VERSION 5.8 ;
BUSBITCHARS "[]" ;
DIVIDERCHAR "/" ;
UNITS
    DATABASE MICRONS 1000 ;
END UNITS

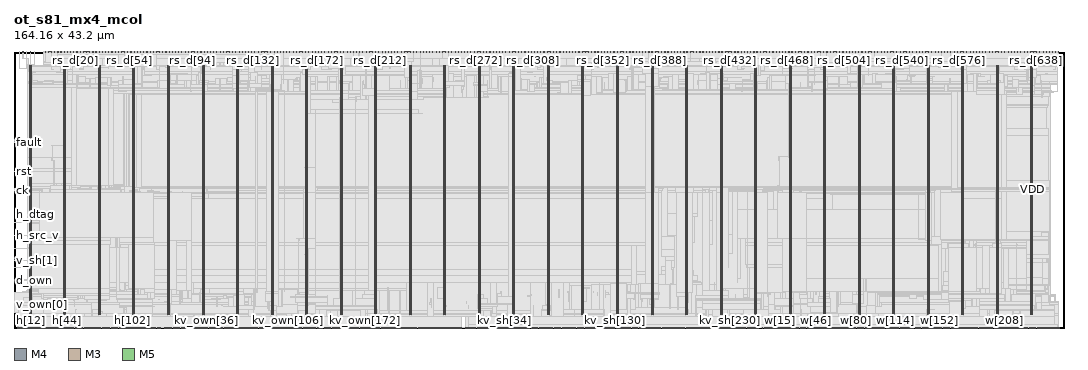
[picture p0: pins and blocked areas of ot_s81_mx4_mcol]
MACRO ot_s81_mx4_mcol
  FOREIGN ot_s81_mx4_mcol 0 0 ;
  CLASS BLOCK ;
  SIZE 164.16 BY 43.2 ;
  PIN ck
    DIRECTION INPUT ;
    USE SIGNAL ;
    PORT
      LAYER M4 ;
        RECT  0 21.504 0.084 21.528 ;
    END
  END ck
  PIN d_own
    DIRECTION INPUT ;
    USE SIGNAL ;
    PORT
      LAYER M4 ;
        RECT  0 7.488 0.084 7.512 ;
    END
  END d_own
  PIN fault
    DIRECTION OUTPUT ;
    USE SIGNAL ;
    PORT
      LAYER M4 ;
        RECT  0 28.992 0.084 29.016 ;
    END
  END fault
  PIN h[0]
    DIRECTION INPUT ;
    USE SIGNAL ;
    PORT
      LAYER M3 ;
        RECT  0.576 0 0.594 0.038 ;
    END
  END h[0]
  PIN h[100]
    DIRECTION INPUT ;
    USE SIGNAL ;
    PORT
      LAYER M3 ;
        RECT  18.144 0 18.162 0.038 ;
    END
  END h[100]
  PIN h[101]
    DIRECTION INPUT ;
    USE SIGNAL ;
    PORT
      LAYER M5 ;
        RECT  18.336 0 18.36 0.084 ;
    END
  END h[101]
  PIN h[102]
    DIRECTION INPUT ;
    USE SIGNAL ;
    PORT
      LAYER M3 ;
        RECT  18.504 0 18.522 0.038 ;
    END
  END h[102]
  PIN h[103]
    DIRECTION INPUT ;
    USE SIGNAL ;
    PORT
      LAYER M5 ;
        RECT  18.672 0 18.696 0.084 ;
    END
  END h[103]
  PIN h[104]
    DIRECTION INPUT ;
    USE SIGNAL ;
    PORT
      LAYER M3 ;
        RECT  18.864 0 18.882 0.038 ;
    END
  END h[104]
  PIN h[105]
    DIRECTION INPUT ;
    USE SIGNAL ;
    PORT
      LAYER M5 ;
        RECT  19.056 0 19.08 0.084 ;
    END
  END h[105]
  PIN h[106]
    DIRECTION INPUT ;
    USE SIGNAL ;
    PORT
      LAYER M3 ;
        RECT  19.224 0 19.242 0.038 ;
    END
  END h[106]
  PIN h[107]
    DIRECTION INPUT ;
    USE SIGNAL ;
    PORT
      LAYER M5 ;
        RECT  19.392 0 19.416 0.084 ;
    END
  END h[107]
  PIN h[108]
    DIRECTION INPUT ;
    USE SIGNAL ;
    PORT
      LAYER M3 ;
        RECT  19.548 0 19.566 0.038 ;
    END
  END h[108]
  PIN h[109]
    DIRECTION INPUT ;
    USE SIGNAL ;
    PORT
      LAYER M5 ;
        RECT  19.728 0 19.752 0.084 ;
    END
  END h[109]
  PIN h[10]
    DIRECTION INPUT ;
    USE SIGNAL ;
    PORT
      LAYER M3 ;
        RECT  2.34 0 2.358 0.038 ;
    END
  END h[10]
  PIN h[110]
    DIRECTION INPUT ;
    USE SIGNAL ;
    PORT
      LAYER M3 ;
        RECT  19.908 0 19.926 0.038 ;
    END
  END h[110]
  PIN h[111]
    DIRECTION INPUT ;
    USE SIGNAL ;
    PORT
      LAYER M5 ;
        RECT  20.112 0 20.136 0.084 ;
    END
  END h[111]
  PIN h[112]
    DIRECTION INPUT ;
    USE SIGNAL ;
    PORT
      LAYER M3 ;
        RECT  20.268 0 20.286 0.038 ;
    END
  END h[112]
  PIN h[113]
    DIRECTION INPUT ;
    USE SIGNAL ;
    PORT
      LAYER M5 ;
        RECT  20.448 0 20.472 0.084 ;
    END
  END h[113]
  PIN h[114]
    DIRECTION INPUT ;
    USE SIGNAL ;
    PORT
      LAYER M3 ;
        RECT  20.628 0 20.646 0.038 ;
    END
  END h[114]
  PIN h[115]
    DIRECTION INPUT ;
    USE SIGNAL ;
    PORT
      LAYER M5 ;
        RECT  20.784 0 20.808 0.084 ;
    END
  END h[115]
  PIN h[116]
    DIRECTION INPUT ;
    USE SIGNAL ;
    PORT
      LAYER M3 ;
        RECT  20.988 0 21.006 0.038 ;
    END
  END h[116]
  PIN h[117]
    DIRECTION INPUT ;
    USE SIGNAL ;
    PORT
      LAYER M5 ;
        RECT  21.12 0 21.144 0.084 ;
    END
  END h[117]
  PIN h[118]
    DIRECTION INPUT ;
    USE SIGNAL ;
    PORT
      LAYER M3 ;
        RECT  21.312 0 21.33 0.038 ;
    END
  END h[118]
  PIN h[119]
    DIRECTION INPUT ;
    USE SIGNAL ;
    PORT
      LAYER M5 ;
        RECT  21.504 0 21.528 0.084 ;
    END
  END h[119]
  PIN h[11]
    DIRECTION INPUT ;
    USE SIGNAL ;
    PORT
      LAYER M5 ;
        RECT  2.496 0 2.52 0.084 ;
    END
  END h[11]
  PIN h[120]
    DIRECTION INPUT ;
    USE SIGNAL ;
    PORT
      LAYER M3 ;
        RECT  21.672 0 21.69 0.038 ;
    END
  END h[120]
  PIN h[121]
    DIRECTION INPUT ;
    USE SIGNAL ;
    PORT
      LAYER M5 ;
        RECT  21.84 0 21.864 0.084 ;
    END
  END h[121]
  PIN h[122]
    DIRECTION INPUT ;
    USE SIGNAL ;
    PORT
      LAYER M3 ;
        RECT  22.032 0 22.05 0.038 ;
    END
  END h[122]
  PIN h[123]
    DIRECTION INPUT ;
    USE SIGNAL ;
    PORT
      LAYER M5 ;
        RECT  22.176 0 22.2 0.084 ;
    END
  END h[123]
  PIN h[124]
    DIRECTION INPUT ;
    USE SIGNAL ;
    PORT
      LAYER M3 ;
        RECT  22.392 0 22.41 0.038 ;
    END
  END h[124]
  PIN h[125]
    DIRECTION INPUT ;
    USE SIGNAL ;
    PORT
      LAYER M5 ;
        RECT  22.56 0 22.584 0.084 ;
    END
  END h[125]
  PIN h[126]
    DIRECTION INPUT ;
    USE SIGNAL ;
    PORT
      LAYER M3 ;
        RECT  22.716 0 22.734 0.038 ;
    END
  END h[126]
  PIN h[127]
    DIRECTION INPUT ;
    USE SIGNAL ;
    PORT
      LAYER M5 ;
        RECT  22.896 0 22.92 0.084 ;
    END
  END h[127]
  PIN h[12]
    DIRECTION INPUT ;
    USE SIGNAL ;
    PORT
      LAYER M3 ;
        RECT  2.7 0 2.718 0.038 ;
    END
  END h[12]
  PIN h[13]
    DIRECTION INPUT ;
    USE SIGNAL ;
    PORT
      LAYER M5 ;
        RECT  2.88 0 2.904 0.084 ;
    END
  END h[13]
  PIN h[14]
    DIRECTION INPUT ;
    USE SIGNAL ;
    PORT
      LAYER M3 ;
        RECT  3.024 0 3.042 0.038 ;
    END
  END h[14]
  PIN h[15]
    DIRECTION INPUT ;
    USE SIGNAL ;
    PORT
      LAYER M5 ;
        RECT  3.216 0 3.24 0.084 ;
    END
  END h[15]
  PIN h[16]
    DIRECTION INPUT ;
    USE SIGNAL ;
    PORT
      LAYER M3 ;
        RECT  3.384 0 3.402 0.038 ;
    END
  END h[16]
  PIN h[17]
    DIRECTION INPUT ;
    USE SIGNAL ;
    PORT
      LAYER M5 ;
        RECT  3.552 0 3.576 0.084 ;
    END
  END h[17]
  PIN h[18]
    DIRECTION INPUT ;
    USE SIGNAL ;
    PORT
      LAYER M3 ;
        RECT  3.744 0 3.762 0.038 ;
    END
  END h[18]
  PIN h[19]
    DIRECTION INPUT ;
    USE SIGNAL ;
    PORT
      LAYER M5 ;
        RECT  3.936 0 3.96 0.084 ;
    END
  END h[19]
  PIN h[1]
    DIRECTION INPUT ;
    USE SIGNAL ;
    PORT
      LAYER M5 ;
        RECT  0.768 0 0.792 0.084 ;
    END
  END h[1]
  PIN h[20]
    DIRECTION INPUT ;
    USE SIGNAL ;
    PORT
      LAYER M3 ;
        RECT  4.104 0 4.122 0.038 ;
    END
  END h[20]
  PIN h[21]
    DIRECTION INPUT ;
    USE SIGNAL ;
    PORT
      LAYER M5 ;
        RECT  4.272 0 4.296 0.084 ;
    END
  END h[21]
  PIN h[22]
    DIRECTION INPUT ;
    USE SIGNAL ;
    PORT
      LAYER M3 ;
        RECT  4.464 0 4.482 0.038 ;
    END
  END h[22]
  PIN h[23]
    DIRECTION INPUT ;
    USE SIGNAL ;
    PORT
      LAYER M5 ;
        RECT  4.608 0 4.632 0.084 ;
    END
  END h[23]
  PIN h[24]
    DIRECTION INPUT ;
    USE SIGNAL ;
    PORT
      LAYER M3 ;
        RECT  4.788 0 4.806 0.038 ;
    END
  END h[24]
  PIN h[25]
    DIRECTION INPUT ;
    USE SIGNAL ;
    PORT
      LAYER M5 ;
        RECT  4.992 0 5.016 0.084 ;
    END
  END h[25]
  PIN h[26]
    DIRECTION INPUT ;
    USE SIGNAL ;
    PORT
      LAYER M3 ;
        RECT  5.148 0 5.166 0.038 ;
    END
  END h[26]
  PIN h[27]
    DIRECTION INPUT ;
    USE SIGNAL ;
    PORT
      LAYER M5 ;
        RECT  5.328 0 5.352 0.084 ;
    END
  END h[27]
  PIN h[28]
    DIRECTION INPUT ;
    USE SIGNAL ;
    PORT
      LAYER M3 ;
        RECT  5.508 0 5.526 0.038 ;
    END
  END h[28]
  PIN h[29]
    DIRECTION INPUT ;
    USE SIGNAL ;
    PORT
      LAYER M5 ;
        RECT  5.664 0 5.688 0.084 ;
    END
  END h[29]
  PIN h[2]
    DIRECTION INPUT ;
    USE SIGNAL ;
    PORT
      LAYER M3 ;
        RECT  0.936 0 0.954 0.038 ;
    END
  END h[2]
  PIN h[30]
    DIRECTION INPUT ;
    USE SIGNAL ;
    PORT
      LAYER M3 ;
        RECT  5.868 0 5.886 0.038 ;
    END
  END h[30]
  PIN h[31]
    DIRECTION INPUT ;
    USE SIGNAL ;
    PORT
      LAYER M5 ;
        RECT  6.048 0 6.072 0.084 ;
    END
  END h[31]
  PIN h[32]
    DIRECTION INPUT ;
    USE SIGNAL ;
    PORT
      LAYER M3 ;
        RECT  6.192 0 6.21 0.038 ;
    END
  END h[32]
  PIN h[33]
    DIRECTION INPUT ;
    USE SIGNAL ;
    PORT
      LAYER M5 ;
        RECT  6.384 0 6.408 0.084 ;
    END
  END h[33]
  PIN h[34]
    DIRECTION INPUT ;
    USE SIGNAL ;
    PORT
      LAYER M3 ;
        RECT  6.552 0 6.57 0.038 ;
    END
  END h[34]
  PIN h[35]
    DIRECTION INPUT ;
    USE SIGNAL ;
    PORT
      LAYER M5 ;
        RECT  6.72 0 6.744 0.084 ;
    END
  END h[35]
  PIN h[36]
    DIRECTION INPUT ;
    USE SIGNAL ;
    PORT
      LAYER M3 ;
        RECT  6.912 0 6.93 0.038 ;
    END
  END h[36]
  PIN h[37]
    DIRECTION INPUT ;
    USE SIGNAL ;
    PORT
      LAYER M5 ;
        RECT  7.104 0 7.128 0.084 ;
    END
  END h[37]
  PIN h[38]
    DIRECTION INPUT ;
    USE SIGNAL ;
    PORT
      LAYER M3 ;
        RECT  7.272 0 7.29 0.038 ;
    END
  END h[38]
  PIN h[39]
    DIRECTION INPUT ;
    USE SIGNAL ;
    PORT
      LAYER M5 ;
        RECT  7.44 0 7.464 0.084 ;
    END
  END h[39]
  PIN h[3]
    DIRECTION INPUT ;
    USE SIGNAL ;
    PORT
      LAYER M5 ;
        RECT  1.104 0 1.128 0.084 ;
    END
  END h[3]
  PIN h[40]
    DIRECTION INPUT ;
    USE SIGNAL ;
    PORT
      LAYER M3 ;
        RECT  7.596 0 7.614 0.038 ;
    END
  END h[40]
  PIN h[41]
    DIRECTION INPUT ;
    USE SIGNAL ;
    PORT
      LAYER M5 ;
        RECT  7.776 0 7.8 0.084 ;
    END
  END h[41]
  PIN h[42]
    DIRECTION INPUT ;
    USE SIGNAL ;
    PORT
      LAYER M3 ;
        RECT  7.956 0 7.974 0.038 ;
    END
  END h[42]
  PIN h[43]
    DIRECTION INPUT ;
    USE SIGNAL ;
    PORT
      LAYER M5 ;
        RECT  8.112 0 8.136 0.084 ;
    END
  END h[43]
  PIN h[44]
    DIRECTION INPUT ;
    USE SIGNAL ;
    PORT
      LAYER M3 ;
        RECT  8.316 0 8.334 0.038 ;
    END
  END h[44]
  PIN h[45]
    DIRECTION INPUT ;
    USE SIGNAL ;
    PORT
      LAYER M5 ;
        RECT  8.496 0 8.52 0.084 ;
    END
  END h[45]
  PIN h[46]
    DIRECTION INPUT ;
    USE SIGNAL ;
    PORT
      LAYER M3 ;
        RECT  8.676 0 8.694 0.038 ;
    END
  END h[46]
  PIN h[47]
    DIRECTION INPUT ;
    USE SIGNAL ;
    PORT
      LAYER M5 ;
        RECT  8.832 0 8.856 0.084 ;
    END
  END h[47]
  PIN h[48]
    DIRECTION INPUT ;
    USE SIGNAL ;
    PORT
      LAYER M3 ;
        RECT  9 0 9.018 0.038 ;
    END
  END h[48]
  PIN h[49]
    DIRECTION INPUT ;
    USE SIGNAL ;
    PORT
      LAYER M5 ;
        RECT  9.168 0 9.192 0.084 ;
    END
  END h[49]
  PIN h[4]
    DIRECTION INPUT ;
    USE SIGNAL ;
    PORT
      LAYER M3 ;
        RECT  1.296 0 1.314 0.038 ;
    END
  END h[4]
  PIN h[50]
    DIRECTION INPUT ;
    USE SIGNAL ;
    PORT
      LAYER M3 ;
        RECT  9.36 0 9.378 0.038 ;
    END
  END h[50]
  PIN h[51]
    DIRECTION INPUT ;
    USE SIGNAL ;
    PORT
      LAYER M5 ;
        RECT  9.552 0 9.576 0.084 ;
    END
  END h[51]
  PIN h[52]
    DIRECTION INPUT ;
    USE SIGNAL ;
    PORT
      LAYER M3 ;
        RECT  9.72 0 9.738 0.038 ;
    END
  END h[52]
  PIN h[53]
    DIRECTION INPUT ;
    USE SIGNAL ;
    PORT
      LAYER M5 ;
        RECT  9.888 0 9.912 0.084 ;
    END
  END h[53]
  PIN h[54]
    DIRECTION INPUT ;
    USE SIGNAL ;
    PORT
      LAYER M3 ;
        RECT  10.08 0 10.098 0.038 ;
    END
  END h[54]
  PIN h[55]
    DIRECTION INPUT ;
    USE SIGNAL ;
    PORT
      LAYER M5 ;
        RECT  10.224 0 10.248 0.084 ;
    END
  END h[55]
  PIN h[56]
    DIRECTION INPUT ;
    USE SIGNAL ;
    PORT
      LAYER M3 ;
        RECT  10.44 0 10.458 0.038 ;
    END
  END h[56]
  PIN h[57]
    DIRECTION INPUT ;
    USE SIGNAL ;
    PORT
      LAYER M5 ;
        RECT  10.608 0 10.632 0.084 ;
    END
  END h[57]
  PIN h[58]
    DIRECTION INPUT ;
    USE SIGNAL ;
    PORT
      LAYER M3 ;
        RECT  10.764 0 10.782 0.038 ;
    END
  END h[58]
  PIN h[59]
    DIRECTION INPUT ;
    USE SIGNAL ;
    PORT
      LAYER M5 ;
        RECT  10.944 0 10.968 0.084 ;
    END
  END h[59]
  PIN h[5]
    DIRECTION INPUT ;
    USE SIGNAL ;
    PORT
      LAYER M5 ;
        RECT  1.44 0 1.464 0.084 ;
    END
  END h[5]
  PIN h[60]
    DIRECTION INPUT ;
    USE SIGNAL ;
    PORT
      LAYER M3 ;
        RECT  11.124 0 11.142 0.038 ;
    END
  END h[60]
  PIN h[61]
    DIRECTION INPUT ;
    USE SIGNAL ;
    PORT
      LAYER M5 ;
        RECT  11.28 0 11.304 0.084 ;
    END
  END h[61]
  PIN h[62]
    DIRECTION INPUT ;
    USE SIGNAL ;
    PORT
      LAYER M3 ;
        RECT  11.484 0 11.502 0.038 ;
    END
  END h[62]
  PIN h[63]
    DIRECTION INPUT ;
    USE SIGNAL ;
    PORT
      LAYER M5 ;
        RECT  11.664 0 11.688 0.084 ;
    END
  END h[63]
  PIN h[64]
    DIRECTION INPUT ;
    USE SIGNAL ;
    PORT
      LAYER M3 ;
        RECT  11.844 0 11.862 0.038 ;
    END
  END h[64]
  PIN h[65]
    DIRECTION INPUT ;
    USE SIGNAL ;
    PORT
      LAYER M5 ;
        RECT  12 0 12.024 0.084 ;
    END
  END h[65]
  PIN h[66]
    DIRECTION INPUT ;
    USE SIGNAL ;
    PORT
      LAYER M3 ;
        RECT  12.168 0 12.186 0.038 ;
    END
  END h[66]
  PIN h[67]
    DIRECTION INPUT ;
    USE SIGNAL ;
    PORT
      LAYER M5 ;
        RECT  12.336 0 12.36 0.084 ;
    END
  END h[67]
  PIN h[68]
    DIRECTION INPUT ;
    USE SIGNAL ;
    PORT
      LAYER M3 ;
        RECT  12.528 0 12.546 0.038 ;
    END
  END h[68]
  PIN h[69]
    DIRECTION INPUT ;
    USE SIGNAL ;
    PORT
      LAYER M5 ;
        RECT  12.72 0 12.744 0.084 ;
    END
  END h[69]
  PIN h[6]
    DIRECTION INPUT ;
    USE SIGNAL ;
    PORT
      LAYER M3 ;
        RECT  1.62 0 1.638 0.038 ;
    END
  END h[6]
  PIN h[70]
    DIRECTION INPUT ;
    USE SIGNAL ;
    PORT
      LAYER M3 ;
        RECT  12.888 0 12.906 0.038 ;
    END
  END h[70]
  PIN h[71]
    DIRECTION INPUT ;
    USE SIGNAL ;
    PORT
      LAYER M5 ;
        RECT  13.056 0 13.08 0.084 ;
    END
  END h[71]
  PIN h[72]
    DIRECTION INPUT ;
    USE SIGNAL ;
    PORT
      LAYER M3 ;
        RECT  13.248 0 13.266 0.038 ;
    END
  END h[72]
  PIN h[73]
    DIRECTION INPUT ;
    USE SIGNAL ;
    PORT
      LAYER M5 ;
        RECT  13.392 0 13.416 0.084 ;
    END
  END h[73]
  PIN h[74]
    DIRECTION INPUT ;
    USE SIGNAL ;
    PORT
      LAYER M3 ;
        RECT  13.572 0 13.59 0.038 ;
    END
  END h[74]
  PIN h[75]
    DIRECTION INPUT ;
    USE SIGNAL ;
    PORT
      LAYER M5 ;
        RECT  13.776 0 13.8 0.084 ;
    END
  END h[75]
  PIN h[76]
    DIRECTION INPUT ;
    USE SIGNAL ;
    PORT
      LAYER M3 ;
        RECT  13.932 0 13.95 0.038 ;
    END
  END h[76]
  PIN h[77]
    DIRECTION INPUT ;
    USE SIGNAL ;
    PORT
      LAYER M5 ;
        RECT  14.112 0 14.136 0.084 ;
    END
  END h[77]
  PIN h[78]
    DIRECTION INPUT ;
    USE SIGNAL ;
    PORT
      LAYER M3 ;
        RECT  14.292 0 14.31 0.038 ;
    END
  END h[78]
  PIN h[79]
    DIRECTION INPUT ;
    USE SIGNAL ;
    PORT
      LAYER M5 ;
        RECT  14.448 0 14.472 0.084 ;
    END
  END h[79]
  PIN h[7]
    DIRECTION INPUT ;
    USE SIGNAL ;
    PORT
      LAYER M5 ;
        RECT  1.824 0 1.848 0.084 ;
    END
  END h[7]
  PIN h[80]
    DIRECTION INPUT ;
    USE SIGNAL ;
    PORT
      LAYER M3 ;
        RECT  14.652 0 14.67 0.038 ;
    END
  END h[80]
  PIN h[81]
    DIRECTION INPUT ;
    USE SIGNAL ;
    PORT
      LAYER M5 ;
        RECT  14.832 0 14.856 0.084 ;
    END
  END h[81]
  PIN h[82]
    DIRECTION INPUT ;
    USE SIGNAL ;
    PORT
      LAYER M3 ;
        RECT  14.976 0 14.994 0.038 ;
    END
  END h[82]
  PIN h[83]
    DIRECTION INPUT ;
    USE SIGNAL ;
    PORT
      LAYER M5 ;
        RECT  15.168 0 15.192 0.084 ;
    END
  END h[83]
  PIN h[84]
    DIRECTION INPUT ;
    USE SIGNAL ;
    PORT
      LAYER M3 ;
        RECT  15.336 0 15.354 0.038 ;
    END
  END h[84]
  PIN h[85]
    DIRECTION INPUT ;
    USE SIGNAL ;
    PORT
      LAYER M5 ;
        RECT  15.504 0 15.528 0.084 ;
    END
  END h[85]
  PIN h[86]
    DIRECTION INPUT ;
    USE SIGNAL ;
    PORT
      LAYER M3 ;
        RECT  15.696 0 15.714 0.038 ;
    END
  END h[86]
  PIN h[87]
    DIRECTION INPUT ;
    USE SIGNAL ;
    PORT
      LAYER M5 ;
        RECT  15.888 0 15.912 0.084 ;
    END
  END h[87]
  PIN h[88]
    DIRECTION INPUT ;
    USE SIGNAL ;
    PORT
      LAYER M3 ;
        RECT  16.056 0 16.074 0.038 ;
    END
  END h[88]
  PIN h[89]
    DIRECTION INPUT ;
    USE SIGNAL ;
    PORT
      LAYER M5 ;
        RECT  16.224 0 16.248 0.084 ;
    END
  END h[89]
  PIN h[8]
    DIRECTION INPUT ;
    USE SIGNAL ;
    PORT
      LAYER M3 ;
        RECT  1.98 0 1.998 0.038 ;
    END
  END h[8]
  PIN h[90]
    DIRECTION INPUT ;
    USE SIGNAL ;
    PORT
      LAYER M3 ;
        RECT  16.416 0 16.434 0.038 ;
    END
  END h[90]
  PIN h[91]
    DIRECTION INPUT ;
    USE SIGNAL ;
    PORT
      LAYER M5 ;
        RECT  16.56 0 16.584 0.084 ;
    END
  END h[91]
  PIN h[92]
    DIRECTION INPUT ;
    USE SIGNAL ;
    PORT
      LAYER M3 ;
        RECT  16.74 0 16.758 0.038 ;
    END
  END h[92]
  PIN h[93]
    DIRECTION INPUT ;
    USE SIGNAL ;
    PORT
      LAYER M5 ;
        RECT  16.944 0 16.968 0.084 ;
    END
  END h[93]
  PIN h[94]
    DIRECTION INPUT ;
    USE SIGNAL ;
    PORT
      LAYER M3 ;
        RECT  17.1 0 17.118 0.038 ;
    END
  END h[94]
  PIN h[95]
    DIRECTION INPUT ;
    USE SIGNAL ;
    PORT
      LAYER M5 ;
        RECT  17.28 0 17.304 0.084 ;
    END
  END h[95]
  PIN h[96]
    DIRECTION INPUT ;
    USE SIGNAL ;
    PORT
      LAYER M3 ;
        RECT  17.46 0 17.478 0.038 ;
    END
  END h[96]
  PIN h[97]
    DIRECTION INPUT ;
    USE SIGNAL ;
    PORT
      LAYER M5 ;
        RECT  17.616 0 17.64 0.084 ;
    END
  END h[97]
  PIN h[98]
    DIRECTION INPUT ;
    USE SIGNAL ;
    PORT
      LAYER M3 ;
        RECT  17.82 0 17.838 0.038 ;
    END
  END h[98]
  PIN h[99]
    DIRECTION INPUT ;
    USE SIGNAL ;
    PORT
      LAYER M5 ;
        RECT  18 0 18.024 0.084 ;
    END
  END h[99]
  PIN h[9]
    DIRECTION INPUT ;
    USE SIGNAL ;
    PORT
      LAYER M5 ;
        RECT  2.16 0 2.184 0.084 ;
    END
  END h[9]
  PIN h_dtag
    DIRECTION INPUT ;
    USE SIGNAL ;
    PORT
      LAYER M4 ;
        RECT  0 16.512 0.084 16.536 ;
    END
  END h_dtag
  PIN h_src_v
    DIRECTION INPUT ;
    USE SIGNAL ;
    PORT
      LAYER M4 ;
        RECT  0 14.496 0.084 14.52 ;
    END
  END h_src_v
  PIN kv_own[0]
    DIRECTION INPUT ;
    USE SIGNAL ;
    PORT
      LAYER M3 ;
        RECT  23.58 0 23.598 0.038 ;
    END
  END kv_own[0]
  PIN kv_own[100]
    DIRECTION INPUT ;
    USE SIGNAL ;
    PORT
      LAYER M3 ;
        RECT  41.76 0 41.778 0.038 ;
    END
  END kv_own[100]
  PIN kv_own[101]
    DIRECTION INPUT ;
    USE SIGNAL ;
    PORT
      LAYER M5 ;
        RECT  41.904 0 41.928 0.084 ;
    END
  END kv_own[101]
  PIN kv_own[102]
    DIRECTION INPUT ;
    USE SIGNAL ;
    PORT
      LAYER M3 ;
        RECT  42.12 0 42.138 0.038 ;
    END
  END kv_own[102]
  PIN kv_own[103]
    DIRECTION INPUT ;
    USE SIGNAL ;
    PORT
      LAYER M5 ;
        RECT  42.288 0 42.312 0.084 ;
    END
  END kv_own[103]
  PIN kv_own[104]
    DIRECTION INPUT ;
    USE SIGNAL ;
    PORT
      LAYER M3 ;
        RECT  42.48 0 42.498 0.038 ;
    END
  END kv_own[104]
  PIN kv_own[105]
    DIRECTION INPUT ;
    USE SIGNAL ;
    PORT
      LAYER M5 ;
        RECT  42.672 0 42.696 0.084 ;
    END
  END kv_own[105]
  PIN kv_own[106]
    DIRECTION INPUT ;
    USE SIGNAL ;
    PORT
      LAYER M3 ;
        RECT  42.84 0 42.858 0.038 ;
    END
  END kv_own[106]
  PIN kv_own[107]
    DIRECTION INPUT ;
    USE SIGNAL ;
    PORT
      LAYER M5 ;
        RECT  43.008 0 43.032 0.084 ;
    END
  END kv_own[107]
  PIN kv_own[108]
    DIRECTION INPUT ;
    USE SIGNAL ;
    PORT
      LAYER M3 ;
        RECT  43.2 0 43.218 0.038 ;
    END
  END kv_own[108]
  PIN kv_own[109]
    DIRECTION INPUT ;
    USE SIGNAL ;
    PORT
      LAYER M5 ;
        RECT  43.392 0 43.416 0.084 ;
    END
  END kv_own[109]
  PIN kv_own[10]
    DIRECTION INPUT ;
    USE SIGNAL ;
    PORT
      LAYER M3 ;
        RECT  25.416 0 25.434 0.038 ;
    END
  END kv_own[10]
  PIN kv_own[110]
    DIRECTION INPUT ;
    USE SIGNAL ;
    PORT
      LAYER M3 ;
        RECT  43.56 0 43.578 0.038 ;
    END
  END kv_own[110]
  PIN kv_own[111]
    DIRECTION INPUT ;
    USE SIGNAL ;
    PORT
      LAYER M5 ;
        RECT  43.728 0 43.752 0.084 ;
    END
  END kv_own[111]
  PIN kv_own[112]
    DIRECTION INPUT ;
    USE SIGNAL ;
    PORT
      LAYER M3 ;
        RECT  43.92 0 43.938 0.038 ;
    END
  END kv_own[112]
  PIN kv_own[113]
    DIRECTION INPUT ;
    USE SIGNAL ;
    PORT
      LAYER M5 ;
        RECT  44.112 0 44.136 0.084 ;
    END
  END kv_own[113]
  PIN kv_own[114]
    DIRECTION INPUT ;
    USE SIGNAL ;
    PORT
      LAYER M3 ;
        RECT  44.28 0 44.298 0.038 ;
    END
  END kv_own[114]
  PIN kv_own[115]
    DIRECTION INPUT ;
    USE SIGNAL ;
    PORT
      LAYER M5 ;
        RECT  44.448 0 44.472 0.084 ;
    END
  END kv_own[115]
  PIN kv_own[116]
    DIRECTION INPUT ;
    USE SIGNAL ;
    PORT
      LAYER M3 ;
        RECT  44.64 0 44.658 0.038 ;
    END
  END kv_own[116]
  PIN kv_own[117]
    DIRECTION INPUT ;
    USE SIGNAL ;
    PORT
      LAYER M5 ;
        RECT  44.832 0 44.856 0.084 ;
    END
  END kv_own[117]
  PIN kv_own[118]
    DIRECTION INPUT ;
    USE SIGNAL ;
    PORT
      LAYER M3 ;
        RECT  45 0 45.018 0.038 ;
    END
  END kv_own[118]
  PIN kv_own[119]
    DIRECTION INPUT ;
    USE SIGNAL ;
    PORT
      LAYER M5 ;
        RECT  45.216 0 45.24 0.084 ;
    END
  END kv_own[119]
  PIN kv_own[11]
    DIRECTION INPUT ;
    USE SIGNAL ;
    PORT
      LAYER M5 ;
        RECT  25.584 0 25.608 0.084 ;
    END
  END kv_own[11]
  PIN kv_own[120]
    DIRECTION INPUT ;
    USE SIGNAL ;
    PORT
      LAYER M3 ;
        RECT  45.396 0 45.414 0.038 ;
    END
  END kv_own[120]
  PIN kv_own[121]
    DIRECTION INPUT ;
    USE SIGNAL ;
    PORT
      LAYER M5 ;
        RECT  45.552 0 45.576 0.084 ;
    END
  END kv_own[121]
  PIN kv_own[122]
    DIRECTION INPUT ;
    USE SIGNAL ;
    PORT
      LAYER M3 ;
        RECT  45.756 0 45.774 0.038 ;
    END
  END kv_own[122]
  PIN kv_own[123]
    DIRECTION INPUT ;
    USE SIGNAL ;
    PORT
      LAYER M5 ;
        RECT  45.936 0 45.96 0.084 ;
    END
  END kv_own[123]
  PIN kv_own[124]
    DIRECTION INPUT ;
    USE SIGNAL ;
    PORT
      LAYER M3 ;
        RECT  46.116 0 46.134 0.038 ;
    END
  END kv_own[124]
  PIN kv_own[125]
    DIRECTION INPUT ;
    USE SIGNAL ;
    PORT
      LAYER M5 ;
        RECT  46.272 0 46.296 0.084 ;
    END
  END kv_own[125]
  PIN kv_own[126]
    DIRECTION INPUT ;
    USE SIGNAL ;
    PORT
      LAYER M3 ;
        RECT  46.476 0 46.494 0.038 ;
    END
  END kv_own[126]
  PIN kv_own[127]
    DIRECTION INPUT ;
    USE SIGNAL ;
    PORT
      LAYER M5 ;
        RECT  46.656 0 46.68 0.084 ;
    END
  END kv_own[127]
  PIN kv_own[128]
    DIRECTION INPUT ;
    USE SIGNAL ;
    PORT
      LAYER M3 ;
        RECT  46.836 0 46.854 0.038 ;
    END
  END kv_own[128]
  PIN kv_own[129]
    DIRECTION INPUT ;
    USE SIGNAL ;
    PORT
      LAYER M5 ;
        RECT  46.992 0 47.016 0.084 ;
    END
  END kv_own[129]
  PIN kv_own[12]
    DIRECTION INPUT ;
    USE SIGNAL ;
    PORT
      LAYER M3 ;
        RECT  25.776 0 25.794 0.038 ;
    END
  END kv_own[12]
  PIN kv_own[130]
    DIRECTION INPUT ;
    USE SIGNAL ;
    PORT
      LAYER M3 ;
        RECT  47.196 0 47.214 0.038 ;
    END
  END kv_own[130]
  PIN kv_own[131]
    DIRECTION INPUT ;
    USE SIGNAL ;
    PORT
      LAYER M5 ;
        RECT  47.376 0 47.4 0.084 ;
    END
  END kv_own[131]
  PIN kv_own[132]
    DIRECTION INPUT ;
    USE SIGNAL ;
    PORT
      LAYER M3 ;
        RECT  47.556 0 47.574 0.038 ;
    END
  END kv_own[132]
  PIN kv_own[133]
    DIRECTION INPUT ;
    USE SIGNAL ;
    PORT
      LAYER M5 ;
        RECT  47.76 0 47.784 0.084 ;
    END
  END kv_own[133]
  PIN kv_own[134]
    DIRECTION INPUT ;
    USE SIGNAL ;
    PORT
      LAYER M3 ;
        RECT  47.916 0 47.934 0.038 ;
    END
  END kv_own[134]
  PIN kv_own[135]
    DIRECTION INPUT ;
    USE SIGNAL ;
    PORT
      LAYER M5 ;
        RECT  48.096 0 48.12 0.084 ;
    END
  END kv_own[135]
  PIN kv_own[136]
    DIRECTION INPUT ;
    USE SIGNAL ;
    PORT
      LAYER M3 ;
        RECT  48.276 0 48.294 0.038 ;
    END
  END kv_own[136]
  PIN kv_own[137]
    DIRECTION INPUT ;
    USE SIGNAL ;
    PORT
      LAYER M5 ;
        RECT  48.48 0 48.504 0.084 ;
    END
  END kv_own[137]
  PIN kv_own[138]
    DIRECTION INPUT ;
    USE SIGNAL ;
    PORT
      LAYER M3 ;
        RECT  48.636 0 48.654 0.038 ;
    END
  END kv_own[138]
  PIN kv_own[139]
    DIRECTION INPUT ;
    USE SIGNAL ;
    PORT
      LAYER M5 ;
        RECT  48.816 0 48.84 0.084 ;
    END
  END kv_own[139]
  PIN kv_own[13]
    DIRECTION INPUT ;
    USE SIGNAL ;
    PORT
      LAYER M5 ;
        RECT  25.92 0 25.944 0.084 ;
    END
  END kv_own[13]
  PIN kv_own[140]
    DIRECTION INPUT ;
    USE SIGNAL ;
    PORT
      LAYER M3 ;
        RECT  48.996 0 49.014 0.038 ;
    END
  END kv_own[140]
  PIN kv_own[141]
    DIRECTION INPUT ;
    USE SIGNAL ;
    PORT
      LAYER M5 ;
        RECT  49.2 0 49.224 0.084 ;
    END
  END kv_own[141]
  PIN kv_own[142]
    DIRECTION INPUT ;
    USE SIGNAL ;
    PORT
      LAYER M3 ;
        RECT  49.392 0 49.41 0.038 ;
    END
  END kv_own[142]
  PIN kv_own[143]
    DIRECTION INPUT ;
    USE SIGNAL ;
    PORT
      LAYER M5 ;
        RECT  49.536 0 49.56 0.084 ;
    END
  END kv_own[143]
  PIN kv_own[144]
    DIRECTION INPUT ;
    USE SIGNAL ;
    PORT
      LAYER M3 ;
        RECT  49.752 0 49.77 0.038 ;
    END
  END kv_own[144]
  PIN kv_own[145]
    DIRECTION INPUT ;
    USE SIGNAL ;
    PORT
      LAYER M5 ;
        RECT  49.92 0 49.944 0.084 ;
    END
  END kv_own[145]
  PIN kv_own[146]
    DIRECTION INPUT ;
    USE SIGNAL ;
    PORT
      LAYER M3 ;
        RECT  50.112 0 50.13 0.038 ;
    END
  END kv_own[146]
  PIN kv_own[147]
    DIRECTION INPUT ;
    USE SIGNAL ;
    PORT
      LAYER M5 ;
        RECT  50.304 0 50.328 0.084 ;
    END
  END kv_own[147]
  PIN kv_own[148]
    DIRECTION INPUT ;
    USE SIGNAL ;
    PORT
      LAYER M3 ;
        RECT  50.472 0 50.49 0.038 ;
    END
  END kv_own[148]
  PIN kv_own[149]
    DIRECTION INPUT ;
    USE SIGNAL ;
    PORT
      LAYER M5 ;
        RECT  50.64 0 50.664 0.084 ;
    END
  END kv_own[149]
  PIN kv_own[14]
    DIRECTION INPUT ;
    USE SIGNAL ;
    PORT
      LAYER M3 ;
        RECT  26.136 0 26.154 0.038 ;
    END
  END kv_own[14]
  PIN kv_own[150]
    DIRECTION INPUT ;
    USE SIGNAL ;
    PORT
      LAYER M3 ;
        RECT  50.832 0 50.85 0.038 ;
    END
  END kv_own[150]
  PIN kv_own[151]
    DIRECTION INPUT ;
    USE SIGNAL ;
    PORT
      LAYER M5 ;
        RECT  51.024 0 51.048 0.084 ;
    END
  END kv_own[151]
  PIN kv_own[152]
    DIRECTION INPUT ;
    USE SIGNAL ;
    PORT
      LAYER M3 ;
        RECT  51.192 0 51.21 0.038 ;
    END
  END kv_own[152]
  PIN kv_own[153]
    DIRECTION INPUT ;
    USE SIGNAL ;
    PORT
      LAYER M5 ;
        RECT  51.36 0 51.384 0.084 ;
    END
  END kv_own[153]
  PIN kv_own[154]
    DIRECTION INPUT ;
    USE SIGNAL ;
    PORT
      LAYER M3 ;
        RECT  51.552 0 51.57 0.038 ;
    END
  END kv_own[154]
  PIN kv_own[155]
    DIRECTION INPUT ;
    USE SIGNAL ;
    PORT
      LAYER M5 ;
        RECT  51.744 0 51.768 0.084 ;
    END
  END kv_own[155]
  PIN kv_own[156]
    DIRECTION INPUT ;
    USE SIGNAL ;
    PORT
      LAYER M3 ;
        RECT  51.912 0 51.93 0.038 ;
    END
  END kv_own[156]
  PIN kv_own[157]
    DIRECTION INPUT ;
    USE SIGNAL ;
    PORT
      LAYER M5 ;
        RECT  52.08 0 52.104 0.084 ;
    END
  END kv_own[157]
  PIN kv_own[158]
    DIRECTION INPUT ;
    USE SIGNAL ;
    PORT
      LAYER M3 ;
        RECT  52.272 0 52.29 0.038 ;
    END
  END kv_own[158]
  PIN kv_own[159]
    DIRECTION INPUT ;
    USE SIGNAL ;
    PORT
      LAYER M5 ;
        RECT  52.464 0 52.488 0.084 ;
    END
  END kv_own[159]
  PIN kv_own[15]
    DIRECTION INPUT ;
    USE SIGNAL ;
    PORT
      LAYER M5 ;
        RECT  26.304 0 26.328 0.084 ;
    END
  END kv_own[15]
  PIN kv_own[160]
    DIRECTION INPUT ;
    USE SIGNAL ;
    PORT
      LAYER M3 ;
        RECT  52.632 0 52.65 0.038 ;
    END
  END kv_own[160]
  PIN kv_own[161]
    DIRECTION INPUT ;
    USE SIGNAL ;
    PORT
      LAYER M5 ;
        RECT  52.8 0 52.824 0.084 ;
    END
  END kv_own[161]
  PIN kv_own[162]
    DIRECTION INPUT ;
    USE SIGNAL ;
    PORT
      LAYER M3 ;
        RECT  52.992 0 53.01 0.038 ;
    END
  END kv_own[162]
  PIN kv_own[163]
    DIRECTION INPUT ;
    USE SIGNAL ;
    PORT
      LAYER M5 ;
        RECT  53.184 0 53.208 0.084 ;
    END
  END kv_own[163]
  PIN kv_own[164]
    DIRECTION INPUT ;
    USE SIGNAL ;
    PORT
      LAYER M3 ;
        RECT  53.388 0 53.406 0.038 ;
    END
  END kv_own[164]
  PIN kv_own[165]
    DIRECTION INPUT ;
    USE SIGNAL ;
    PORT
      LAYER M5 ;
        RECT  53.568 0 53.592 0.084 ;
    END
  END kv_own[165]
  PIN kv_own[166]
    DIRECTION INPUT ;
    USE SIGNAL ;
    PORT
      LAYER M3 ;
        RECT  53.748 0 53.766 0.038 ;
    END
  END kv_own[166]
  PIN kv_own[167]
    DIRECTION INPUT ;
    USE SIGNAL ;
    PORT
      LAYER M5 ;
        RECT  53.904 0 53.928 0.084 ;
    END
  END kv_own[167]
  PIN kv_own[168]
    DIRECTION INPUT ;
    USE SIGNAL ;
    PORT
      LAYER M3 ;
        RECT  54.108 0 54.126 0.038 ;
    END
  END kv_own[168]
  PIN kv_own[169]
    DIRECTION INPUT ;
    USE SIGNAL ;
    PORT
      LAYER M5 ;
        RECT  54.288 0 54.312 0.084 ;
    END
  END kv_own[169]
  PIN kv_own[16]
    DIRECTION INPUT ;
    USE SIGNAL ;
    PORT
      LAYER M3 ;
        RECT  26.496 0 26.514 0.038 ;
    END
  END kv_own[16]
  PIN kv_own[170]
    DIRECTION INPUT ;
    USE SIGNAL ;
    PORT
      LAYER M3 ;
        RECT  54.468 0 54.486 0.038 ;
    END
  END kv_own[170]
  PIN kv_own[171]
    DIRECTION INPUT ;
    USE SIGNAL ;
    PORT
      LAYER M5 ;
        RECT  54.624 0 54.648 0.084 ;
    END
  END kv_own[171]
  PIN kv_own[172]
    DIRECTION INPUT ;
    USE SIGNAL ;
    PORT
      LAYER M3 ;
        RECT  54.828 0 54.846 0.038 ;
    END
  END kv_own[172]
  PIN kv_own[173]
    DIRECTION INPUT ;
    USE SIGNAL ;
    PORT
      LAYER M5 ;
        RECT  55.008 0 55.032 0.084 ;
    END
  END kv_own[173]
  PIN kv_own[174]
    DIRECTION INPUT ;
    USE SIGNAL ;
    PORT
      LAYER M3 ;
        RECT  55.188 0 55.206 0.038 ;
    END
  END kv_own[174]
  PIN kv_own[175]
    DIRECTION INPUT ;
    USE SIGNAL ;
    PORT
      LAYER M5 ;
        RECT  55.344 0 55.368 0.084 ;
    END
  END kv_own[175]
  PIN kv_own[176]
    DIRECTION INPUT ;
    USE SIGNAL ;
    PORT
      LAYER M3 ;
        RECT  55.548 0 55.566 0.038 ;
    END
  END kv_own[176]
  PIN kv_own[177]
    DIRECTION INPUT ;
    USE SIGNAL ;
    PORT
      LAYER M5 ;
        RECT  55.728 0 55.752 0.084 ;
    END
  END kv_own[177]
  PIN kv_own[178]
    DIRECTION INPUT ;
    USE SIGNAL ;
    PORT
      LAYER M3 ;
        RECT  55.908 0 55.926 0.038 ;
    END
  END kv_own[178]
  PIN kv_own[179]
    DIRECTION INPUT ;
    USE SIGNAL ;
    PORT
      LAYER M5 ;
        RECT  56.112 0 56.136 0.084 ;
    END
  END kv_own[179]
  PIN kv_own[17]
    DIRECTION INPUT ;
    USE SIGNAL ;
    PORT
      LAYER M5 ;
        RECT  26.688 0 26.712 0.084 ;
    END
  END kv_own[17]
  PIN kv_own[180]
    DIRECTION INPUT ;
    USE SIGNAL ;
    PORT
      LAYER M3 ;
        RECT  56.268 0 56.286 0.038 ;
    END
  END kv_own[180]
  PIN kv_own[181]
    DIRECTION INPUT ;
    USE SIGNAL ;
    PORT
      LAYER M5 ;
        RECT  56.448 0 56.472 0.084 ;
    END
  END kv_own[181]
  PIN kv_own[182]
    DIRECTION INPUT ;
    USE SIGNAL ;
    PORT
      LAYER M3 ;
        RECT  56.628 0 56.646 0.038 ;
    END
  END kv_own[182]
  PIN kv_own[183]
    DIRECTION INPUT ;
    USE SIGNAL ;
    PORT
      LAYER M5 ;
        RECT  56.832 0 56.856 0.084 ;
    END
  END kv_own[183]
  PIN kv_own[184]
    DIRECTION INPUT ;
    USE SIGNAL ;
    PORT
      LAYER M3 ;
        RECT  56.988 0 57.006 0.038 ;
    END
  END kv_own[184]
  PIN kv_own[185]
    DIRECTION INPUT ;
    USE SIGNAL ;
    PORT
      LAYER M5 ;
        RECT  57.168 0 57.192 0.084 ;
    END
  END kv_own[185]
  PIN kv_own[186]
    DIRECTION INPUT ;
    USE SIGNAL ;
    PORT
      LAYER M3 ;
        RECT  57.384 0 57.402 0.038 ;
    END
  END kv_own[186]
  PIN kv_own[187]
    DIRECTION INPUT ;
    USE SIGNAL ;
    PORT
      LAYER M5 ;
        RECT  57.552 0 57.576 0.084 ;
    END
  END kv_own[187]
  PIN kv_own[188]
    DIRECTION INPUT ;
    USE SIGNAL ;
    PORT
      LAYER M3 ;
        RECT  57.744 0 57.762 0.038 ;
    END
  END kv_own[188]
  PIN kv_own[189]
    DIRECTION INPUT ;
    USE SIGNAL ;
    PORT
      LAYER M5 ;
        RECT  57.888 0 57.912 0.084 ;
    END
  END kv_own[189]
  PIN kv_own[18]
    DIRECTION INPUT ;
    USE SIGNAL ;
    PORT
      LAYER M3 ;
        RECT  26.856 0 26.874 0.038 ;
    END
  END kv_own[18]
  PIN kv_own[190]
    DIRECTION INPUT ;
    USE SIGNAL ;
    PORT
      LAYER M3 ;
        RECT  58.104 0 58.122 0.038 ;
    END
  END kv_own[190]
  PIN kv_own[191]
    DIRECTION INPUT ;
    USE SIGNAL ;
    PORT
      LAYER M5 ;
        RECT  58.272 0 58.296 0.084 ;
    END
  END kv_own[191]
  PIN kv_own[192]
    DIRECTION INPUT ;
    USE SIGNAL ;
    PORT
      LAYER M3 ;
        RECT  58.464 0 58.482 0.038 ;
    END
  END kv_own[192]
  PIN kv_own[193]
    DIRECTION INPUT ;
    USE SIGNAL ;
    PORT
      LAYER M5 ;
        RECT  58.656 0 58.68 0.084 ;
    END
  END kv_own[193]
  PIN kv_own[194]
    DIRECTION INPUT ;
    USE SIGNAL ;
    PORT
      LAYER M3 ;
        RECT  58.824 0 58.842 0.038 ;
    END
  END kv_own[194]
  PIN kv_own[195]
    DIRECTION INPUT ;
    USE SIGNAL ;
    PORT
      LAYER M5 ;
        RECT  58.992 0 59.016 0.084 ;
    END
  END kv_own[195]
  PIN kv_own[196]
    DIRECTION INPUT ;
    USE SIGNAL ;
    PORT
      LAYER M3 ;
        RECT  59.184 0 59.202 0.038 ;
    END
  END kv_own[196]
  PIN kv_own[197]
    DIRECTION INPUT ;
    USE SIGNAL ;
    PORT
      LAYER M5 ;
        RECT  59.376 0 59.4 0.084 ;
    END
  END kv_own[197]
  PIN kv_own[198]
    DIRECTION INPUT ;
    USE SIGNAL ;
    PORT
      LAYER M3 ;
        RECT  59.544 0 59.562 0.038 ;
    END
  END kv_own[198]
  PIN kv_own[199]
    DIRECTION INPUT ;
    USE SIGNAL ;
    PORT
      LAYER M5 ;
        RECT  59.712 0 59.736 0.084 ;
    END
  END kv_own[199]
  PIN kv_own[19]
    DIRECTION INPUT ;
    USE SIGNAL ;
    PORT
      LAYER M5 ;
        RECT  27.024 0 27.048 0.084 ;
    END
  END kv_own[19]
  PIN kv_own[1]
    DIRECTION INPUT ;
    USE SIGNAL ;
    PORT
      LAYER M5 ;
        RECT  23.76 0 23.784 0.084 ;
    END
  END kv_own[1]
  PIN kv_own[200]
    DIRECTION INPUT ;
    USE SIGNAL ;
    PORT
      LAYER M3 ;
        RECT  59.904 0 59.922 0.038 ;
    END
  END kv_own[200]
  PIN kv_own[201]
    DIRECTION INPUT ;
    USE SIGNAL ;
    PORT
      LAYER M5 ;
        RECT  60.096 0 60.12 0.084 ;
    END
  END kv_own[201]
  PIN kv_own[202]
    DIRECTION INPUT ;
    USE SIGNAL ;
    PORT
      LAYER M3 ;
        RECT  60.264 0 60.282 0.038 ;
    END
  END kv_own[202]
  PIN kv_own[203]
    DIRECTION INPUT ;
    USE SIGNAL ;
    PORT
      LAYER M5 ;
        RECT  60.432 0 60.456 0.084 ;
    END
  END kv_own[203]
  PIN kv_own[204]
    DIRECTION INPUT ;
    USE SIGNAL ;
    PORT
      LAYER M3 ;
        RECT  60.624 0 60.642 0.038 ;
    END
  END kv_own[204]
  PIN kv_own[205]
    DIRECTION INPUT ;
    USE SIGNAL ;
    PORT
      LAYER M5 ;
        RECT  60.816 0 60.84 0.084 ;
    END
  END kv_own[205]
  PIN kv_own[206]
    DIRECTION INPUT ;
    USE SIGNAL ;
    PORT
      LAYER M3 ;
        RECT  60.984 0 61.002 0.038 ;
    END
  END kv_own[206]
  PIN kv_own[207]
    DIRECTION INPUT ;
    USE SIGNAL ;
    PORT
      LAYER M5 ;
        RECT  61.2 0 61.224 0.084 ;
    END
  END kv_own[207]
  PIN kv_own[208]
    DIRECTION INPUT ;
    USE SIGNAL ;
    PORT
      LAYER M3 ;
        RECT  61.38 0 61.398 0.038 ;
    END
  END kv_own[208]
  PIN kv_own[209]
    DIRECTION INPUT ;
    USE SIGNAL ;
    PORT
      LAYER M5 ;
        RECT  61.536 0 61.56 0.084 ;
    END
  END kv_own[209]
  PIN kv_own[20]
    DIRECTION INPUT ;
    USE SIGNAL ;
    PORT
      LAYER M3 ;
        RECT  27.216 0 27.234 0.038 ;
    END
  END kv_own[20]
  PIN kv_own[210]
    DIRECTION INPUT ;
    USE SIGNAL ;
    PORT
      LAYER M3 ;
        RECT  61.74 0 61.758 0.038 ;
    END
  END kv_own[210]
  PIN kv_own[211]
    DIRECTION INPUT ;
    USE SIGNAL ;
    PORT
      LAYER M5 ;
        RECT  61.92 0 61.944 0.084 ;
    END
  END kv_own[211]
  PIN kv_own[212]
    DIRECTION INPUT ;
    USE SIGNAL ;
    PORT
      LAYER M3 ;
        RECT  62.1 0 62.118 0.038 ;
    END
  END kv_own[212]
  PIN kv_own[213]
    DIRECTION INPUT ;
    USE SIGNAL ;
    PORT
      LAYER M5 ;
        RECT  62.256 0 62.28 0.084 ;
    END
  END kv_own[213]
  PIN kv_own[214]
    DIRECTION INPUT ;
    USE SIGNAL ;
    PORT
      LAYER M3 ;
        RECT  62.46 0 62.478 0.038 ;
    END
  END kv_own[214]
  PIN kv_own[215]
    DIRECTION INPUT ;
    USE SIGNAL ;
    PORT
      LAYER M5 ;
        RECT  62.64 0 62.664 0.084 ;
    END
  END kv_own[215]
  PIN kv_own[216]
    DIRECTION INPUT ;
    USE SIGNAL ;
    PORT
      LAYER M3 ;
        RECT  62.82 0 62.838 0.038 ;
    END
  END kv_own[216]
  PIN kv_own[217]
    DIRECTION INPUT ;
    USE SIGNAL ;
    PORT
      LAYER M5 ;
        RECT  62.976 0 63 0.084 ;
    END
  END kv_own[217]
  PIN kv_own[218]
    DIRECTION INPUT ;
    USE SIGNAL ;
    PORT
      LAYER M3 ;
        RECT  63.18 0 63.198 0.038 ;
    END
  END kv_own[218]
  PIN kv_own[219]
    DIRECTION INPUT ;
    USE SIGNAL ;
    PORT
      LAYER M5 ;
        RECT  63.36 0 63.384 0.084 ;
    END
  END kv_own[219]
  PIN kv_own[21]
    DIRECTION INPUT ;
    USE SIGNAL ;
    PORT
      LAYER M5 ;
        RECT  27.408 0 27.432 0.084 ;
    END
  END kv_own[21]
  PIN kv_own[220]
    DIRECTION INPUT ;
    USE SIGNAL ;
    PORT
      LAYER M3 ;
        RECT  63.54 0 63.558 0.038 ;
    END
  END kv_own[220]
  PIN kv_own[221]
    DIRECTION INPUT ;
    USE SIGNAL ;
    PORT
      LAYER M5 ;
        RECT  63.744 0 63.768 0.084 ;
    END
  END kv_own[221]
  PIN kv_own[222]
    DIRECTION INPUT ;
    USE SIGNAL ;
    PORT
      LAYER M3 ;
        RECT  63.9 0 63.918 0.038 ;
    END
  END kv_own[222]
  PIN kv_own[223]
    DIRECTION INPUT ;
    USE SIGNAL ;
    PORT
      LAYER M5 ;
        RECT  64.08 0 64.104 0.084 ;
    END
  END kv_own[223]
  PIN kv_own[224]
    DIRECTION INPUT ;
    USE SIGNAL ;
    PORT
      LAYER M3 ;
        RECT  64.26 0 64.278 0.038 ;
    END
  END kv_own[224]
  PIN kv_own[225]
    DIRECTION INPUT ;
    USE SIGNAL ;
    PORT
      LAYER M5 ;
        RECT  64.464 0 64.488 0.084 ;
    END
  END kv_own[225]
  PIN kv_own[226]
    DIRECTION INPUT ;
    USE SIGNAL ;
    PORT
      LAYER M3 ;
        RECT  64.62 0 64.638 0.038 ;
    END
  END kv_own[226]
  PIN kv_own[227]
    DIRECTION INPUT ;
    USE SIGNAL ;
    PORT
      LAYER M5 ;
        RECT  64.8 0 64.824 0.084 ;
    END
  END kv_own[227]
  PIN kv_own[228]
    DIRECTION INPUT ;
    USE SIGNAL ;
    PORT
      LAYER M3 ;
        RECT  64.98 0 64.998 0.038 ;
    END
  END kv_own[228]
  PIN kv_own[229]
    DIRECTION INPUT ;
    USE SIGNAL ;
    PORT
      LAYER M5 ;
        RECT  65.184 0 65.208 0.084 ;
    END
  END kv_own[229]
  PIN kv_own[22]
    DIRECTION INPUT ;
    USE SIGNAL ;
    PORT
      LAYER M3 ;
        RECT  27.576 0 27.594 0.038 ;
    END
  END kv_own[22]
  PIN kv_own[230]
    DIRECTION INPUT ;
    USE SIGNAL ;
    PORT
      LAYER M3 ;
        RECT  65.376 0 65.394 0.038 ;
    END
  END kv_own[230]
  PIN kv_own[231]
    DIRECTION INPUT ;
    USE SIGNAL ;
    PORT
      LAYER M5 ;
        RECT  65.52 0 65.544 0.084 ;
    END
  END kv_own[231]
  PIN kv_own[232]
    DIRECTION INPUT ;
    USE SIGNAL ;
    PORT
      LAYER M3 ;
        RECT  65.736 0 65.754 0.038 ;
    END
  END kv_own[232]
  PIN kv_own[233]
    DIRECTION INPUT ;
    USE SIGNAL ;
    PORT
      LAYER M5 ;
        RECT  65.904 0 65.928 0.084 ;
    END
  END kv_own[233]
  PIN kv_own[234]
    DIRECTION INPUT ;
    USE SIGNAL ;
    PORT
      LAYER M3 ;
        RECT  66.096 0 66.114 0.038 ;
    END
  END kv_own[234]
  PIN kv_own[235]
    DIRECTION INPUT ;
    USE SIGNAL ;
    PORT
      LAYER M5 ;
        RECT  66.288 0 66.312 0.084 ;
    END
  END kv_own[235]
  PIN kv_own[236]
    DIRECTION INPUT ;
    USE SIGNAL ;
    PORT
      LAYER M3 ;
        RECT  66.456 0 66.474 0.038 ;
    END
  END kv_own[236]
  PIN kv_own[237]
    DIRECTION INPUT ;
    USE SIGNAL ;
    PORT
      LAYER M5 ;
        RECT  66.624 0 66.648 0.084 ;
    END
  END kv_own[237]
  PIN kv_own[238]
    DIRECTION INPUT ;
    USE SIGNAL ;
    PORT
      LAYER M3 ;
        RECT  66.816 0 66.834 0.038 ;
    END
  END kv_own[238]
  PIN kv_own[239]
    DIRECTION INPUT ;
    USE SIGNAL ;
    PORT
      LAYER M5 ;
        RECT  67.008 0 67.032 0.084 ;
    END
  END kv_own[239]
  PIN kv_own[23]
    DIRECTION INPUT ;
    USE SIGNAL ;
    PORT
      LAYER M5 ;
        RECT  27.744 0 27.768 0.084 ;
    END
  END kv_own[23]
  PIN kv_own[240]
    DIRECTION INPUT ;
    USE SIGNAL ;
    PORT
      LAYER M3 ;
        RECT  67.176 0 67.194 0.038 ;
    END
  END kv_own[240]
  PIN kv_own[241]
    DIRECTION INPUT ;
    USE SIGNAL ;
    PORT
      LAYER M5 ;
        RECT  67.344 0 67.368 0.084 ;
    END
  END kv_own[241]
  PIN kv_own[242]
    DIRECTION INPUT ;
    USE SIGNAL ;
    PORT
      LAYER M3 ;
        RECT  67.536 0 67.554 0.038 ;
    END
  END kv_own[242]
  PIN kv_own[243]
    DIRECTION INPUT ;
    USE SIGNAL ;
    PORT
      LAYER M5 ;
        RECT  67.728 0 67.752 0.084 ;
    END
  END kv_own[243]
  PIN kv_own[244]
    DIRECTION INPUT ;
    USE SIGNAL ;
    PORT
      LAYER M3 ;
        RECT  67.896 0 67.914 0.038 ;
    END
  END kv_own[244]
  PIN kv_own[245]
    DIRECTION INPUT ;
    USE SIGNAL ;
    PORT
      LAYER M5 ;
        RECT  68.064 0 68.088 0.084 ;
    END
  END kv_own[245]
  PIN kv_own[246]
    DIRECTION INPUT ;
    USE SIGNAL ;
    PORT
      LAYER M3 ;
        RECT  68.256 0 68.274 0.038 ;
    END
  END kv_own[246]
  PIN kv_own[247]
    DIRECTION INPUT ;
    USE SIGNAL ;
    PORT
      LAYER M5 ;
        RECT  68.448 0 68.472 0.084 ;
    END
  END kv_own[247]
  PIN kv_own[248]
    DIRECTION INPUT ;
    USE SIGNAL ;
    PORT
      LAYER M3 ;
        RECT  68.616 0 68.634 0.038 ;
    END
  END kv_own[248]
  PIN kv_own[249]
    DIRECTION INPUT ;
    USE SIGNAL ;
    PORT
      LAYER M5 ;
        RECT  68.784 0 68.808 0.084 ;
    END
  END kv_own[249]
  PIN kv_own[24]
    DIRECTION INPUT ;
    USE SIGNAL ;
    PORT
      LAYER M3 ;
        RECT  27.936 0 27.954 0.038 ;
    END
  END kv_own[24]
  PIN kv_own[250]
    DIRECTION INPUT ;
    USE SIGNAL ;
    PORT
      LAYER M3 ;
        RECT  68.976 0 68.994 0.038 ;
    END
  END kv_own[250]
  PIN kv_own[251]
    DIRECTION INPUT ;
    USE SIGNAL ;
    PORT
      LAYER M5 ;
        RECT  69.168 0 69.192 0.084 ;
    END
  END kv_own[251]
  PIN kv_own[252]
    DIRECTION INPUT ;
    USE SIGNAL ;
    PORT
      LAYER M3 ;
        RECT  69.372 0 69.39 0.038 ;
    END
  END kv_own[252]
  PIN kv_own[253]
    DIRECTION INPUT ;
    USE SIGNAL ;
    PORT
      LAYER M5 ;
        RECT  69.552 0 69.576 0.084 ;
    END
  END kv_own[253]
  PIN kv_own[254]
    DIRECTION INPUT ;
    USE SIGNAL ;
    PORT
      LAYER M3 ;
        RECT  69.732 0 69.75 0.038 ;
    END
  END kv_own[254]
  PIN kv_own[255]
    DIRECTION INPUT ;
    USE SIGNAL ;
    PORT
      LAYER M5 ;
        RECT  69.888 0 69.912 0.084 ;
    END
  END kv_own[255]
  PIN kv_own[25]
    DIRECTION INPUT ;
    USE SIGNAL ;
    PORT
      LAYER M5 ;
        RECT  28.128 0 28.152 0.084 ;
    END
  END kv_own[25]
  PIN kv_own[26]
    DIRECTION INPUT ;
    USE SIGNAL ;
    PORT
      LAYER M3 ;
        RECT  28.296 0 28.314 0.038 ;
    END
  END kv_own[26]
  PIN kv_own[27]
    DIRECTION INPUT ;
    USE SIGNAL ;
    PORT
      LAYER M5 ;
        RECT  28.464 0 28.488 0.084 ;
    END
  END kv_own[27]
  PIN kv_own[28]
    DIRECTION INPUT ;
    USE SIGNAL ;
    PORT
      LAYER M3 ;
        RECT  28.656 0 28.674 0.038 ;
    END
  END kv_own[28]
  PIN kv_own[29]
    DIRECTION INPUT ;
    USE SIGNAL ;
    PORT
      LAYER M5 ;
        RECT  28.848 0 28.872 0.084 ;
    END
  END kv_own[29]
  PIN kv_own[2]
    DIRECTION INPUT ;
    USE SIGNAL ;
    PORT
      LAYER M3 ;
        RECT  23.94 0 23.958 0.038 ;
    END
  END kv_own[2]
  PIN kv_own[30]
    DIRECTION INPUT ;
    USE SIGNAL ;
    PORT
      LAYER M3 ;
        RECT  29.016 0 29.034 0.038 ;
    END
  END kv_own[30]
  PIN kv_own[31]
    DIRECTION INPUT ;
    USE SIGNAL ;
    PORT
      LAYER M5 ;
        RECT  29.232 0 29.256 0.084 ;
    END
  END kv_own[31]
  PIN kv_own[32]
    DIRECTION INPUT ;
    USE SIGNAL ;
    PORT
      LAYER M3 ;
        RECT  29.412 0 29.43 0.038 ;
    END
  END kv_own[32]
  PIN kv_own[33]
    DIRECTION INPUT ;
    USE SIGNAL ;
    PORT
      LAYER M5 ;
        RECT  29.568 0 29.592 0.084 ;
    END
  END kv_own[33]
  PIN kv_own[34]
    DIRECTION INPUT ;
    USE SIGNAL ;
    PORT
      LAYER M3 ;
        RECT  29.772 0 29.79 0.038 ;
    END
  END kv_own[34]
  PIN kv_own[35]
    DIRECTION INPUT ;
    USE SIGNAL ;
    PORT
      LAYER M5 ;
        RECT  29.952 0 29.976 0.084 ;
    END
  END kv_own[35]
  PIN kv_own[36]
    DIRECTION INPUT ;
    USE SIGNAL ;
    PORT
      LAYER M3 ;
        RECT  30.132 0 30.15 0.038 ;
    END
  END kv_own[36]
  PIN kv_own[37]
    DIRECTION INPUT ;
    USE SIGNAL ;
    PORT
      LAYER M5 ;
        RECT  30.288 0 30.312 0.084 ;
    END
  END kv_own[37]
  PIN kv_own[38]
    DIRECTION INPUT ;
    USE SIGNAL ;
    PORT
      LAYER M3 ;
        RECT  30.492 0 30.51 0.038 ;
    END
  END kv_own[38]
  PIN kv_own[39]
    DIRECTION INPUT ;
    USE SIGNAL ;
    PORT
      LAYER M5 ;
        RECT  30.672 0 30.696 0.084 ;
    END
  END kv_own[39]
  PIN kv_own[3]
    DIRECTION INPUT ;
    USE SIGNAL ;
    PORT
      LAYER M5 ;
        RECT  24.144 0 24.168 0.084 ;
    END
  END kv_own[3]
  PIN kv_own[40]
    DIRECTION INPUT ;
    USE SIGNAL ;
    PORT
      LAYER M3 ;
        RECT  30.852 0 30.87 0.038 ;
    END
  END kv_own[40]
  PIN kv_own[41]
    DIRECTION INPUT ;
    USE SIGNAL ;
    PORT
      LAYER M5 ;
        RECT  31.008 0 31.032 0.084 ;
    END
  END kv_own[41]
  PIN kv_own[42]
    DIRECTION INPUT ;
    USE SIGNAL ;
    PORT
      LAYER M3 ;
        RECT  31.212 0 31.23 0.038 ;
    END
  END kv_own[42]
  PIN kv_own[43]
    DIRECTION INPUT ;
    USE SIGNAL ;
    PORT
      LAYER M5 ;
        RECT  31.392 0 31.416 0.084 ;
    END
  END kv_own[43]
  PIN kv_own[44]
    DIRECTION INPUT ;
    USE SIGNAL ;
    PORT
      LAYER M3 ;
        RECT  31.572 0 31.59 0.038 ;
    END
  END kv_own[44]
  PIN kv_own[45]
    DIRECTION INPUT ;
    USE SIGNAL ;
    PORT
      LAYER M5 ;
        RECT  31.776 0 31.8 0.084 ;
    END
  END kv_own[45]
  PIN kv_own[46]
    DIRECTION INPUT ;
    USE SIGNAL ;
    PORT
      LAYER M3 ;
        RECT  31.932 0 31.95 0.038 ;
    END
  END kv_own[46]
  PIN kv_own[47]
    DIRECTION INPUT ;
    USE SIGNAL ;
    PORT
      LAYER M5 ;
        RECT  32.112 0 32.136 0.084 ;
    END
  END kv_own[47]
  PIN kv_own[48]
    DIRECTION INPUT ;
    USE SIGNAL ;
    PORT
      LAYER M3 ;
        RECT  32.292 0 32.31 0.038 ;
    END
  END kv_own[48]
  PIN kv_own[49]
    DIRECTION INPUT ;
    USE SIGNAL ;
    PORT
      LAYER M5 ;
        RECT  32.496 0 32.52 0.084 ;
    END
  END kv_own[49]
  PIN kv_own[4]
    DIRECTION INPUT ;
    USE SIGNAL ;
    PORT
      LAYER M3 ;
        RECT  24.3 0 24.318 0.038 ;
    END
  END kv_own[4]
  PIN kv_own[50]
    DIRECTION INPUT ;
    USE SIGNAL ;
    PORT
      LAYER M3 ;
        RECT  32.652 0 32.67 0.038 ;
    END
  END kv_own[50]
  PIN kv_own[51]
    DIRECTION INPUT ;
    USE SIGNAL ;
    PORT
      LAYER M5 ;
        RECT  32.832 0 32.856 0.084 ;
    END
  END kv_own[51]
  PIN kv_own[52]
    DIRECTION INPUT ;
    USE SIGNAL ;
    PORT
      LAYER M3 ;
        RECT  33.012 0 33.03 0.038 ;
    END
  END kv_own[52]
  PIN kv_own[53]
    DIRECTION INPUT ;
    USE SIGNAL ;
    PORT
      LAYER M5 ;
        RECT  33.216 0 33.24 0.084 ;
    END
  END kv_own[53]
  PIN kv_own[54]
    DIRECTION INPUT ;
    USE SIGNAL ;
    PORT
      LAYER M3 ;
        RECT  33.408 0 33.426 0.038 ;
    END
  END kv_own[54]
  PIN kv_own[55]
    DIRECTION INPUT ;
    USE SIGNAL ;
    PORT
      LAYER M5 ;
        RECT  33.552 0 33.576 0.084 ;
    END
  END kv_own[55]
  PIN kv_own[56]
    DIRECTION INPUT ;
    USE SIGNAL ;
    PORT
      LAYER M3 ;
        RECT  33.768 0 33.786 0.038 ;
    END
  END kv_own[56]
  PIN kv_own[57]
    DIRECTION INPUT ;
    USE SIGNAL ;
    PORT
      LAYER M5 ;
        RECT  33.936 0 33.96 0.084 ;
    END
  END kv_own[57]
  PIN kv_own[58]
    DIRECTION INPUT ;
    USE SIGNAL ;
    PORT
      LAYER M3 ;
        RECT  34.128 0 34.146 0.038 ;
    END
  END kv_own[58]
  PIN kv_own[59]
    DIRECTION INPUT ;
    USE SIGNAL ;
    PORT
      LAYER M5 ;
        RECT  34.32 0 34.344 0.084 ;
    END
  END kv_own[59]
  PIN kv_own[5]
    DIRECTION INPUT ;
    USE SIGNAL ;
    PORT
      LAYER M5 ;
        RECT  24.48 0 24.504 0.084 ;
    END
  END kv_own[5]
  PIN kv_own[60]
    DIRECTION INPUT ;
    USE SIGNAL ;
    PORT
      LAYER M3 ;
        RECT  34.488 0 34.506 0.038 ;
    END
  END kv_own[60]
  PIN kv_own[61]
    DIRECTION INPUT ;
    USE SIGNAL ;
    PORT
      LAYER M5 ;
        RECT  34.656 0 34.68 0.084 ;
    END
  END kv_own[61]
  PIN kv_own[62]
    DIRECTION INPUT ;
    USE SIGNAL ;
    PORT
      LAYER M3 ;
        RECT  34.848 0 34.866 0.038 ;
    END
  END kv_own[62]
  PIN kv_own[63]
    DIRECTION INPUT ;
    USE SIGNAL ;
    PORT
      LAYER M5 ;
        RECT  35.04 0 35.064 0.084 ;
    END
  END kv_own[63]
  PIN kv_own[64]
    DIRECTION INPUT ;
    USE SIGNAL ;
    PORT
      LAYER M3 ;
        RECT  35.208 0 35.226 0.038 ;
    END
  END kv_own[64]
  PIN kv_own[65]
    DIRECTION INPUT ;
    USE SIGNAL ;
    PORT
      LAYER M5 ;
        RECT  35.376 0 35.4 0.084 ;
    END
  END kv_own[65]
  PIN kv_own[66]
    DIRECTION INPUT ;
    USE SIGNAL ;
    PORT
      LAYER M3 ;
        RECT  35.568 0 35.586 0.038 ;
    END
  END kv_own[66]
  PIN kv_own[67]
    DIRECTION INPUT ;
    USE SIGNAL ;
    PORT
      LAYER M5 ;
        RECT  35.76 0 35.784 0.084 ;
    END
  END kv_own[67]
  PIN kv_own[68]
    DIRECTION INPUT ;
    USE SIGNAL ;
    PORT
      LAYER M3 ;
        RECT  35.928 0 35.946 0.038 ;
    END
  END kv_own[68]
  PIN kv_own[69]
    DIRECTION INPUT ;
    USE SIGNAL ;
    PORT
      LAYER M5 ;
        RECT  36.096 0 36.12 0.084 ;
    END
  END kv_own[69]
  PIN kv_own[6]
    DIRECTION INPUT ;
    USE SIGNAL ;
    PORT
      LAYER M3 ;
        RECT  24.66 0 24.678 0.038 ;
    END
  END kv_own[6]
  PIN kv_own[70]
    DIRECTION INPUT ;
    USE SIGNAL ;
    PORT
      LAYER M3 ;
        RECT  36.288 0 36.306 0.038 ;
    END
  END kv_own[70]
  PIN kv_own[71]
    DIRECTION INPUT ;
    USE SIGNAL ;
    PORT
      LAYER M5 ;
        RECT  36.48 0 36.504 0.084 ;
    END
  END kv_own[71]
  PIN kv_own[72]
    DIRECTION INPUT ;
    USE SIGNAL ;
    PORT
      LAYER M3 ;
        RECT  36.648 0 36.666 0.038 ;
    END
  END kv_own[72]
  PIN kv_own[73]
    DIRECTION INPUT ;
    USE SIGNAL ;
    PORT
      LAYER M5 ;
        RECT  36.816 0 36.84 0.084 ;
    END
  END kv_own[73]
  PIN kv_own[74]
    DIRECTION INPUT ;
    USE SIGNAL ;
    PORT
      LAYER M3 ;
        RECT  37.008 0 37.026 0.038 ;
    END
  END kv_own[74]
  PIN kv_own[75]
    DIRECTION INPUT ;
    USE SIGNAL ;
    PORT
      LAYER M5 ;
        RECT  37.2 0 37.224 0.084 ;
    END
  END kv_own[75]
  PIN kv_own[76]
    DIRECTION INPUT ;
    USE SIGNAL ;
    PORT
      LAYER M3 ;
        RECT  37.404 0 37.422 0.038 ;
    END
  END kv_own[76]
  PIN kv_own[77]
    DIRECTION INPUT ;
    USE SIGNAL ;
    PORT
      LAYER M5 ;
        RECT  37.584 0 37.608 0.084 ;
    END
  END kv_own[77]
  PIN kv_own[78]
    DIRECTION INPUT ;
    USE SIGNAL ;
    PORT
      LAYER M3 ;
        RECT  37.764 0 37.782 0.038 ;
    END
  END kv_own[78]
  PIN kv_own[79]
    DIRECTION INPUT ;
    USE SIGNAL ;
    PORT
      LAYER M5 ;
        RECT  37.92 0 37.944 0.084 ;
    END
  END kv_own[79]
  PIN kv_own[7]
    DIRECTION INPUT ;
    USE SIGNAL ;
    PORT
      LAYER M5 ;
        RECT  24.864 0 24.888 0.084 ;
    END
  END kv_own[7]
  PIN kv_own[80]
    DIRECTION INPUT ;
    USE SIGNAL ;
    PORT
      LAYER M3 ;
        RECT  38.124 0 38.142 0.038 ;
    END
  END kv_own[80]
  PIN kv_own[81]
    DIRECTION INPUT ;
    USE SIGNAL ;
    PORT
      LAYER M5 ;
        RECT  38.304 0 38.328 0.084 ;
    END
  END kv_own[81]
  PIN kv_own[82]
    DIRECTION INPUT ;
    USE SIGNAL ;
    PORT
      LAYER M3 ;
        RECT  38.484 0 38.502 0.038 ;
    END
  END kv_own[82]
  PIN kv_own[83]
    DIRECTION INPUT ;
    USE SIGNAL ;
    PORT
      LAYER M5 ;
        RECT  38.64 0 38.664 0.084 ;
    END
  END kv_own[83]
  PIN kv_own[84]
    DIRECTION INPUT ;
    USE SIGNAL ;
    PORT
      LAYER M3 ;
        RECT  38.844 0 38.862 0.038 ;
    END
  END kv_own[84]
  PIN kv_own[85]
    DIRECTION INPUT ;
    USE SIGNAL ;
    PORT
      LAYER M5 ;
        RECT  39.024 0 39.048 0.084 ;
    END
  END kv_own[85]
  PIN kv_own[86]
    DIRECTION INPUT ;
    USE SIGNAL ;
    PORT
      LAYER M3 ;
        RECT  39.204 0 39.222 0.038 ;
    END
  END kv_own[86]
  PIN kv_own[87]
    DIRECTION INPUT ;
    USE SIGNAL ;
    PORT
      LAYER M5 ;
        RECT  39.36 0 39.384 0.084 ;
    END
  END kv_own[87]
  PIN kv_own[88]
    DIRECTION INPUT ;
    USE SIGNAL ;
    PORT
      LAYER M3 ;
        RECT  39.564 0 39.582 0.038 ;
    END
  END kv_own[88]
  PIN kv_own[89]
    DIRECTION INPUT ;
    USE SIGNAL ;
    PORT
      LAYER M5 ;
        RECT  39.744 0 39.768 0.084 ;
    END
  END kv_own[89]
  PIN kv_own[8]
    DIRECTION INPUT ;
    USE SIGNAL ;
    PORT
      LAYER M3 ;
        RECT  25.02 0 25.038 0.038 ;
    END
  END kv_own[8]
  PIN kv_own[90]
    DIRECTION INPUT ;
    USE SIGNAL ;
    PORT
      LAYER M3 ;
        RECT  39.924 0 39.942 0.038 ;
    END
  END kv_own[90]
  PIN kv_own[91]
    DIRECTION INPUT ;
    USE SIGNAL ;
    PORT
      LAYER M5 ;
        RECT  40.128 0 40.152 0.084 ;
    END
  END kv_own[91]
  PIN kv_own[92]
    DIRECTION INPUT ;
    USE SIGNAL ;
    PORT
      LAYER M3 ;
        RECT  40.284 0 40.302 0.038 ;
    END
  END kv_own[92]
  PIN kv_own[93]
    DIRECTION INPUT ;
    USE SIGNAL ;
    PORT
      LAYER M5 ;
        RECT  40.464 0 40.488 0.084 ;
    END
  END kv_own[93]
  PIN kv_own[94]
    DIRECTION INPUT ;
    USE SIGNAL ;
    PORT
      LAYER M3 ;
        RECT  40.644 0 40.662 0.038 ;
    END
  END kv_own[94]
  PIN kv_own[95]
    DIRECTION INPUT ;
    USE SIGNAL ;
    PORT
      LAYER M5 ;
        RECT  40.848 0 40.872 0.084 ;
    END
  END kv_own[95]
  PIN kv_own[96]
    DIRECTION INPUT ;
    USE SIGNAL ;
    PORT
      LAYER M3 ;
        RECT  41.004 0 41.022 0.038 ;
    END
  END kv_own[96]
  PIN kv_own[97]
    DIRECTION INPUT ;
    USE SIGNAL ;
    PORT
      LAYER M5 ;
        RECT  41.184 0 41.208 0.084 ;
    END
  END kv_own[97]
  PIN kv_own[98]
    DIRECTION INPUT ;
    USE SIGNAL ;
    PORT
      LAYER M3 ;
        RECT  41.4 0 41.418 0.038 ;
    END
  END kv_own[98]
  PIN kv_own[99]
    DIRECTION INPUT ;
    USE SIGNAL ;
    PORT
      LAYER M5 ;
        RECT  41.568 0 41.592 0.084 ;
    END
  END kv_own[99]
  PIN kv_own[9]
    DIRECTION INPUT ;
    USE SIGNAL ;
    PORT
      LAYER M5 ;
        RECT  25.2 0 25.224 0.084 ;
    END
  END kv_own[9]
  PIN kv_sh[0]
    DIRECTION INPUT ;
    USE SIGNAL ;
    PORT
      LAYER M3 ;
        RECT  70.596 0 70.614 0.038 ;
    END
  END kv_sh[0]
  PIN kv_sh[100]
    DIRECTION INPUT ;
    USE SIGNAL ;
    PORT
      LAYER M3 ;
        RECT  88.56 0 88.578 0.038 ;
    END
  END kv_sh[100]
  PIN kv_sh[101]
    DIRECTION INPUT ;
    USE SIGNAL ;
    PORT
      LAYER M5 ;
        RECT  88.704 0 88.728 0.084 ;
    END
  END kv_sh[101]
  PIN kv_sh[102]
    DIRECTION INPUT ;
    USE SIGNAL ;
    PORT
      LAYER M3 ;
        RECT  88.92 0 88.938 0.038 ;
    END
  END kv_sh[102]
  PIN kv_sh[103]
    DIRECTION INPUT ;
    USE SIGNAL ;
    PORT
      LAYER M5 ;
        RECT  89.088 0 89.112 0.084 ;
    END
  END kv_sh[103]
  PIN kv_sh[104]
    DIRECTION INPUT ;
    USE SIGNAL ;
    PORT
      LAYER M3 ;
        RECT  89.28 0 89.298 0.038 ;
    END
  END kv_sh[104]
  PIN kv_sh[105]
    DIRECTION INPUT ;
    USE SIGNAL ;
    PORT
      LAYER M5 ;
        RECT  89.424 0 89.448 0.084 ;
    END
  END kv_sh[105]
  PIN kv_sh[106]
    DIRECTION INPUT ;
    USE SIGNAL ;
    PORT
      LAYER M3 ;
        RECT  89.64 0 89.658 0.038 ;
    END
  END kv_sh[106]
  PIN kv_sh[107]
    DIRECTION INPUT ;
    USE SIGNAL ;
    PORT
      LAYER M5 ;
        RECT  89.808 0 89.832 0.084 ;
    END
  END kv_sh[107]
  PIN kv_sh[108]
    DIRECTION INPUT ;
    USE SIGNAL ;
    PORT
      LAYER M3 ;
        RECT  90 0 90.018 0.038 ;
    END
  END kv_sh[108]
  PIN kv_sh[109]
    DIRECTION INPUT ;
    USE SIGNAL ;
    PORT
      LAYER M5 ;
        RECT  90.144 0 90.168 0.084 ;
    END
  END kv_sh[109]
  PIN kv_sh[10]
    DIRECTION INPUT ;
    USE SIGNAL ;
    PORT
      LAYER M3 ;
        RECT  72.396 0 72.414 0.038 ;
    END
  END kv_sh[10]
  PIN kv_sh[110]
    DIRECTION INPUT ;
    USE SIGNAL ;
    PORT
      LAYER M3 ;
        RECT  90.36 0 90.378 0.038 ;
    END
  END kv_sh[110]
  PIN kv_sh[111]
    DIRECTION INPUT ;
    USE SIGNAL ;
    PORT
      LAYER M5 ;
        RECT  90.528 0 90.552 0.084 ;
    END
  END kv_sh[111]
  PIN kv_sh[112]
    DIRECTION INPUT ;
    USE SIGNAL ;
    PORT
      LAYER M3 ;
        RECT  90.72 0 90.738 0.038 ;
    END
  END kv_sh[112]
  PIN kv_sh[113]
    DIRECTION INPUT ;
    USE SIGNAL ;
    PORT
      LAYER M5 ;
        RECT  90.864 0 90.888 0.084 ;
    END
  END kv_sh[113]
  PIN kv_sh[114]
    DIRECTION INPUT ;
    USE SIGNAL ;
    PORT
      LAYER M3 ;
        RECT  91.08 0 91.098 0.038 ;
    END
  END kv_sh[114]
  PIN kv_sh[115]
    DIRECTION INPUT ;
    USE SIGNAL ;
    PORT
      LAYER M5 ;
        RECT  91.248 0 91.272 0.084 ;
    END
  END kv_sh[115]
  PIN kv_sh[116]
    DIRECTION INPUT ;
    USE SIGNAL ;
    PORT
      LAYER M3 ;
        RECT  91.44 0 91.458 0.038 ;
    END
  END kv_sh[116]
  PIN kv_sh[117]
    DIRECTION INPUT ;
    USE SIGNAL ;
    PORT
      LAYER M5 ;
        RECT  91.584 0 91.608 0.084 ;
    END
  END kv_sh[117]
  PIN kv_sh[118]
    DIRECTION INPUT ;
    USE SIGNAL ;
    PORT
      LAYER M3 ;
        RECT  91.8 0 91.818 0.038 ;
    END
  END kv_sh[118]
  PIN kv_sh[119]
    DIRECTION INPUT ;
    USE SIGNAL ;
    PORT
      LAYER M5 ;
        RECT  91.968 0 91.992 0.084 ;
    END
  END kv_sh[119]
  PIN kv_sh[11]
    DIRECTION INPUT ;
    USE SIGNAL ;
    PORT
      LAYER M5 ;
        RECT  72.576 0 72.6 0.084 ;
    END
  END kv_sh[11]
  PIN kv_sh[120]
    DIRECTION INPUT ;
    USE SIGNAL ;
    PORT
      LAYER M3 ;
        RECT  92.16 0 92.178 0.038 ;
    END
  END kv_sh[120]
  PIN kv_sh[121]
    DIRECTION INPUT ;
    USE SIGNAL ;
    PORT
      LAYER M5 ;
        RECT  92.304 0 92.328 0.084 ;
    END
  END kv_sh[121]
  PIN kv_sh[122]
    DIRECTION INPUT ;
    USE SIGNAL ;
    PORT
      LAYER M3 ;
        RECT  92.52 0 92.538 0.038 ;
    END
  END kv_sh[122]
  PIN kv_sh[123]
    DIRECTION INPUT ;
    USE SIGNAL ;
    PORT
      LAYER M5 ;
        RECT  92.688 0 92.712 0.084 ;
    END
  END kv_sh[123]
  PIN kv_sh[124]
    DIRECTION INPUT ;
    USE SIGNAL ;
    PORT
      LAYER M3 ;
        RECT  92.88 0 92.898 0.038 ;
    END
  END kv_sh[124]
  PIN kv_sh[125]
    DIRECTION INPUT ;
    USE SIGNAL ;
    PORT
      LAYER M5 ;
        RECT  93.024 0 93.048 0.084 ;
    END
  END kv_sh[125]
  PIN kv_sh[126]
    DIRECTION INPUT ;
    USE SIGNAL ;
    PORT
      LAYER M3 ;
        RECT  93.204 0 93.222 0.038 ;
    END
  END kv_sh[126]
  PIN kv_sh[127]
    DIRECTION INPUT ;
    USE SIGNAL ;
    PORT
      LAYER M5 ;
        RECT  93.408 0 93.432 0.084 ;
    END
  END kv_sh[127]
  PIN kv_sh[128]
    DIRECTION INPUT ;
    USE SIGNAL ;
    PORT
      LAYER M3 ;
        RECT  93.564 0 93.582 0.038 ;
    END
  END kv_sh[128]
  PIN kv_sh[129]
    DIRECTION INPUT ;
    USE SIGNAL ;
    PORT
      LAYER M5 ;
        RECT  93.744 0 93.768 0.084 ;
    END
  END kv_sh[129]
  PIN kv_sh[12]
    DIRECTION INPUT ;
    USE SIGNAL ;
    PORT
      LAYER M3 ;
        RECT  72.72 0 72.738 0.038 ;
    END
  END kv_sh[12]
  PIN kv_sh[130]
    DIRECTION INPUT ;
    USE SIGNAL ;
    PORT
      LAYER M3 ;
        RECT  93.924 0 93.942 0.038 ;
    END
  END kv_sh[130]
  PIN kv_sh[131]
    DIRECTION INPUT ;
    USE SIGNAL ;
    PORT
      LAYER M5 ;
        RECT  94.128 0 94.152 0.084 ;
    END
  END kv_sh[131]
  PIN kv_sh[132]
    DIRECTION INPUT ;
    USE SIGNAL ;
    PORT
      LAYER M3 ;
        RECT  94.284 0 94.302 0.038 ;
    END
  END kv_sh[132]
  PIN kv_sh[133]
    DIRECTION INPUT ;
    USE SIGNAL ;
    PORT
      LAYER M5 ;
        RECT  94.464 0 94.488 0.084 ;
    END
  END kv_sh[133]
  PIN kv_sh[134]
    DIRECTION INPUT ;
    USE SIGNAL ;
    PORT
      LAYER M3 ;
        RECT  94.644 0 94.662 0.038 ;
    END
  END kv_sh[134]
  PIN kv_sh[135]
    DIRECTION INPUT ;
    USE SIGNAL ;
    PORT
      LAYER M5 ;
        RECT  94.848 0 94.872 0.084 ;
    END
  END kv_sh[135]
  PIN kv_sh[136]
    DIRECTION INPUT ;
    USE SIGNAL ;
    PORT
      LAYER M3 ;
        RECT  95.004 0 95.022 0.038 ;
    END
  END kv_sh[136]
  PIN kv_sh[137]
    DIRECTION INPUT ;
    USE SIGNAL ;
    PORT
      LAYER M5 ;
        RECT  95.184 0 95.208 0.084 ;
    END
  END kv_sh[137]
  PIN kv_sh[138]
    DIRECTION INPUT ;
    USE SIGNAL ;
    PORT
      LAYER M3 ;
        RECT  95.364 0 95.382 0.038 ;
    END
  END kv_sh[138]
  PIN kv_sh[139]
    DIRECTION INPUT ;
    USE SIGNAL ;
    PORT
      LAYER M5 ;
        RECT  95.568 0 95.592 0.084 ;
    END
  END kv_sh[139]
  PIN kv_sh[13]
    DIRECTION INPUT ;
    USE SIGNAL ;
    PORT
      LAYER M5 ;
        RECT  72.912 0 72.936 0.084 ;
    END
  END kv_sh[13]
  PIN kv_sh[140]
    DIRECTION INPUT ;
    USE SIGNAL ;
    PORT
      LAYER M3 ;
        RECT  95.724 0 95.742 0.038 ;
    END
  END kv_sh[140]
  PIN kv_sh[141]
    DIRECTION INPUT ;
    USE SIGNAL ;
    PORT
      LAYER M5 ;
        RECT  95.904 0 95.928 0.084 ;
    END
  END kv_sh[141]
  PIN kv_sh[142]
    DIRECTION INPUT ;
    USE SIGNAL ;
    PORT
      LAYER M3 ;
        RECT  96.084 0 96.102 0.038 ;
    END
  END kv_sh[142]
  PIN kv_sh[143]
    DIRECTION INPUT ;
    USE SIGNAL ;
    PORT
      LAYER M5 ;
        RECT  96.288 0 96.312 0.084 ;
    END
  END kv_sh[143]
  PIN kv_sh[144]
    DIRECTION INPUT ;
    USE SIGNAL ;
    PORT
      LAYER M3 ;
        RECT  96.444 0 96.462 0.038 ;
    END
  END kv_sh[144]
  PIN kv_sh[145]
    DIRECTION INPUT ;
    USE SIGNAL ;
    PORT
      LAYER M5 ;
        RECT  96.624 0 96.648 0.084 ;
    END
  END kv_sh[145]
  PIN kv_sh[146]
    DIRECTION INPUT ;
    USE SIGNAL ;
    PORT
      LAYER M3 ;
        RECT  96.804 0 96.822 0.038 ;
    END
  END kv_sh[146]
  PIN kv_sh[147]
    DIRECTION INPUT ;
    USE SIGNAL ;
    PORT
      LAYER M5 ;
        RECT  97.008 0 97.032 0.084 ;
    END
  END kv_sh[147]
  PIN kv_sh[148]
    DIRECTION INPUT ;
    USE SIGNAL ;
    PORT
      LAYER M3 ;
        RECT  97.164 0 97.182 0.038 ;
    END
  END kv_sh[148]
  PIN kv_sh[149]
    DIRECTION INPUT ;
    USE SIGNAL ;
    PORT
      LAYER M5 ;
        RECT  97.344 0 97.368 0.084 ;
    END
  END kv_sh[149]
  PIN kv_sh[14]
    DIRECTION INPUT ;
    USE SIGNAL ;
    PORT
      LAYER M3 ;
        RECT  73.08 0 73.098 0.038 ;
    END
  END kv_sh[14]
  PIN kv_sh[150]
    DIRECTION INPUT ;
    USE SIGNAL ;
    PORT
      LAYER M3 ;
        RECT  97.524 0 97.542 0.038 ;
    END
  END kv_sh[150]
  PIN kv_sh[151]
    DIRECTION INPUT ;
    USE SIGNAL ;
    PORT
      LAYER M5 ;
        RECT  97.728 0 97.752 0.084 ;
    END
  END kv_sh[151]
  PIN kv_sh[152]
    DIRECTION INPUT ;
    USE SIGNAL ;
    PORT
      LAYER M3 ;
        RECT  97.884 0 97.902 0.038 ;
    END
  END kv_sh[152]
  PIN kv_sh[153]
    DIRECTION INPUT ;
    USE SIGNAL ;
    PORT
      LAYER M5 ;
        RECT  98.064 0 98.088 0.084 ;
    END
  END kv_sh[153]
  PIN kv_sh[154]
    DIRECTION INPUT ;
    USE SIGNAL ;
    PORT
      LAYER M3 ;
        RECT  98.244 0 98.262 0.038 ;
    END
  END kv_sh[154]
  PIN kv_sh[155]
    DIRECTION INPUT ;
    USE SIGNAL ;
    PORT
      LAYER M5 ;
        RECT  98.448 0 98.472 0.084 ;
    END
  END kv_sh[155]
  PIN kv_sh[156]
    DIRECTION INPUT ;
    USE SIGNAL ;
    PORT
      LAYER M3 ;
        RECT  98.604 0 98.622 0.038 ;
    END
  END kv_sh[156]
  PIN kv_sh[157]
    DIRECTION INPUT ;
    USE SIGNAL ;
    PORT
      LAYER M5 ;
        RECT  98.784 0 98.808 0.084 ;
    END
  END kv_sh[157]
  PIN kv_sh[158]
    DIRECTION INPUT ;
    USE SIGNAL ;
    PORT
      LAYER M3 ;
        RECT  98.964 0 98.982 0.038 ;
    END
  END kv_sh[158]
  PIN kv_sh[159]
    DIRECTION INPUT ;
    USE SIGNAL ;
    PORT
      LAYER M5 ;
        RECT  99.168 0 99.192 0.084 ;
    END
  END kv_sh[159]
  PIN kv_sh[15]
    DIRECTION INPUT ;
    USE SIGNAL ;
    PORT
      LAYER M5 ;
        RECT  73.296 0 73.32 0.084 ;
    END
  END kv_sh[15]
  PIN kv_sh[160]
    DIRECTION INPUT ;
    USE SIGNAL ;
    PORT
      LAYER M3 ;
        RECT  99.324 0 99.342 0.038 ;
    END
  END kv_sh[160]
  PIN kv_sh[161]
    DIRECTION INPUT ;
    USE SIGNAL ;
    PORT
      LAYER M5 ;
        RECT  99.504 0 99.528 0.084 ;
    END
  END kv_sh[161]
  PIN kv_sh[162]
    DIRECTION INPUT ;
    USE SIGNAL ;
    PORT
      LAYER M3 ;
        RECT  99.684 0 99.702 0.038 ;
    END
  END kv_sh[162]
  PIN kv_sh[163]
    DIRECTION INPUT ;
    USE SIGNAL ;
    PORT
      LAYER M5 ;
        RECT  99.888 0 99.912 0.084 ;
    END
  END kv_sh[163]
  PIN kv_sh[164]
    DIRECTION INPUT ;
    USE SIGNAL ;
    PORT
      LAYER M3 ;
        RECT  100.044 0 100.062 0.038 ;
    END
  END kv_sh[164]
  PIN kv_sh[165]
    DIRECTION INPUT ;
    USE SIGNAL ;
    PORT
      LAYER M5 ;
        RECT  100.224 0 100.248 0.084 ;
    END
  END kv_sh[165]
  PIN kv_sh[166]
    DIRECTION INPUT ;
    USE SIGNAL ;
    PORT
      LAYER M3 ;
        RECT  100.404 0 100.422 0.038 ;
    END
  END kv_sh[166]
  PIN kv_sh[167]
    DIRECTION INPUT ;
    USE SIGNAL ;
    PORT
      LAYER M5 ;
        RECT  100.608 0 100.632 0.084 ;
    END
  END kv_sh[167]
  PIN kv_sh[168]
    DIRECTION INPUT ;
    USE SIGNAL ;
    PORT
      LAYER M3 ;
        RECT  100.764 0 100.782 0.038 ;
    END
  END kv_sh[168]
  PIN kv_sh[169]
    DIRECTION INPUT ;
    USE SIGNAL ;
    PORT
      LAYER M5 ;
        RECT  100.944 0 100.968 0.084 ;
    END
  END kv_sh[169]
  PIN kv_sh[16]
    DIRECTION INPUT ;
    USE SIGNAL ;
    PORT
      LAYER M3 ;
        RECT  73.44 0 73.458 0.038 ;
    END
  END kv_sh[16]
  PIN kv_sh[170]
    DIRECTION INPUT ;
    USE SIGNAL ;
    PORT
      LAYER M3 ;
        RECT  101.124 0 101.142 0.038 ;
    END
  END kv_sh[170]
  PIN kv_sh[171]
    DIRECTION INPUT ;
    USE SIGNAL ;
    PORT
      LAYER M5 ;
        RECT  101.328 0 101.352 0.084 ;
    END
  END kv_sh[171]
  PIN kv_sh[172]
    DIRECTION INPUT ;
    USE SIGNAL ;
    PORT
      LAYER M3 ;
        RECT  101.484 0 101.502 0.038 ;
    END
  END kv_sh[172]
  PIN kv_sh[173]
    DIRECTION INPUT ;
    USE SIGNAL ;
    PORT
      LAYER M5 ;
        RECT  101.664 0 101.688 0.084 ;
    END
  END kv_sh[173]
  PIN kv_sh[174]
    DIRECTION INPUT ;
    USE SIGNAL ;
    PORT
      LAYER M3 ;
        RECT  101.844 0 101.862 0.038 ;
    END
  END kv_sh[174]
  PIN kv_sh[175]
    DIRECTION INPUT ;
    USE SIGNAL ;
    PORT
      LAYER M5 ;
        RECT  102 0 102.024 0.084 ;
    END
  END kv_sh[175]
  PIN kv_sh[176]
    DIRECTION INPUT ;
    USE SIGNAL ;
    PORT
      LAYER M3 ;
        RECT  102.204 0 102.222 0.038 ;
    END
  END kv_sh[176]
  PIN kv_sh[177]
    DIRECTION INPUT ;
    USE SIGNAL ;
    PORT
      LAYER M5 ;
        RECT  102.384 0 102.408 0.084 ;
    END
  END kv_sh[177]
  PIN kv_sh[178]
    DIRECTION INPUT ;
    USE SIGNAL ;
    PORT
      LAYER M3 ;
        RECT  102.564 0 102.582 0.038 ;
    END
  END kv_sh[178]
  PIN kv_sh[179]
    DIRECTION INPUT ;
    USE SIGNAL ;
    PORT
      LAYER M5 ;
        RECT  102.72 0 102.744 0.084 ;
    END
  END kv_sh[179]
  PIN kv_sh[17]
    DIRECTION INPUT ;
    USE SIGNAL ;
    PORT
      LAYER M5 ;
        RECT  73.632 0 73.656 0.084 ;
    END
  END kv_sh[17]
  PIN kv_sh[180]
    DIRECTION INPUT ;
    USE SIGNAL ;
    PORT
      LAYER M3 ;
        RECT  102.924 0 102.942 0.038 ;
    END
  END kv_sh[180]
  PIN kv_sh[181]
    DIRECTION INPUT ;
    USE SIGNAL ;
    PORT
      LAYER M5 ;
        RECT  103.104 0 103.128 0.084 ;
    END
  END kv_sh[181]
  PIN kv_sh[182]
    DIRECTION INPUT ;
    USE SIGNAL ;
    PORT
      LAYER M3 ;
        RECT  103.284 0 103.302 0.038 ;
    END
  END kv_sh[182]
  PIN kv_sh[183]
    DIRECTION INPUT ;
    USE SIGNAL ;
    PORT
      LAYER M5 ;
        RECT  103.44 0 103.464 0.084 ;
    END
  END kv_sh[183]
  PIN kv_sh[184]
    DIRECTION INPUT ;
    USE SIGNAL ;
    PORT
      LAYER M3 ;
        RECT  103.644 0 103.662 0.038 ;
    END
  END kv_sh[184]
  PIN kv_sh[185]
    DIRECTION INPUT ;
    USE SIGNAL ;
    PORT
      LAYER M5 ;
        RECT  103.824 0 103.848 0.084 ;
    END
  END kv_sh[185]
  PIN kv_sh[186]
    DIRECTION INPUT ;
    USE SIGNAL ;
    PORT
      LAYER M3 ;
        RECT  104.004 0 104.022 0.038 ;
    END
  END kv_sh[186]
  PIN kv_sh[187]
    DIRECTION INPUT ;
    USE SIGNAL ;
    PORT
      LAYER M5 ;
        RECT  104.16 0 104.184 0.084 ;
    END
  END kv_sh[187]
  PIN kv_sh[188]
    DIRECTION INPUT ;
    USE SIGNAL ;
    PORT
      LAYER M3 ;
        RECT  104.364 0 104.382 0.038 ;
    END
  END kv_sh[188]
  PIN kv_sh[189]
    DIRECTION INPUT ;
    USE SIGNAL ;
    PORT
      LAYER M5 ;
        RECT  104.544 0 104.568 0.084 ;
    END
  END kv_sh[189]
  PIN kv_sh[18]
    DIRECTION INPUT ;
    USE SIGNAL ;
    PORT
      LAYER M3 ;
        RECT  73.8 0 73.818 0.038 ;
    END
  END kv_sh[18]
  PIN kv_sh[190]
    DIRECTION INPUT ;
    USE SIGNAL ;
    PORT
      LAYER M3 ;
        RECT  104.724 0 104.742 0.038 ;
    END
  END kv_sh[190]
  PIN kv_sh[191]
    DIRECTION INPUT ;
    USE SIGNAL ;
    PORT
      LAYER M5 ;
        RECT  104.88 0 104.904 0.084 ;
    END
  END kv_sh[191]
  PIN kv_sh[192]
    DIRECTION INPUT ;
    USE SIGNAL ;
    PORT
      LAYER M3 ;
        RECT  105.084 0 105.102 0.038 ;
    END
  END kv_sh[192]
  PIN kv_sh[193]
    DIRECTION INPUT ;
    USE SIGNAL ;
    PORT
      LAYER M5 ;
        RECT  105.264 0 105.288 0.084 ;
    END
  END kv_sh[193]
  PIN kv_sh[194]
    DIRECTION INPUT ;
    USE SIGNAL ;
    PORT
      LAYER M3 ;
        RECT  105.444 0 105.462 0.038 ;
    END
  END kv_sh[194]
  PIN kv_sh[195]
    DIRECTION INPUT ;
    USE SIGNAL ;
    PORT
      LAYER M5 ;
        RECT  105.6 0 105.624 0.084 ;
    END
  END kv_sh[195]
  PIN kv_sh[196]
    DIRECTION INPUT ;
    USE SIGNAL ;
    PORT
      LAYER M3 ;
        RECT  105.804 0 105.822 0.038 ;
    END
  END kv_sh[196]
  PIN kv_sh[197]
    DIRECTION INPUT ;
    USE SIGNAL ;
    PORT
      LAYER M5 ;
        RECT  105.984 0 106.008 0.084 ;
    END
  END kv_sh[197]
  PIN kv_sh[198]
    DIRECTION INPUT ;
    USE SIGNAL ;
    PORT
      LAYER M3 ;
        RECT  106.164 0 106.182 0.038 ;
    END
  END kv_sh[198]
  PIN kv_sh[199]
    DIRECTION INPUT ;
    USE SIGNAL ;
    PORT
      LAYER M5 ;
        RECT  106.32 0 106.344 0.084 ;
    END
  END kv_sh[199]
  PIN kv_sh[19]
    DIRECTION INPUT ;
    USE SIGNAL ;
    PORT
      LAYER M5 ;
        RECT  74.016 0 74.04 0.084 ;
    END
  END kv_sh[19]
  PIN kv_sh[1]
    DIRECTION INPUT ;
    USE SIGNAL ;
    PORT
      LAYER M5 ;
        RECT  70.752 0 70.776 0.084 ;
    END
  END kv_sh[1]
  PIN kv_sh[200]
    DIRECTION INPUT ;
    USE SIGNAL ;
    PORT
      LAYER M3 ;
        RECT  106.524 0 106.542 0.038 ;
    END
  END kv_sh[200]
  PIN kv_sh[201]
    DIRECTION INPUT ;
    USE SIGNAL ;
    PORT
      LAYER M5 ;
        RECT  106.704 0 106.728 0.084 ;
    END
  END kv_sh[201]
  PIN kv_sh[202]
    DIRECTION INPUT ;
    USE SIGNAL ;
    PORT
      LAYER M3 ;
        RECT  106.884 0 106.902 0.038 ;
    END
  END kv_sh[202]
  PIN kv_sh[203]
    DIRECTION INPUT ;
    USE SIGNAL ;
    PORT
      LAYER M5 ;
        RECT  107.04 0 107.064 0.084 ;
    END
  END kv_sh[203]
  PIN kv_sh[204]
    DIRECTION INPUT ;
    USE SIGNAL ;
    PORT
      LAYER M3 ;
        RECT  107.244 0 107.262 0.038 ;
    END
  END kv_sh[204]
  PIN kv_sh[205]
    DIRECTION INPUT ;
    USE SIGNAL ;
    PORT
      LAYER M5 ;
        RECT  107.424 0 107.448 0.084 ;
    END
  END kv_sh[205]
  PIN kv_sh[206]
    DIRECTION INPUT ;
    USE SIGNAL ;
    PORT
      LAYER M3 ;
        RECT  107.604 0 107.622 0.038 ;
    END
  END kv_sh[206]
  PIN kv_sh[207]
    DIRECTION INPUT ;
    USE SIGNAL ;
    PORT
      LAYER M5 ;
        RECT  107.76 0 107.784 0.084 ;
    END
  END kv_sh[207]
  PIN kv_sh[208]
    DIRECTION INPUT ;
    USE SIGNAL ;
    PORT
      LAYER M3 ;
        RECT  107.964 0 107.982 0.038 ;
    END
  END kv_sh[208]
  PIN kv_sh[209]
    DIRECTION INPUT ;
    USE SIGNAL ;
    PORT
      LAYER M5 ;
        RECT  108.144 0 108.168 0.084 ;
    END
  END kv_sh[209]
  PIN kv_sh[20]
    DIRECTION INPUT ;
    USE SIGNAL ;
    PORT
      LAYER M3 ;
        RECT  74.16 0 74.178 0.038 ;
    END
  END kv_sh[20]
  PIN kv_sh[210]
    DIRECTION INPUT ;
    USE SIGNAL ;
    PORT
      LAYER M3 ;
        RECT  108.324 0 108.342 0.038 ;
    END
  END kv_sh[210]
  PIN kv_sh[211]
    DIRECTION INPUT ;
    USE SIGNAL ;
    PORT
      LAYER M5 ;
        RECT  108.48 0 108.504 0.084 ;
    END
  END kv_sh[211]
  PIN kv_sh[212]
    DIRECTION INPUT ;
    USE SIGNAL ;
    PORT
      LAYER M3 ;
        RECT  108.684 0 108.702 0.038 ;
    END
  END kv_sh[212]
  PIN kv_sh[213]
    DIRECTION INPUT ;
    USE SIGNAL ;
    PORT
      LAYER M5 ;
        RECT  108.864 0 108.888 0.084 ;
    END
  END kv_sh[213]
  PIN kv_sh[214]
    DIRECTION INPUT ;
    USE SIGNAL ;
    PORT
      LAYER M3 ;
        RECT  109.044 0 109.062 0.038 ;
    END
  END kv_sh[214]
  PIN kv_sh[215]
    DIRECTION INPUT ;
    USE SIGNAL ;
    PORT
      LAYER M5 ;
        RECT  109.2 0 109.224 0.084 ;
    END
  END kv_sh[215]
  PIN kv_sh[216]
    DIRECTION INPUT ;
    USE SIGNAL ;
    PORT
      LAYER M3 ;
        RECT  109.404 0 109.422 0.038 ;
    END
  END kv_sh[216]
  PIN kv_sh[217]
    DIRECTION INPUT ;
    USE SIGNAL ;
    PORT
      LAYER M5 ;
        RECT  109.584 0 109.608 0.084 ;
    END
  END kv_sh[217]
  PIN kv_sh[218]
    DIRECTION INPUT ;
    USE SIGNAL ;
    PORT
      LAYER M3 ;
        RECT  109.764 0 109.782 0.038 ;
    END
  END kv_sh[218]
  PIN kv_sh[219]
    DIRECTION INPUT ;
    USE SIGNAL ;
    PORT
      LAYER M5 ;
        RECT  109.92 0 109.944 0.084 ;
    END
  END kv_sh[219]
  PIN kv_sh[21]
    DIRECTION INPUT ;
    USE SIGNAL ;
    PORT
      LAYER M5 ;
        RECT  74.352 0 74.376 0.084 ;
    END
  END kv_sh[21]
  PIN kv_sh[220]
    DIRECTION INPUT ;
    USE SIGNAL ;
    PORT
      LAYER M3 ;
        RECT  110.124 0 110.142 0.038 ;
    END
  END kv_sh[220]
  PIN kv_sh[221]
    DIRECTION INPUT ;
    USE SIGNAL ;
    PORT
      LAYER M5 ;
        RECT  110.304 0 110.328 0.084 ;
    END
  END kv_sh[221]
  PIN kv_sh[222]
    DIRECTION INPUT ;
    USE SIGNAL ;
    PORT
      LAYER M3 ;
        RECT  110.484 0 110.502 0.038 ;
    END
  END kv_sh[222]
  PIN kv_sh[223]
    DIRECTION INPUT ;
    USE SIGNAL ;
    PORT
      LAYER M5 ;
        RECT  110.64 0 110.664 0.084 ;
    END
  END kv_sh[223]
  PIN kv_sh[224]
    DIRECTION INPUT ;
    USE SIGNAL ;
    PORT
      LAYER M3 ;
        RECT  110.844 0 110.862 0.038 ;
    END
  END kv_sh[224]
  PIN kv_sh[225]
    DIRECTION INPUT ;
    USE SIGNAL ;
    PORT
      LAYER M5 ;
        RECT  111.024 0 111.048 0.084 ;
    END
  END kv_sh[225]
  PIN kv_sh[226]
    DIRECTION INPUT ;
    USE SIGNAL ;
    PORT
      LAYER M3 ;
        RECT  111.204 0 111.222 0.038 ;
    END
  END kv_sh[226]
  PIN kv_sh[227]
    DIRECTION INPUT ;
    USE SIGNAL ;
    PORT
      LAYER M5 ;
        RECT  111.36 0 111.384 0.084 ;
    END
  END kv_sh[227]
  PIN kv_sh[228]
    DIRECTION INPUT ;
    USE SIGNAL ;
    PORT
      LAYER M3 ;
        RECT  111.564 0 111.582 0.038 ;
    END
  END kv_sh[228]
  PIN kv_sh[229]
    DIRECTION INPUT ;
    USE SIGNAL ;
    PORT
      LAYER M5 ;
        RECT  111.744 0 111.768 0.084 ;
    END
  END kv_sh[229]
  PIN kv_sh[22]
    DIRECTION INPUT ;
    USE SIGNAL ;
    PORT
      LAYER M3 ;
        RECT  74.52 0 74.538 0.038 ;
    END
  END kv_sh[22]
  PIN kv_sh[230]
    DIRECTION INPUT ;
    USE SIGNAL ;
    PORT
      LAYER M3 ;
        RECT  111.924 0 111.942 0.038 ;
    END
  END kv_sh[230]
  PIN kv_sh[231]
    DIRECTION INPUT ;
    USE SIGNAL ;
    PORT
      LAYER M5 ;
        RECT  112.08 0 112.104 0.084 ;
    END
  END kv_sh[231]
  PIN kv_sh[232]
    DIRECTION INPUT ;
    USE SIGNAL ;
    PORT
      LAYER M3 ;
        RECT  112.284 0 112.302 0.038 ;
    END
  END kv_sh[232]
  PIN kv_sh[233]
    DIRECTION INPUT ;
    USE SIGNAL ;
    PORT
      LAYER M5 ;
        RECT  112.464 0 112.488 0.084 ;
    END
  END kv_sh[233]
  PIN kv_sh[234]
    DIRECTION INPUT ;
    USE SIGNAL ;
    PORT
      LAYER M3 ;
        RECT  112.644 0 112.662 0.038 ;
    END
  END kv_sh[234]
  PIN kv_sh[235]
    DIRECTION INPUT ;
    USE SIGNAL ;
    PORT
      LAYER M5 ;
        RECT  112.8 0 112.824 0.084 ;
    END
  END kv_sh[235]
  PIN kv_sh[236]
    DIRECTION INPUT ;
    USE SIGNAL ;
    PORT
      LAYER M3 ;
        RECT  113.004 0 113.022 0.038 ;
    END
  END kv_sh[236]
  PIN kv_sh[237]
    DIRECTION INPUT ;
    USE SIGNAL ;
    PORT
      LAYER M5 ;
        RECT  113.184 0 113.208 0.084 ;
    END
  END kv_sh[237]
  PIN kv_sh[238]
    DIRECTION INPUT ;
    USE SIGNAL ;
    PORT
      LAYER M3 ;
        RECT  113.364 0 113.382 0.038 ;
    END
  END kv_sh[238]
  PIN kv_sh[239]
    DIRECTION INPUT ;
    USE SIGNAL ;
    PORT
      LAYER M5 ;
        RECT  113.52 0 113.544 0.084 ;
    END
  END kv_sh[239]
  PIN kv_sh[23]
    DIRECTION INPUT ;
    USE SIGNAL ;
    PORT
      LAYER M5 ;
        RECT  74.688 0 74.712 0.084 ;
    END
  END kv_sh[23]
  PIN kv_sh[240]
    DIRECTION INPUT ;
    USE SIGNAL ;
    PORT
      LAYER M3 ;
        RECT  113.724 0 113.742 0.038 ;
    END
  END kv_sh[240]
  PIN kv_sh[241]
    DIRECTION INPUT ;
    USE SIGNAL ;
    PORT
      LAYER M5 ;
        RECT  113.904 0 113.928 0.084 ;
    END
  END kv_sh[241]
  PIN kv_sh[242]
    DIRECTION INPUT ;
    USE SIGNAL ;
    PORT
      LAYER M3 ;
        RECT  114.048 0 114.066 0.038 ;
    END
  END kv_sh[242]
  PIN kv_sh[243]
    DIRECTION INPUT ;
    USE SIGNAL ;
    PORT
      LAYER M5 ;
        RECT  114.24 0 114.264 0.084 ;
    END
  END kv_sh[243]
  PIN kv_sh[244]
    DIRECTION INPUT ;
    USE SIGNAL ;
    PORT
      LAYER M3 ;
        RECT  114.408 0 114.426 0.038 ;
    END
  END kv_sh[244]
  PIN kv_sh[245]
    DIRECTION INPUT ;
    USE SIGNAL ;
    PORT
      LAYER M5 ;
        RECT  114.624 0 114.648 0.084 ;
    END
  END kv_sh[245]
  PIN kv_sh[246]
    DIRECTION INPUT ;
    USE SIGNAL ;
    PORT
      LAYER M3 ;
        RECT  114.768 0 114.786 0.038 ;
    END
  END kv_sh[246]
  PIN kv_sh[247]
    DIRECTION INPUT ;
    USE SIGNAL ;
    PORT
      LAYER M5 ;
        RECT  114.96 0 114.984 0.084 ;
    END
  END kv_sh[247]
  PIN kv_sh[248]
    DIRECTION INPUT ;
    USE SIGNAL ;
    PORT
      LAYER M3 ;
        RECT  115.128 0 115.146 0.038 ;
    END
  END kv_sh[248]
  PIN kv_sh[249]
    DIRECTION INPUT ;
    USE SIGNAL ;
    PORT
      LAYER M5 ;
        RECT  115.344 0 115.368 0.084 ;
    END
  END kv_sh[249]
  PIN kv_sh[24]
    DIRECTION INPUT ;
    USE SIGNAL ;
    PORT
      LAYER M3 ;
        RECT  74.88 0 74.898 0.038 ;
    END
  END kv_sh[24]
  PIN kv_sh[250]
    DIRECTION INPUT ;
    USE SIGNAL ;
    PORT
      LAYER M3 ;
        RECT  115.488 0 115.506 0.038 ;
    END
  END kv_sh[250]
  PIN kv_sh[251]
    DIRECTION INPUT ;
    USE SIGNAL ;
    PORT
      LAYER M5 ;
        RECT  115.68 0 115.704 0.084 ;
    END
  END kv_sh[251]
  PIN kv_sh[252]
    DIRECTION INPUT ;
    USE SIGNAL ;
    PORT
      LAYER M3 ;
        RECT  115.848 0 115.866 0.038 ;
    END
  END kv_sh[252]
  PIN kv_sh[253]
    DIRECTION INPUT ;
    USE SIGNAL ;
    PORT
      LAYER M5 ;
        RECT  116.016 0 116.04 0.084 ;
    END
  END kv_sh[253]
  PIN kv_sh[254]
    DIRECTION INPUT ;
    USE SIGNAL ;
    PORT
      LAYER M3 ;
        RECT  116.208 0 116.226 0.038 ;
    END
  END kv_sh[254]
  PIN kv_sh[255]
    DIRECTION INPUT ;
    USE SIGNAL ;
    PORT
      LAYER M5 ;
        RECT  116.4 0 116.424 0.084 ;
    END
  END kv_sh[255]
  PIN kv_sh[25]
    DIRECTION INPUT ;
    USE SIGNAL ;
    PORT
      LAYER M5 ;
        RECT  75.072 0 75.096 0.084 ;
    END
  END kv_sh[25]
  PIN kv_sh[26]
    DIRECTION INPUT ;
    USE SIGNAL ;
    PORT
      LAYER M3 ;
        RECT  75.24 0 75.258 0.038 ;
    END
  END kv_sh[26]
  PIN kv_sh[27]
    DIRECTION INPUT ;
    USE SIGNAL ;
    PORT
      LAYER M5 ;
        RECT  75.408 0 75.432 0.084 ;
    END
  END kv_sh[27]
  PIN kv_sh[28]
    DIRECTION INPUT ;
    USE SIGNAL ;
    PORT
      LAYER M3 ;
        RECT  75.6 0 75.618 0.038 ;
    END
  END kv_sh[28]
  PIN kv_sh[29]
    DIRECTION INPUT ;
    USE SIGNAL ;
    PORT
      LAYER M5 ;
        RECT  75.792 0 75.816 0.084 ;
    END
  END kv_sh[29]
  PIN kv_sh[2]
    DIRECTION INPUT ;
    USE SIGNAL ;
    PORT
      LAYER M3 ;
        RECT  70.956 0 70.974 0.038 ;
    END
  END kv_sh[2]
  PIN kv_sh[30]
    DIRECTION INPUT ;
    USE SIGNAL ;
    PORT
      LAYER M3 ;
        RECT  75.96 0 75.978 0.038 ;
    END
  END kv_sh[30]
  PIN kv_sh[31]
    DIRECTION INPUT ;
    USE SIGNAL ;
    PORT
      LAYER M5 ;
        RECT  76.128 0 76.152 0.084 ;
    END
  END kv_sh[31]
  PIN kv_sh[32]
    DIRECTION INPUT ;
    USE SIGNAL ;
    PORT
      LAYER M3 ;
        RECT  76.32 0 76.338 0.038 ;
    END
  END kv_sh[32]
  PIN kv_sh[33]
    DIRECTION INPUT ;
    USE SIGNAL ;
    PORT
      LAYER M5 ;
        RECT  76.512 0 76.536 0.084 ;
    END
  END kv_sh[33]
  PIN kv_sh[34]
    DIRECTION INPUT ;
    USE SIGNAL ;
    PORT
      LAYER M3 ;
        RECT  76.68 0 76.698 0.038 ;
    END
  END kv_sh[34]
  PIN kv_sh[35]
    DIRECTION INPUT ;
    USE SIGNAL ;
    PORT
      LAYER M5 ;
        RECT  76.848 0 76.872 0.084 ;
    END
  END kv_sh[35]
  PIN kv_sh[36]
    DIRECTION INPUT ;
    USE SIGNAL ;
    PORT
      LAYER M3 ;
        RECT  77.04 0 77.058 0.038 ;
    END
  END kv_sh[36]
  PIN kv_sh[37]
    DIRECTION INPUT ;
    USE SIGNAL ;
    PORT
      LAYER M5 ;
        RECT  77.232 0 77.256 0.084 ;
    END
  END kv_sh[37]
  PIN kv_sh[38]
    DIRECTION INPUT ;
    USE SIGNAL ;
    PORT
      LAYER M3 ;
        RECT  77.4 0 77.418 0.038 ;
    END
  END kv_sh[38]
  PIN kv_sh[39]
    DIRECTION INPUT ;
    USE SIGNAL ;
    PORT
      LAYER M5 ;
        RECT  77.568 0 77.592 0.084 ;
    END
  END kv_sh[39]
  PIN kv_sh[3]
    DIRECTION INPUT ;
    USE SIGNAL ;
    PORT
      LAYER M5 ;
        RECT  71.136 0 71.16 0.084 ;
    END
  END kv_sh[3]
  PIN kv_sh[40]
    DIRECTION INPUT ;
    USE SIGNAL ;
    PORT
      LAYER M3 ;
        RECT  77.76 0 77.778 0.038 ;
    END
  END kv_sh[40]
  PIN kv_sh[41]
    DIRECTION INPUT ;
    USE SIGNAL ;
    PORT
      LAYER M5 ;
        RECT  77.952 0 77.976 0.084 ;
    END
  END kv_sh[41]
  PIN kv_sh[42]
    DIRECTION INPUT ;
    USE SIGNAL ;
    PORT
      LAYER M3 ;
        RECT  78.12 0 78.138 0.038 ;
    END
  END kv_sh[42]
  PIN kv_sh[43]
    DIRECTION INPUT ;
    USE SIGNAL ;
    PORT
      LAYER M5 ;
        RECT  78.288 0 78.312 0.084 ;
    END
  END kv_sh[43]
  PIN kv_sh[44]
    DIRECTION INPUT ;
    USE SIGNAL ;
    PORT
      LAYER M3 ;
        RECT  78.48 0 78.498 0.038 ;
    END
  END kv_sh[44]
  PIN kv_sh[45]
    DIRECTION INPUT ;
    USE SIGNAL ;
    PORT
      LAYER M5 ;
        RECT  78.672 0 78.696 0.084 ;
    END
  END kv_sh[45]
  PIN kv_sh[46]
    DIRECTION INPUT ;
    USE SIGNAL ;
    PORT
      LAYER M3 ;
        RECT  78.84 0 78.858 0.038 ;
    END
  END kv_sh[46]
  PIN kv_sh[47]
    DIRECTION INPUT ;
    USE SIGNAL ;
    PORT
      LAYER M5 ;
        RECT  79.008 0 79.032 0.084 ;
    END
  END kv_sh[47]
  PIN kv_sh[48]
    DIRECTION INPUT ;
    USE SIGNAL ;
    PORT
      LAYER M3 ;
        RECT  79.2 0 79.218 0.038 ;
    END
  END kv_sh[48]
  PIN kv_sh[49]
    DIRECTION INPUT ;
    USE SIGNAL ;
    PORT
      LAYER M5 ;
        RECT  79.392 0 79.416 0.084 ;
    END
  END kv_sh[49]
  PIN kv_sh[4]
    DIRECTION INPUT ;
    USE SIGNAL ;
    PORT
      LAYER M3 ;
        RECT  71.316 0 71.334 0.038 ;
    END
  END kv_sh[4]
  PIN kv_sh[50]
    DIRECTION INPUT ;
    USE SIGNAL ;
    PORT
      LAYER M3 ;
        RECT  79.56 0 79.578 0.038 ;
    END
  END kv_sh[50]
  PIN kv_sh[51]
    DIRECTION INPUT ;
    USE SIGNAL ;
    PORT
      LAYER M5 ;
        RECT  79.728 0 79.752 0.084 ;
    END
  END kv_sh[51]
  PIN kv_sh[52]
    DIRECTION INPUT ;
    USE SIGNAL ;
    PORT
      LAYER M3 ;
        RECT  79.92 0 79.938 0.038 ;
    END
  END kv_sh[52]
  PIN kv_sh[53]
    DIRECTION INPUT ;
    USE SIGNAL ;
    PORT
      LAYER M5 ;
        RECT  80.112 0 80.136 0.084 ;
    END
  END kv_sh[53]
  PIN kv_sh[54]
    DIRECTION INPUT ;
    USE SIGNAL ;
    PORT
      LAYER M3 ;
        RECT  80.28 0 80.298 0.038 ;
    END
  END kv_sh[54]
  PIN kv_sh[55]
    DIRECTION INPUT ;
    USE SIGNAL ;
    PORT
      LAYER M5 ;
        RECT  80.448 0 80.472 0.084 ;
    END
  END kv_sh[55]
  PIN kv_sh[56]
    DIRECTION INPUT ;
    USE SIGNAL ;
    PORT
      LAYER M3 ;
        RECT  80.64 0 80.658 0.038 ;
    END
  END kv_sh[56]
  PIN kv_sh[57]
    DIRECTION INPUT ;
    USE SIGNAL ;
    PORT
      LAYER M5 ;
        RECT  80.832 0 80.856 0.084 ;
    END
  END kv_sh[57]
  PIN kv_sh[58]
    DIRECTION INPUT ;
    USE SIGNAL ;
    PORT
      LAYER M3 ;
        RECT  81 0 81.018 0.038 ;
    END
  END kv_sh[58]
  PIN kv_sh[59]
    DIRECTION INPUT ;
    USE SIGNAL ;
    PORT
      LAYER M5 ;
        RECT  81.168 0 81.192 0.084 ;
    END
  END kv_sh[59]
  PIN kv_sh[5]
    DIRECTION INPUT ;
    USE SIGNAL ;
    PORT
      LAYER M5 ;
        RECT  71.472 0 71.496 0.084 ;
    END
  END kv_sh[5]
  PIN kv_sh[60]
    DIRECTION INPUT ;
    USE SIGNAL ;
    PORT
      LAYER M3 ;
        RECT  81.36 0 81.378 0.038 ;
    END
  END kv_sh[60]
  PIN kv_sh[61]
    DIRECTION INPUT ;
    USE SIGNAL ;
    PORT
      LAYER M5 ;
        RECT  81.552 0 81.576 0.084 ;
    END
  END kv_sh[61]
  PIN kv_sh[62]
    DIRECTION INPUT ;
    USE SIGNAL ;
    PORT
      LAYER M3 ;
        RECT  81.72 0 81.738 0.038 ;
    END
  END kv_sh[62]
  PIN kv_sh[63]
    DIRECTION INPUT ;
    USE SIGNAL ;
    PORT
      LAYER M5 ;
        RECT  81.888 0 81.912 0.084 ;
    END
  END kv_sh[63]
  PIN kv_sh[64]
    DIRECTION INPUT ;
    USE SIGNAL ;
    PORT
      LAYER M3 ;
        RECT  82.08 0 82.098 0.038 ;
    END
  END kv_sh[64]
  PIN kv_sh[65]
    DIRECTION INPUT ;
    USE SIGNAL ;
    PORT
      LAYER M5 ;
        RECT  82.272 0 82.296 0.084 ;
    END
  END kv_sh[65]
  PIN kv_sh[66]
    DIRECTION INPUT ;
    USE SIGNAL ;
    PORT
      LAYER M3 ;
        RECT  82.44 0 82.458 0.038 ;
    END
  END kv_sh[66]
  PIN kv_sh[67]
    DIRECTION INPUT ;
    USE SIGNAL ;
    PORT
      LAYER M5 ;
        RECT  82.608 0 82.632 0.084 ;
    END
  END kv_sh[67]
  PIN kv_sh[68]
    DIRECTION INPUT ;
    USE SIGNAL ;
    PORT
      LAYER M3 ;
        RECT  82.8 0 82.818 0.038 ;
    END
  END kv_sh[68]
  PIN kv_sh[69]
    DIRECTION INPUT ;
    USE SIGNAL ;
    PORT
      LAYER M5 ;
        RECT  82.992 0 83.016 0.084 ;
    END
  END kv_sh[69]
  PIN kv_sh[6]
    DIRECTION INPUT ;
    USE SIGNAL ;
    PORT
      LAYER M3 ;
        RECT  71.676 0 71.694 0.038 ;
    END
  END kv_sh[6]
  PIN kv_sh[70]
    DIRECTION INPUT ;
    USE SIGNAL ;
    PORT
      LAYER M3 ;
        RECT  83.16 0 83.178 0.038 ;
    END
  END kv_sh[70]
  PIN kv_sh[71]
    DIRECTION INPUT ;
    USE SIGNAL ;
    PORT
      LAYER M5 ;
        RECT  83.328 0 83.352 0.084 ;
    END
  END kv_sh[71]
  PIN kv_sh[72]
    DIRECTION INPUT ;
    USE SIGNAL ;
    PORT
      LAYER M3 ;
        RECT  83.52 0 83.538 0.038 ;
    END
  END kv_sh[72]
  PIN kv_sh[73]
    DIRECTION INPUT ;
    USE SIGNAL ;
    PORT
      LAYER M5 ;
        RECT  83.712 0 83.736 0.084 ;
    END
  END kv_sh[73]
  PIN kv_sh[74]
    DIRECTION INPUT ;
    USE SIGNAL ;
    PORT
      LAYER M3 ;
        RECT  83.88 0 83.898 0.038 ;
    END
  END kv_sh[74]
  PIN kv_sh[75]
    DIRECTION INPUT ;
    USE SIGNAL ;
    PORT
      LAYER M5 ;
        RECT  84.048 0 84.072 0.084 ;
    END
  END kv_sh[75]
  PIN kv_sh[76]
    DIRECTION INPUT ;
    USE SIGNAL ;
    PORT
      LAYER M3 ;
        RECT  84.24 0 84.258 0.038 ;
    END
  END kv_sh[76]
  PIN kv_sh[77]
    DIRECTION INPUT ;
    USE SIGNAL ;
    PORT
      LAYER M5 ;
        RECT  84.432 0 84.456 0.084 ;
    END
  END kv_sh[77]
  PIN kv_sh[78]
    DIRECTION INPUT ;
    USE SIGNAL ;
    PORT
      LAYER M3 ;
        RECT  84.6 0 84.618 0.038 ;
    END
  END kv_sh[78]
  PIN kv_sh[79]
    DIRECTION INPUT ;
    USE SIGNAL ;
    PORT
      LAYER M5 ;
        RECT  84.768 0 84.792 0.084 ;
    END
  END kv_sh[79]
  PIN kv_sh[7]
    DIRECTION INPUT ;
    USE SIGNAL ;
    PORT
      LAYER M5 ;
        RECT  71.856 0 71.88 0.084 ;
    END
  END kv_sh[7]
  PIN kv_sh[80]
    DIRECTION INPUT ;
    USE SIGNAL ;
    PORT
      LAYER M3 ;
        RECT  84.96 0 84.978 0.038 ;
    END
  END kv_sh[80]
  PIN kv_sh[81]
    DIRECTION INPUT ;
    USE SIGNAL ;
    PORT
      LAYER M5 ;
        RECT  85.152 0 85.176 0.084 ;
    END
  END kv_sh[81]
  PIN kv_sh[82]
    DIRECTION INPUT ;
    USE SIGNAL ;
    PORT
      LAYER M3 ;
        RECT  85.32 0 85.338 0.038 ;
    END
  END kv_sh[82]
  PIN kv_sh[83]
    DIRECTION INPUT ;
    USE SIGNAL ;
    PORT
      LAYER M5 ;
        RECT  85.488 0 85.512 0.084 ;
    END
  END kv_sh[83]
  PIN kv_sh[84]
    DIRECTION INPUT ;
    USE SIGNAL ;
    PORT
      LAYER M3 ;
        RECT  85.68 0 85.698 0.038 ;
    END
  END kv_sh[84]
  PIN kv_sh[85]
    DIRECTION INPUT ;
    USE SIGNAL ;
    PORT
      LAYER M5 ;
        RECT  85.872 0 85.896 0.084 ;
    END
  END kv_sh[85]
  PIN kv_sh[86]
    DIRECTION INPUT ;
    USE SIGNAL ;
    PORT
      LAYER M3 ;
        RECT  86.04 0 86.058 0.038 ;
    END
  END kv_sh[86]
  PIN kv_sh[87]
    DIRECTION INPUT ;
    USE SIGNAL ;
    PORT
      LAYER M5 ;
        RECT  86.208 0 86.232 0.084 ;
    END
  END kv_sh[87]
  PIN kv_sh[88]
    DIRECTION INPUT ;
    USE SIGNAL ;
    PORT
      LAYER M3 ;
        RECT  86.4 0 86.418 0.038 ;
    END
  END kv_sh[88]
  PIN kv_sh[89]
    DIRECTION INPUT ;
    USE SIGNAL ;
    PORT
      LAYER M5 ;
        RECT  86.592 0 86.616 0.084 ;
    END
  END kv_sh[89]
  PIN kv_sh[8]
    DIRECTION INPUT ;
    USE SIGNAL ;
    PORT
      LAYER M3 ;
        RECT  72.036 0 72.054 0.038 ;
    END
  END kv_sh[8]
  PIN kv_sh[90]
    DIRECTION INPUT ;
    USE SIGNAL ;
    PORT
      LAYER M3 ;
        RECT  86.76 0 86.778 0.038 ;
    END
  END kv_sh[90]
  PIN kv_sh[91]
    DIRECTION INPUT ;
    USE SIGNAL ;
    PORT
      LAYER M5 ;
        RECT  86.928 0 86.952 0.084 ;
    END
  END kv_sh[91]
  PIN kv_sh[92]
    DIRECTION INPUT ;
    USE SIGNAL ;
    PORT
      LAYER M3 ;
        RECT  87.12 0 87.138 0.038 ;
    END
  END kv_sh[92]
  PIN kv_sh[93]
    DIRECTION INPUT ;
    USE SIGNAL ;
    PORT
      LAYER M5 ;
        RECT  87.312 0 87.336 0.084 ;
    END
  END kv_sh[93]
  PIN kv_sh[94]
    DIRECTION INPUT ;
    USE SIGNAL ;
    PORT
      LAYER M3 ;
        RECT  87.48 0 87.498 0.038 ;
    END
  END kv_sh[94]
  PIN kv_sh[95]
    DIRECTION INPUT ;
    USE SIGNAL ;
    PORT
      LAYER M5 ;
        RECT  87.648 0 87.672 0.084 ;
    END
  END kv_sh[95]
  PIN kv_sh[96]
    DIRECTION INPUT ;
    USE SIGNAL ;
    PORT
      LAYER M3 ;
        RECT  87.84 0 87.858 0.038 ;
    END
  END kv_sh[96]
  PIN kv_sh[97]
    DIRECTION INPUT ;
    USE SIGNAL ;
    PORT
      LAYER M5 ;
        RECT  88.032 0 88.056 0.084 ;
    END
  END kv_sh[97]
  PIN kv_sh[98]
    DIRECTION INPUT ;
    USE SIGNAL ;
    PORT
      LAYER M3 ;
        RECT  88.2 0 88.218 0.038 ;
    END
  END kv_sh[98]
  PIN kv_sh[99]
    DIRECTION INPUT ;
    USE SIGNAL ;
    PORT
      LAYER M5 ;
        RECT  88.368 0 88.392 0.084 ;
    END
  END kv_sh[99]
  PIN kv_sh[9]
    DIRECTION INPUT ;
    USE SIGNAL ;
    PORT
      LAYER M5 ;
        RECT  72.192 0 72.216 0.084 ;
    END
  END kv_sh[9]
  PIN rs_d[0]
    DIRECTION OUTPUT ;
    USE SIGNAL ;
    PORT
      LAYER M3 ;
        RECT  4.608 43.162 4.626 43.2 ;
    END
  END rs_d[0]
  PIN rs_d[100]
    DIRECTION OUTPUT ;
    USE SIGNAL ;
    PORT
      LAYER M3 ;
        RECT  29.448 43.162 29.466 43.2 ;
    END
  END rs_d[100]
  PIN rs_d[101]
    DIRECTION OUTPUT ;
    USE SIGNAL ;
    PORT
      LAYER M5 ;
        RECT  29.712 43.116 29.736 43.2 ;
    END
  END rs_d[101]
  PIN rs_d[102]
    DIRECTION OUTPUT ;
    USE SIGNAL ;
    PORT
      LAYER M3 ;
        RECT  29.952 43.162 29.97 43.2 ;
    END
  END rs_d[102]
  PIN rs_d[103]
    DIRECTION OUTPUT ;
    USE SIGNAL ;
    PORT
      LAYER M5 ;
        RECT  30.192 43.116 30.216 43.2 ;
    END
  END rs_d[103]
  PIN rs_d[104]
    DIRECTION OUTPUT ;
    USE SIGNAL ;
    PORT
      LAYER M3 ;
        RECT  30.456 43.162 30.474 43.2 ;
    END
  END rs_d[104]
  PIN rs_d[105]
    DIRECTION OUTPUT ;
    USE SIGNAL ;
    PORT
      LAYER M5 ;
        RECT  30.72 43.116 30.744 43.2 ;
    END
  END rs_d[105]
  PIN rs_d[106]
    DIRECTION OUTPUT ;
    USE SIGNAL ;
    PORT
      LAYER M3 ;
        RECT  30.96 43.162 30.978 43.2 ;
    END
  END rs_d[106]
  PIN rs_d[107]
    DIRECTION OUTPUT ;
    USE SIGNAL ;
    PORT
      LAYER M5 ;
        RECT  31.2 43.116 31.224 43.2 ;
    END
  END rs_d[107]
  PIN rs_d[108]
    DIRECTION OUTPUT ;
    USE SIGNAL ;
    PORT
      LAYER M3 ;
        RECT  31.464 43.162 31.482 43.2 ;
    END
  END rs_d[108]
  PIN rs_d[109]
    DIRECTION OUTPUT ;
    USE SIGNAL ;
    PORT
      LAYER M5 ;
        RECT  31.68 43.116 31.704 43.2 ;
    END
  END rs_d[109]
  PIN rs_d[10]
    DIRECTION OUTPUT ;
    USE SIGNAL ;
    PORT
      LAYER M3 ;
        RECT  7.092 43.162 7.11 43.2 ;
    END
  END rs_d[10]
  PIN rs_d[110]
    DIRECTION OUTPUT ;
    USE SIGNAL ;
    PORT
      LAYER M3 ;
        RECT  31.932 43.162 31.95 43.2 ;
    END
  END rs_d[110]
  PIN rs_d[111]
    DIRECTION OUTPUT ;
    USE SIGNAL ;
    PORT
      LAYER M5 ;
        RECT  32.208 43.116 32.232 43.2 ;
    END
  END rs_d[111]
  PIN rs_d[112]
    DIRECTION OUTPUT ;
    USE SIGNAL ;
    PORT
      LAYER M3 ;
        RECT  32.436 43.162 32.454 43.2 ;
    END
  END rs_d[112]
  PIN rs_d[113]
    DIRECTION OUTPUT ;
    USE SIGNAL ;
    PORT
      LAYER M5 ;
        RECT  32.688 43.116 32.712 43.2 ;
    END
  END rs_d[113]
  PIN rs_d[114]
    DIRECTION OUTPUT ;
    USE SIGNAL ;
    PORT
      LAYER M3 ;
        RECT  32.94 43.162 32.958 43.2 ;
    END
  END rs_d[114]
  PIN rs_d[115]
    DIRECTION OUTPUT ;
    USE SIGNAL ;
    PORT
      LAYER M5 ;
        RECT  33.168 43.116 33.192 43.2 ;
    END
  END rs_d[115]
  PIN rs_d[116]
    DIRECTION OUTPUT ;
    USE SIGNAL ;
    PORT
      LAYER M3 ;
        RECT  33.444 43.162 33.462 43.2 ;
    END
  END rs_d[116]
  PIN rs_d[117]
    DIRECTION OUTPUT ;
    USE SIGNAL ;
    PORT
      LAYER M5 ;
        RECT  33.696 43.116 33.72 43.2 ;
    END
  END rs_d[117]
  PIN rs_d[118]
    DIRECTION OUTPUT ;
    USE SIGNAL ;
    PORT
      LAYER M3 ;
        RECT  33.948 43.162 33.966 43.2 ;
    END
  END rs_d[118]
  PIN rs_d[119]
    DIRECTION OUTPUT ;
    USE SIGNAL ;
    PORT
      LAYER M5 ;
        RECT  34.176 43.116 34.2 43.2 ;
    END
  END rs_d[119]
  PIN rs_d[11]
    DIRECTION OUTPUT ;
    USE SIGNAL ;
    PORT
      LAYER M5 ;
        RECT  7.344 43.116 7.368 43.2 ;
    END
  END rs_d[11]
  PIN rs_d[120]
    DIRECTION OUTPUT ;
    USE SIGNAL ;
    PORT
      LAYER M3 ;
        RECT  34.416 43.162 34.434 43.2 ;
    END
  END rs_d[120]
  PIN rs_d[121]
    DIRECTION OUTPUT ;
    USE SIGNAL ;
    PORT
      LAYER M5 ;
        RECT  34.656 43.116 34.68 43.2 ;
    END
  END rs_d[121]
  PIN rs_d[122]
    DIRECTION OUTPUT ;
    USE SIGNAL ;
    PORT
      LAYER M3 ;
        RECT  34.92 43.162 34.938 43.2 ;
    END
  END rs_d[122]
  PIN rs_d[123]
    DIRECTION OUTPUT ;
    USE SIGNAL ;
    PORT
      LAYER M5 ;
        RECT  35.184 43.116 35.208 43.2 ;
    END
  END rs_d[123]
  PIN rs_d[124]
    DIRECTION OUTPUT ;
    USE SIGNAL ;
    PORT
      LAYER M3 ;
        RECT  35.424 43.162 35.442 43.2 ;
    END
  END rs_d[124]
  PIN rs_d[125]
    DIRECTION OUTPUT ;
    USE SIGNAL ;
    PORT
      LAYER M5 ;
        RECT  35.664 43.116 35.688 43.2 ;
    END
  END rs_d[125]
  PIN rs_d[126]
    DIRECTION OUTPUT ;
    USE SIGNAL ;
    PORT
      LAYER M3 ;
        RECT  35.928 43.162 35.946 43.2 ;
    END
  END rs_d[126]
  PIN rs_d[127]
    DIRECTION OUTPUT ;
    USE SIGNAL ;
    PORT
      LAYER M5 ;
        RECT  36.144 43.116 36.168 43.2 ;
    END
  END rs_d[127]
  PIN rs_d[128]
    DIRECTION OUTPUT ;
    USE SIGNAL ;
    PORT
      LAYER M3 ;
        RECT  36.432 43.162 36.45 43.2 ;
    END
  END rs_d[128]
  PIN rs_d[129]
    DIRECTION OUTPUT ;
    USE SIGNAL ;
    PORT
      LAYER M5 ;
        RECT  36.672 43.116 36.696 43.2 ;
    END
  END rs_d[129]
  PIN rs_d[12]
    DIRECTION OUTPUT ;
    USE SIGNAL ;
    PORT
      LAYER M3 ;
        RECT  7.596 43.162 7.614 43.2 ;
    END
  END rs_d[12]
  PIN rs_d[130]
    DIRECTION OUTPUT ;
    USE SIGNAL ;
    PORT
      LAYER M3 ;
        RECT  36.9 43.162 36.918 43.2 ;
    END
  END rs_d[130]
  PIN rs_d[131]
    DIRECTION OUTPUT ;
    USE SIGNAL ;
    PORT
      LAYER M5 ;
        RECT  37.152 43.116 37.176 43.2 ;
    END
  END rs_d[131]
  PIN rs_d[132]
    DIRECTION OUTPUT ;
    USE SIGNAL ;
    PORT
      LAYER M3 ;
        RECT  37.404 43.162 37.422 43.2 ;
    END
  END rs_d[132]
  PIN rs_d[133]
    DIRECTION OUTPUT ;
    USE SIGNAL ;
    PORT
      LAYER M5 ;
        RECT  37.632 43.116 37.656 43.2 ;
    END
  END rs_d[133]
  PIN rs_d[134]
    DIRECTION OUTPUT ;
    USE SIGNAL ;
    PORT
      LAYER M3 ;
        RECT  37.908 43.162 37.926 43.2 ;
    END
  END rs_d[134]
  PIN rs_d[135]
    DIRECTION OUTPUT ;
    USE SIGNAL ;
    PORT
      LAYER M5 ;
        RECT  38.16 43.116 38.184 43.2 ;
    END
  END rs_d[135]
  PIN rs_d[136]
    DIRECTION OUTPUT ;
    USE SIGNAL ;
    PORT
      LAYER M3 ;
        RECT  38.412 43.162 38.43 43.2 ;
    END
  END rs_d[136]
  PIN rs_d[137]
    DIRECTION OUTPUT ;
    USE SIGNAL ;
    PORT
      LAYER M5 ;
        RECT  38.64 43.116 38.664 43.2 ;
    END
  END rs_d[137]
  PIN rs_d[138]
    DIRECTION OUTPUT ;
    USE SIGNAL ;
    PORT
      LAYER M3 ;
        RECT  38.916 43.162 38.934 43.2 ;
    END
  END rs_d[138]
  PIN rs_d[139]
    DIRECTION OUTPUT ;
    USE SIGNAL ;
    PORT
      LAYER M5 ;
        RECT  39.168 43.116 39.192 43.2 ;
    END
  END rs_d[139]
  PIN rs_d[13]
    DIRECTION OUTPUT ;
    USE SIGNAL ;
    PORT
      LAYER M5 ;
        RECT  7.824 43.116 7.848 43.2 ;
    END
  END rs_d[13]
  PIN rs_d[140]
    DIRECTION OUTPUT ;
    USE SIGNAL ;
    PORT
      LAYER M3 ;
        RECT  39.384 43.162 39.402 43.2 ;
    END
  END rs_d[140]
  PIN rs_d[141]
    DIRECTION OUTPUT ;
    USE SIGNAL ;
    PORT
      LAYER M5 ;
        RECT  39.648 43.116 39.672 43.2 ;
    END
  END rs_d[141]
  PIN rs_d[142]
    DIRECTION OUTPUT ;
    USE SIGNAL ;
    PORT
      LAYER M3 ;
        RECT  39.888 43.162 39.906 43.2 ;
    END
  END rs_d[142]
  PIN rs_d[143]
    DIRECTION OUTPUT ;
    USE SIGNAL ;
    PORT
      LAYER M5 ;
        RECT  40.128 43.116 40.152 43.2 ;
    END
  END rs_d[143]
  PIN rs_d[144]
    DIRECTION OUTPUT ;
    USE SIGNAL ;
    PORT
      LAYER M3 ;
        RECT  40.392 43.162 40.41 43.2 ;
    END
  END rs_d[144]
  PIN rs_d[145]
    DIRECTION OUTPUT ;
    USE SIGNAL ;
    PORT
      LAYER M5 ;
        RECT  40.656 43.116 40.68 43.2 ;
    END
  END rs_d[145]
  PIN rs_d[146]
    DIRECTION OUTPUT ;
    USE SIGNAL ;
    PORT
      LAYER M3 ;
        RECT  40.896 43.162 40.914 43.2 ;
    END
  END rs_d[146]
  PIN rs_d[147]
    DIRECTION OUTPUT ;
    USE SIGNAL ;
    PORT
      LAYER M5 ;
        RECT  41.136 43.116 41.16 43.2 ;
    END
  END rs_d[147]
  PIN rs_d[148]
    DIRECTION OUTPUT ;
    USE SIGNAL ;
    PORT
      LAYER M3 ;
        RECT  41.4 43.162 41.418 43.2 ;
    END
  END rs_d[148]
  PIN rs_d[149]
    DIRECTION OUTPUT ;
    USE SIGNAL ;
    PORT
      LAYER M5 ;
        RECT  41.616 43.116 41.64 43.2 ;
    END
  END rs_d[149]
  PIN rs_d[14]
    DIRECTION OUTPUT ;
    USE SIGNAL ;
    PORT
      LAYER M3 ;
        RECT  8.1 43.162 8.118 43.2 ;
    END
  END rs_d[14]
  PIN rs_d[150]
    DIRECTION OUTPUT ;
    USE SIGNAL ;
    PORT
      LAYER M3 ;
        RECT  41.868 43.162 41.886 43.2 ;
    END
  END rs_d[150]
  PIN rs_d[151]
    DIRECTION OUTPUT ;
    USE SIGNAL ;
    PORT
      LAYER M5 ;
        RECT  42.144 43.116 42.168 43.2 ;
    END
  END rs_d[151]
  PIN rs_d[152]
    DIRECTION OUTPUT ;
    USE SIGNAL ;
    PORT
      LAYER M3 ;
        RECT  42.372 43.162 42.39 43.2 ;
    END
  END rs_d[152]
  PIN rs_d[153]
    DIRECTION OUTPUT ;
    USE SIGNAL ;
    PORT
      LAYER M5 ;
        RECT  42.624 43.116 42.648 43.2 ;
    END
  END rs_d[153]
  PIN rs_d[154]
    DIRECTION OUTPUT ;
    USE SIGNAL ;
    PORT
      LAYER M3 ;
        RECT  42.876 43.162 42.894 43.2 ;
    END
  END rs_d[154]
  PIN rs_d[155]
    DIRECTION OUTPUT ;
    USE SIGNAL ;
    PORT
      LAYER M5 ;
        RECT  43.104 43.116 43.128 43.2 ;
    END
  END rs_d[155]
  PIN rs_d[156]
    DIRECTION OUTPUT ;
    USE SIGNAL ;
    PORT
      LAYER M3 ;
        RECT  43.38 43.162 43.398 43.2 ;
    END
  END rs_d[156]
  PIN rs_d[157]
    DIRECTION OUTPUT ;
    USE SIGNAL ;
    PORT
      LAYER M5 ;
        RECT  43.632 43.116 43.656 43.2 ;
    END
  END rs_d[157]
  PIN rs_d[158]
    DIRECTION OUTPUT ;
    USE SIGNAL ;
    PORT
      LAYER M3 ;
        RECT  43.884 43.162 43.902 43.2 ;
    END
  END rs_d[158]
  PIN rs_d[159]
    DIRECTION OUTPUT ;
    USE SIGNAL ;
    PORT
      LAYER M5 ;
        RECT  44.112 43.116 44.136 43.2 ;
    END
  END rs_d[159]
  PIN rs_d[15]
    DIRECTION OUTPUT ;
    USE SIGNAL ;
    PORT
      LAYER M5 ;
        RECT  8.352 43.116 8.376 43.2 ;
    END
  END rs_d[15]
  PIN rs_d[160]
    DIRECTION OUTPUT ;
    USE SIGNAL ;
    PORT
      LAYER M3 ;
        RECT  44.352 43.162 44.37 43.2 ;
    END
  END rs_d[160]
  PIN rs_d[161]
    DIRECTION OUTPUT ;
    USE SIGNAL ;
    PORT
      LAYER M5 ;
        RECT  44.592 43.116 44.616 43.2 ;
    END
  END rs_d[161]
  PIN rs_d[162]
    DIRECTION OUTPUT ;
    USE SIGNAL ;
    PORT
      LAYER M3 ;
        RECT  44.856 43.162 44.874 43.2 ;
    END
  END rs_d[162]
  PIN rs_d[163]
    DIRECTION OUTPUT ;
    USE SIGNAL ;
    PORT
      LAYER M5 ;
        RECT  45.12 43.116 45.144 43.2 ;
    END
  END rs_d[163]
  PIN rs_d[164]
    DIRECTION OUTPUT ;
    USE SIGNAL ;
    PORT
      LAYER M3 ;
        RECT  45.36 43.162 45.378 43.2 ;
    END
  END rs_d[164]
  PIN rs_d[165]
    DIRECTION OUTPUT ;
    USE SIGNAL ;
    PORT
      LAYER M5 ;
        RECT  45.6 43.116 45.624 43.2 ;
    END
  END rs_d[165]
  PIN rs_d[166]
    DIRECTION OUTPUT ;
    USE SIGNAL ;
    PORT
      LAYER M3 ;
        RECT  45.864 43.162 45.882 43.2 ;
    END
  END rs_d[166]
  PIN rs_d[167]
    DIRECTION OUTPUT ;
    USE SIGNAL ;
    PORT
      LAYER M5 ;
        RECT  46.08 43.116 46.104 43.2 ;
    END
  END rs_d[167]
  PIN rs_d[168]
    DIRECTION OUTPUT ;
    USE SIGNAL ;
    PORT
      LAYER M3 ;
        RECT  46.368 43.162 46.386 43.2 ;
    END
  END rs_d[168]
  PIN rs_d[169]
    DIRECTION OUTPUT ;
    USE SIGNAL ;
    PORT
      LAYER M5 ;
        RECT  46.608 43.116 46.632 43.2 ;
    END
  END rs_d[169]
  PIN rs_d[16]
    DIRECTION OUTPUT ;
    USE SIGNAL ;
    PORT
      LAYER M3 ;
        RECT  8.604 43.162 8.622 43.2 ;
    END
  END rs_d[16]
  PIN rs_d[170]
    DIRECTION OUTPUT ;
    USE SIGNAL ;
    PORT
      LAYER M3 ;
        RECT  46.836 43.162 46.854 43.2 ;
    END
  END rs_d[170]
  PIN rs_d[171]
    DIRECTION OUTPUT ;
    USE SIGNAL ;
    PORT
      LAYER M5 ;
        RECT  47.088 43.116 47.112 43.2 ;
    END
  END rs_d[171]
  PIN rs_d[172]
    DIRECTION OUTPUT ;
    USE SIGNAL ;
    PORT
      LAYER M3 ;
        RECT  47.34 43.162 47.358 43.2 ;
    END
  END rs_d[172]
  PIN rs_d[173]
    DIRECTION OUTPUT ;
    USE SIGNAL ;
    PORT
      LAYER M5 ;
        RECT  47.616 43.116 47.64 43.2 ;
    END
  END rs_d[173]
  PIN rs_d[174]
    DIRECTION OUTPUT ;
    USE SIGNAL ;
    PORT
      LAYER M3 ;
        RECT  47.844 43.162 47.862 43.2 ;
    END
  END rs_d[174]
  PIN rs_d[175]
    DIRECTION OUTPUT ;
    USE SIGNAL ;
    PORT
      LAYER M5 ;
        RECT  48.096 43.116 48.12 43.2 ;
    END
  END rs_d[175]
  PIN rs_d[176]
    DIRECTION OUTPUT ;
    USE SIGNAL ;
    PORT
      LAYER M3 ;
        RECT  48.348 43.162 48.366 43.2 ;
    END
  END rs_d[176]
  PIN rs_d[177]
    DIRECTION OUTPUT ;
    USE SIGNAL ;
    PORT
      LAYER M5 ;
        RECT  48.576 43.116 48.6 43.2 ;
    END
  END rs_d[177]
  PIN rs_d[178]
    DIRECTION OUTPUT ;
    USE SIGNAL ;
    PORT
      LAYER M3 ;
        RECT  48.852 43.162 48.87 43.2 ;
    END
  END rs_d[178]
  PIN rs_d[179]
    DIRECTION OUTPUT ;
    USE SIGNAL ;
    PORT
      LAYER M5 ;
        RECT  49.104 43.116 49.128 43.2 ;
    END
  END rs_d[179]
  PIN rs_d[17]
    DIRECTION OUTPUT ;
    USE SIGNAL ;
    PORT
      LAYER M5 ;
        RECT  8.832 43.116 8.856 43.2 ;
    END
  END rs_d[17]
  PIN rs_d[180]
    DIRECTION OUTPUT ;
    USE SIGNAL ;
    PORT
      LAYER M3 ;
        RECT  49.32 43.162 49.338 43.2 ;
    END
  END rs_d[180]
  PIN rs_d[181]
    DIRECTION OUTPUT ;
    USE SIGNAL ;
    PORT
      LAYER M5 ;
        RECT  49.584 43.116 49.608 43.2 ;
    END
  END rs_d[181]
  PIN rs_d[182]
    DIRECTION OUTPUT ;
    USE SIGNAL ;
    PORT
      LAYER M3 ;
        RECT  49.824 43.162 49.842 43.2 ;
    END
  END rs_d[182]
  PIN rs_d[183]
    DIRECTION OUTPUT ;
    USE SIGNAL ;
    PORT
      LAYER M5 ;
        RECT  50.064 43.116 50.088 43.2 ;
    END
  END rs_d[183]
  PIN rs_d[184]
    DIRECTION OUTPUT ;
    USE SIGNAL ;
    PORT
      LAYER M3 ;
        RECT  50.328 43.162 50.346 43.2 ;
    END
  END rs_d[184]
  PIN rs_d[185]
    DIRECTION OUTPUT ;
    USE SIGNAL ;
    PORT
      LAYER M5 ;
        RECT  50.592 43.116 50.616 43.2 ;
    END
  END rs_d[185]
  PIN rs_d[186]
    DIRECTION OUTPUT ;
    USE SIGNAL ;
    PORT
      LAYER M3 ;
        RECT  50.832 43.162 50.85 43.2 ;
    END
  END rs_d[186]
  PIN rs_d[187]
    DIRECTION OUTPUT ;
    USE SIGNAL ;
    PORT
      LAYER M5 ;
        RECT  51.072 43.116 51.096 43.2 ;
    END
  END rs_d[187]
  PIN rs_d[188]
    DIRECTION OUTPUT ;
    USE SIGNAL ;
    PORT
      LAYER M3 ;
        RECT  51.336 43.162 51.354 43.2 ;
    END
  END rs_d[188]
  PIN rs_d[189]
    DIRECTION OUTPUT ;
    USE SIGNAL ;
    PORT
      LAYER M5 ;
        RECT  51.552 43.116 51.576 43.2 ;
    END
  END rs_d[189]
  PIN rs_d[18]
    DIRECTION OUTPUT ;
    USE SIGNAL ;
    PORT
      LAYER M3 ;
        RECT  9.072 43.162 9.09 43.2 ;
    END
  END rs_d[18]
  PIN rs_d[190]
    DIRECTION OUTPUT ;
    USE SIGNAL ;
    PORT
      LAYER M3 ;
        RECT  51.804 43.162 51.822 43.2 ;
    END
  END rs_d[190]
  PIN rs_d[191]
    DIRECTION OUTPUT ;
    USE SIGNAL ;
    PORT
      LAYER M5 ;
        RECT  52.08 43.116 52.104 43.2 ;
    END
  END rs_d[191]
  PIN rs_d[192]
    DIRECTION OUTPUT ;
    USE SIGNAL ;
    PORT
      LAYER M3 ;
        RECT  52.308 43.162 52.326 43.2 ;
    END
  END rs_d[192]
  PIN rs_d[193]
    DIRECTION OUTPUT ;
    USE SIGNAL ;
    PORT
      LAYER M5 ;
        RECT  52.56 43.116 52.584 43.2 ;
    END
  END rs_d[193]
  PIN rs_d[194]
    DIRECTION OUTPUT ;
    USE SIGNAL ;
    PORT
      LAYER M3 ;
        RECT  52.812 43.162 52.83 43.2 ;
    END
  END rs_d[194]
  PIN rs_d[195]
    DIRECTION OUTPUT ;
    USE SIGNAL ;
    PORT
      LAYER M5 ;
        RECT  53.04 43.116 53.064 43.2 ;
    END
  END rs_d[195]
  PIN rs_d[196]
    DIRECTION OUTPUT ;
    USE SIGNAL ;
    PORT
      LAYER M3 ;
        RECT  53.316 43.162 53.334 43.2 ;
    END
  END rs_d[196]
  PIN rs_d[197]
    DIRECTION OUTPUT ;
    USE SIGNAL ;
    PORT
      LAYER M5 ;
        RECT  53.568 43.116 53.592 43.2 ;
    END
  END rs_d[197]
  PIN rs_d[198]
    DIRECTION OUTPUT ;
    USE SIGNAL ;
    PORT
      LAYER M3 ;
        RECT  53.82 43.162 53.838 43.2 ;
    END
  END rs_d[198]
  PIN rs_d[199]
    DIRECTION OUTPUT ;
    USE SIGNAL ;
    PORT
      LAYER M5 ;
        RECT  54.048 43.116 54.072 43.2 ;
    END
  END rs_d[199]
  PIN rs_d[19]
    DIRECTION OUTPUT ;
    USE SIGNAL ;
    PORT
      LAYER M5 ;
        RECT  9.312 43.116 9.336 43.2 ;
    END
  END rs_d[19]
  PIN rs_d[1]
    DIRECTION OUTPUT ;
    USE SIGNAL ;
    PORT
      LAYER M5 ;
        RECT  4.848 43.116 4.872 43.2 ;
    END
  END rs_d[1]
  PIN rs_d[200]
    DIRECTION OUTPUT ;
    USE SIGNAL ;
    PORT
      LAYER M3 ;
        RECT  54.288 43.162 54.306 43.2 ;
    END
  END rs_d[200]
  PIN rs_d[201]
    DIRECTION OUTPUT ;
    USE SIGNAL ;
    PORT
      LAYER M5 ;
        RECT  54.528 43.116 54.552 43.2 ;
    END
  END rs_d[201]
  PIN rs_d[202]
    DIRECTION OUTPUT ;
    USE SIGNAL ;
    PORT
      LAYER M3 ;
        RECT  54.792 43.162 54.81 43.2 ;
    END
  END rs_d[202]
  PIN rs_d[203]
    DIRECTION OUTPUT ;
    USE SIGNAL ;
    PORT
      LAYER M5 ;
        RECT  55.056 43.116 55.08 43.2 ;
    END
  END rs_d[203]
  PIN rs_d[204]
    DIRECTION OUTPUT ;
    USE SIGNAL ;
    PORT
      LAYER M3 ;
        RECT  55.296 43.162 55.314 43.2 ;
    END
  END rs_d[204]
  PIN rs_d[205]
    DIRECTION OUTPUT ;
    USE SIGNAL ;
    PORT
      LAYER M5 ;
        RECT  55.536 43.116 55.56 43.2 ;
    END
  END rs_d[205]
  PIN rs_d[206]
    DIRECTION OUTPUT ;
    USE SIGNAL ;
    PORT
      LAYER M3 ;
        RECT  55.8 43.162 55.818 43.2 ;
    END
  END rs_d[206]
  PIN rs_d[207]
    DIRECTION OUTPUT ;
    USE SIGNAL ;
    PORT
      LAYER M5 ;
        RECT  56.016 43.116 56.04 43.2 ;
    END
  END rs_d[207]
  PIN rs_d[208]
    DIRECTION OUTPUT ;
    USE SIGNAL ;
    PORT
      LAYER M3 ;
        RECT  56.304 43.162 56.322 43.2 ;
    END
  END rs_d[208]
  PIN rs_d[209]
    DIRECTION OUTPUT ;
    USE SIGNAL ;
    PORT
      LAYER M5 ;
        RECT  56.544 43.116 56.568 43.2 ;
    END
  END rs_d[209]
  PIN rs_d[20]
    DIRECTION OUTPUT ;
    USE SIGNAL ;
    PORT
      LAYER M3 ;
        RECT  9.576 43.162 9.594 43.2 ;
    END
  END rs_d[20]
  PIN rs_d[210]
    DIRECTION OUTPUT ;
    USE SIGNAL ;
    PORT
      LAYER M3 ;
        RECT  56.772 43.162 56.79 43.2 ;
    END
  END rs_d[210]
  PIN rs_d[211]
    DIRECTION OUTPUT ;
    USE SIGNAL ;
    PORT
      LAYER M5 ;
        RECT  57.024 43.116 57.048 43.2 ;
    END
  END rs_d[211]
  PIN rs_d[212]
    DIRECTION OUTPUT ;
    USE SIGNAL ;
    PORT
      LAYER M3 ;
        RECT  57.276 43.162 57.294 43.2 ;
    END
  END rs_d[212]
  PIN rs_d[213]
    DIRECTION OUTPUT ;
    USE SIGNAL ;
    PORT
      LAYER M5 ;
        RECT  57.552 43.116 57.576 43.2 ;
    END
  END rs_d[213]
  PIN rs_d[214]
    DIRECTION OUTPUT ;
    USE SIGNAL ;
    PORT
      LAYER M3 ;
        RECT  57.78 43.162 57.798 43.2 ;
    END
  END rs_d[214]
  PIN rs_d[215]
    DIRECTION OUTPUT ;
    USE SIGNAL ;
    PORT
      LAYER M5 ;
        RECT  58.032 43.116 58.056 43.2 ;
    END
  END rs_d[215]
  PIN rs_d[216]
    DIRECTION OUTPUT ;
    USE SIGNAL ;
    PORT
      LAYER M3 ;
        RECT  58.284 43.162 58.302 43.2 ;
    END
  END rs_d[216]
  PIN rs_d[217]
    DIRECTION OUTPUT ;
    USE SIGNAL ;
    PORT
      LAYER M5 ;
        RECT  58.512 43.116 58.536 43.2 ;
    END
  END rs_d[217]
  PIN rs_d[218]
    DIRECTION OUTPUT ;
    USE SIGNAL ;
    PORT
      LAYER M3 ;
        RECT  58.788 43.162 58.806 43.2 ;
    END
  END rs_d[218]
  PIN rs_d[219]
    DIRECTION OUTPUT ;
    USE SIGNAL ;
    PORT
      LAYER M5 ;
        RECT  59.04 43.116 59.064 43.2 ;
    END
  END rs_d[219]
  PIN rs_d[21]
    DIRECTION OUTPUT ;
    USE SIGNAL ;
    PORT
      LAYER M5 ;
        RECT  9.84 43.116 9.864 43.2 ;
    END
  END rs_d[21]
  PIN rs_d[220]
    DIRECTION OUTPUT ;
    USE SIGNAL ;
    PORT
      LAYER M3 ;
        RECT  59.256 43.162 59.274 43.2 ;
    END
  END rs_d[220]
  PIN rs_d[221]
    DIRECTION OUTPUT ;
    USE SIGNAL ;
    PORT
      LAYER M5 ;
        RECT  59.52 43.116 59.544 43.2 ;
    END
  END rs_d[221]
  PIN rs_d[222]
    DIRECTION OUTPUT ;
    USE SIGNAL ;
    PORT
      LAYER M3 ;
        RECT  59.76 43.162 59.778 43.2 ;
    END
  END rs_d[222]
  PIN rs_d[223]
    DIRECTION OUTPUT ;
    USE SIGNAL ;
    PORT
      LAYER M5 ;
        RECT  60 43.116 60.024 43.2 ;
    END
  END rs_d[223]
  PIN rs_d[224]
    DIRECTION OUTPUT ;
    USE SIGNAL ;
    PORT
      LAYER M3 ;
        RECT  60.264 43.162 60.282 43.2 ;
    END
  END rs_d[224]
  PIN rs_d[225]
    DIRECTION OUTPUT ;
    USE SIGNAL ;
    PORT
      LAYER M5 ;
        RECT  60.528 43.116 60.552 43.2 ;
    END
  END rs_d[225]
  PIN rs_d[226]
    DIRECTION OUTPUT ;
    USE SIGNAL ;
    PORT
      LAYER M3 ;
        RECT  60.768 43.162 60.786 43.2 ;
    END
  END rs_d[226]
  PIN rs_d[227]
    DIRECTION OUTPUT ;
    USE SIGNAL ;
    PORT
      LAYER M5 ;
        RECT  61.008 43.116 61.032 43.2 ;
    END
  END rs_d[227]
  PIN rs_d[228]
    DIRECTION OUTPUT ;
    USE SIGNAL ;
    PORT
      LAYER M3 ;
        RECT  61.272 43.162 61.29 43.2 ;
    END
  END rs_d[228]
  PIN rs_d[229]
    DIRECTION OUTPUT ;
    USE SIGNAL ;
    PORT
      LAYER M5 ;
        RECT  61.488 43.116 61.512 43.2 ;
    END
  END rs_d[229]
  PIN rs_d[22]
    DIRECTION OUTPUT ;
    USE SIGNAL ;
    PORT
      LAYER M3 ;
        RECT  10.08 43.162 10.098 43.2 ;
    END
  END rs_d[22]
  PIN rs_d[230]
    DIRECTION OUTPUT ;
    USE SIGNAL ;
    PORT
      LAYER M3 ;
        RECT  61.74 43.162 61.758 43.2 ;
    END
  END rs_d[230]
  PIN rs_d[231]
    DIRECTION OUTPUT ;
    USE SIGNAL ;
    PORT
      LAYER M5 ;
        RECT  62.016 43.116 62.04 43.2 ;
    END
  END rs_d[231]
  PIN rs_d[232]
    DIRECTION OUTPUT ;
    USE SIGNAL ;
    PORT
      LAYER M3 ;
        RECT  62.244 43.162 62.262 43.2 ;
    END
  END rs_d[232]
  PIN rs_d[233]
    DIRECTION OUTPUT ;
    USE SIGNAL ;
    PORT
      LAYER M5 ;
        RECT  62.496 43.116 62.52 43.2 ;
    END
  END rs_d[233]
  PIN rs_d[234]
    DIRECTION OUTPUT ;
    USE SIGNAL ;
    PORT
      LAYER M3 ;
        RECT  62.748 43.162 62.766 43.2 ;
    END
  END rs_d[234]
  PIN rs_d[235]
    DIRECTION OUTPUT ;
    USE SIGNAL ;
    PORT
      LAYER M5 ;
        RECT  62.976 43.116 63 43.2 ;
    END
  END rs_d[235]
  PIN rs_d[236]
    DIRECTION OUTPUT ;
    USE SIGNAL ;
    PORT
      LAYER M3 ;
        RECT  63.252 43.162 63.27 43.2 ;
    END
  END rs_d[236]
  PIN rs_d[237]
    DIRECTION OUTPUT ;
    USE SIGNAL ;
    PORT
      LAYER M5 ;
        RECT  63.504 43.116 63.528 43.2 ;
    END
  END rs_d[237]
  PIN rs_d[238]
    DIRECTION OUTPUT ;
    USE SIGNAL ;
    PORT
      LAYER M3 ;
        RECT  63.756 43.162 63.774 43.2 ;
    END
  END rs_d[238]
  PIN rs_d[239]
    DIRECTION OUTPUT ;
    USE SIGNAL ;
    PORT
      LAYER M5 ;
        RECT  63.984 43.116 64.008 43.2 ;
    END
  END rs_d[239]
  PIN rs_d[23]
    DIRECTION OUTPUT ;
    USE SIGNAL ;
    PORT
      LAYER M5 ;
        RECT  10.32 43.116 10.344 43.2 ;
    END
  END rs_d[23]
  PIN rs_d[240]
    DIRECTION OUTPUT ;
    USE SIGNAL ;
    PORT
      LAYER M3 ;
        RECT  64.224 43.162 64.242 43.2 ;
    END
  END rs_d[240]
  PIN rs_d[241]
    DIRECTION OUTPUT ;
    USE SIGNAL ;
    PORT
      LAYER M5 ;
        RECT  64.464 43.116 64.488 43.2 ;
    END
  END rs_d[241]
  PIN rs_d[242]
    DIRECTION OUTPUT ;
    USE SIGNAL ;
    PORT
      LAYER M3 ;
        RECT  64.728 43.162 64.746 43.2 ;
    END
  END rs_d[242]
  PIN rs_d[243]
    DIRECTION OUTPUT ;
    USE SIGNAL ;
    PORT
      LAYER M5 ;
        RECT  64.992 43.116 65.016 43.2 ;
    END
  END rs_d[243]
  PIN rs_d[244]
    DIRECTION OUTPUT ;
    USE SIGNAL ;
    PORT
      LAYER M3 ;
        RECT  65.232 43.162 65.25 43.2 ;
    END
  END rs_d[244]
  PIN rs_d[245]
    DIRECTION OUTPUT ;
    USE SIGNAL ;
    PORT
      LAYER M5 ;
        RECT  65.472 43.116 65.496 43.2 ;
    END
  END rs_d[245]
  PIN rs_d[246]
    DIRECTION OUTPUT ;
    USE SIGNAL ;
    PORT
      LAYER M3 ;
        RECT  65.736 43.162 65.754 43.2 ;
    END
  END rs_d[246]
  PIN rs_d[247]
    DIRECTION OUTPUT ;
    USE SIGNAL ;
    PORT
      LAYER M5 ;
        RECT  66 43.116 66.024 43.2 ;
    END
  END rs_d[247]
  PIN rs_d[248]
    DIRECTION OUTPUT ;
    USE SIGNAL ;
    PORT
      LAYER M3 ;
        RECT  66.24 43.162 66.258 43.2 ;
    END
  END rs_d[248]
  PIN rs_d[249]
    DIRECTION OUTPUT ;
    USE SIGNAL ;
    PORT
      LAYER M5 ;
        RECT  66.48 43.116 66.504 43.2 ;
    END
  END rs_d[249]
  PIN rs_d[24]
    DIRECTION OUTPUT ;
    USE SIGNAL ;
    PORT
      LAYER M3 ;
        RECT  10.584 43.162 10.602 43.2 ;
    END
  END rs_d[24]
  PIN rs_d[250]
    DIRECTION OUTPUT ;
    USE SIGNAL ;
    PORT
      LAYER M3 ;
        RECT  66.708 43.162 66.726 43.2 ;
    END
  END rs_d[250]
  PIN rs_d[251]
    DIRECTION OUTPUT ;
    USE SIGNAL ;
    PORT
      LAYER M5 ;
        RECT  66.96 43.116 66.984 43.2 ;
    END
  END rs_d[251]
  PIN rs_d[252]
    DIRECTION OUTPUT ;
    USE SIGNAL ;
    PORT
      LAYER M3 ;
        RECT  67.212 43.162 67.23 43.2 ;
    END
  END rs_d[252]
  PIN rs_d[253]
    DIRECTION OUTPUT ;
    USE SIGNAL ;
    PORT
      LAYER M5 ;
        RECT  67.488 43.116 67.512 43.2 ;
    END
  END rs_d[253]
  PIN rs_d[254]
    DIRECTION OUTPUT ;
    USE SIGNAL ;
    PORT
      LAYER M3 ;
        RECT  67.716 43.162 67.734 43.2 ;
    END
  END rs_d[254]
  PIN rs_d[255]
    DIRECTION OUTPUT ;
    USE SIGNAL ;
    PORT
      LAYER M5 ;
        RECT  67.968 43.116 67.992 43.2 ;
    END
  END rs_d[255]
  PIN rs_d[256]
    DIRECTION OUTPUT ;
    USE SIGNAL ;
    PORT
      LAYER M3 ;
        RECT  68.22 43.162 68.238 43.2 ;
    END
  END rs_d[256]
  PIN rs_d[257]
    DIRECTION OUTPUT ;
    USE SIGNAL ;
    PORT
      LAYER M5 ;
        RECT  68.448 43.116 68.472 43.2 ;
    END
  END rs_d[257]
  PIN rs_d[258]
    DIRECTION OUTPUT ;
    USE SIGNAL ;
    PORT
      LAYER M3 ;
        RECT  68.724 43.162 68.742 43.2 ;
    END
  END rs_d[258]
  PIN rs_d[259]
    DIRECTION OUTPUT ;
    USE SIGNAL ;
    PORT
      LAYER M5 ;
        RECT  68.976 43.116 69 43.2 ;
    END
  END rs_d[259]
  PIN rs_d[25]
    DIRECTION OUTPUT ;
    USE SIGNAL ;
    PORT
      LAYER M5 ;
        RECT  10.8 43.116 10.824 43.2 ;
    END
  END rs_d[25]
  PIN rs_d[260]
    DIRECTION OUTPUT ;
    USE SIGNAL ;
    PORT
      LAYER M3 ;
        RECT  69.192 43.162 69.21 43.2 ;
    END
  END rs_d[260]
  PIN rs_d[261]
    DIRECTION OUTPUT ;
    USE SIGNAL ;
    PORT
      LAYER M5 ;
        RECT  69.456 43.116 69.48 43.2 ;
    END
  END rs_d[261]
  PIN rs_d[262]
    DIRECTION OUTPUT ;
    USE SIGNAL ;
    PORT
      LAYER M3 ;
        RECT  69.696 43.162 69.714 43.2 ;
    END
  END rs_d[262]
  PIN rs_d[263]
    DIRECTION OUTPUT ;
    USE SIGNAL ;
    PORT
      LAYER M5 ;
        RECT  69.936 43.116 69.96 43.2 ;
    END
  END rs_d[263]
  PIN rs_d[264]
    DIRECTION OUTPUT ;
    USE SIGNAL ;
    PORT
      LAYER M3 ;
        RECT  70.2 43.162 70.218 43.2 ;
    END
  END rs_d[264]
  PIN rs_d[265]
    DIRECTION OUTPUT ;
    USE SIGNAL ;
    PORT
      LAYER M5 ;
        RECT  70.464 43.116 70.488 43.2 ;
    END
  END rs_d[265]
  PIN rs_d[266]
    DIRECTION OUTPUT ;
    USE SIGNAL ;
    PORT
      LAYER M3 ;
        RECT  70.704 43.162 70.722 43.2 ;
    END
  END rs_d[266]
  PIN rs_d[267]
    DIRECTION OUTPUT ;
    USE SIGNAL ;
    PORT
      LAYER M5 ;
        RECT  70.944 43.116 70.968 43.2 ;
    END
  END rs_d[267]
  PIN rs_d[268]
    DIRECTION OUTPUT ;
    USE SIGNAL ;
    PORT
      LAYER M3 ;
        RECT  71.208 43.162 71.226 43.2 ;
    END
  END rs_d[268]
  PIN rs_d[269]
    DIRECTION OUTPUT ;
    USE SIGNAL ;
    PORT
      LAYER M5 ;
        RECT  71.424 43.116 71.448 43.2 ;
    END
  END rs_d[269]
  PIN rs_d[26]
    DIRECTION OUTPUT ;
    USE SIGNAL ;
    PORT
      LAYER M3 ;
        RECT  11.088 43.162 11.106 43.2 ;
    END
  END rs_d[26]
  PIN rs_d[270]
    DIRECTION OUTPUT ;
    USE SIGNAL ;
    PORT
      LAYER M3 ;
        RECT  71.676 43.162 71.694 43.2 ;
    END
  END rs_d[270]
  PIN rs_d[271]
    DIRECTION OUTPUT ;
    USE SIGNAL ;
    PORT
      LAYER M5 ;
        RECT  71.952 43.116 71.976 43.2 ;
    END
  END rs_d[271]
  PIN rs_d[272]
    DIRECTION OUTPUT ;
    USE SIGNAL ;
    PORT
      LAYER M3 ;
        RECT  72.18 43.162 72.198 43.2 ;
    END
  END rs_d[272]
  PIN rs_d[273]
    DIRECTION OUTPUT ;
    USE SIGNAL ;
    PORT
      LAYER M5 ;
        RECT  72.432 43.116 72.456 43.2 ;
    END
  END rs_d[273]
  PIN rs_d[274]
    DIRECTION OUTPUT ;
    USE SIGNAL ;
    PORT
      LAYER M3 ;
        RECT  72.684 43.162 72.702 43.2 ;
    END
  END rs_d[274]
  PIN rs_d[275]
    DIRECTION OUTPUT ;
    USE SIGNAL ;
    PORT
      LAYER M5 ;
        RECT  72.912 43.116 72.936 43.2 ;
    END
  END rs_d[275]
  PIN rs_d[276]
    DIRECTION OUTPUT ;
    USE SIGNAL ;
    PORT
      LAYER M3 ;
        RECT  73.188 43.162 73.206 43.2 ;
    END
  END rs_d[276]
  PIN rs_d[277]
    DIRECTION OUTPUT ;
    USE SIGNAL ;
    PORT
      LAYER M5 ;
        RECT  73.44 43.116 73.464 43.2 ;
    END
  END rs_d[277]
  PIN rs_d[278]
    DIRECTION OUTPUT ;
    USE SIGNAL ;
    PORT
      LAYER M3 ;
        RECT  73.692 43.162 73.71 43.2 ;
    END
  END rs_d[278]
  PIN rs_d[279]
    DIRECTION OUTPUT ;
    USE SIGNAL ;
    PORT
      LAYER M5 ;
        RECT  73.92 43.116 73.944 43.2 ;
    END
  END rs_d[279]
  PIN rs_d[27]
    DIRECTION OUTPUT ;
    USE SIGNAL ;
    PORT
      LAYER M5 ;
        RECT  11.328 43.116 11.352 43.2 ;
    END
  END rs_d[27]
  PIN rs_d[280]
    DIRECTION OUTPUT ;
    USE SIGNAL ;
    PORT
      LAYER M3 ;
        RECT  74.196 43.162 74.214 43.2 ;
    END
  END rs_d[280]
  PIN rs_d[281]
    DIRECTION OUTPUT ;
    USE SIGNAL ;
    PORT
      LAYER M5 ;
        RECT  74.4 43.116 74.424 43.2 ;
    END
  END rs_d[281]
  PIN rs_d[282]
    DIRECTION OUTPUT ;
    USE SIGNAL ;
    PORT
      LAYER M3 ;
        RECT  74.664 43.162 74.682 43.2 ;
    END
  END rs_d[282]
  PIN rs_d[283]
    DIRECTION OUTPUT ;
    USE SIGNAL ;
    PORT
      LAYER M5 ;
        RECT  74.928 43.116 74.952 43.2 ;
    END
  END rs_d[283]
  PIN rs_d[284]
    DIRECTION OUTPUT ;
    USE SIGNAL ;
    PORT
      LAYER M3 ;
        RECT  75.168 43.162 75.186 43.2 ;
    END
  END rs_d[284]
  PIN rs_d[285]
    DIRECTION OUTPUT ;
    USE SIGNAL ;
    PORT
      LAYER M5 ;
        RECT  75.408 43.116 75.432 43.2 ;
    END
  END rs_d[285]
  PIN rs_d[286]
    DIRECTION OUTPUT ;
    USE SIGNAL ;
    PORT
      LAYER M3 ;
        RECT  75.672 43.162 75.69 43.2 ;
    END
  END rs_d[286]
  PIN rs_d[287]
    DIRECTION OUTPUT ;
    USE SIGNAL ;
    PORT
      LAYER M5 ;
        RECT  75.936 43.116 75.96 43.2 ;
    END
  END rs_d[287]
  PIN rs_d[288]
    DIRECTION OUTPUT ;
    USE SIGNAL ;
    PORT
      LAYER M3 ;
        RECT  76.176 43.162 76.194 43.2 ;
    END
  END rs_d[288]
  PIN rs_d[289]
    DIRECTION OUTPUT ;
    USE SIGNAL ;
    PORT
      LAYER M5 ;
        RECT  76.416 43.116 76.44 43.2 ;
    END
  END rs_d[289]
  PIN rs_d[28]
    DIRECTION OUTPUT ;
    USE SIGNAL ;
    PORT
      LAYER M3 ;
        RECT  11.556 43.162 11.574 43.2 ;
    END
  END rs_d[28]
  PIN rs_d[290]
    DIRECTION OUTPUT ;
    USE SIGNAL ;
    PORT
      LAYER M3 ;
        RECT  76.68 43.162 76.698 43.2 ;
    END
  END rs_d[290]
  PIN rs_d[291]
    DIRECTION OUTPUT ;
    USE SIGNAL ;
    PORT
      LAYER M5 ;
        RECT  76.896 43.116 76.92 43.2 ;
    END
  END rs_d[291]
  PIN rs_d[292]
    DIRECTION OUTPUT ;
    USE SIGNAL ;
    PORT
      LAYER M3 ;
        RECT  77.148 43.162 77.166 43.2 ;
    END
  END rs_d[292]
  PIN rs_d[293]
    DIRECTION OUTPUT ;
    USE SIGNAL ;
    PORT
      LAYER M5 ;
        RECT  77.424 43.116 77.448 43.2 ;
    END
  END rs_d[293]
  PIN rs_d[294]
    DIRECTION OUTPUT ;
    USE SIGNAL ;
    PORT
      LAYER M3 ;
        RECT  77.652 43.162 77.67 43.2 ;
    END
  END rs_d[294]
  PIN rs_d[295]
    DIRECTION OUTPUT ;
    USE SIGNAL ;
    PORT
      LAYER M5 ;
        RECT  77.904 43.116 77.928 43.2 ;
    END
  END rs_d[295]
  PIN rs_d[296]
    DIRECTION OUTPUT ;
    USE SIGNAL ;
    PORT
      LAYER M3 ;
        RECT  78.156 43.162 78.174 43.2 ;
    END
  END rs_d[296]
  PIN rs_d[297]
    DIRECTION OUTPUT ;
    USE SIGNAL ;
    PORT
      LAYER M5 ;
        RECT  78.384 43.116 78.408 43.2 ;
    END
  END rs_d[297]
  PIN rs_d[298]
    DIRECTION OUTPUT ;
    USE SIGNAL ;
    PORT
      LAYER M3 ;
        RECT  78.66 43.162 78.678 43.2 ;
    END
  END rs_d[298]
  PIN rs_d[299]
    DIRECTION OUTPUT ;
    USE SIGNAL ;
    PORT
      LAYER M5 ;
        RECT  78.912 43.116 78.936 43.2 ;
    END
  END rs_d[299]
  PIN rs_d[29]
    DIRECTION OUTPUT ;
    USE SIGNAL ;
    PORT
      LAYER M5 ;
        RECT  11.808 43.116 11.832 43.2 ;
    END
  END rs_d[29]
  PIN rs_d[2]
    DIRECTION OUTPUT ;
    USE SIGNAL ;
    PORT
      LAYER M3 ;
        RECT  5.112 43.162 5.13 43.2 ;
    END
  END rs_d[2]
  PIN rs_d[300]
    DIRECTION OUTPUT ;
    USE SIGNAL ;
    PORT
      LAYER M3 ;
        RECT  79.164 43.162 79.182 43.2 ;
    END
  END rs_d[300]
  PIN rs_d[301]
    DIRECTION OUTPUT ;
    USE SIGNAL ;
    PORT
      LAYER M5 ;
        RECT  79.392 43.116 79.416 43.2 ;
    END
  END rs_d[301]
  PIN rs_d[302]
    DIRECTION OUTPUT ;
    USE SIGNAL ;
    PORT
      LAYER M3 ;
        RECT  79.632 43.162 79.65 43.2 ;
    END
  END rs_d[302]
  PIN rs_d[303]
    DIRECTION OUTPUT ;
    USE SIGNAL ;
    PORT
      LAYER M5 ;
        RECT  79.872 43.116 79.896 43.2 ;
    END
  END rs_d[303]
  PIN rs_d[304]
    DIRECTION OUTPUT ;
    USE SIGNAL ;
    PORT
      LAYER M3 ;
        RECT  80.136 43.162 80.154 43.2 ;
    END
  END rs_d[304]
  PIN rs_d[305]
    DIRECTION OUTPUT ;
    USE SIGNAL ;
    PORT
      LAYER M5 ;
        RECT  80.4 43.116 80.424 43.2 ;
    END
  END rs_d[305]
  PIN rs_d[306]
    DIRECTION OUTPUT ;
    USE SIGNAL ;
    PORT
      LAYER M3 ;
        RECT  80.64 43.162 80.658 43.2 ;
    END
  END rs_d[306]
  PIN rs_d[307]
    DIRECTION OUTPUT ;
    USE SIGNAL ;
    PORT
      LAYER M5 ;
        RECT  80.88 43.116 80.904 43.2 ;
    END
  END rs_d[307]
  PIN rs_d[308]
    DIRECTION OUTPUT ;
    USE SIGNAL ;
    PORT
      LAYER M3 ;
        RECT  81.144 43.162 81.162 43.2 ;
    END
  END rs_d[308]
  PIN rs_d[309]
    DIRECTION OUTPUT ;
    USE SIGNAL ;
    PORT
      LAYER M5 ;
        RECT  81.36 43.116 81.384 43.2 ;
    END
  END rs_d[309]
  PIN rs_d[30]
    DIRECTION OUTPUT ;
    USE SIGNAL ;
    PORT
      LAYER M3 ;
        RECT  12.06 43.162 12.078 43.2 ;
    END
  END rs_d[30]
  PIN rs_d[310]
    DIRECTION OUTPUT ;
    USE SIGNAL ;
    PORT
      LAYER M3 ;
        RECT  81.648 43.162 81.666 43.2 ;
    END
  END rs_d[310]
  PIN rs_d[311]
    DIRECTION OUTPUT ;
    USE SIGNAL ;
    PORT
      LAYER M5 ;
        RECT  81.888 43.116 81.912 43.2 ;
    END
  END rs_d[311]
  PIN rs_d[312]
    DIRECTION OUTPUT ;
    USE SIGNAL ;
    PORT
      LAYER M3 ;
        RECT  82.116 43.162 82.134 43.2 ;
    END
  END rs_d[312]
  PIN rs_d[313]
    DIRECTION OUTPUT ;
    USE SIGNAL ;
    PORT
      LAYER M5 ;
        RECT  82.368 43.116 82.392 43.2 ;
    END
  END rs_d[313]
  PIN rs_d[314]
    DIRECTION OUTPUT ;
    USE SIGNAL ;
    PORT
      LAYER M3 ;
        RECT  82.62 43.162 82.638 43.2 ;
    END
  END rs_d[314]
  PIN rs_d[315]
    DIRECTION OUTPUT ;
    USE SIGNAL ;
    PORT
      LAYER M5 ;
        RECT  82.848 43.116 82.872 43.2 ;
    END
  END rs_d[315]
  PIN rs_d[316]
    DIRECTION OUTPUT ;
    USE SIGNAL ;
    PORT
      LAYER M3 ;
        RECT  83.124 43.162 83.142 43.2 ;
    END
  END rs_d[316]
  PIN rs_d[317]
    DIRECTION OUTPUT ;
    USE SIGNAL ;
    PORT
      LAYER M5 ;
        RECT  83.376 43.116 83.4 43.2 ;
    END
  END rs_d[317]
  PIN rs_d[318]
    DIRECTION OUTPUT ;
    USE SIGNAL ;
    PORT
      LAYER M3 ;
        RECT  83.628 43.162 83.646 43.2 ;
    END
  END rs_d[318]
  PIN rs_d[319]
    DIRECTION OUTPUT ;
    USE SIGNAL ;
    PORT
      LAYER M5 ;
        RECT  83.856 43.116 83.88 43.2 ;
    END
  END rs_d[319]
  PIN rs_d[31]
    DIRECTION OUTPUT ;
    USE SIGNAL ;
    PORT
      LAYER M5 ;
        RECT  12.336 43.116 12.36 43.2 ;
    END
  END rs_d[31]
  PIN rs_d[320]
    DIRECTION OUTPUT ;
    USE SIGNAL ;
    PORT
      LAYER M3 ;
        RECT  84.132 43.162 84.15 43.2 ;
    END
  END rs_d[320]
  PIN rs_d[321]
    DIRECTION OUTPUT ;
    USE SIGNAL ;
    PORT
      LAYER M5 ;
        RECT  84.384 43.116 84.408 43.2 ;
    END
  END rs_d[321]
  PIN rs_d[322]
    DIRECTION OUTPUT ;
    USE SIGNAL ;
    PORT
      LAYER M3 ;
        RECT  84.6 43.162 84.618 43.2 ;
    END
  END rs_d[322]
  PIN rs_d[323]
    DIRECTION OUTPUT ;
    USE SIGNAL ;
    PORT
      LAYER M5 ;
        RECT  84.864 43.116 84.888 43.2 ;
    END
  END rs_d[323]
  PIN rs_d[324]
    DIRECTION OUTPUT ;
    USE SIGNAL ;
    PORT
      LAYER M3 ;
        RECT  85.104 43.162 85.122 43.2 ;
    END
  END rs_d[324]
  PIN rs_d[325]
    DIRECTION OUTPUT ;
    USE SIGNAL ;
    PORT
      LAYER M5 ;
        RECT  85.344 43.116 85.368 43.2 ;
    END
  END rs_d[325]
  PIN rs_d[326]
    DIRECTION OUTPUT ;
    USE SIGNAL ;
    PORT
      LAYER M3 ;
        RECT  85.608 43.162 85.626 43.2 ;
    END
  END rs_d[326]
  PIN rs_d[327]
    DIRECTION OUTPUT ;
    USE SIGNAL ;
    PORT
      LAYER M5 ;
        RECT  85.872 43.116 85.896 43.2 ;
    END
  END rs_d[327]
  PIN rs_d[328]
    DIRECTION OUTPUT ;
    USE SIGNAL ;
    PORT
      LAYER M3 ;
        RECT  86.112 43.162 86.13 43.2 ;
    END
  END rs_d[328]
  PIN rs_d[329]
    DIRECTION OUTPUT ;
    USE SIGNAL ;
    PORT
      LAYER M5 ;
        RECT  86.352 43.116 86.376 43.2 ;
    END
  END rs_d[329]
  PIN rs_d[32]
    DIRECTION OUTPUT ;
    USE SIGNAL ;
    PORT
      LAYER M3 ;
        RECT  12.564 43.162 12.582 43.2 ;
    END
  END rs_d[32]
  PIN rs_d[330]
    DIRECTION OUTPUT ;
    USE SIGNAL ;
    PORT
      LAYER M3 ;
        RECT  86.616 43.162 86.634 43.2 ;
    END
  END rs_d[330]
  PIN rs_d[331]
    DIRECTION OUTPUT ;
    USE SIGNAL ;
    PORT
      LAYER M5 ;
        RECT  86.832 43.116 86.856 43.2 ;
    END
  END rs_d[331]
  PIN rs_d[332]
    DIRECTION OUTPUT ;
    USE SIGNAL ;
    PORT
      LAYER M3 ;
        RECT  87.084 43.162 87.102 43.2 ;
    END
  END rs_d[332]
  PIN rs_d[333]
    DIRECTION OUTPUT ;
    USE SIGNAL ;
    PORT
      LAYER M5 ;
        RECT  87.36 43.116 87.384 43.2 ;
    END
  END rs_d[333]
  PIN rs_d[334]
    DIRECTION OUTPUT ;
    USE SIGNAL ;
    PORT
      LAYER M3 ;
        RECT  87.588 43.162 87.606 43.2 ;
    END
  END rs_d[334]
  PIN rs_d[335]
    DIRECTION OUTPUT ;
    USE SIGNAL ;
    PORT
      LAYER M5 ;
        RECT  87.84 43.116 87.864 43.2 ;
    END
  END rs_d[335]
  PIN rs_d[336]
    DIRECTION OUTPUT ;
    USE SIGNAL ;
    PORT
      LAYER M3 ;
        RECT  88.092 43.162 88.11 43.2 ;
    END
  END rs_d[336]
  PIN rs_d[337]
    DIRECTION OUTPUT ;
    USE SIGNAL ;
    PORT
      LAYER M5 ;
        RECT  88.32 43.116 88.344 43.2 ;
    END
  END rs_d[337]
  PIN rs_d[338]
    DIRECTION OUTPUT ;
    USE SIGNAL ;
    PORT
      LAYER M3 ;
        RECT  88.596 43.162 88.614 43.2 ;
    END
  END rs_d[338]
  PIN rs_d[339]
    DIRECTION OUTPUT ;
    USE SIGNAL ;
    PORT
      LAYER M5 ;
        RECT  88.848 43.116 88.872 43.2 ;
    END
  END rs_d[339]
  PIN rs_d[33]
    DIRECTION OUTPUT ;
    USE SIGNAL ;
    PORT
      LAYER M5 ;
        RECT  12.816 43.116 12.84 43.2 ;
    END
  END rs_d[33]
  PIN rs_d[340]
    DIRECTION OUTPUT ;
    USE SIGNAL ;
    PORT
      LAYER M3 ;
        RECT  89.1 43.162 89.118 43.2 ;
    END
  END rs_d[340]
  PIN rs_d[341]
    DIRECTION OUTPUT ;
    USE SIGNAL ;
    PORT
      LAYER M5 ;
        RECT  89.328 43.116 89.352 43.2 ;
    END
  END rs_d[341]
  PIN rs_d[342]
    DIRECTION OUTPUT ;
    USE SIGNAL ;
    PORT
      LAYER M3 ;
        RECT  89.568 43.162 89.586 43.2 ;
    END
  END rs_d[342]
  PIN rs_d[343]
    DIRECTION OUTPUT ;
    USE SIGNAL ;
    PORT
      LAYER M5 ;
        RECT  89.808 43.116 89.832 43.2 ;
    END
  END rs_d[343]
  PIN rs_d[344]
    DIRECTION OUTPUT ;
    USE SIGNAL ;
    PORT
      LAYER M3 ;
        RECT  90.072 43.162 90.09 43.2 ;
    END
  END rs_d[344]
  PIN rs_d[345]
    DIRECTION OUTPUT ;
    USE SIGNAL ;
    PORT
      LAYER M5 ;
        RECT  90.336 43.116 90.36 43.2 ;
    END
  END rs_d[345]
  PIN rs_d[346]
    DIRECTION OUTPUT ;
    USE SIGNAL ;
    PORT
      LAYER M3 ;
        RECT  90.576 43.162 90.594 43.2 ;
    END
  END rs_d[346]
  PIN rs_d[347]
    DIRECTION OUTPUT ;
    USE SIGNAL ;
    PORT
      LAYER M5 ;
        RECT  90.816 43.116 90.84 43.2 ;
    END
  END rs_d[347]
  PIN rs_d[348]
    DIRECTION OUTPUT ;
    USE SIGNAL ;
    PORT
      LAYER M3 ;
        RECT  91.08 43.162 91.098 43.2 ;
    END
  END rs_d[348]
  PIN rs_d[349]
    DIRECTION OUTPUT ;
    USE SIGNAL ;
    PORT
      LAYER M5 ;
        RECT  91.296 43.116 91.32 43.2 ;
    END
  END rs_d[349]
  PIN rs_d[34]
    DIRECTION OUTPUT ;
    USE SIGNAL ;
    PORT
      LAYER M3 ;
        RECT  13.068 43.162 13.086 43.2 ;
    END
  END rs_d[34]
  PIN rs_d[350]
    DIRECTION OUTPUT ;
    USE SIGNAL ;
    PORT
      LAYER M3 ;
        RECT  91.584 43.162 91.602 43.2 ;
    END
  END rs_d[350]
  PIN rs_d[351]
    DIRECTION OUTPUT ;
    USE SIGNAL ;
    PORT
      LAYER M5 ;
        RECT  91.824 43.116 91.848 43.2 ;
    END
  END rs_d[351]
  PIN rs_d[352]
    DIRECTION OUTPUT ;
    USE SIGNAL ;
    PORT
      LAYER M3 ;
        RECT  92.052 43.162 92.07 43.2 ;
    END
  END rs_d[352]
  PIN rs_d[353]
    DIRECTION OUTPUT ;
    USE SIGNAL ;
    PORT
      LAYER M5 ;
        RECT  92.304 43.116 92.328 43.2 ;
    END
  END rs_d[353]
  PIN rs_d[354]
    DIRECTION OUTPUT ;
    USE SIGNAL ;
    PORT
      LAYER M3 ;
        RECT  92.556 43.162 92.574 43.2 ;
    END
  END rs_d[354]
  PIN rs_d[355]
    DIRECTION OUTPUT ;
    USE SIGNAL ;
    PORT
      LAYER M5 ;
        RECT  92.832 43.116 92.856 43.2 ;
    END
  END rs_d[355]
  PIN rs_d[356]
    DIRECTION OUTPUT ;
    USE SIGNAL ;
    PORT
      LAYER M3 ;
        RECT  93.06 43.162 93.078 43.2 ;
    END
  END rs_d[356]
  PIN rs_d[357]
    DIRECTION OUTPUT ;
    USE SIGNAL ;
    PORT
      LAYER M5 ;
        RECT  93.312 43.116 93.336 43.2 ;
    END
  END rs_d[357]
  PIN rs_d[358]
    DIRECTION OUTPUT ;
    USE SIGNAL ;
    PORT
      LAYER M3 ;
        RECT  93.564 43.162 93.582 43.2 ;
    END
  END rs_d[358]
  PIN rs_d[359]
    DIRECTION OUTPUT ;
    USE SIGNAL ;
    PORT
      LAYER M5 ;
        RECT  93.792 43.116 93.816 43.2 ;
    END
  END rs_d[359]
  PIN rs_d[35]
    DIRECTION OUTPUT ;
    USE SIGNAL ;
    PORT
      LAYER M5 ;
        RECT  13.296 43.116 13.32 43.2 ;
    END
  END rs_d[35]
  PIN rs_d[360]
    DIRECTION OUTPUT ;
    USE SIGNAL ;
    PORT
      LAYER M3 ;
        RECT  94.068 43.162 94.086 43.2 ;
    END
  END rs_d[360]
  PIN rs_d[361]
    DIRECTION OUTPUT ;
    USE SIGNAL ;
    PORT
      LAYER M5 ;
        RECT  94.32 43.116 94.344 43.2 ;
    END
  END rs_d[361]
  PIN rs_d[362]
    DIRECTION OUTPUT ;
    USE SIGNAL ;
    PORT
      LAYER M3 ;
        RECT  94.536 43.162 94.554 43.2 ;
    END
  END rs_d[362]
  PIN rs_d[363]
    DIRECTION OUTPUT ;
    USE SIGNAL ;
    PORT
      LAYER M5 ;
        RECT  94.8 43.116 94.824 43.2 ;
    END
  END rs_d[363]
  PIN rs_d[364]
    DIRECTION OUTPUT ;
    USE SIGNAL ;
    PORT
      LAYER M3 ;
        RECT  95.04 43.162 95.058 43.2 ;
    END
  END rs_d[364]
  PIN rs_d[365]
    DIRECTION OUTPUT ;
    USE SIGNAL ;
    PORT
      LAYER M5 ;
        RECT  95.28 43.116 95.304 43.2 ;
    END
  END rs_d[365]
  PIN rs_d[366]
    DIRECTION OUTPUT ;
    USE SIGNAL ;
    PORT
      LAYER M3 ;
        RECT  95.544 43.162 95.562 43.2 ;
    END
  END rs_d[366]
  PIN rs_d[367]
    DIRECTION OUTPUT ;
    USE SIGNAL ;
    PORT
      LAYER M5 ;
        RECT  95.808 43.116 95.832 43.2 ;
    END
  END rs_d[367]
  PIN rs_d[368]
    DIRECTION OUTPUT ;
    USE SIGNAL ;
    PORT
      LAYER M3 ;
        RECT  96.048 43.162 96.066 43.2 ;
    END
  END rs_d[368]
  PIN rs_d[369]
    DIRECTION OUTPUT ;
    USE SIGNAL ;
    PORT
      LAYER M5 ;
        RECT  96.288 43.116 96.312 43.2 ;
    END
  END rs_d[369]
  PIN rs_d[36]
    DIRECTION OUTPUT ;
    USE SIGNAL ;
    PORT
      LAYER M3 ;
        RECT  13.572 43.162 13.59 43.2 ;
    END
  END rs_d[36]
  PIN rs_d[370]
    DIRECTION OUTPUT ;
    USE SIGNAL ;
    PORT
      LAYER M3 ;
        RECT  96.552 43.162 96.57 43.2 ;
    END
  END rs_d[370]
  PIN rs_d[371]
    DIRECTION OUTPUT ;
    USE SIGNAL ;
    PORT
      LAYER M5 ;
        RECT  96.768 43.116 96.792 43.2 ;
    END
  END rs_d[371]
  PIN rs_d[372]
    DIRECTION OUTPUT ;
    USE SIGNAL ;
    PORT
      LAYER M3 ;
        RECT  97.02 43.162 97.038 43.2 ;
    END
  END rs_d[372]
  PIN rs_d[373]
    DIRECTION OUTPUT ;
    USE SIGNAL ;
    PORT
      LAYER M5 ;
        RECT  97.296 43.116 97.32 43.2 ;
    END
  END rs_d[373]
  PIN rs_d[374]
    DIRECTION OUTPUT ;
    USE SIGNAL ;
    PORT
      LAYER M3 ;
        RECT  97.524 43.162 97.542 43.2 ;
    END
  END rs_d[374]
  PIN rs_d[375]
    DIRECTION OUTPUT ;
    USE SIGNAL ;
    PORT
      LAYER M5 ;
        RECT  97.776 43.116 97.8 43.2 ;
    END
  END rs_d[375]
  PIN rs_d[376]
    DIRECTION OUTPUT ;
    USE SIGNAL ;
    PORT
      LAYER M3 ;
        RECT  98.028 43.162 98.046 43.2 ;
    END
  END rs_d[376]
  PIN rs_d[377]
    DIRECTION OUTPUT ;
    USE SIGNAL ;
    PORT
      LAYER M5 ;
        RECT  98.256 43.116 98.28 43.2 ;
    END
  END rs_d[377]
  PIN rs_d[378]
    DIRECTION OUTPUT ;
    USE SIGNAL ;
    PORT
      LAYER M3 ;
        RECT  98.532 43.162 98.55 43.2 ;
    END
  END rs_d[378]
  PIN rs_d[379]
    DIRECTION OUTPUT ;
    USE SIGNAL ;
    PORT
      LAYER M5 ;
        RECT  98.784 43.116 98.808 43.2 ;
    END
  END rs_d[379]
  PIN rs_d[37]
    DIRECTION OUTPUT ;
    USE SIGNAL ;
    PORT
      LAYER M5 ;
        RECT  13.824 43.116 13.848 43.2 ;
    END
  END rs_d[37]
  PIN rs_d[380]
    DIRECTION OUTPUT ;
    USE SIGNAL ;
    PORT
      LAYER M3 ;
        RECT  99.036 43.162 99.054 43.2 ;
    END
  END rs_d[380]
  PIN rs_d[381]
    DIRECTION OUTPUT ;
    USE SIGNAL ;
    PORT
      LAYER M5 ;
        RECT  99.264 43.116 99.288 43.2 ;
    END
  END rs_d[381]
  PIN rs_d[382]
    DIRECTION OUTPUT ;
    USE SIGNAL ;
    PORT
      LAYER M3 ;
        RECT  99.504 43.162 99.522 43.2 ;
    END
  END rs_d[382]
  PIN rs_d[383]
    DIRECTION OUTPUT ;
    USE SIGNAL ;
    PORT
      LAYER M5 ;
        RECT  99.744 43.116 99.768 43.2 ;
    END
  END rs_d[383]
  PIN rs_d[384]
    DIRECTION OUTPUT ;
    USE SIGNAL ;
    PORT
      LAYER M3 ;
        RECT  100.008 43.162 100.026 43.2 ;
    END
  END rs_d[384]
  PIN rs_d[385]
    DIRECTION OUTPUT ;
    USE SIGNAL ;
    PORT
      LAYER M5 ;
        RECT  100.272 43.116 100.296 43.2 ;
    END
  END rs_d[385]
  PIN rs_d[386]
    DIRECTION OUTPUT ;
    USE SIGNAL ;
    PORT
      LAYER M3 ;
        RECT  100.512 43.162 100.53 43.2 ;
    END
  END rs_d[386]
  PIN rs_d[387]
    DIRECTION OUTPUT ;
    USE SIGNAL ;
    PORT
      LAYER M5 ;
        RECT  100.752 43.116 100.776 43.2 ;
    END
  END rs_d[387]
  PIN rs_d[388]
    DIRECTION OUTPUT ;
    USE SIGNAL ;
    PORT
      LAYER M3 ;
        RECT  101.016 43.162 101.034 43.2 ;
    END
  END rs_d[388]
  PIN rs_d[389]
    DIRECTION OUTPUT ;
    USE SIGNAL ;
    PORT
      LAYER M5 ;
        RECT  101.232 43.116 101.256 43.2 ;
    END
  END rs_d[389]
  PIN rs_d[38]
    DIRECTION OUTPUT ;
    USE SIGNAL ;
    PORT
      LAYER M3 ;
        RECT  14.04 43.162 14.058 43.2 ;
    END
  END rs_d[38]
  PIN rs_d[390]
    DIRECTION OUTPUT ;
    USE SIGNAL ;
    PORT
      LAYER M3 ;
        RECT  101.52 43.162 101.538 43.2 ;
    END
  END rs_d[390]
  PIN rs_d[391]
    DIRECTION OUTPUT ;
    USE SIGNAL ;
    PORT
      LAYER M5 ;
        RECT  101.76 43.116 101.784 43.2 ;
    END
  END rs_d[391]
  PIN rs_d[392]
    DIRECTION OUTPUT ;
    USE SIGNAL ;
    PORT
      LAYER M3 ;
        RECT  101.988 43.162 102.006 43.2 ;
    END
  END rs_d[392]
  PIN rs_d[393]
    DIRECTION OUTPUT ;
    USE SIGNAL ;
    PORT
      LAYER M5 ;
        RECT  102.24 43.116 102.264 43.2 ;
    END
  END rs_d[393]
  PIN rs_d[394]
    DIRECTION OUTPUT ;
    USE SIGNAL ;
    PORT
      LAYER M3 ;
        RECT  102.492 43.162 102.51 43.2 ;
    END
  END rs_d[394]
  PIN rs_d[395]
    DIRECTION OUTPUT ;
    USE SIGNAL ;
    PORT
      LAYER M5 ;
        RECT  102.768 43.116 102.792 43.2 ;
    END
  END rs_d[395]
  PIN rs_d[396]
    DIRECTION OUTPUT ;
    USE SIGNAL ;
    PORT
      LAYER M3 ;
        RECT  102.996 43.162 103.014 43.2 ;
    END
  END rs_d[396]
  PIN rs_d[397]
    DIRECTION OUTPUT ;
    USE SIGNAL ;
    PORT
      LAYER M5 ;
        RECT  103.248 43.116 103.272 43.2 ;
    END
  END rs_d[397]
  PIN rs_d[398]
    DIRECTION OUTPUT ;
    USE SIGNAL ;
    PORT
      LAYER M3 ;
        RECT  103.5 43.162 103.518 43.2 ;
    END
  END rs_d[398]
  PIN rs_d[399]
    DIRECTION OUTPUT ;
    USE SIGNAL ;
    PORT
      LAYER M5 ;
        RECT  103.728 43.116 103.752 43.2 ;
    END
  END rs_d[399]
  PIN rs_d[39]
    DIRECTION OUTPUT ;
    USE SIGNAL ;
    PORT
      LAYER M5 ;
        RECT  14.304 43.116 14.328 43.2 ;
    END
  END rs_d[39]
  PIN rs_d[3]
    DIRECTION OUTPUT ;
    USE SIGNAL ;
    PORT
      LAYER M5 ;
        RECT  5.376 43.116 5.4 43.2 ;
    END
  END rs_d[3]
  PIN rs_d[400]
    DIRECTION OUTPUT ;
    USE SIGNAL ;
    PORT
      LAYER M3 ;
        RECT  104.004 43.162 104.022 43.2 ;
    END
  END rs_d[400]
  PIN rs_d[401]
    DIRECTION OUTPUT ;
    USE SIGNAL ;
    PORT
      LAYER M5 ;
        RECT  104.256 43.116 104.28 43.2 ;
    END
  END rs_d[401]
  PIN rs_d[402]
    DIRECTION OUTPUT ;
    USE SIGNAL ;
    PORT
      LAYER M3 ;
        RECT  104.472 43.162 104.49 43.2 ;
    END
  END rs_d[402]
  PIN rs_d[403]
    DIRECTION OUTPUT ;
    USE SIGNAL ;
    PORT
      LAYER M5 ;
        RECT  104.736 43.116 104.76 43.2 ;
    END
  END rs_d[403]
  PIN rs_d[404]
    DIRECTION OUTPUT ;
    USE SIGNAL ;
    PORT
      LAYER M3 ;
        RECT  104.976 43.162 104.994 43.2 ;
    END
  END rs_d[404]
  PIN rs_d[405]
    DIRECTION OUTPUT ;
    USE SIGNAL ;
    PORT
      LAYER M5 ;
        RECT  105.216 43.116 105.24 43.2 ;
    END
  END rs_d[405]
  PIN rs_d[406]
    DIRECTION OUTPUT ;
    USE SIGNAL ;
    PORT
      LAYER M3 ;
        RECT  105.48 43.162 105.498 43.2 ;
    END
  END rs_d[406]
  PIN rs_d[407]
    DIRECTION OUTPUT ;
    USE SIGNAL ;
    PORT
      LAYER M5 ;
        RECT  105.744 43.116 105.768 43.2 ;
    END
  END rs_d[407]
  PIN rs_d[408]
    DIRECTION OUTPUT ;
    USE SIGNAL ;
    PORT
      LAYER M3 ;
        RECT  105.984 43.162 106.002 43.2 ;
    END
  END rs_d[408]
  PIN rs_d[409]
    DIRECTION OUTPUT ;
    USE SIGNAL ;
    PORT
      LAYER M5 ;
        RECT  106.224 43.116 106.248 43.2 ;
    END
  END rs_d[409]
  PIN rs_d[40]
    DIRECTION OUTPUT ;
    USE SIGNAL ;
    PORT
      LAYER M3 ;
        RECT  14.544 43.162 14.562 43.2 ;
    END
  END rs_d[40]
  PIN rs_d[410]
    DIRECTION OUTPUT ;
    USE SIGNAL ;
    PORT
      LAYER M3 ;
        RECT  106.488 43.162 106.506 43.2 ;
    END
  END rs_d[410]
  PIN rs_d[411]
    DIRECTION OUTPUT ;
    USE SIGNAL ;
    PORT
      LAYER M5 ;
        RECT  106.704 43.116 106.728 43.2 ;
    END
  END rs_d[411]
  PIN rs_d[412]
    DIRECTION OUTPUT ;
    USE SIGNAL ;
    PORT
      LAYER M3 ;
        RECT  106.956 43.162 106.974 43.2 ;
    END
  END rs_d[412]
  PIN rs_d[413]
    DIRECTION OUTPUT ;
    USE SIGNAL ;
    PORT
      LAYER M5 ;
        RECT  107.232 43.116 107.256 43.2 ;
    END
  END rs_d[413]
  PIN rs_d[414]
    DIRECTION OUTPUT ;
    USE SIGNAL ;
    PORT
      LAYER M3 ;
        RECT  107.46 43.162 107.478 43.2 ;
    END
  END rs_d[414]
  PIN rs_d[415]
    DIRECTION OUTPUT ;
    USE SIGNAL ;
    PORT
      LAYER M5 ;
        RECT  107.712 43.116 107.736 43.2 ;
    END
  END rs_d[415]
  PIN rs_d[416]
    DIRECTION OUTPUT ;
    USE SIGNAL ;
    PORT
      LAYER M3 ;
        RECT  107.964 43.162 107.982 43.2 ;
    END
  END rs_d[416]
  PIN rs_d[417]
    DIRECTION OUTPUT ;
    USE SIGNAL ;
    PORT
      LAYER M5 ;
        RECT  108.192 43.116 108.216 43.2 ;
    END
  END rs_d[417]
  PIN rs_d[418]
    DIRECTION OUTPUT ;
    USE SIGNAL ;
    PORT
      LAYER M3 ;
        RECT  108.468 43.162 108.486 43.2 ;
    END
  END rs_d[418]
  PIN rs_d[419]
    DIRECTION OUTPUT ;
    USE SIGNAL ;
    PORT
      LAYER M5 ;
        RECT  108.72 43.116 108.744 43.2 ;
    END
  END rs_d[419]
  PIN rs_d[41]
    DIRECTION OUTPUT ;
    USE SIGNAL ;
    PORT
      LAYER M5 ;
        RECT  14.784 43.116 14.808 43.2 ;
    END
  END rs_d[41]
  PIN rs_d[420]
    DIRECTION OUTPUT ;
    USE SIGNAL ;
    PORT
      LAYER M3 ;
        RECT  108.972 43.162 108.99 43.2 ;
    END
  END rs_d[420]
  PIN rs_d[421]
    DIRECTION OUTPUT ;
    USE SIGNAL ;
    PORT
      LAYER M5 ;
        RECT  109.2 43.116 109.224 43.2 ;
    END
  END rs_d[421]
  PIN rs_d[422]
    DIRECTION OUTPUT ;
    USE SIGNAL ;
    PORT
      LAYER M3 ;
        RECT  109.44 43.162 109.458 43.2 ;
    END
  END rs_d[422]
  PIN rs_d[423]
    DIRECTION OUTPUT ;
    USE SIGNAL ;
    PORT
      LAYER M5 ;
        RECT  109.68 43.116 109.704 43.2 ;
    END
  END rs_d[423]
  PIN rs_d[424]
    DIRECTION OUTPUT ;
    USE SIGNAL ;
    PORT
      LAYER M3 ;
        RECT  109.944 43.162 109.962 43.2 ;
    END
  END rs_d[424]
  PIN rs_d[425]
    DIRECTION OUTPUT ;
    USE SIGNAL ;
    PORT
      LAYER M5 ;
        RECT  110.208 43.116 110.232 43.2 ;
    END
  END rs_d[425]
  PIN rs_d[426]
    DIRECTION OUTPUT ;
    USE SIGNAL ;
    PORT
      LAYER M3 ;
        RECT  110.448 43.162 110.466 43.2 ;
    END
  END rs_d[426]
  PIN rs_d[427]
    DIRECTION OUTPUT ;
    USE SIGNAL ;
    PORT
      LAYER M5 ;
        RECT  110.688 43.116 110.712 43.2 ;
    END
  END rs_d[427]
  PIN rs_d[428]
    DIRECTION OUTPUT ;
    USE SIGNAL ;
    PORT
      LAYER M3 ;
        RECT  110.952 43.162 110.97 43.2 ;
    END
  END rs_d[428]
  PIN rs_d[429]
    DIRECTION OUTPUT ;
    USE SIGNAL ;
    PORT
      LAYER M5 ;
        RECT  111.216 43.116 111.24 43.2 ;
    END
  END rs_d[429]
  PIN rs_d[42]
    DIRECTION OUTPUT ;
    USE SIGNAL ;
    PORT
      LAYER M3 ;
        RECT  15.048 43.162 15.066 43.2 ;
    END
  END rs_d[42]
  PIN rs_d[430]
    DIRECTION OUTPUT ;
    USE SIGNAL ;
    PORT
      LAYER M3 ;
        RECT  111.456 43.162 111.474 43.2 ;
    END
  END rs_d[430]
  PIN rs_d[431]
    DIRECTION OUTPUT ;
    USE SIGNAL ;
    PORT
      LAYER M5 ;
        RECT  111.696 43.116 111.72 43.2 ;
    END
  END rs_d[431]
  PIN rs_d[432]
    DIRECTION OUTPUT ;
    USE SIGNAL ;
    PORT
      LAYER M3 ;
        RECT  111.924 43.162 111.942 43.2 ;
    END
  END rs_d[432]
  PIN rs_d[433]
    DIRECTION OUTPUT ;
    USE SIGNAL ;
    PORT
      LAYER M5 ;
        RECT  112.176 43.116 112.2 43.2 ;
    END
  END rs_d[433]
  PIN rs_d[434]
    DIRECTION OUTPUT ;
    USE SIGNAL ;
    PORT
      LAYER M3 ;
        RECT  112.428 43.162 112.446 43.2 ;
    END
  END rs_d[434]
  PIN rs_d[435]
    DIRECTION OUTPUT ;
    USE SIGNAL ;
    PORT
      LAYER M5 ;
        RECT  112.704 43.116 112.728 43.2 ;
    END
  END rs_d[435]
  PIN rs_d[436]
    DIRECTION OUTPUT ;
    USE SIGNAL ;
    PORT
      LAYER M3 ;
        RECT  112.932 43.162 112.95 43.2 ;
    END
  END rs_d[436]
  PIN rs_d[437]
    DIRECTION OUTPUT ;
    USE SIGNAL ;
    PORT
      LAYER M5 ;
        RECT  113.184 43.116 113.208 43.2 ;
    END
  END rs_d[437]
  PIN rs_d[438]
    DIRECTION OUTPUT ;
    USE SIGNAL ;
    PORT
      LAYER M3 ;
        RECT  113.436 43.162 113.454 43.2 ;
    END
  END rs_d[438]
  PIN rs_d[439]
    DIRECTION OUTPUT ;
    USE SIGNAL ;
    PORT
      LAYER M5 ;
        RECT  113.664 43.116 113.688 43.2 ;
    END
  END rs_d[439]
  PIN rs_d[43]
    DIRECTION OUTPUT ;
    USE SIGNAL ;
    PORT
      LAYER M5 ;
        RECT  15.312 43.116 15.336 43.2 ;
    END
  END rs_d[43]
  PIN rs_d[440]
    DIRECTION OUTPUT ;
    USE SIGNAL ;
    PORT
      LAYER M3 ;
        RECT  113.94 43.162 113.958 43.2 ;
    END
  END rs_d[440]
  PIN rs_d[441]
    DIRECTION OUTPUT ;
    USE SIGNAL ;
    PORT
      LAYER M5 ;
        RECT  114.192 43.116 114.216 43.2 ;
    END
  END rs_d[441]
  PIN rs_d[442]
    DIRECTION OUTPUT ;
    USE SIGNAL ;
    PORT
      LAYER M3 ;
        RECT  114.408 43.162 114.426 43.2 ;
    END
  END rs_d[442]
  PIN rs_d[443]
    DIRECTION OUTPUT ;
    USE SIGNAL ;
    PORT
      LAYER M5 ;
        RECT  114.672 43.116 114.696 43.2 ;
    END
  END rs_d[443]
  PIN rs_d[444]
    DIRECTION OUTPUT ;
    USE SIGNAL ;
    PORT
      LAYER M3 ;
        RECT  114.912 43.162 114.93 43.2 ;
    END
  END rs_d[444]
  PIN rs_d[445]
    DIRECTION OUTPUT ;
    USE SIGNAL ;
    PORT
      LAYER M5 ;
        RECT  115.152 43.116 115.176 43.2 ;
    END
  END rs_d[445]
  PIN rs_d[446]
    DIRECTION OUTPUT ;
    USE SIGNAL ;
    PORT
      LAYER M3 ;
        RECT  115.416 43.162 115.434 43.2 ;
    END
  END rs_d[446]
  PIN rs_d[447]
    DIRECTION OUTPUT ;
    USE SIGNAL ;
    PORT
      LAYER M5 ;
        RECT  115.68 43.116 115.704 43.2 ;
    END
  END rs_d[447]
  PIN rs_d[448]
    DIRECTION OUTPUT ;
    USE SIGNAL ;
    PORT
      LAYER M3 ;
        RECT  115.92 43.162 115.938 43.2 ;
    END
  END rs_d[448]
  PIN rs_d[449]
    DIRECTION OUTPUT ;
    USE SIGNAL ;
    PORT
      LAYER M5 ;
        RECT  116.16 43.116 116.184 43.2 ;
    END
  END rs_d[449]
  PIN rs_d[44]
    DIRECTION OUTPUT ;
    USE SIGNAL ;
    PORT
      LAYER M3 ;
        RECT  15.552 43.162 15.57 43.2 ;
    END
  END rs_d[44]
  PIN rs_d[450]
    DIRECTION OUTPUT ;
    USE SIGNAL ;
    PORT
      LAYER M3 ;
        RECT  116.424 43.162 116.442 43.2 ;
    END
  END rs_d[450]
  PIN rs_d[451]
    DIRECTION OUTPUT ;
    USE SIGNAL ;
    PORT
      LAYER M5 ;
        RECT  116.64 43.116 116.664 43.2 ;
    END
  END rs_d[451]
  PIN rs_d[452]
    DIRECTION OUTPUT ;
    USE SIGNAL ;
    PORT
      LAYER M3 ;
        RECT  116.892 43.162 116.91 43.2 ;
    END
  END rs_d[452]
  PIN rs_d[453]
    DIRECTION OUTPUT ;
    USE SIGNAL ;
    PORT
      LAYER M5 ;
        RECT  117.168 43.116 117.192 43.2 ;
    END
  END rs_d[453]
  PIN rs_d[454]
    DIRECTION OUTPUT ;
    USE SIGNAL ;
    PORT
      LAYER M3 ;
        RECT  117.396 43.162 117.414 43.2 ;
    END
  END rs_d[454]
  PIN rs_d[455]
    DIRECTION OUTPUT ;
    USE SIGNAL ;
    PORT
      LAYER M5 ;
        RECT  117.648 43.116 117.672 43.2 ;
    END
  END rs_d[455]
  PIN rs_d[456]
    DIRECTION OUTPUT ;
    USE SIGNAL ;
    PORT
      LAYER M3 ;
        RECT  117.9 43.162 117.918 43.2 ;
    END
  END rs_d[456]
  PIN rs_d[457]
    DIRECTION OUTPUT ;
    USE SIGNAL ;
    PORT
      LAYER M5 ;
        RECT  118.128 43.116 118.152 43.2 ;
    END
  END rs_d[457]
  PIN rs_d[458]
    DIRECTION OUTPUT ;
    USE SIGNAL ;
    PORT
      LAYER M3 ;
        RECT  118.404 43.162 118.422 43.2 ;
    END
  END rs_d[458]
  PIN rs_d[459]
    DIRECTION OUTPUT ;
    USE SIGNAL ;
    PORT
      LAYER M5 ;
        RECT  118.656 43.116 118.68 43.2 ;
    END
  END rs_d[459]
  PIN rs_d[45]
    DIRECTION OUTPUT ;
    USE SIGNAL ;
    PORT
      LAYER M5 ;
        RECT  15.792 43.116 15.816 43.2 ;
    END
  END rs_d[45]
  PIN rs_d[460]
    DIRECTION OUTPUT ;
    USE SIGNAL ;
    PORT
      LAYER M3 ;
        RECT  118.908 43.162 118.926 43.2 ;
    END
  END rs_d[460]
  PIN rs_d[461]
    DIRECTION OUTPUT ;
    USE SIGNAL ;
    PORT
      LAYER M5 ;
        RECT  119.136 43.116 119.16 43.2 ;
    END
  END rs_d[461]
  PIN rs_d[462]
    DIRECTION OUTPUT ;
    USE SIGNAL ;
    PORT
      LAYER M3 ;
        RECT  119.376 43.162 119.394 43.2 ;
    END
  END rs_d[462]
  PIN rs_d[463]
    DIRECTION OUTPUT ;
    USE SIGNAL ;
    PORT
      LAYER M5 ;
        RECT  119.616 43.116 119.64 43.2 ;
    END
  END rs_d[463]
  PIN rs_d[464]
    DIRECTION OUTPUT ;
    USE SIGNAL ;
    PORT
      LAYER M3 ;
        RECT  119.88 43.162 119.898 43.2 ;
    END
  END rs_d[464]
  PIN rs_d[465]
    DIRECTION OUTPUT ;
    USE SIGNAL ;
    PORT
      LAYER M5 ;
        RECT  120.144 43.116 120.168 43.2 ;
    END
  END rs_d[465]
  PIN rs_d[466]
    DIRECTION OUTPUT ;
    USE SIGNAL ;
    PORT
      LAYER M3 ;
        RECT  120.384 43.162 120.402 43.2 ;
    END
  END rs_d[466]
  PIN rs_d[467]
    DIRECTION OUTPUT ;
    USE SIGNAL ;
    PORT
      LAYER M5 ;
        RECT  120.624 43.116 120.648 43.2 ;
    END
  END rs_d[467]
  PIN rs_d[468]
    DIRECTION OUTPUT ;
    USE SIGNAL ;
    PORT
      LAYER M3 ;
        RECT  120.888 43.162 120.906 43.2 ;
    END
  END rs_d[468]
  PIN rs_d[469]
    DIRECTION OUTPUT ;
    USE SIGNAL ;
    PORT
      LAYER M5 ;
        RECT  121.152 43.116 121.176 43.2 ;
    END
  END rs_d[469]
  PIN rs_d[46]
    DIRECTION OUTPUT ;
    USE SIGNAL ;
    PORT
      LAYER M3 ;
        RECT  16.056 43.162 16.074 43.2 ;
    END
  END rs_d[46]
  PIN rs_d[470]
    DIRECTION OUTPUT ;
    USE SIGNAL ;
    PORT
      LAYER M3 ;
        RECT  121.392 43.162 121.41 43.2 ;
    END
  END rs_d[470]
  PIN rs_d[471]
    DIRECTION OUTPUT ;
    USE SIGNAL ;
    PORT
      LAYER M5 ;
        RECT  121.632 43.116 121.656 43.2 ;
    END
  END rs_d[471]
  PIN rs_d[472]
    DIRECTION OUTPUT ;
    USE SIGNAL ;
    PORT
      LAYER M3 ;
        RECT  121.896 43.162 121.914 43.2 ;
    END
  END rs_d[472]
  PIN rs_d[473]
    DIRECTION OUTPUT ;
    USE SIGNAL ;
    PORT
      LAYER M5 ;
        RECT  122.112 43.116 122.136 43.2 ;
    END
  END rs_d[473]
  PIN rs_d[474]
    DIRECTION OUTPUT ;
    USE SIGNAL ;
    PORT
      LAYER M3 ;
        RECT  122.364 43.162 122.382 43.2 ;
    END
  END rs_d[474]
  PIN rs_d[475]
    DIRECTION OUTPUT ;
    USE SIGNAL ;
    PORT
      LAYER M5 ;
        RECT  122.64 43.116 122.664 43.2 ;
    END
  END rs_d[475]
  PIN rs_d[476]
    DIRECTION OUTPUT ;
    USE SIGNAL ;
    PORT
      LAYER M3 ;
        RECT  122.868 43.162 122.886 43.2 ;
    END
  END rs_d[476]
  PIN rs_d[477]
    DIRECTION OUTPUT ;
    USE SIGNAL ;
    PORT
      LAYER M5 ;
        RECT  123.12 43.116 123.144 43.2 ;
    END
  END rs_d[477]
  PIN rs_d[478]
    DIRECTION OUTPUT ;
    USE SIGNAL ;
    PORT
      LAYER M3 ;
        RECT  123.372 43.162 123.39 43.2 ;
    END
  END rs_d[478]
  PIN rs_d[479]
    DIRECTION OUTPUT ;
    USE SIGNAL ;
    PORT
      LAYER M5 ;
        RECT  123.6 43.116 123.624 43.2 ;
    END
  END rs_d[479]
  PIN rs_d[47]
    DIRECTION OUTPUT ;
    USE SIGNAL ;
    PORT
      LAYER M5 ;
        RECT  16.272 43.116 16.296 43.2 ;
    END
  END rs_d[47]
  PIN rs_d[480]
    DIRECTION OUTPUT ;
    USE SIGNAL ;
    PORT
      LAYER M3 ;
        RECT  123.876 43.162 123.894 43.2 ;
    END
  END rs_d[480]
  PIN rs_d[481]
    DIRECTION OUTPUT ;
    USE SIGNAL ;
    PORT
      LAYER M5 ;
        RECT  124.128 43.116 124.152 43.2 ;
    END
  END rs_d[481]
  PIN rs_d[482]
    DIRECTION OUTPUT ;
    USE SIGNAL ;
    PORT
      LAYER M3 ;
        RECT  124.38 43.162 124.398 43.2 ;
    END
  END rs_d[482]
  PIN rs_d[483]
    DIRECTION OUTPUT ;
    USE SIGNAL ;
    PORT
      LAYER M5 ;
        RECT  124.608 43.116 124.632 43.2 ;
    END
  END rs_d[483]
  PIN rs_d[484]
    DIRECTION OUTPUT ;
    USE SIGNAL ;
    PORT
      LAYER M3 ;
        RECT  124.848 43.162 124.866 43.2 ;
    END
  END rs_d[484]
  PIN rs_d[485]
    DIRECTION OUTPUT ;
    USE SIGNAL ;
    PORT
      LAYER M5 ;
        RECT  125.088 43.116 125.112 43.2 ;
    END
  END rs_d[485]
  PIN rs_d[486]
    DIRECTION OUTPUT ;
    USE SIGNAL ;
    PORT
      LAYER M3 ;
        RECT  125.352 43.162 125.37 43.2 ;
    END
  END rs_d[486]
  PIN rs_d[487]
    DIRECTION OUTPUT ;
    USE SIGNAL ;
    PORT
      LAYER M5 ;
        RECT  125.616 43.116 125.64 43.2 ;
    END
  END rs_d[487]
  PIN rs_d[488]
    DIRECTION OUTPUT ;
    USE SIGNAL ;
    PORT
      LAYER M3 ;
        RECT  125.856 43.162 125.874 43.2 ;
    END
  END rs_d[488]
  PIN rs_d[489]
    DIRECTION OUTPUT ;
    USE SIGNAL ;
    PORT
      LAYER M5 ;
        RECT  126.096 43.116 126.12 43.2 ;
    END
  END rs_d[489]
  PIN rs_d[48]
    DIRECTION OUTPUT ;
    USE SIGNAL ;
    PORT
      LAYER M3 ;
        RECT  16.524 43.162 16.542 43.2 ;
    END
  END rs_d[48]
  PIN rs_d[490]
    DIRECTION OUTPUT ;
    USE SIGNAL ;
    PORT
      LAYER M3 ;
        RECT  126.36 43.162 126.378 43.2 ;
    END
  END rs_d[490]
  PIN rs_d[491]
    DIRECTION OUTPUT ;
    USE SIGNAL ;
    PORT
      LAYER M5 ;
        RECT  126.576 43.116 126.6 43.2 ;
    END
  END rs_d[491]
  PIN rs_d[492]
    DIRECTION OUTPUT ;
    USE SIGNAL ;
    PORT
      LAYER M3 ;
        RECT  126.864 43.162 126.882 43.2 ;
    END
  END rs_d[492]
  PIN rs_d[493]
    DIRECTION OUTPUT ;
    USE SIGNAL ;
    PORT
      LAYER M5 ;
        RECT  127.104 43.116 127.128 43.2 ;
    END
  END rs_d[493]
  PIN rs_d[494]
    DIRECTION OUTPUT ;
    USE SIGNAL ;
    PORT
      LAYER M3 ;
        RECT  127.332 43.162 127.35 43.2 ;
    END
  END rs_d[494]
  PIN rs_d[495]
    DIRECTION OUTPUT ;
    USE SIGNAL ;
    PORT
      LAYER M5 ;
        RECT  127.584 43.116 127.608 43.2 ;
    END
  END rs_d[495]
  PIN rs_d[496]
    DIRECTION OUTPUT ;
    USE SIGNAL ;
    PORT
      LAYER M3 ;
        RECT  127.836 43.162 127.854 43.2 ;
    END
  END rs_d[496]
  PIN rs_d[497]
    DIRECTION OUTPUT ;
    USE SIGNAL ;
    PORT
      LAYER M5 ;
        RECT  128.064 43.116 128.088 43.2 ;
    END
  END rs_d[497]
  PIN rs_d[498]
    DIRECTION OUTPUT ;
    USE SIGNAL ;
    PORT
      LAYER M3 ;
        RECT  128.34 43.162 128.358 43.2 ;
    END
  END rs_d[498]
  PIN rs_d[499]
    DIRECTION OUTPUT ;
    USE SIGNAL ;
    PORT
      LAYER M5 ;
        RECT  128.592 43.116 128.616 43.2 ;
    END
  END rs_d[499]
  PIN rs_d[49]
    DIRECTION OUTPUT ;
    USE SIGNAL ;
    PORT
      LAYER M5 ;
        RECT  16.8 43.116 16.824 43.2 ;
    END
  END rs_d[49]
  PIN rs_d[4]
    DIRECTION OUTPUT ;
    USE SIGNAL ;
    PORT
      LAYER M3 ;
        RECT  5.616 43.162 5.634 43.2 ;
    END
  END rs_d[4]
  PIN rs_d[500]
    DIRECTION OUTPUT ;
    USE SIGNAL ;
    PORT
      LAYER M3 ;
        RECT  128.844 43.162 128.862 43.2 ;
    END
  END rs_d[500]
  PIN rs_d[501]
    DIRECTION OUTPUT ;
    USE SIGNAL ;
    PORT
      LAYER M5 ;
        RECT  129.072 43.116 129.096 43.2 ;
    END
  END rs_d[501]
  PIN rs_d[502]
    DIRECTION OUTPUT ;
    USE SIGNAL ;
    PORT
      LAYER M3 ;
        RECT  129.348 43.162 129.366 43.2 ;
    END
  END rs_d[502]
  PIN rs_d[503]
    DIRECTION OUTPUT ;
    USE SIGNAL ;
    PORT
      LAYER M5 ;
        RECT  129.6 43.116 129.624 43.2 ;
    END
  END rs_d[503]
  PIN rs_d[504]
    DIRECTION OUTPUT ;
    USE SIGNAL ;
    PORT
      LAYER M3 ;
        RECT  129.816 43.162 129.834 43.2 ;
    END
  END rs_d[504]
  PIN rs_d[505]
    DIRECTION OUTPUT ;
    USE SIGNAL ;
    PORT
      LAYER M5 ;
        RECT  130.08 43.116 130.104 43.2 ;
    END
  END rs_d[505]
  PIN rs_d[506]
    DIRECTION OUTPUT ;
    USE SIGNAL ;
    PORT
      LAYER M3 ;
        RECT  130.32 43.162 130.338 43.2 ;
    END
  END rs_d[506]
  PIN rs_d[507]
    DIRECTION OUTPUT ;
    USE SIGNAL ;
    PORT
      LAYER M5 ;
        RECT  130.56 43.116 130.584 43.2 ;
    END
  END rs_d[507]
  PIN rs_d[508]
    DIRECTION OUTPUT ;
    USE SIGNAL ;
    PORT
      LAYER M3 ;
        RECT  130.824 43.162 130.842 43.2 ;
    END
  END rs_d[508]
  PIN rs_d[509]
    DIRECTION OUTPUT ;
    USE SIGNAL ;
    PORT
      LAYER M5 ;
        RECT  131.088 43.116 131.112 43.2 ;
    END
  END rs_d[509]
  PIN rs_d[50]
    DIRECTION OUTPUT ;
    USE SIGNAL ;
    PORT
      LAYER M3 ;
        RECT  17.028 43.162 17.046 43.2 ;
    END
  END rs_d[50]
  PIN rs_d[510]
    DIRECTION OUTPUT ;
    USE SIGNAL ;
    PORT
      LAYER M3 ;
        RECT  131.328 43.162 131.346 43.2 ;
    END
  END rs_d[510]
  PIN rs_d[511]
    DIRECTION OUTPUT ;
    USE SIGNAL ;
    PORT
      LAYER M5 ;
        RECT  131.568 43.116 131.592 43.2 ;
    END
  END rs_d[511]
  PIN rs_d[512]
    DIRECTION OUTPUT ;
    USE SIGNAL ;
    PORT
      LAYER M3 ;
        RECT  131.832 43.162 131.85 43.2 ;
    END
  END rs_d[512]
  PIN rs_d[513]
    DIRECTION OUTPUT ;
    USE SIGNAL ;
    PORT
      LAYER M5 ;
        RECT  132.048 43.116 132.072 43.2 ;
    END
  END rs_d[513]
  PIN rs_d[514]
    DIRECTION OUTPUT ;
    USE SIGNAL ;
    PORT
      LAYER M3 ;
        RECT  132.3 43.162 132.318 43.2 ;
    END
  END rs_d[514]
  PIN rs_d[515]
    DIRECTION OUTPUT ;
    USE SIGNAL ;
    PORT
      LAYER M5 ;
        RECT  132.576 43.116 132.6 43.2 ;
    END
  END rs_d[515]
  PIN rs_d[516]
    DIRECTION OUTPUT ;
    USE SIGNAL ;
    PORT
      LAYER M3 ;
        RECT  132.804 43.162 132.822 43.2 ;
    END
  END rs_d[516]
  PIN rs_d[517]
    DIRECTION OUTPUT ;
    USE SIGNAL ;
    PORT
      LAYER M5 ;
        RECT  133.056 43.116 133.08 43.2 ;
    END
  END rs_d[517]
  PIN rs_d[518]
    DIRECTION OUTPUT ;
    USE SIGNAL ;
    PORT
      LAYER M3 ;
        RECT  133.308 43.162 133.326 43.2 ;
    END
  END rs_d[518]
  PIN rs_d[519]
    DIRECTION OUTPUT ;
    USE SIGNAL ;
    PORT
      LAYER M5 ;
        RECT  133.536 43.116 133.56 43.2 ;
    END
  END rs_d[519]
  PIN rs_d[51]
    DIRECTION OUTPUT ;
    USE SIGNAL ;
    PORT
      LAYER M5 ;
        RECT  17.28 43.116 17.304 43.2 ;
    END
  END rs_d[51]
  PIN rs_d[520]
    DIRECTION OUTPUT ;
    USE SIGNAL ;
    PORT
      LAYER M3 ;
        RECT  133.812 43.162 133.83 43.2 ;
    END
  END rs_d[520]
  PIN rs_d[521]
    DIRECTION OUTPUT ;
    USE SIGNAL ;
    PORT
      LAYER M5 ;
        RECT  134.064 43.116 134.088 43.2 ;
    END
  END rs_d[521]
  PIN rs_d[522]
    DIRECTION OUTPUT ;
    USE SIGNAL ;
    PORT
      LAYER M3 ;
        RECT  134.316 43.162 134.334 43.2 ;
    END
  END rs_d[522]
  PIN rs_d[523]
    DIRECTION OUTPUT ;
    USE SIGNAL ;
    PORT
      LAYER M5 ;
        RECT  134.544 43.116 134.568 43.2 ;
    END
  END rs_d[523]
  PIN rs_d[524]
    DIRECTION OUTPUT ;
    USE SIGNAL ;
    PORT
      LAYER M3 ;
        RECT  134.784 43.162 134.802 43.2 ;
    END
  END rs_d[524]
  PIN rs_d[525]
    DIRECTION OUTPUT ;
    USE SIGNAL ;
    PORT
      LAYER M5 ;
        RECT  135.024 43.116 135.048 43.2 ;
    END
  END rs_d[525]
  PIN rs_d[526]
    DIRECTION OUTPUT ;
    USE SIGNAL ;
    PORT
      LAYER M3 ;
        RECT  135.288 43.162 135.306 43.2 ;
    END
  END rs_d[526]
  PIN rs_d[527]
    DIRECTION OUTPUT ;
    USE SIGNAL ;
    PORT
      LAYER M5 ;
        RECT  135.552 43.116 135.576 43.2 ;
    END
  END rs_d[527]
  PIN rs_d[528]
    DIRECTION OUTPUT ;
    USE SIGNAL ;
    PORT
      LAYER M3 ;
        RECT  135.792 43.162 135.81 43.2 ;
    END
  END rs_d[528]
  PIN rs_d[529]
    DIRECTION OUTPUT ;
    USE SIGNAL ;
    PORT
      LAYER M5 ;
        RECT  136.032 43.116 136.056 43.2 ;
    END
  END rs_d[529]
  PIN rs_d[52]
    DIRECTION OUTPUT ;
    USE SIGNAL ;
    PORT
      LAYER M3 ;
        RECT  17.532 43.162 17.55 43.2 ;
    END
  END rs_d[52]
  PIN rs_d[530]
    DIRECTION OUTPUT ;
    USE SIGNAL ;
    PORT
      LAYER M3 ;
        RECT  136.296 43.162 136.314 43.2 ;
    END
  END rs_d[530]
  PIN rs_d[531]
    DIRECTION OUTPUT ;
    USE SIGNAL ;
    PORT
      LAYER M5 ;
        RECT  136.512 43.116 136.536 43.2 ;
    END
  END rs_d[531]
  PIN rs_d[532]
    DIRECTION OUTPUT ;
    USE SIGNAL ;
    PORT
      LAYER M3 ;
        RECT  136.8 43.162 136.818 43.2 ;
    END
  END rs_d[532]
  PIN rs_d[533]
    DIRECTION OUTPUT ;
    USE SIGNAL ;
    PORT
      LAYER M5 ;
        RECT  137.04 43.116 137.064 43.2 ;
    END
  END rs_d[533]
  PIN rs_d[534]
    DIRECTION OUTPUT ;
    USE SIGNAL ;
    PORT
      LAYER M3 ;
        RECT  137.268 43.162 137.286 43.2 ;
    END
  END rs_d[534]
  PIN rs_d[535]
    DIRECTION OUTPUT ;
    USE SIGNAL ;
    PORT
      LAYER M5 ;
        RECT  137.52 43.116 137.544 43.2 ;
    END
  END rs_d[535]
  PIN rs_d[536]
    DIRECTION OUTPUT ;
    USE SIGNAL ;
    PORT
      LAYER M3 ;
        RECT  137.772 43.162 137.79 43.2 ;
    END
  END rs_d[536]
  PIN rs_d[537]
    DIRECTION OUTPUT ;
    USE SIGNAL ;
    PORT
      LAYER M5 ;
        RECT  138 43.116 138.024 43.2 ;
    END
  END rs_d[537]
  PIN rs_d[538]
    DIRECTION OUTPUT ;
    USE SIGNAL ;
    PORT
      LAYER M3 ;
        RECT  138.276 43.162 138.294 43.2 ;
    END
  END rs_d[538]
  PIN rs_d[539]
    DIRECTION OUTPUT ;
    USE SIGNAL ;
    PORT
      LAYER M5 ;
        RECT  138.528 43.116 138.552 43.2 ;
    END
  END rs_d[539]
  PIN rs_d[53]
    DIRECTION OUTPUT ;
    USE SIGNAL ;
    PORT
      LAYER M5 ;
        RECT  17.76 43.116 17.784 43.2 ;
    END
  END rs_d[53]
  PIN rs_d[540]
    DIRECTION OUTPUT ;
    USE SIGNAL ;
    PORT
      LAYER M3 ;
        RECT  138.78 43.162 138.798 43.2 ;
    END
  END rs_d[540]
  PIN rs_d[541]
    DIRECTION OUTPUT ;
    USE SIGNAL ;
    PORT
      LAYER M5 ;
        RECT  139.008 43.116 139.032 43.2 ;
    END
  END rs_d[541]
  PIN rs_d[542]
    DIRECTION OUTPUT ;
    USE SIGNAL ;
    PORT
      LAYER M3 ;
        RECT  139.284 43.162 139.302 43.2 ;
    END
  END rs_d[542]
  PIN rs_d[543]
    DIRECTION OUTPUT ;
    USE SIGNAL ;
    PORT
      LAYER M5 ;
        RECT  139.536 43.116 139.56 43.2 ;
    END
  END rs_d[543]
  PIN rs_d[544]
    DIRECTION OUTPUT ;
    USE SIGNAL ;
    PORT
      LAYER M3 ;
        RECT  139.752 43.162 139.77 43.2 ;
    END
  END rs_d[544]
  PIN rs_d[545]
    DIRECTION OUTPUT ;
    USE SIGNAL ;
    PORT
      LAYER M5 ;
        RECT  140.016 43.116 140.04 43.2 ;
    END
  END rs_d[545]
  PIN rs_d[546]
    DIRECTION OUTPUT ;
    USE SIGNAL ;
    PORT
      LAYER M3 ;
        RECT  140.256 43.162 140.274 43.2 ;
    END
  END rs_d[546]
  PIN rs_d[547]
    DIRECTION OUTPUT ;
    USE SIGNAL ;
    PORT
      LAYER M5 ;
        RECT  140.496 43.116 140.52 43.2 ;
    END
  END rs_d[547]
  PIN rs_d[548]
    DIRECTION OUTPUT ;
    USE SIGNAL ;
    PORT
      LAYER M3 ;
        RECT  140.76 43.162 140.778 43.2 ;
    END
  END rs_d[548]
  PIN rs_d[549]
    DIRECTION OUTPUT ;
    USE SIGNAL ;
    PORT
      LAYER M5 ;
        RECT  141.024 43.116 141.048 43.2 ;
    END
  END rs_d[549]
  PIN rs_d[54]
    DIRECTION OUTPUT ;
    USE SIGNAL ;
    PORT
      LAYER M3 ;
        RECT  18.036 43.162 18.054 43.2 ;
    END
  END rs_d[54]
  PIN rs_d[550]
    DIRECTION OUTPUT ;
    USE SIGNAL ;
    PORT
      LAYER M3 ;
        RECT  141.264 43.162 141.282 43.2 ;
    END
  END rs_d[550]
  PIN rs_d[551]
    DIRECTION OUTPUT ;
    USE SIGNAL ;
    PORT
      LAYER M5 ;
        RECT  141.504 43.116 141.528 43.2 ;
    END
  END rs_d[551]
  PIN rs_d[552]
    DIRECTION OUTPUT ;
    USE SIGNAL ;
    PORT
      LAYER M3 ;
        RECT  141.768 43.162 141.786 43.2 ;
    END
  END rs_d[552]
  PIN rs_d[553]
    DIRECTION OUTPUT ;
    USE SIGNAL ;
    PORT
      LAYER M5 ;
        RECT  141.984 43.116 142.008 43.2 ;
    END
  END rs_d[553]
  PIN rs_d[554]
    DIRECTION OUTPUT ;
    USE SIGNAL ;
    PORT
      LAYER M3 ;
        RECT  142.236 43.162 142.254 43.2 ;
    END
  END rs_d[554]
  PIN rs_d[555]
    DIRECTION OUTPUT ;
    USE SIGNAL ;
    PORT
      LAYER M5 ;
        RECT  142.512 43.116 142.536 43.2 ;
    END
  END rs_d[555]
  PIN rs_d[556]
    DIRECTION OUTPUT ;
    USE SIGNAL ;
    PORT
      LAYER M3 ;
        RECT  142.74 43.162 142.758 43.2 ;
    END
  END rs_d[556]
  PIN rs_d[557]
    DIRECTION OUTPUT ;
    USE SIGNAL ;
    PORT
      LAYER M5 ;
        RECT  142.992 43.116 143.016 43.2 ;
    END
  END rs_d[557]
  PIN rs_d[558]
    DIRECTION OUTPUT ;
    USE SIGNAL ;
    PORT
      LAYER M3 ;
        RECT  143.244 43.162 143.262 43.2 ;
    END
  END rs_d[558]
  PIN rs_d[559]
    DIRECTION OUTPUT ;
    USE SIGNAL ;
    PORT
      LAYER M5 ;
        RECT  143.472 43.116 143.496 43.2 ;
    END
  END rs_d[559]
  PIN rs_d[55]
    DIRECTION OUTPUT ;
    USE SIGNAL ;
    PORT
      LAYER M5 ;
        RECT  18.288 43.116 18.312 43.2 ;
    END
  END rs_d[55]
  PIN rs_d[560]
    DIRECTION OUTPUT ;
    USE SIGNAL ;
    PORT
      LAYER M3 ;
        RECT  143.748 43.162 143.766 43.2 ;
    END
  END rs_d[560]
  PIN rs_d[561]
    DIRECTION OUTPUT ;
    USE SIGNAL ;
    PORT
      LAYER M5 ;
        RECT  144 43.116 144.024 43.2 ;
    END
  END rs_d[561]
  PIN rs_d[562]
    DIRECTION OUTPUT ;
    USE SIGNAL ;
    PORT
      LAYER M3 ;
        RECT  144.252 43.162 144.27 43.2 ;
    END
  END rs_d[562]
  PIN rs_d[563]
    DIRECTION OUTPUT ;
    USE SIGNAL ;
    PORT
      LAYER M5 ;
        RECT  144.48 43.116 144.504 43.2 ;
    END
  END rs_d[563]
  PIN rs_d[564]
    DIRECTION OUTPUT ;
    USE SIGNAL ;
    PORT
      LAYER M3 ;
        RECT  144.72 43.162 144.738 43.2 ;
    END
  END rs_d[564]
  PIN rs_d[565]
    DIRECTION OUTPUT ;
    USE SIGNAL ;
    PORT
      LAYER M5 ;
        RECT  144.96 43.116 144.984 43.2 ;
    END
  END rs_d[565]
  PIN rs_d[566]
    DIRECTION OUTPUT ;
    USE SIGNAL ;
    PORT
      LAYER M3 ;
        RECT  145.224 43.162 145.242 43.2 ;
    END
  END rs_d[566]
  PIN rs_d[567]
    DIRECTION OUTPUT ;
    USE SIGNAL ;
    PORT
      LAYER M5 ;
        RECT  145.488 43.116 145.512 43.2 ;
    END
  END rs_d[567]
  PIN rs_d[568]
    DIRECTION OUTPUT ;
    USE SIGNAL ;
    PORT
      LAYER M3 ;
        RECT  145.728 43.162 145.746 43.2 ;
    END
  END rs_d[568]
  PIN rs_d[569]
    DIRECTION OUTPUT ;
    USE SIGNAL ;
    PORT
      LAYER M5 ;
        RECT  145.968 43.116 145.992 43.2 ;
    END
  END rs_d[569]
  PIN rs_d[56]
    DIRECTION OUTPUT ;
    USE SIGNAL ;
    PORT
      LAYER M3 ;
        RECT  18.54 43.162 18.558 43.2 ;
    END
  END rs_d[56]
  PIN rs_d[570]
    DIRECTION OUTPUT ;
    USE SIGNAL ;
    PORT
      LAYER M3 ;
        RECT  146.232 43.162 146.25 43.2 ;
    END
  END rs_d[570]
  PIN rs_d[571]
    DIRECTION OUTPUT ;
    USE SIGNAL ;
    PORT
      LAYER M5 ;
        RECT  146.448 43.116 146.472 43.2 ;
    END
  END rs_d[571]
  PIN rs_d[572]
    DIRECTION OUTPUT ;
    USE SIGNAL ;
    PORT
      LAYER M3 ;
        RECT  146.736 43.162 146.754 43.2 ;
    END
  END rs_d[572]
  PIN rs_d[573]
    DIRECTION OUTPUT ;
    USE SIGNAL ;
    PORT
      LAYER M5 ;
        RECT  146.976 43.116 147 43.2 ;
    END
  END rs_d[573]
  PIN rs_d[574]
    DIRECTION OUTPUT ;
    USE SIGNAL ;
    PORT
      LAYER M3 ;
        RECT  147.204 43.162 147.222 43.2 ;
    END
  END rs_d[574]
  PIN rs_d[575]
    DIRECTION OUTPUT ;
    USE SIGNAL ;
    PORT
      LAYER M5 ;
        RECT  147.456 43.116 147.48 43.2 ;
    END
  END rs_d[575]
  PIN rs_d[576]
    DIRECTION OUTPUT ;
    USE SIGNAL ;
    PORT
      LAYER M3 ;
        RECT  147.708 43.162 147.726 43.2 ;
    END
  END rs_d[576]
  PIN rs_d[577]
    DIRECTION OUTPUT ;
    USE SIGNAL ;
    PORT
      LAYER M5 ;
        RECT  147.984 43.116 148.008 43.2 ;
    END
  END rs_d[577]
  PIN rs_d[578]
    DIRECTION OUTPUT ;
    USE SIGNAL ;
    PORT
      LAYER M3 ;
        RECT  148.212 43.162 148.23 43.2 ;
    END
  END rs_d[578]
  PIN rs_d[579]
    DIRECTION OUTPUT ;
    USE SIGNAL ;
    PORT
      LAYER M5 ;
        RECT  148.464 43.116 148.488 43.2 ;
    END
  END rs_d[579]
  PIN rs_d[57]
    DIRECTION OUTPUT ;
    USE SIGNAL ;
    PORT
      LAYER M5 ;
        RECT  18.768 43.116 18.792 43.2 ;
    END
  END rs_d[57]
  PIN rs_d[580]
    DIRECTION OUTPUT ;
    USE SIGNAL ;
    PORT
      LAYER M3 ;
        RECT  148.716 43.162 148.734 43.2 ;
    END
  END rs_d[580]
  PIN rs_d[581]
    DIRECTION OUTPUT ;
    USE SIGNAL ;
    PORT
      LAYER M5 ;
        RECT  148.944 43.116 148.968 43.2 ;
    END
  END rs_d[581]
  PIN rs_d[582]
    DIRECTION OUTPUT ;
    USE SIGNAL ;
    PORT
      LAYER M3 ;
        RECT  149.22 43.162 149.238 43.2 ;
    END
  END rs_d[582]
  PIN rs_d[583]
    DIRECTION OUTPUT ;
    USE SIGNAL ;
    PORT
      LAYER M5 ;
        RECT  149.472 43.116 149.496 43.2 ;
    END
  END rs_d[583]
  PIN rs_d[584]
    DIRECTION OUTPUT ;
    USE SIGNAL ;
    PORT
      LAYER M3 ;
        RECT  149.688 43.162 149.706 43.2 ;
    END
  END rs_d[584]
  PIN rs_d[585]
    DIRECTION OUTPUT ;
    USE SIGNAL ;
    PORT
      LAYER M5 ;
        RECT  149.952 43.116 149.976 43.2 ;
    END
  END rs_d[585]
  PIN rs_d[586]
    DIRECTION OUTPUT ;
    USE SIGNAL ;
    PORT
      LAYER M3 ;
        RECT  150.192 43.162 150.21 43.2 ;
    END
  END rs_d[586]
  PIN rs_d[587]
    DIRECTION OUTPUT ;
    USE SIGNAL ;
    PORT
      LAYER M5 ;
        RECT  150.432 43.116 150.456 43.2 ;
    END
  END rs_d[587]
  PIN rs_d[588]
    DIRECTION OUTPUT ;
    USE SIGNAL ;
    PORT
      LAYER M3 ;
        RECT  150.696 43.162 150.714 43.2 ;
    END
  END rs_d[588]
  PIN rs_d[589]
    DIRECTION OUTPUT ;
    USE SIGNAL ;
    PORT
      LAYER M5 ;
        RECT  150.96 43.116 150.984 43.2 ;
    END
  END rs_d[589]
  PIN rs_d[58]
    DIRECTION OUTPUT ;
    USE SIGNAL ;
    PORT
      LAYER M3 ;
        RECT  19.008 43.162 19.026 43.2 ;
    END
  END rs_d[58]
  PIN rs_d[590]
    DIRECTION OUTPUT ;
    USE SIGNAL ;
    PORT
      LAYER M3 ;
        RECT  151.2 43.162 151.218 43.2 ;
    END
  END rs_d[590]
  PIN rs_d[591]
    DIRECTION OUTPUT ;
    USE SIGNAL ;
    PORT
      LAYER M5 ;
        RECT  151.44 43.116 151.464 43.2 ;
    END
  END rs_d[591]
  PIN rs_d[592]
    DIRECTION OUTPUT ;
    USE SIGNAL ;
    PORT
      LAYER M3 ;
        RECT  151.704 43.162 151.722 43.2 ;
    END
  END rs_d[592]
  PIN rs_d[593]
    DIRECTION OUTPUT ;
    USE SIGNAL ;
    PORT
      LAYER M5 ;
        RECT  151.92 43.116 151.944 43.2 ;
    END
  END rs_d[593]
  PIN rs_d[594]
    DIRECTION OUTPUT ;
    USE SIGNAL ;
    PORT
      LAYER M3 ;
        RECT  152.172 43.162 152.19 43.2 ;
    END
  END rs_d[594]
  PIN rs_d[595]
    DIRECTION OUTPUT ;
    USE SIGNAL ;
    PORT
      LAYER M5 ;
        RECT  152.448 43.116 152.472 43.2 ;
    END
  END rs_d[595]
  PIN rs_d[596]
    DIRECTION OUTPUT ;
    USE SIGNAL ;
    PORT
      LAYER M3 ;
        RECT  152.676 43.162 152.694 43.2 ;
    END
  END rs_d[596]
  PIN rs_d[597]
    DIRECTION OUTPUT ;
    USE SIGNAL ;
    PORT
      LAYER M5 ;
        RECT  152.928 43.116 152.952 43.2 ;
    END
  END rs_d[597]
  PIN rs_d[598]
    DIRECTION OUTPUT ;
    USE SIGNAL ;
    PORT
      LAYER M3 ;
        RECT  153.18 43.162 153.198 43.2 ;
    END
  END rs_d[598]
  PIN rs_d[599]
    DIRECTION OUTPUT ;
    USE SIGNAL ;
    PORT
      LAYER M5 ;
        RECT  153.408 43.116 153.432 43.2 ;
    END
  END rs_d[599]
  PIN rs_d[59]
    DIRECTION OUTPUT ;
    USE SIGNAL ;
    PORT
      LAYER M5 ;
        RECT  19.248 43.116 19.272 43.2 ;
    END
  END rs_d[59]
  PIN rs_d[5]
    DIRECTION OUTPUT ;
    USE SIGNAL ;
    PORT
      LAYER M5 ;
        RECT  5.856 43.116 5.88 43.2 ;
    END
  END rs_d[5]
  PIN rs_d[600]
    DIRECTION OUTPUT ;
    USE SIGNAL ;
    PORT
      LAYER M3 ;
        RECT  153.684 43.162 153.702 43.2 ;
    END
  END rs_d[600]
  PIN rs_d[601]
    DIRECTION OUTPUT ;
    USE SIGNAL ;
    PORT
      LAYER M5 ;
        RECT  153.936 43.116 153.96 43.2 ;
    END
  END rs_d[601]
  PIN rs_d[602]
    DIRECTION OUTPUT ;
    USE SIGNAL ;
    PORT
      LAYER M3 ;
        RECT  154.188 43.162 154.206 43.2 ;
    END
  END rs_d[602]
  PIN rs_d[603]
    DIRECTION OUTPUT ;
    USE SIGNAL ;
    PORT
      LAYER M5 ;
        RECT  154.416 43.116 154.44 43.2 ;
    END
  END rs_d[603]
  PIN rs_d[604]
    DIRECTION OUTPUT ;
    USE SIGNAL ;
    PORT
      LAYER M3 ;
        RECT  154.656 43.162 154.674 43.2 ;
    END
  END rs_d[604]
  PIN rs_d[605]
    DIRECTION OUTPUT ;
    USE SIGNAL ;
    PORT
      LAYER M5 ;
        RECT  154.896 43.116 154.92 43.2 ;
    END
  END rs_d[605]
  PIN rs_d[606]
    DIRECTION OUTPUT ;
    USE SIGNAL ;
    PORT
      LAYER M3 ;
        RECT  155.16 43.162 155.178 43.2 ;
    END
  END rs_d[606]
  PIN rs_d[607]
    DIRECTION OUTPUT ;
    USE SIGNAL ;
    PORT
      LAYER M5 ;
        RECT  155.424 43.116 155.448 43.2 ;
    END
  END rs_d[607]
  PIN rs_d[608]
    DIRECTION OUTPUT ;
    USE SIGNAL ;
    PORT
      LAYER M3 ;
        RECT  155.664 43.162 155.682 43.2 ;
    END
  END rs_d[608]
  PIN rs_d[609]
    DIRECTION OUTPUT ;
    USE SIGNAL ;
    PORT
      LAYER M5 ;
        RECT  155.904 43.116 155.928 43.2 ;
    END
  END rs_d[609]
  PIN rs_d[60]
    DIRECTION OUTPUT ;
    USE SIGNAL ;
    PORT
      LAYER M3 ;
        RECT  19.512 43.162 19.53 43.2 ;
    END
  END rs_d[60]
  PIN rs_d[610]
    DIRECTION OUTPUT ;
    USE SIGNAL ;
    PORT
      LAYER M3 ;
        RECT  156.168 43.162 156.186 43.2 ;
    END
  END rs_d[610]
  PIN rs_d[611]
    DIRECTION OUTPUT ;
    USE SIGNAL ;
    PORT
      LAYER M5 ;
        RECT  156.432 43.116 156.456 43.2 ;
    END
  END rs_d[611]
  PIN rs_d[612]
    DIRECTION OUTPUT ;
    USE SIGNAL ;
    PORT
      LAYER M3 ;
        RECT  156.672 43.162 156.69 43.2 ;
    END
  END rs_d[612]
  PIN rs_d[613]
    DIRECTION OUTPUT ;
    USE SIGNAL ;
    PORT
      LAYER M5 ;
        RECT  156.912 43.116 156.936 43.2 ;
    END
  END rs_d[613]
  PIN rs_d[614]
    DIRECTION OUTPUT ;
    USE SIGNAL ;
    PORT
      LAYER M3 ;
        RECT  157.14 43.162 157.158 43.2 ;
    END
  END rs_d[614]
  PIN rs_d[615]
    DIRECTION OUTPUT ;
    USE SIGNAL ;
    PORT
      LAYER M5 ;
        RECT  157.392 43.116 157.416 43.2 ;
    END
  END rs_d[615]
  PIN rs_d[616]
    DIRECTION OUTPUT ;
    USE SIGNAL ;
    PORT
      LAYER M3 ;
        RECT  157.644 43.162 157.662 43.2 ;
    END
  END rs_d[616]
  PIN rs_d[617]
    DIRECTION OUTPUT ;
    USE SIGNAL ;
    PORT
      LAYER M5 ;
        RECT  157.92 43.116 157.944 43.2 ;
    END
  END rs_d[617]
  PIN rs_d[618]
    DIRECTION OUTPUT ;
    USE SIGNAL ;
    PORT
      LAYER M3 ;
        RECT  158.148 43.162 158.166 43.2 ;
    END
  END rs_d[618]
  PIN rs_d[619]
    DIRECTION OUTPUT ;
    USE SIGNAL ;
    PORT
      LAYER M5 ;
        RECT  158.4 43.116 158.424 43.2 ;
    END
  END rs_d[619]
  PIN rs_d[61]
    DIRECTION OUTPUT ;
    USE SIGNAL ;
    PORT
      LAYER M5 ;
        RECT  19.776 43.116 19.8 43.2 ;
    END
  END rs_d[61]
  PIN rs_d[620]
    DIRECTION OUTPUT ;
    USE SIGNAL ;
    PORT
      LAYER M3 ;
        RECT  158.652 43.162 158.67 43.2 ;
    END
  END rs_d[620]
  PIN rs_d[621]
    DIRECTION OUTPUT ;
    USE SIGNAL ;
    PORT
      LAYER M5 ;
        RECT  158.88 43.116 158.904 43.2 ;
    END
  END rs_d[621]
  PIN rs_d[622]
    DIRECTION OUTPUT ;
    USE SIGNAL ;
    PORT
      LAYER M3 ;
        RECT  159.156 43.162 159.174 43.2 ;
    END
  END rs_d[622]
  PIN rs_d[623]
    DIRECTION OUTPUT ;
    USE SIGNAL ;
    PORT
      LAYER M5 ;
        RECT  159.408 43.116 159.432 43.2 ;
    END
  END rs_d[623]
  PIN rs_d[624]
    DIRECTION OUTPUT ;
    USE SIGNAL ;
    PORT
      LAYER M3 ;
        RECT  159.624 43.162 159.642 43.2 ;
    END
  END rs_d[624]
  PIN rs_d[625]
    DIRECTION OUTPUT ;
    USE SIGNAL ;
    PORT
      LAYER M5 ;
        RECT  159.888 43.116 159.912 43.2 ;
    END
  END rs_d[625]
  PIN rs_d[626]
    DIRECTION OUTPUT ;
    USE SIGNAL ;
    PORT
      LAYER M3 ;
        RECT  160.128 43.162 160.146 43.2 ;
    END
  END rs_d[626]
  PIN rs_d[627]
    DIRECTION OUTPUT ;
    USE SIGNAL ;
    PORT
      LAYER M5 ;
        RECT  160.368 43.116 160.392 43.2 ;
    END
  END rs_d[627]
  PIN rs_d[628]
    DIRECTION OUTPUT ;
    USE SIGNAL ;
    PORT
      LAYER M3 ;
        RECT  160.632 43.162 160.65 43.2 ;
    END
  END rs_d[628]
  PIN rs_d[629]
    DIRECTION OUTPUT ;
    USE SIGNAL ;
    PORT
      LAYER M5 ;
        RECT  160.896 43.116 160.92 43.2 ;
    END
  END rs_d[629]
  PIN rs_d[62]
    DIRECTION OUTPUT ;
    USE SIGNAL ;
    PORT
      LAYER M3 ;
        RECT  20.016 43.162 20.034 43.2 ;
    END
  END rs_d[62]
  PIN rs_d[630]
    DIRECTION OUTPUT ;
    USE SIGNAL ;
    PORT
      LAYER M3 ;
        RECT  161.136 43.162 161.154 43.2 ;
    END
  END rs_d[630]
  PIN rs_d[631]
    DIRECTION OUTPUT ;
    USE SIGNAL ;
    PORT
      LAYER M5 ;
        RECT  161.376 43.116 161.4 43.2 ;
    END
  END rs_d[631]
  PIN rs_d[632]
    DIRECTION OUTPUT ;
    USE SIGNAL ;
    PORT
      LAYER M3 ;
        RECT  161.64 43.162 161.658 43.2 ;
    END
  END rs_d[632]
  PIN rs_d[633]
    DIRECTION OUTPUT ;
    USE SIGNAL ;
    PORT
      LAYER M5 ;
        RECT  161.856 43.116 161.88 43.2 ;
    END
  END rs_d[633]
  PIN rs_d[634]
    DIRECTION OUTPUT ;
    USE SIGNAL ;
    PORT
      LAYER M3 ;
        RECT  162.108 43.162 162.126 43.2 ;
    END
  END rs_d[634]
  PIN rs_d[635]
    DIRECTION OUTPUT ;
    USE SIGNAL ;
    PORT
      LAYER M5 ;
        RECT  162.384 43.116 162.408 43.2 ;
    END
  END rs_d[635]
  PIN rs_d[636]
    DIRECTION OUTPUT ;
    USE SIGNAL ;
    PORT
      LAYER M3 ;
        RECT  162.612 43.162 162.63 43.2 ;
    END
  END rs_d[636]
  PIN rs_d[637]
    DIRECTION OUTPUT ;
    USE SIGNAL ;
    PORT
      LAYER M5 ;
        RECT  162.864 43.116 162.888 43.2 ;
    END
  END rs_d[637]
  PIN rs_d[638]
    DIRECTION OUTPUT ;
    USE SIGNAL ;
    PORT
      LAYER M3 ;
        RECT  163.116 43.162 163.134 43.2 ;
    END
  END rs_d[638]
  PIN rs_d[639]
    DIRECTION OUTPUT ;
    USE SIGNAL ;
    PORT
      LAYER M5 ;
        RECT  163.344 43.116 163.368 43.2 ;
    END
  END rs_d[639]
  PIN rs_d[63]
    DIRECTION OUTPUT ;
    USE SIGNAL ;
    PORT
      LAYER M5 ;
        RECT  20.256 43.116 20.28 43.2 ;
    END
  END rs_d[63]
  PIN rs_d[64]
    DIRECTION OUTPUT ;
    USE SIGNAL ;
    PORT
      LAYER M3 ;
        RECT  20.52 43.162 20.538 43.2 ;
    END
  END rs_d[64]
  PIN rs_d[65]
    DIRECTION OUTPUT ;
    USE SIGNAL ;
    PORT
      LAYER M5 ;
        RECT  20.784 43.116 20.808 43.2 ;
    END
  END rs_d[65]
  PIN rs_d[66]
    DIRECTION OUTPUT ;
    USE SIGNAL ;
    PORT
      LAYER M3 ;
        RECT  21.024 43.162 21.042 43.2 ;
    END
  END rs_d[66]
  PIN rs_d[67]
    DIRECTION OUTPUT ;
    USE SIGNAL ;
    PORT
      LAYER M5 ;
        RECT  21.264 43.116 21.288 43.2 ;
    END
  END rs_d[67]
  PIN rs_d[68]
    DIRECTION OUTPUT ;
    USE SIGNAL ;
    PORT
      LAYER M3 ;
        RECT  21.492 43.162 21.51 43.2 ;
    END
  END rs_d[68]
  PIN rs_d[69]
    DIRECTION OUTPUT ;
    USE SIGNAL ;
    PORT
      LAYER M5 ;
        RECT  21.744 43.116 21.768 43.2 ;
    END
  END rs_d[69]
  PIN rs_d[6]
    DIRECTION OUTPUT ;
    USE SIGNAL ;
    PORT
      LAYER M3 ;
        RECT  6.12 43.162 6.138 43.2 ;
    END
  END rs_d[6]
  PIN rs_d[70]
    DIRECTION OUTPUT ;
    USE SIGNAL ;
    PORT
      LAYER M3 ;
        RECT  21.996 43.162 22.014 43.2 ;
    END
  END rs_d[70]
  PIN rs_d[71]
    DIRECTION OUTPUT ;
    USE SIGNAL ;
    PORT
      LAYER M5 ;
        RECT  22.272 43.116 22.296 43.2 ;
    END
  END rs_d[71]
  PIN rs_d[72]
    DIRECTION OUTPUT ;
    USE SIGNAL ;
    PORT
      LAYER M3 ;
        RECT  22.5 43.162 22.518 43.2 ;
    END
  END rs_d[72]
  PIN rs_d[73]
    DIRECTION OUTPUT ;
    USE SIGNAL ;
    PORT
      LAYER M5 ;
        RECT  22.752 43.116 22.776 43.2 ;
    END
  END rs_d[73]
  PIN rs_d[74]
    DIRECTION OUTPUT ;
    USE SIGNAL ;
    PORT
      LAYER M3 ;
        RECT  23.004 43.162 23.022 43.2 ;
    END
  END rs_d[74]
  PIN rs_d[75]
    DIRECTION OUTPUT ;
    USE SIGNAL ;
    PORT
      LAYER M5 ;
        RECT  23.232 43.116 23.256 43.2 ;
    END
  END rs_d[75]
  PIN rs_d[76]
    DIRECTION OUTPUT ;
    USE SIGNAL ;
    PORT
      LAYER M3 ;
        RECT  23.508 43.162 23.526 43.2 ;
    END
  END rs_d[76]
  PIN rs_d[77]
    DIRECTION OUTPUT ;
    USE SIGNAL ;
    PORT
      LAYER M5 ;
        RECT  23.76 43.116 23.784 43.2 ;
    END
  END rs_d[77]
  PIN rs_d[78]
    DIRECTION OUTPUT ;
    USE SIGNAL ;
    PORT
      LAYER M3 ;
        RECT  23.976 43.162 23.994 43.2 ;
    END
  END rs_d[78]
  PIN rs_d[79]
    DIRECTION OUTPUT ;
    USE SIGNAL ;
    PORT
      LAYER M5 ;
        RECT  24.24 43.116 24.264 43.2 ;
    END
  END rs_d[79]
  PIN rs_d[7]
    DIRECTION OUTPUT ;
    USE SIGNAL ;
    PORT
      LAYER M5 ;
        RECT  6.336 43.116 6.36 43.2 ;
    END
  END rs_d[7]
  PIN rs_d[80]
    DIRECTION OUTPUT ;
    USE SIGNAL ;
    PORT
      LAYER M3 ;
        RECT  24.48 43.162 24.498 43.2 ;
    END
  END rs_d[80]
  PIN rs_d[81]
    DIRECTION OUTPUT ;
    USE SIGNAL ;
    PORT
      LAYER M5 ;
        RECT  24.72 43.116 24.744 43.2 ;
    END
  END rs_d[81]
  PIN rs_d[82]
    DIRECTION OUTPUT ;
    USE SIGNAL ;
    PORT
      LAYER M3 ;
        RECT  24.984 43.162 25.002 43.2 ;
    END
  END rs_d[82]
  PIN rs_d[83]
    DIRECTION OUTPUT ;
    USE SIGNAL ;
    PORT
      LAYER M5 ;
        RECT  25.248 43.116 25.272 43.2 ;
    END
  END rs_d[83]
  PIN rs_d[84]
    DIRECTION OUTPUT ;
    USE SIGNAL ;
    PORT
      LAYER M3 ;
        RECT  25.488 43.162 25.506 43.2 ;
    END
  END rs_d[84]
  PIN rs_d[85]
    DIRECTION OUTPUT ;
    USE SIGNAL ;
    PORT
      LAYER M5 ;
        RECT  25.728 43.116 25.752 43.2 ;
    END
  END rs_d[85]
  PIN rs_d[86]
    DIRECTION OUTPUT ;
    USE SIGNAL ;
    PORT
      LAYER M3 ;
        RECT  25.992 43.162 26.01 43.2 ;
    END
  END rs_d[86]
  PIN rs_d[87]
    DIRECTION OUTPUT ;
    USE SIGNAL ;
    PORT
      LAYER M5 ;
        RECT  26.208 43.116 26.232 43.2 ;
    END
  END rs_d[87]
  PIN rs_d[88]
    DIRECTION OUTPUT ;
    USE SIGNAL ;
    PORT
      LAYER M3 ;
        RECT  26.496 43.162 26.514 43.2 ;
    END
  END rs_d[88]
  PIN rs_d[89]
    DIRECTION OUTPUT ;
    USE SIGNAL ;
    PORT
      LAYER M5 ;
        RECT  26.736 43.116 26.76 43.2 ;
    END
  END rs_d[89]
  PIN rs_d[8]
    DIRECTION OUTPUT ;
    USE SIGNAL ;
    PORT
      LAYER M3 ;
        RECT  6.588 43.162 6.606 43.2 ;
    END
  END rs_d[8]
  PIN rs_d[90]
    DIRECTION OUTPUT ;
    USE SIGNAL ;
    PORT
      LAYER M3 ;
        RECT  26.964 43.162 26.982 43.2 ;
    END
  END rs_d[90]
  PIN rs_d[91]
    DIRECTION OUTPUT ;
    USE SIGNAL ;
    PORT
      LAYER M5 ;
        RECT  27.216 43.116 27.24 43.2 ;
    END
  END rs_d[91]
  PIN rs_d[92]
    DIRECTION OUTPUT ;
    USE SIGNAL ;
    PORT
      LAYER M3 ;
        RECT  27.468 43.162 27.486 43.2 ;
    END
  END rs_d[92]
  PIN rs_d[93]
    DIRECTION OUTPUT ;
    USE SIGNAL ;
    PORT
      LAYER M5 ;
        RECT  27.696 43.116 27.72 43.2 ;
    END
  END rs_d[93]
  PIN rs_d[94]
    DIRECTION OUTPUT ;
    USE SIGNAL ;
    PORT
      LAYER M3 ;
        RECT  27.972 43.162 27.99 43.2 ;
    END
  END rs_d[94]
  PIN rs_d[95]
    DIRECTION OUTPUT ;
    USE SIGNAL ;
    PORT
      LAYER M5 ;
        RECT  28.224 43.116 28.248 43.2 ;
    END
  END rs_d[95]
  PIN rs_d[96]
    DIRECTION OUTPUT ;
    USE SIGNAL ;
    PORT
      LAYER M3 ;
        RECT  28.476 43.162 28.494 43.2 ;
    END
  END rs_d[96]
  PIN rs_d[97]
    DIRECTION OUTPUT ;
    USE SIGNAL ;
    PORT
      LAYER M5 ;
        RECT  28.704 43.116 28.728 43.2 ;
    END
  END rs_d[97]
  PIN rs_d[98]
    DIRECTION OUTPUT ;
    USE SIGNAL ;
    PORT
      LAYER M3 ;
        RECT  28.98 43.162 28.998 43.2 ;
    END
  END rs_d[98]
  PIN rs_d[99]
    DIRECTION OUTPUT ;
    USE SIGNAL ;
    PORT
      LAYER M5 ;
        RECT  29.232 43.116 29.256 43.2 ;
    END
  END rs_d[99]
  PIN rs_d[9]
    DIRECTION OUTPUT ;
    USE SIGNAL ;
    PORT
      LAYER M5 ;
        RECT  6.864 43.116 6.888 43.2 ;
    END
  END rs_d[9]
  PIN rs_v[0]
    DIRECTION OUTPUT ;
    USE SIGNAL ;
    PORT
      LAYER M3 ;
        RECT  0.792 43.162 0.81 43.2 ;
    END
  END rs_v[0]
  PIN rs_v[1]
    DIRECTION OUTPUT ;
    USE SIGNAL ;
    PORT
      LAYER M5 ;
        RECT  1.392 43.116 1.416 43.2 ;
    END
  END rs_v[1]
  PIN rs_v[2]
    DIRECTION OUTPUT ;
    USE SIGNAL ;
    PORT
      LAYER M3 ;
        RECT  1.98 43.162 1.998 43.2 ;
    END
  END rs_v[2]
  PIN rs_v[3]
    DIRECTION OUTPUT ;
    USE SIGNAL ;
    PORT
      LAYER M5 ;
        RECT  2.592 43.116 2.616 43.2 ;
    END
  END rs_v[3]
  PIN rs_v[4]
    DIRECTION OUTPUT ;
    USE SIGNAL ;
    PORT
      LAYER M3 ;
        RECT  3.204 43.162 3.222 43.2 ;
    END
  END rs_v[4]
  PIN rst
    DIRECTION INPUT ;
    USE SIGNAL ;
    PORT
      LAYER M4 ;
        RECT  0 24.48 0.084 24.504 ;
    END
  END rst
  PIN v_own[0]
    DIRECTION INPUT ;
    USE SIGNAL ;
    PORT
      LAYER M4 ;
        RECT  0 2.4 0.084 2.424 ;
    END
  END v_own[0]
  PIN v_own[1]
    DIRECTION INPUT ;
    USE SIGNAL ;
    PORT
      LAYER M4 ;
        RECT  0 3.168 0.084 3.192 ;
    END
  END v_own[1]
  PIN v_own[2]
    DIRECTION INPUT ;
    USE SIGNAL ;
    PORT
      LAYER M4 ;
        RECT  0 3.984 0.084 4.008 ;
    END
  END v_own[2]
  PIN v_own[3]
    DIRECTION INPUT ;
    USE SIGNAL ;
    PORT
      LAYER M4 ;
        RECT  0 4.8 0.084 4.824 ;
    END
  END v_own[3]
  PIN v_own[4]
    DIRECTION INPUT ;
    USE SIGNAL ;
    PORT
      LAYER M4 ;
        RECT  0 5.568 0.084 5.592 ;
    END
  END v_own[4]
  PIN v_sh[0]
    DIRECTION INPUT ;
    USE SIGNAL ;
    PORT
      LAYER M4 ;
        RECT  0 9.504 0.084 9.528 ;
    END
  END v_sh[0]
  PIN v_sh[1]
    DIRECTION INPUT ;
    USE SIGNAL ;
    PORT
      LAYER M4 ;
        RECT  0 10.512 0.084 10.536 ;
    END
  END v_sh[1]
  PIN vtag
    DIRECTION INPUT ;
    USE SIGNAL ;
    PORT
      LAYER M4 ;
        RECT  0 12.48 0.084 12.504 ;
    END
  END vtag
  PIN w[0]
    DIRECTION INPUT ;
    USE SIGNAL ;
    PORT
      LAYER M3 ;
        RECT  117.072 0 117.09 0.038 ;
    END
  END w[0]
  PIN w[100]
    DIRECTION INPUT ;
    USE SIGNAL ;
    PORT
      LAYER M3 ;
        RECT  135.252 0 135.27 0.038 ;
    END
  END w[100]
  PIN w[101]
    DIRECTION INPUT ;
    USE SIGNAL ;
    PORT
      LAYER M5 ;
        RECT  135.408 0 135.432 0.084 ;
    END
  END w[101]
  PIN w[102]
    DIRECTION INPUT ;
    USE SIGNAL ;
    PORT
      LAYER M3 ;
        RECT  135.612 0 135.63 0.038 ;
    END
  END w[102]
  PIN w[103]
    DIRECTION INPUT ;
    USE SIGNAL ;
    PORT
      LAYER M5 ;
        RECT  135.792 0 135.816 0.084 ;
    END
  END w[103]
  PIN w[104]
    DIRECTION INPUT ;
    USE SIGNAL ;
    PORT
      LAYER M3 ;
        RECT  135.972 0 135.99 0.038 ;
    END
  END w[104]
  PIN w[105]
    DIRECTION INPUT ;
    USE SIGNAL ;
    PORT
      LAYER M5 ;
        RECT  136.128 0 136.152 0.084 ;
    END
  END w[105]
  PIN w[106]
    DIRECTION INPUT ;
    USE SIGNAL ;
    PORT
      LAYER M3 ;
        RECT  136.332 0 136.35 0.038 ;
    END
  END w[106]
  PIN w[107]
    DIRECTION INPUT ;
    USE SIGNAL ;
    PORT
      LAYER M5 ;
        RECT  136.512 0 136.536 0.084 ;
    END
  END w[107]
  PIN w[108]
    DIRECTION INPUT ;
    USE SIGNAL ;
    PORT
      LAYER M3 ;
        RECT  136.692 0 136.71 0.038 ;
    END
  END w[108]
  PIN w[109]
    DIRECTION INPUT ;
    USE SIGNAL ;
    PORT
      LAYER M5 ;
        RECT  136.896 0 136.92 0.084 ;
    END
  END w[109]
  PIN w[10]
    DIRECTION INPUT ;
    USE SIGNAL ;
    PORT
      LAYER M3 ;
        RECT  118.908 0 118.926 0.038 ;
    END
  END w[10]
  PIN w[110]
    DIRECTION INPUT ;
    USE SIGNAL ;
    PORT
      LAYER M3 ;
        RECT  137.052 0 137.07 0.038 ;
    END
  END w[110]
  PIN w[111]
    DIRECTION INPUT ;
    USE SIGNAL ;
    PORT
      LAYER M5 ;
        RECT  137.232 0 137.256 0.084 ;
    END
  END w[111]
  PIN w[112]
    DIRECTION INPUT ;
    USE SIGNAL ;
    PORT
      LAYER M3 ;
        RECT  137.412 0 137.43 0.038 ;
    END
  END w[112]
  PIN w[113]
    DIRECTION INPUT ;
    USE SIGNAL ;
    PORT
      LAYER M5 ;
        RECT  137.616 0 137.64 0.084 ;
    END
  END w[113]
  PIN w[114]
    DIRECTION INPUT ;
    USE SIGNAL ;
    PORT
      LAYER M3 ;
        RECT  137.772 0 137.79 0.038 ;
    END
  END w[114]
  PIN w[115]
    DIRECTION INPUT ;
    USE SIGNAL ;
    PORT
      LAYER M5 ;
        RECT  137.952 0 137.976 0.084 ;
    END
  END w[115]
  PIN w[116]
    DIRECTION INPUT ;
    USE SIGNAL ;
    PORT
      LAYER M3 ;
        RECT  138.168 0 138.186 0.038 ;
    END
  END w[116]
  PIN w[117]
    DIRECTION INPUT ;
    USE SIGNAL ;
    PORT
      LAYER M5 ;
        RECT  138.336 0 138.36 0.084 ;
    END
  END w[117]
  PIN w[118]
    DIRECTION INPUT ;
    USE SIGNAL ;
    PORT
      LAYER M3 ;
        RECT  138.528 0 138.546 0.038 ;
    END
  END w[118]
  PIN w[119]
    DIRECTION INPUT ;
    USE SIGNAL ;
    PORT
      LAYER M5 ;
        RECT  138.672 0 138.696 0.084 ;
    END
  END w[119]
  PIN w[11]
    DIRECTION INPUT ;
    USE SIGNAL ;
    PORT
      LAYER M5 ;
        RECT  119.088 0 119.112 0.084 ;
    END
  END w[11]
  PIN w[120]
    DIRECTION INPUT ;
    USE SIGNAL ;
    PORT
      LAYER M3 ;
        RECT  138.888 0 138.906 0.038 ;
    END
  END w[120]
  PIN w[121]
    DIRECTION INPUT ;
    USE SIGNAL ;
    PORT
      LAYER M5 ;
        RECT  139.056 0 139.08 0.084 ;
    END
  END w[121]
  PIN w[122]
    DIRECTION INPUT ;
    USE SIGNAL ;
    PORT
      LAYER M3 ;
        RECT  139.248 0 139.266 0.038 ;
    END
  END w[122]
  PIN w[123]
    DIRECTION INPUT ;
    USE SIGNAL ;
    PORT
      LAYER M5 ;
        RECT  139.44 0 139.464 0.084 ;
    END
  END w[123]
  PIN w[124]
    DIRECTION INPUT ;
    USE SIGNAL ;
    PORT
      LAYER M3 ;
        RECT  139.608 0 139.626 0.038 ;
    END
  END w[124]
  PIN w[125]
    DIRECTION INPUT ;
    USE SIGNAL ;
    PORT
      LAYER M5 ;
        RECT  139.776 0 139.8 0.084 ;
    END
  END w[125]
  PIN w[126]
    DIRECTION INPUT ;
    USE SIGNAL ;
    PORT
      LAYER M3 ;
        RECT  139.968 0 139.986 0.038 ;
    END
  END w[126]
  PIN w[127]
    DIRECTION INPUT ;
    USE SIGNAL ;
    PORT
      LAYER M5 ;
        RECT  140.16 0 140.184 0.084 ;
    END
  END w[127]
  PIN w[128]
    DIRECTION INPUT ;
    USE SIGNAL ;
    PORT
      LAYER M3 ;
        RECT  140.328 0 140.346 0.038 ;
    END
  END w[128]
  PIN w[129]
    DIRECTION INPUT ;
    USE SIGNAL ;
    PORT
      LAYER M5 ;
        RECT  140.496 0 140.52 0.084 ;
    END
  END w[129]
  PIN w[12]
    DIRECTION INPUT ;
    USE SIGNAL ;
    PORT
      LAYER M3 ;
        RECT  119.268 0 119.286 0.038 ;
    END
  END w[12]
  PIN w[130]
    DIRECTION INPUT ;
    USE SIGNAL ;
    PORT
      LAYER M3 ;
        RECT  140.688 0 140.706 0.038 ;
    END
  END w[130]
  PIN w[131]
    DIRECTION INPUT ;
    USE SIGNAL ;
    PORT
      LAYER M5 ;
        RECT  140.88 0 140.904 0.084 ;
    END
  END w[131]
  PIN w[132]
    DIRECTION INPUT ;
    USE SIGNAL ;
    PORT
      LAYER M3 ;
        RECT  141.048 0 141.066 0.038 ;
    END
  END w[132]
  PIN w[133]
    DIRECTION INPUT ;
    USE SIGNAL ;
    PORT
      LAYER M5 ;
        RECT  141.216 0 141.24 0.084 ;
    END
  END w[133]
  PIN w[134]
    DIRECTION INPUT ;
    USE SIGNAL ;
    PORT
      LAYER M3 ;
        RECT  141.408 0 141.426 0.038 ;
    END
  END w[134]
  PIN w[135]
    DIRECTION INPUT ;
    USE SIGNAL ;
    PORT
      LAYER M5 ;
        RECT  141.6 0 141.624 0.084 ;
    END
  END w[135]
  PIN w[136]
    DIRECTION INPUT ;
    USE SIGNAL ;
    PORT
      LAYER M3 ;
        RECT  141.768 0 141.786 0.038 ;
    END
  END w[136]
  PIN w[137]
    DIRECTION INPUT ;
    USE SIGNAL ;
    PORT
      LAYER M5 ;
        RECT  141.984 0 142.008 0.084 ;
    END
  END w[137]
  PIN w[138]
    DIRECTION INPUT ;
    USE SIGNAL ;
    PORT
      LAYER M3 ;
        RECT  142.164 0 142.182 0.038 ;
    END
  END w[138]
  PIN w[139]
    DIRECTION INPUT ;
    USE SIGNAL ;
    PORT
      LAYER M5 ;
        RECT  142.32 0 142.344 0.084 ;
    END
  END w[139]
  PIN w[13]
    DIRECTION INPUT ;
    USE SIGNAL ;
    PORT
      LAYER M5 ;
        RECT  119.424 0 119.448 0.084 ;
    END
  END w[13]
  PIN w[140]
    DIRECTION INPUT ;
    USE SIGNAL ;
    PORT
      LAYER M3 ;
        RECT  142.524 0 142.542 0.038 ;
    END
  END w[140]
  PIN w[141]
    DIRECTION INPUT ;
    USE SIGNAL ;
    PORT
      LAYER M5 ;
        RECT  142.704 0 142.728 0.084 ;
    END
  END w[141]
  PIN w[142]
    DIRECTION INPUT ;
    USE SIGNAL ;
    PORT
      LAYER M3 ;
        RECT  142.884 0 142.902 0.038 ;
    END
  END w[142]
  PIN w[143]
    DIRECTION INPUT ;
    USE SIGNAL ;
    PORT
      LAYER M5 ;
        RECT  143.04 0 143.064 0.084 ;
    END
  END w[143]
  PIN w[144]
    DIRECTION INPUT ;
    USE SIGNAL ;
    PORT
      LAYER M3 ;
        RECT  143.244 0 143.262 0.038 ;
    END
  END w[144]
  PIN w[145]
    DIRECTION INPUT ;
    USE SIGNAL ;
    PORT
      LAYER M5 ;
        RECT  143.424 0 143.448 0.084 ;
    END
  END w[145]
  PIN w[146]
    DIRECTION INPUT ;
    USE SIGNAL ;
    PORT
      LAYER M3 ;
        RECT  143.604 0 143.622 0.038 ;
    END
  END w[146]
  PIN w[147]
    DIRECTION INPUT ;
    USE SIGNAL ;
    PORT
      LAYER M5 ;
        RECT  143.76 0 143.784 0.084 ;
    END
  END w[147]
  PIN w[148]
    DIRECTION INPUT ;
    USE SIGNAL ;
    PORT
      LAYER M3 ;
        RECT  143.964 0 143.982 0.038 ;
    END
  END w[148]
  PIN w[149]
    DIRECTION INPUT ;
    USE SIGNAL ;
    PORT
      LAYER M5 ;
        RECT  144.144 0 144.168 0.084 ;
    END
  END w[149]
  PIN w[14]
    DIRECTION INPUT ;
    USE SIGNAL ;
    PORT
      LAYER M3 ;
        RECT  119.628 0 119.646 0.038 ;
    END
  END w[14]
  PIN w[150]
    DIRECTION INPUT ;
    USE SIGNAL ;
    PORT
      LAYER M3 ;
        RECT  144.324 0 144.342 0.038 ;
    END
  END w[150]
  PIN w[151]
    DIRECTION INPUT ;
    USE SIGNAL ;
    PORT
      LAYER M5 ;
        RECT  144.528 0 144.552 0.084 ;
    END
  END w[151]
  PIN w[152]
    DIRECTION INPUT ;
    USE SIGNAL ;
    PORT
      LAYER M3 ;
        RECT  144.684 0 144.702 0.038 ;
    END
  END w[152]
  PIN w[153]
    DIRECTION INPUT ;
    USE SIGNAL ;
    PORT
      LAYER M5 ;
        RECT  144.864 0 144.888 0.084 ;
    END
  END w[153]
  PIN w[154]
    DIRECTION INPUT ;
    USE SIGNAL ;
    PORT
      LAYER M3 ;
        RECT  145.044 0 145.062 0.038 ;
    END
  END w[154]
  PIN w[155]
    DIRECTION INPUT ;
    USE SIGNAL ;
    PORT
      LAYER M5 ;
        RECT  145.248 0 145.272 0.084 ;
    END
  END w[155]
  PIN w[156]
    DIRECTION INPUT ;
    USE SIGNAL ;
    PORT
      LAYER M3 ;
        RECT  145.404 0 145.422 0.038 ;
    END
  END w[156]
  PIN w[157]
    DIRECTION INPUT ;
    USE SIGNAL ;
    PORT
      LAYER M5 ;
        RECT  145.584 0 145.608 0.084 ;
    END
  END w[157]
  PIN w[158]
    DIRECTION INPUT ;
    USE SIGNAL ;
    PORT
      LAYER M3 ;
        RECT  145.764 0 145.782 0.038 ;
    END
  END w[158]
  PIN w[159]
    DIRECTION INPUT ;
    USE SIGNAL ;
    PORT
      LAYER M5 ;
        RECT  145.968 0 145.992 0.084 ;
    END
  END w[159]
  PIN w[15]
    DIRECTION INPUT ;
    USE SIGNAL ;
    PORT
      LAYER M5 ;
        RECT  119.808 0 119.832 0.084 ;
    END
  END w[15]
  PIN w[160]
    DIRECTION INPUT ;
    USE SIGNAL ;
    PORT
      LAYER M3 ;
        RECT  146.16 0 146.178 0.038 ;
    END
  END w[160]
  PIN w[161]
    DIRECTION INPUT ;
    USE SIGNAL ;
    PORT
      LAYER M5 ;
        RECT  146.304 0 146.328 0.084 ;
    END
  END w[161]
  PIN w[162]
    DIRECTION INPUT ;
    USE SIGNAL ;
    PORT
      LAYER M3 ;
        RECT  146.52 0 146.538 0.038 ;
    END
  END w[162]
  PIN w[163]
    DIRECTION INPUT ;
    USE SIGNAL ;
    PORT
      LAYER M5 ;
        RECT  146.688 0 146.712 0.084 ;
    END
  END w[163]
  PIN w[164]
    DIRECTION INPUT ;
    USE SIGNAL ;
    PORT
      LAYER M3 ;
        RECT  146.88 0 146.898 0.038 ;
    END
  END w[164]
  PIN w[165]
    DIRECTION INPUT ;
    USE SIGNAL ;
    PORT
      LAYER M5 ;
        RECT  147.072 0 147.096 0.084 ;
    END
  END w[165]
  PIN w[166]
    DIRECTION INPUT ;
    USE SIGNAL ;
    PORT
      LAYER M3 ;
        RECT  147.24 0 147.258 0.038 ;
    END
  END w[166]
  PIN w[167]
    DIRECTION INPUT ;
    USE SIGNAL ;
    PORT
      LAYER M5 ;
        RECT  147.408 0 147.432 0.084 ;
    END
  END w[167]
  PIN w[168]
    DIRECTION INPUT ;
    USE SIGNAL ;
    PORT
      LAYER M3 ;
        RECT  147.6 0 147.618 0.038 ;
    END
  END w[168]
  PIN w[169]
    DIRECTION INPUT ;
    USE SIGNAL ;
    PORT
      LAYER M5 ;
        RECT  147.792 0 147.816 0.084 ;
    END
  END w[169]
  PIN w[16]
    DIRECTION INPUT ;
    USE SIGNAL ;
    PORT
      LAYER M3 ;
        RECT  119.988 0 120.006 0.038 ;
    END
  END w[16]
  PIN w[170]
    DIRECTION INPUT ;
    USE SIGNAL ;
    PORT
      LAYER M3 ;
        RECT  147.96 0 147.978 0.038 ;
    END
  END w[170]
  PIN w[171]
    DIRECTION INPUT ;
    USE SIGNAL ;
    PORT
      LAYER M5 ;
        RECT  148.128 0 148.152 0.084 ;
    END
  END w[171]
  PIN w[172]
    DIRECTION INPUT ;
    USE SIGNAL ;
    PORT
      LAYER M3 ;
        RECT  148.32 0 148.338 0.038 ;
    END
  END w[172]
  PIN w[173]
    DIRECTION INPUT ;
    USE SIGNAL ;
    PORT
      LAYER M5 ;
        RECT  148.512 0 148.536 0.084 ;
    END
  END w[173]
  PIN w[174]
    DIRECTION INPUT ;
    USE SIGNAL ;
    PORT
      LAYER M3 ;
        RECT  148.68 0 148.698 0.038 ;
    END
  END w[174]
  PIN w[175]
    DIRECTION INPUT ;
    USE SIGNAL ;
    PORT
      LAYER M5 ;
        RECT  148.848 0 148.872 0.084 ;
    END
  END w[175]
  PIN w[176]
    DIRECTION INPUT ;
    USE SIGNAL ;
    PORT
      LAYER M3 ;
        RECT  149.04 0 149.058 0.038 ;
    END
  END w[176]
  PIN w[177]
    DIRECTION INPUT ;
    USE SIGNAL ;
    PORT
      LAYER M5 ;
        RECT  149.232 0 149.256 0.084 ;
    END
  END w[177]
  PIN w[178]
    DIRECTION INPUT ;
    USE SIGNAL ;
    PORT
      LAYER M3 ;
        RECT  149.4 0 149.418 0.038 ;
    END
  END w[178]
  PIN w[179]
    DIRECTION INPUT ;
    USE SIGNAL ;
    PORT
      LAYER M5 ;
        RECT  149.616 0 149.64 0.084 ;
    END
  END w[179]
  PIN w[17]
    DIRECTION INPUT ;
    USE SIGNAL ;
    PORT
      LAYER M5 ;
        RECT  120.144 0 120.168 0.084 ;
    END
  END w[17]
  PIN w[180]
    DIRECTION INPUT ;
    USE SIGNAL ;
    PORT
      LAYER M3 ;
        RECT  149.76 0 149.778 0.038 ;
    END
  END w[180]
  PIN w[181]
    DIRECTION INPUT ;
    USE SIGNAL ;
    PORT
      LAYER M5 ;
        RECT  149.952 0 149.976 0.084 ;
    END
  END w[181]
  PIN w[182]
    DIRECTION INPUT ;
    USE SIGNAL ;
    PORT
      LAYER M3 ;
        RECT  150.156 0 150.174 0.038 ;
    END
  END w[182]
  PIN w[183]
    DIRECTION INPUT ;
    USE SIGNAL ;
    PORT
      LAYER M5 ;
        RECT  150.336 0 150.36 0.084 ;
    END
  END w[183]
  PIN w[184]
    DIRECTION INPUT ;
    USE SIGNAL ;
    PORT
      LAYER M3 ;
        RECT  150.516 0 150.534 0.038 ;
    END
  END w[184]
  PIN w[185]
    DIRECTION INPUT ;
    USE SIGNAL ;
    PORT
      LAYER M5 ;
        RECT  150.672 0 150.696 0.084 ;
    END
  END w[185]
  PIN w[186]
    DIRECTION INPUT ;
    USE SIGNAL ;
    PORT
      LAYER M3 ;
        RECT  150.876 0 150.894 0.038 ;
    END
  END w[186]
  PIN w[187]
    DIRECTION INPUT ;
    USE SIGNAL ;
    PORT
      LAYER M5 ;
        RECT  151.056 0 151.08 0.084 ;
    END
  END w[187]
  PIN w[188]
    DIRECTION INPUT ;
    USE SIGNAL ;
    PORT
      LAYER M3 ;
        RECT  151.236 0 151.254 0.038 ;
    END
  END w[188]
  PIN w[189]
    DIRECTION INPUT ;
    USE SIGNAL ;
    PORT
      LAYER M5 ;
        RECT  151.392 0 151.416 0.084 ;
    END
  END w[189]
  PIN w[18]
    DIRECTION INPUT ;
    USE SIGNAL ;
    PORT
      LAYER M3 ;
        RECT  120.348 0 120.366 0.038 ;
    END
  END w[18]
  PIN w[190]
    DIRECTION INPUT ;
    USE SIGNAL ;
    PORT
      LAYER M3 ;
        RECT  151.596 0 151.614 0.038 ;
    END
  END w[190]
  PIN w[191]
    DIRECTION INPUT ;
    USE SIGNAL ;
    PORT
      LAYER M5 ;
        RECT  151.776 0 151.8 0.084 ;
    END
  END w[191]
  PIN w[192]
    DIRECTION INPUT ;
    USE SIGNAL ;
    PORT
      LAYER M3 ;
        RECT  151.956 0 151.974 0.038 ;
    END
  END w[192]
  PIN w[193]
    DIRECTION INPUT ;
    USE SIGNAL ;
    PORT
      LAYER M5 ;
        RECT  152.112 0 152.136 0.084 ;
    END
  END w[193]
  PIN w[194]
    DIRECTION INPUT ;
    USE SIGNAL ;
    PORT
      LAYER M3 ;
        RECT  152.316 0 152.334 0.038 ;
    END
  END w[194]
  PIN w[195]
    DIRECTION INPUT ;
    USE SIGNAL ;
    PORT
      LAYER M5 ;
        RECT  152.496 0 152.52 0.084 ;
    END
  END w[195]
  PIN w[196]
    DIRECTION INPUT ;
    USE SIGNAL ;
    PORT
      LAYER M3 ;
        RECT  152.676 0 152.694 0.038 ;
    END
  END w[196]
  PIN w[197]
    DIRECTION INPUT ;
    USE SIGNAL ;
    PORT
      LAYER M5 ;
        RECT  152.88 0 152.904 0.084 ;
    END
  END w[197]
  PIN w[198]
    DIRECTION INPUT ;
    USE SIGNAL ;
    PORT
      LAYER M3 ;
        RECT  153.036 0 153.054 0.038 ;
    END
  END w[198]
  PIN w[199]
    DIRECTION INPUT ;
    USE SIGNAL ;
    PORT
      LAYER M5 ;
        RECT  153.216 0 153.24 0.084 ;
    END
  END w[199]
  PIN w[19]
    DIRECTION INPUT ;
    USE SIGNAL ;
    PORT
      LAYER M5 ;
        RECT  120.528 0 120.552 0.084 ;
    END
  END w[19]
  PIN w[1]
    DIRECTION INPUT ;
    USE SIGNAL ;
    PORT
      LAYER M5 ;
        RECT  117.264 0 117.288 0.084 ;
    END
  END w[1]
  PIN w[200]
    DIRECTION INPUT ;
    USE SIGNAL ;
    PORT
      LAYER M3 ;
        RECT  153.396 0 153.414 0.038 ;
    END
  END w[200]
  PIN w[201]
    DIRECTION INPUT ;
    USE SIGNAL ;
    PORT
      LAYER M5 ;
        RECT  153.6 0 153.624 0.084 ;
    END
  END w[201]
  PIN w[202]
    DIRECTION INPUT ;
    USE SIGNAL ;
    PORT
      LAYER M3 ;
        RECT  153.756 0 153.774 0.038 ;
    END
  END w[202]
  PIN w[203]
    DIRECTION INPUT ;
    USE SIGNAL ;
    PORT
      LAYER M5 ;
        RECT  153.936 0 153.96 0.084 ;
    END
  END w[203]
  PIN w[204]
    DIRECTION INPUT ;
    USE SIGNAL ;
    PORT
      LAYER M3 ;
        RECT  154.152 0 154.17 0.038 ;
    END
  END w[204]
  PIN w[205]
    DIRECTION INPUT ;
    USE SIGNAL ;
    PORT
      LAYER M5 ;
        RECT  154.32 0 154.344 0.084 ;
    END
  END w[205]
  PIN w[206]
    DIRECTION INPUT ;
    USE SIGNAL ;
    PORT
      LAYER M3 ;
        RECT  154.512 0 154.53 0.038 ;
    END
  END w[206]
  PIN w[207]
    DIRECTION INPUT ;
    USE SIGNAL ;
    PORT
      LAYER M5 ;
        RECT  154.656 0 154.68 0.084 ;
    END
  END w[207]
  PIN w[208]
    DIRECTION INPUT ;
    USE SIGNAL ;
    PORT
      LAYER M3 ;
        RECT  154.872 0 154.89 0.038 ;
    END
  END w[208]
  PIN w[209]
    DIRECTION INPUT ;
    USE SIGNAL ;
    PORT
      LAYER M5 ;
        RECT  155.04 0 155.064 0.084 ;
    END
  END w[209]
  PIN w[20]
    DIRECTION INPUT ;
    USE SIGNAL ;
    PORT
      LAYER M3 ;
        RECT  120.708 0 120.726 0.038 ;
    END
  END w[20]
  PIN w[210]
    DIRECTION INPUT ;
    USE SIGNAL ;
    PORT
      LAYER M3 ;
        RECT  155.232 0 155.25 0.038 ;
    END
  END w[210]
  PIN w[211]
    DIRECTION INPUT ;
    USE SIGNAL ;
    PORT
      LAYER M5 ;
        RECT  155.424 0 155.448 0.084 ;
    END
  END w[211]
  PIN w[212]
    DIRECTION INPUT ;
    USE SIGNAL ;
    PORT
      LAYER M3 ;
        RECT  155.592 0 155.61 0.038 ;
    END
  END w[212]
  PIN w[213]
    DIRECTION INPUT ;
    USE SIGNAL ;
    PORT
      LAYER M5 ;
        RECT  155.76 0 155.784 0.084 ;
    END
  END w[213]
  PIN w[214]
    DIRECTION INPUT ;
    USE SIGNAL ;
    PORT
      LAYER M3 ;
        RECT  155.952 0 155.97 0.038 ;
    END
  END w[214]
  PIN w[215]
    DIRECTION INPUT ;
    USE SIGNAL ;
    PORT
      LAYER M5 ;
        RECT  156.144 0 156.168 0.084 ;
    END
  END w[215]
  PIN w[216]
    DIRECTION INPUT ;
    USE SIGNAL ;
    PORT
      LAYER M3 ;
        RECT  156.312 0 156.33 0.038 ;
    END
  END w[216]
  PIN w[217]
    DIRECTION INPUT ;
    USE SIGNAL ;
    PORT
      LAYER M5 ;
        RECT  156.48 0 156.504 0.084 ;
    END
  END w[217]
  PIN w[218]
    DIRECTION INPUT ;
    USE SIGNAL ;
    PORT
      LAYER M3 ;
        RECT  156.672 0 156.69 0.038 ;
    END
  END w[218]
  PIN w[219]
    DIRECTION INPUT ;
    USE SIGNAL ;
    PORT
      LAYER M5 ;
        RECT  156.864 0 156.888 0.084 ;
    END
  END w[219]
  PIN w[21]
    DIRECTION INPUT ;
    USE SIGNAL ;
    PORT
      LAYER M5 ;
        RECT  120.912 0 120.936 0.084 ;
    END
  END w[21]
  PIN w[220]
    DIRECTION INPUT ;
    USE SIGNAL ;
    PORT
      LAYER M3 ;
        RECT  157.032 0 157.05 0.038 ;
    END
  END w[220]
  PIN w[221]
    DIRECTION INPUT ;
    USE SIGNAL ;
    PORT
      LAYER M5 ;
        RECT  157.2 0 157.224 0.084 ;
    END
  END w[221]
  PIN w[222]
    DIRECTION INPUT ;
    USE SIGNAL ;
    PORT
      LAYER M3 ;
        RECT  157.392 0 157.41 0.038 ;
    END
  END w[222]
  PIN w[223]
    DIRECTION INPUT ;
    USE SIGNAL ;
    PORT
      LAYER M5 ;
        RECT  157.584 0 157.608 0.084 ;
    END
  END w[223]
  PIN w[224]
    DIRECTION INPUT ;
    USE SIGNAL ;
    PORT
      LAYER M3 ;
        RECT  157.752 0 157.77 0.038 ;
    END
  END w[224]
  PIN w[225]
    DIRECTION INPUT ;
    USE SIGNAL ;
    PORT
      LAYER M5 ;
        RECT  157.968 0 157.992 0.084 ;
    END
  END w[225]
  PIN w[226]
    DIRECTION INPUT ;
    USE SIGNAL ;
    PORT
      LAYER M3 ;
        RECT  158.148 0 158.166 0.038 ;
    END
  END w[226]
  PIN w[227]
    DIRECTION INPUT ;
    USE SIGNAL ;
    PORT
      LAYER M5 ;
        RECT  158.304 0 158.328 0.084 ;
    END
  END w[227]
  PIN w[228]
    DIRECTION INPUT ;
    USE SIGNAL ;
    PORT
      LAYER M3 ;
        RECT  158.508 0 158.526 0.038 ;
    END
  END w[228]
  PIN w[229]
    DIRECTION INPUT ;
    USE SIGNAL ;
    PORT
      LAYER M5 ;
        RECT  158.688 0 158.712 0.084 ;
    END
  END w[229]
  PIN w[22]
    DIRECTION INPUT ;
    USE SIGNAL ;
    PORT
      LAYER M3 ;
        RECT  121.068 0 121.086 0.038 ;
    END
  END w[22]
  PIN w[230]
    DIRECTION INPUT ;
    USE SIGNAL ;
    PORT
      LAYER M3 ;
        RECT  158.868 0 158.886 0.038 ;
    END
  END w[230]
  PIN w[231]
    DIRECTION INPUT ;
    USE SIGNAL ;
    PORT
      LAYER M5 ;
        RECT  159.024 0 159.048 0.084 ;
    END
  END w[231]
  PIN w[232]
    DIRECTION INPUT ;
    USE SIGNAL ;
    PORT
      LAYER M3 ;
        RECT  159.228 0 159.246 0.038 ;
    END
  END w[232]
  PIN w[233]
    DIRECTION INPUT ;
    USE SIGNAL ;
    PORT
      LAYER M5 ;
        RECT  159.408 0 159.432 0.084 ;
    END
  END w[233]
  PIN w[234]
    DIRECTION INPUT ;
    USE SIGNAL ;
    PORT
      LAYER M3 ;
        RECT  159.588 0 159.606 0.038 ;
    END
  END w[234]
  PIN w[235]
    DIRECTION INPUT ;
    USE SIGNAL ;
    PORT
      LAYER M5 ;
        RECT  159.744 0 159.768 0.084 ;
    END
  END w[235]
  PIN w[236]
    DIRECTION INPUT ;
    USE SIGNAL ;
    PORT
      LAYER M3 ;
        RECT  159.948 0 159.966 0.038 ;
    END
  END w[236]
  PIN w[237]
    DIRECTION INPUT ;
    USE SIGNAL ;
    PORT
      LAYER M5 ;
        RECT  160.128 0 160.152 0.084 ;
    END
  END w[237]
  PIN w[238]
    DIRECTION INPUT ;
    USE SIGNAL ;
    PORT
      LAYER M3 ;
        RECT  160.308 0 160.326 0.038 ;
    END
  END w[238]
  PIN w[239]
    DIRECTION INPUT ;
    USE SIGNAL ;
    PORT
      LAYER M5 ;
        RECT  160.512 0 160.536 0.084 ;
    END
  END w[239]
  PIN w[23]
    DIRECTION INPUT ;
    USE SIGNAL ;
    PORT
      LAYER M5 ;
        RECT  121.248 0 121.272 0.084 ;
    END
  END w[23]
  PIN w[240]
    DIRECTION INPUT ;
    USE SIGNAL ;
    PORT
      LAYER M3 ;
        RECT  160.668 0 160.686 0.038 ;
    END
  END w[240]
  PIN w[241]
    DIRECTION INPUT ;
    USE SIGNAL ;
    PORT
      LAYER M5 ;
        RECT  160.848 0 160.872 0.084 ;
    END
  END w[241]
  PIN w[242]
    DIRECTION INPUT ;
    USE SIGNAL ;
    PORT
      LAYER M3 ;
        RECT  161.028 0 161.046 0.038 ;
    END
  END w[242]
  PIN w[243]
    DIRECTION INPUT ;
    USE SIGNAL ;
    PORT
      LAYER M5 ;
        RECT  161.232 0 161.256 0.084 ;
    END
  END w[243]
  PIN w[244]
    DIRECTION INPUT ;
    USE SIGNAL ;
    PORT
      LAYER M3 ;
        RECT  161.388 0 161.406 0.038 ;
    END
  END w[244]
  PIN w[245]
    DIRECTION INPUT ;
    USE SIGNAL ;
    PORT
      LAYER M5 ;
        RECT  161.568 0 161.592 0.084 ;
    END
  END w[245]
  PIN w[246]
    DIRECTION INPUT ;
    USE SIGNAL ;
    PORT
      LAYER M3 ;
        RECT  161.748 0 161.766 0.038 ;
    END
  END w[246]
  PIN w[247]
    DIRECTION INPUT ;
    USE SIGNAL ;
    PORT
      LAYER M5 ;
        RECT  161.952 0 161.976 0.084 ;
    END
  END w[247]
  PIN w[248]
    DIRECTION INPUT ;
    USE SIGNAL ;
    PORT
      LAYER M3 ;
        RECT  162.144 0 162.162 0.038 ;
    END
  END w[248]
  PIN w[249]
    DIRECTION INPUT ;
    USE SIGNAL ;
    PORT
      LAYER M5 ;
        RECT  162.288 0 162.312 0.084 ;
    END
  END w[249]
  PIN w[24]
    DIRECTION INPUT ;
    USE SIGNAL ;
    PORT
      LAYER M3 ;
        RECT  121.428 0 121.446 0.038 ;
    END
  END w[24]
  PIN w[250]
    DIRECTION INPUT ;
    USE SIGNAL ;
    PORT
      LAYER M3 ;
        RECT  162.504 0 162.522 0.038 ;
    END
  END w[250]
  PIN w[251]
    DIRECTION INPUT ;
    USE SIGNAL ;
    PORT
      LAYER M5 ;
        RECT  162.672 0 162.696 0.084 ;
    END
  END w[251]
  PIN w[252]
    DIRECTION INPUT ;
    USE SIGNAL ;
    PORT
      LAYER M3 ;
        RECT  162.864 0 162.882 0.038 ;
    END
  END w[252]
  PIN w[253]
    DIRECTION INPUT ;
    USE SIGNAL ;
    PORT
      LAYER M5 ;
        RECT  163.056 0 163.08 0.084 ;
    END
  END w[253]
  PIN w[254]
    DIRECTION INPUT ;
    USE SIGNAL ;
    PORT
      LAYER M3 ;
        RECT  163.224 0 163.242 0.038 ;
    END
  END w[254]
  PIN w[255]
    DIRECTION INPUT ;
    USE SIGNAL ;
    PORT
      LAYER M5 ;
        RECT  163.392 0 163.416 0.084 ;
    END
  END w[255]
  PIN w[25]
    DIRECTION INPUT ;
    USE SIGNAL ;
    PORT
      LAYER M5 ;
        RECT  121.632 0 121.656 0.084 ;
    END
  END w[25]
  PIN w[26]
    DIRECTION INPUT ;
    USE SIGNAL ;
    PORT
      LAYER M3 ;
        RECT  121.788 0 121.806 0.038 ;
    END
  END w[26]
  PIN w[27]
    DIRECTION INPUT ;
    USE SIGNAL ;
    PORT
      LAYER M5 ;
        RECT  121.968 0 121.992 0.084 ;
    END
  END w[27]
  PIN w[28]
    DIRECTION INPUT ;
    USE SIGNAL ;
    PORT
      LAYER M3 ;
        RECT  122.184 0 122.202 0.038 ;
    END
  END w[28]
  PIN w[29]
    DIRECTION INPUT ;
    USE SIGNAL ;
    PORT
      LAYER M5 ;
        RECT  122.352 0 122.376 0.084 ;
    END
  END w[29]
  PIN w[2]
    DIRECTION INPUT ;
    USE SIGNAL ;
    PORT
      LAYER M3 ;
        RECT  117.432 0 117.45 0.038 ;
    END
  END w[2]
  PIN w[30]
    DIRECTION INPUT ;
    USE SIGNAL ;
    PORT
      LAYER M3 ;
        RECT  122.544 0 122.562 0.038 ;
    END
  END w[30]
  PIN w[31]
    DIRECTION INPUT ;
    USE SIGNAL ;
    PORT
      LAYER M5 ;
        RECT  122.688 0 122.712 0.084 ;
    END
  END w[31]
  PIN w[32]
    DIRECTION INPUT ;
    USE SIGNAL ;
    PORT
      LAYER M3 ;
        RECT  122.904 0 122.922 0.038 ;
    END
  END w[32]
  PIN w[33]
    DIRECTION INPUT ;
    USE SIGNAL ;
    PORT
      LAYER M5 ;
        RECT  123.072 0 123.096 0.084 ;
    END
  END w[33]
  PIN w[34]
    DIRECTION INPUT ;
    USE SIGNAL ;
    PORT
      LAYER M3 ;
        RECT  123.264 0 123.282 0.038 ;
    END
  END w[34]
  PIN w[35]
    DIRECTION INPUT ;
    USE SIGNAL ;
    PORT
      LAYER M5 ;
        RECT  123.456 0 123.48 0.084 ;
    END
  END w[35]
  PIN w[36]
    DIRECTION INPUT ;
    USE SIGNAL ;
    PORT
      LAYER M3 ;
        RECT  123.624 0 123.642 0.038 ;
    END
  END w[36]
  PIN w[37]
    DIRECTION INPUT ;
    USE SIGNAL ;
    PORT
      LAYER M5 ;
        RECT  123.792 0 123.816 0.084 ;
    END
  END w[37]
  PIN w[38]
    DIRECTION INPUT ;
    USE SIGNAL ;
    PORT
      LAYER M3 ;
        RECT  123.984 0 124.002 0.038 ;
    END
  END w[38]
  PIN w[39]
    DIRECTION INPUT ;
    USE SIGNAL ;
    PORT
      LAYER M5 ;
        RECT  124.176 0 124.2 0.084 ;
    END
  END w[39]
  PIN w[3]
    DIRECTION INPUT ;
    USE SIGNAL ;
    PORT
      LAYER M5 ;
        RECT  117.648 0 117.672 0.084 ;
    END
  END w[3]
  PIN w[40]
    DIRECTION INPUT ;
    USE SIGNAL ;
    PORT
      LAYER M3 ;
        RECT  124.344 0 124.362 0.038 ;
    END
  END w[40]
  PIN w[41]
    DIRECTION INPUT ;
    USE SIGNAL ;
    PORT
      LAYER M5 ;
        RECT  124.512 0 124.536 0.084 ;
    END
  END w[41]
  PIN w[42]
    DIRECTION INPUT ;
    USE SIGNAL ;
    PORT
      LAYER M3 ;
        RECT  124.704 0 124.722 0.038 ;
    END
  END w[42]
  PIN w[43]
    DIRECTION INPUT ;
    USE SIGNAL ;
    PORT
      LAYER M5 ;
        RECT  124.896 0 124.92 0.084 ;
    END
  END w[43]
  PIN w[44]
    DIRECTION INPUT ;
    USE SIGNAL ;
    PORT
      LAYER M3 ;
        RECT  125.064 0 125.082 0.038 ;
    END
  END w[44]
  PIN w[45]
    DIRECTION INPUT ;
    USE SIGNAL ;
    PORT
      LAYER M5 ;
        RECT  125.232 0 125.256 0.084 ;
    END
  END w[45]
  PIN w[46]
    DIRECTION INPUT ;
    USE SIGNAL ;
    PORT
      LAYER M3 ;
        RECT  125.424 0 125.442 0.038 ;
    END
  END w[46]
  PIN w[47]
    DIRECTION INPUT ;
    USE SIGNAL ;
    PORT
      LAYER M5 ;
        RECT  125.616 0 125.64 0.084 ;
    END
  END w[47]
  PIN w[48]
    DIRECTION INPUT ;
    USE SIGNAL ;
    PORT
      LAYER M3 ;
        RECT  125.784 0 125.802 0.038 ;
    END
  END w[48]
  PIN w[49]
    DIRECTION INPUT ;
    USE SIGNAL ;
    PORT
      LAYER M5 ;
        RECT  126 0 126.024 0.084 ;
    END
  END w[49]
  PIN w[4]
    DIRECTION INPUT ;
    USE SIGNAL ;
    PORT
      LAYER M3 ;
        RECT  117.792 0 117.81 0.038 ;
    END
  END w[4]
  PIN w[50]
    DIRECTION INPUT ;
    USE SIGNAL ;
    PORT
      LAYER M3 ;
        RECT  126.18 0 126.198 0.038 ;
    END
  END w[50]
  PIN w[51]
    DIRECTION INPUT ;
    USE SIGNAL ;
    PORT
      LAYER M5 ;
        RECT  126.336 0 126.36 0.084 ;
    END
  END w[51]
  PIN w[52]
    DIRECTION INPUT ;
    USE SIGNAL ;
    PORT
      LAYER M3 ;
        RECT  126.54 0 126.558 0.038 ;
    END
  END w[52]
  PIN w[53]
    DIRECTION INPUT ;
    USE SIGNAL ;
    PORT
      LAYER M5 ;
        RECT  126.72 0 126.744 0.084 ;
    END
  END w[53]
  PIN w[54]
    DIRECTION INPUT ;
    USE SIGNAL ;
    PORT
      LAYER M3 ;
        RECT  126.9 0 126.918 0.038 ;
    END
  END w[54]
  PIN w[55]
    DIRECTION INPUT ;
    USE SIGNAL ;
    PORT
      LAYER M5 ;
        RECT  127.056 0 127.08 0.084 ;
    END
  END w[55]
  PIN w[56]
    DIRECTION INPUT ;
    USE SIGNAL ;
    PORT
      LAYER M3 ;
        RECT  127.26 0 127.278 0.038 ;
    END
  END w[56]
  PIN w[57]
    DIRECTION INPUT ;
    USE SIGNAL ;
    PORT
      LAYER M5 ;
        RECT  127.44 0 127.464 0.084 ;
    END
  END w[57]
  PIN w[58]
    DIRECTION INPUT ;
    USE SIGNAL ;
    PORT
      LAYER M3 ;
        RECT  127.62 0 127.638 0.038 ;
    END
  END w[58]
  PIN w[59]
    DIRECTION INPUT ;
    USE SIGNAL ;
    PORT
      LAYER M5 ;
        RECT  127.776 0 127.8 0.084 ;
    END
  END w[59]
  PIN w[5]
    DIRECTION INPUT ;
    USE SIGNAL ;
    PORT
      LAYER M5 ;
        RECT  117.984 0 118.008 0.084 ;
    END
  END w[5]
  PIN w[60]
    DIRECTION INPUT ;
    USE SIGNAL ;
    PORT
      LAYER M3 ;
        RECT  127.98 0 127.998 0.038 ;
    END
  END w[60]
  PIN w[61]
    DIRECTION INPUT ;
    USE SIGNAL ;
    PORT
      LAYER M5 ;
        RECT  128.16 0 128.184 0.084 ;
    END
  END w[61]
  PIN w[62]
    DIRECTION INPUT ;
    USE SIGNAL ;
    PORT
      LAYER M3 ;
        RECT  128.34 0 128.358 0.038 ;
    END
  END w[62]
  PIN w[63]
    DIRECTION INPUT ;
    USE SIGNAL ;
    PORT
      LAYER M5 ;
        RECT  128.544 0 128.568 0.084 ;
    END
  END w[63]
  PIN w[64]
    DIRECTION INPUT ;
    USE SIGNAL ;
    PORT
      LAYER M3 ;
        RECT  128.7 0 128.718 0.038 ;
    END
  END w[64]
  PIN w[65]
    DIRECTION INPUT ;
    USE SIGNAL ;
    PORT
      LAYER M5 ;
        RECT  128.88 0 128.904 0.084 ;
    END
  END w[65]
  PIN w[66]
    DIRECTION INPUT ;
    USE SIGNAL ;
    PORT
      LAYER M3 ;
        RECT  129.06 0 129.078 0.038 ;
    END
  END w[66]
  PIN w[67]
    DIRECTION INPUT ;
    USE SIGNAL ;
    PORT
      LAYER M5 ;
        RECT  129.264 0 129.288 0.084 ;
    END
  END w[67]
  PIN w[68]
    DIRECTION INPUT ;
    USE SIGNAL ;
    PORT
      LAYER M3 ;
        RECT  129.42 0 129.438 0.038 ;
    END
  END w[68]
  PIN w[69]
    DIRECTION INPUT ;
    USE SIGNAL ;
    PORT
      LAYER M5 ;
        RECT  129.6 0 129.624 0.084 ;
    END
  END w[69]
  PIN w[6]
    DIRECTION INPUT ;
    USE SIGNAL ;
    PORT
      LAYER M3 ;
        RECT  118.188 0 118.206 0.038 ;
    END
  END w[6]
  PIN w[70]
    DIRECTION INPUT ;
    USE SIGNAL ;
    PORT
      LAYER M3 ;
        RECT  129.78 0 129.798 0.038 ;
    END
  END w[70]
  PIN w[71]
    DIRECTION INPUT ;
    USE SIGNAL ;
    PORT
      LAYER M5 ;
        RECT  129.984 0 130.008 0.084 ;
    END
  END w[71]
  PIN w[72]
    DIRECTION INPUT ;
    USE SIGNAL ;
    PORT
      LAYER M3 ;
        RECT  130.176 0 130.194 0.038 ;
    END
  END w[72]
  PIN w[73]
    DIRECTION INPUT ;
    USE SIGNAL ;
    PORT
      LAYER M5 ;
        RECT  130.32 0 130.344 0.084 ;
    END
  END w[73]
  PIN w[74]
    DIRECTION INPUT ;
    USE SIGNAL ;
    PORT
      LAYER M3 ;
        RECT  130.536 0 130.554 0.038 ;
    END
  END w[74]
  PIN w[75]
    DIRECTION INPUT ;
    USE SIGNAL ;
    PORT
      LAYER M5 ;
        RECT  130.704 0 130.728 0.084 ;
    END
  END w[75]
  PIN w[76]
    DIRECTION INPUT ;
    USE SIGNAL ;
    PORT
      LAYER M3 ;
        RECT  130.896 0 130.914 0.038 ;
    END
  END w[76]
  PIN w[77]
    DIRECTION INPUT ;
    USE SIGNAL ;
    PORT
      LAYER M5 ;
        RECT  131.088 0 131.112 0.084 ;
    END
  END w[77]
  PIN w[78]
    DIRECTION INPUT ;
    USE SIGNAL ;
    PORT
      LAYER M3 ;
        RECT  131.256 0 131.274 0.038 ;
    END
  END w[78]
  PIN w[79]
    DIRECTION INPUT ;
    USE SIGNAL ;
    PORT
      LAYER M5 ;
        RECT  131.424 0 131.448 0.084 ;
    END
  END w[79]
  PIN w[7]
    DIRECTION INPUT ;
    USE SIGNAL ;
    PORT
      LAYER M5 ;
        RECT  118.368 0 118.392 0.084 ;
    END
  END w[7]
  PIN w[80]
    DIRECTION INPUT ;
    USE SIGNAL ;
    PORT
      LAYER M3 ;
        RECT  131.616 0 131.634 0.038 ;
    END
  END w[80]
  PIN w[81]
    DIRECTION INPUT ;
    USE SIGNAL ;
    PORT
      LAYER M5 ;
        RECT  131.808 0 131.832 0.084 ;
    END
  END w[81]
  PIN w[82]
    DIRECTION INPUT ;
    USE SIGNAL ;
    PORT
      LAYER M3 ;
        RECT  131.976 0 131.994 0.038 ;
    END
  END w[82]
  PIN w[83]
    DIRECTION INPUT ;
    USE SIGNAL ;
    PORT
      LAYER M5 ;
        RECT  132.144 0 132.168 0.084 ;
    END
  END w[83]
  PIN w[84]
    DIRECTION INPUT ;
    USE SIGNAL ;
    PORT
      LAYER M3 ;
        RECT  132.336 0 132.354 0.038 ;
    END
  END w[84]
  PIN w[85]
    DIRECTION INPUT ;
    USE SIGNAL ;
    PORT
      LAYER M5 ;
        RECT  132.528 0 132.552 0.084 ;
    END
  END w[85]
  PIN w[86]
    DIRECTION INPUT ;
    USE SIGNAL ;
    PORT
      LAYER M3 ;
        RECT  132.696 0 132.714 0.038 ;
    END
  END w[86]
  PIN w[87]
    DIRECTION INPUT ;
    USE SIGNAL ;
    PORT
      LAYER M5 ;
        RECT  132.864 0 132.888 0.084 ;
    END
  END w[87]
  PIN w[88]
    DIRECTION INPUT ;
    USE SIGNAL ;
    PORT
      LAYER M3 ;
        RECT  133.056 0 133.074 0.038 ;
    END
  END w[88]
  PIN w[89]
    DIRECTION INPUT ;
    USE SIGNAL ;
    PORT
      LAYER M5 ;
        RECT  133.248 0 133.272 0.084 ;
    END
  END w[89]
  PIN w[8]
    DIRECTION INPUT ;
    USE SIGNAL ;
    PORT
      LAYER M3 ;
        RECT  118.548 0 118.566 0.038 ;
    END
  END w[8]
  PIN w[90]
    DIRECTION INPUT ;
    USE SIGNAL ;
    PORT
      LAYER M3 ;
        RECT  133.416 0 133.434 0.038 ;
    END
  END w[90]
  PIN w[91]
    DIRECTION INPUT ;
    USE SIGNAL ;
    PORT
      LAYER M5 ;
        RECT  133.632 0 133.656 0.084 ;
    END
  END w[91]
  PIN w[92]
    DIRECTION INPUT ;
    USE SIGNAL ;
    PORT
      LAYER M3 ;
        RECT  133.776 0 133.794 0.038 ;
    END
  END w[92]
  PIN w[93]
    DIRECTION INPUT ;
    USE SIGNAL ;
    PORT
      LAYER M5 ;
        RECT  133.968 0 133.992 0.084 ;
    END
  END w[93]
  PIN w[94]
    DIRECTION INPUT ;
    USE SIGNAL ;
    PORT
      LAYER M3 ;
        RECT  134.172 0 134.19 0.038 ;
    END
  END w[94]
  PIN w[95]
    DIRECTION INPUT ;
    USE SIGNAL ;
    PORT
      LAYER M5 ;
        RECT  134.352 0 134.376 0.084 ;
    END
  END w[95]
  PIN w[96]
    DIRECTION INPUT ;
    USE SIGNAL ;
    PORT
      LAYER M3 ;
        RECT  134.532 0 134.55 0.038 ;
    END
  END w[96]
  PIN w[97]
    DIRECTION INPUT ;
    USE SIGNAL ;
    PORT
      LAYER M5 ;
        RECT  134.688 0 134.712 0.084 ;
    END
  END w[97]
  PIN w[98]
    DIRECTION INPUT ;
    USE SIGNAL ;
    PORT
      LAYER M3 ;
        RECT  134.892 0 134.91 0.038 ;
    END
  END w[98]
  PIN w[99]
    DIRECTION INPUT ;
    USE SIGNAL ;
    PORT
      LAYER M5 ;
        RECT  135.072 0 135.096 0.084 ;
    END
  END w[99]
  PIN w[9]
    DIRECTION INPUT ;
    USE SIGNAL ;
    PORT
      LAYER M5 ;
        RECT  118.704 0 118.728 0.084 ;
    END
  END w[9]
  PIN VDD
    DIRECTION INOUT ;
    USE POWER ;
    PORT
      LAYER M5 ;
        RECT  159.192 2.151 159.312 41.049 ;
        RECT  153.792 2.151 153.912 41.049 ;
        RECT  148.392 2.151 148.512 41.049 ;
        RECT  142.992 2.151 143.112 41.049 ;
        RECT  137.592 2.151 137.712 41.049 ;
        RECT  132.192 2.151 132.312 41.049 ;
        RECT  126.792 2.151 126.912 41.049 ;
        RECT  121.392 2.151 121.512 41.049 ;
        RECT  115.992 2.151 116.112 41.049 ;
        RECT  110.592 2.151 110.712 41.049 ;
        RECT  105.192 2.151 105.312 41.049 ;
        RECT  99.792 2.151 99.912 41.049 ;
        RECT  94.392 2.151 94.512 41.049 ;
        RECT  88.992 2.151 89.112 41.049 ;
        RECT  83.592 2.151 83.712 41.049 ;
        RECT  78.192 2.151 78.312 41.049 ;
        RECT  72.792 2.151 72.912 41.049 ;
        RECT  67.392 2.151 67.512 41.049 ;
        RECT  61.992 2.151 62.112 41.049 ;
        RECT  56.592 2.151 56.712 41.049 ;
        RECT  51.192 2.151 51.312 41.049 ;
        RECT  45.792 2.151 45.912 41.049 ;
        RECT  40.392 2.151 40.512 41.049 ;
        RECT  34.992 2.151 35.112 41.049 ;
        RECT  29.592 2.151 29.712 41.049 ;
        RECT  24.192 2.151 24.312 41.049 ;
        RECT  18.792 2.151 18.912 41.049 ;
        RECT  13.392 2.151 13.512 41.049 ;
        RECT  7.992 2.151 8.112 41.049 ;
        RECT  2.592 2.151 2.712 41.049 ;
    END
  END VDD
  PIN VSS
    DIRECTION INOUT ;
    USE GROUND ;
    PORT
      LAYER M5 ;
        RECT  159 2.137 159.12 41.063 ;
        RECT  153.6 2.137 153.72 41.063 ;
        RECT  148.2 2.137 148.32 41.063 ;
        RECT  142.8 2.137 142.92 41.063 ;
        RECT  137.4 2.137 137.52 41.063 ;
        RECT  132 2.137 132.12 41.063 ;
        RECT  126.6 2.137 126.72 41.063 ;
        RECT  121.2 2.137 121.32 41.063 ;
        RECT  115.8 2.137 115.92 41.063 ;
        RECT  110.4 2.137 110.52 41.063 ;
        RECT  105 2.137 105.12 41.063 ;
        RECT  99.6 2.137 99.72 41.063 ;
        RECT  94.2 2.137 94.32 41.063 ;
        RECT  88.8 2.137 88.92 41.063 ;
        RECT  83.4 2.137 83.52 41.063 ;
        RECT  78 2.137 78.12 41.063 ;
        RECT  72.6 2.137 72.72 41.063 ;
        RECT  67.2 2.137 67.32 41.063 ;
        RECT  61.8 2.137 61.92 41.063 ;
        RECT  56.4 2.137 56.52 41.063 ;
        RECT  51 2.137 51.12 41.063 ;
        RECT  45.6 2.137 45.72 41.063 ;
        RECT  40.2 2.137 40.32 41.063 ;
        RECT  34.8 2.137 34.92 41.063 ;
        RECT  29.4 2.137 29.52 41.063 ;
        RECT  24 2.137 24.12 41.063 ;
        RECT  18.6 2.137 18.72 41.063 ;
        RECT  13.2 2.137 13.32 41.063 ;
        RECT  7.8 2.137 7.92 41.063 ;
        RECT  2.4 2.137 2.52 41.063 ;
    END
  END VSS
  OBS
    LAYER RVTN ;
     RECT  2.16 2.16 162 2.295 ;
     RECT  2.16 2.565 162 2.835 ;
     RECT  2.16 3.105 162 3.375 ;
     RECT  2.16 3.645 162 3.915 ;
     RECT  2.16 4.185 162 4.455 ;
     RECT  2.16 4.725 162 4.995 ;
     RECT  2.16 5.265 162 5.535 ;
     RECT  2.16 5.805 162 6.075 ;
     RECT  2.16 6.345 162 6.615 ;
     RECT  2.16 6.885 162 7.155 ;
     RECT  2.16 7.425 162 7.695 ;
     RECT  2.16 7.965 162 8.235 ;
     RECT  2.16 8.505 162 8.775 ;
     RECT  2.16 9.045 162 9.315 ;
     RECT  2.16 9.585 162 9.855 ;
     RECT  2.16 10.125 162 10.395 ;
     RECT  2.16 10.665 162 10.935 ;
     RECT  2.16 11.205 162 11.475 ;
     RECT  2.16 11.745 162 12.015 ;
     RECT  2.16 12.285 162 12.555 ;
     RECT  2.16 12.825 162 13.095 ;
     RECT  2.16 13.365 162 13.635 ;
     RECT  2.16 13.905 162 14.175 ;
     RECT  2.16 14.445 162 14.715 ;
     RECT  2.16 14.985 162 15.255 ;
     RECT  2.16 15.525 162 15.795 ;
     RECT  2.16 16.065 162 16.335 ;
     RECT  2.16 16.605 162 16.875 ;
     RECT  2.16 17.145 162 17.415 ;
     RECT  2.16 17.685 162 17.955 ;
     RECT  2.16 18.225 162 18.495 ;
     RECT  2.16 18.765 162 19.035 ;
     RECT  2.16 19.305 162 19.575 ;
     RECT  2.16 19.845 162 20.115 ;
     RECT  2.16 20.385 162 20.655 ;
     RECT  2.16 20.925 162 21.195 ;
     RECT  2.16 21.465 162 21.735 ;
     RECT  2.16 22.005 162 22.275 ;
     RECT  2.16 22.545 162 22.815 ;
     RECT  2.16 23.085 162 23.355 ;
     RECT  2.16 23.625 162 23.895 ;
     RECT  2.16 24.165 162 24.435 ;
     RECT  2.16 24.705 162 24.975 ;
     RECT  2.16 25.245 162 25.515 ;
     RECT  2.16 25.785 162 26.055 ;
     RECT  2.16 26.325 162 26.595 ;
     RECT  2.16 26.865 162 27.135 ;
     RECT  2.16 27.405 162 27.675 ;
     RECT  2.16 27.945 162 28.215 ;
     RECT  2.16 28.485 162 28.755 ;
     RECT  2.16 29.025 162 29.295 ;
     RECT  2.16 29.565 162 29.835 ;
     RECT  2.16 30.105 162 30.375 ;
     RECT  2.16 30.645 162 30.915 ;
     RECT  2.16 31.185 162 31.455 ;
     RECT  2.16 31.725 162 31.995 ;
     RECT  2.16 32.265 162 32.535 ;
     RECT  2.16 32.805 162 33.075 ;
     RECT  2.16 33.345 162 33.615 ;
     RECT  2.16 33.885 162 34.155 ;
     RECT  2.16 34.425 162 34.695 ;
     RECT  2.16 34.965 162 35.235 ;
     RECT  2.16 35.505 162 35.775 ;
     RECT  2.16 36.045 162 36.315 ;
     RECT  2.16 36.585 162 36.855 ;
     RECT  2.16 37.125 162 37.395 ;
     RECT  2.16 37.665 162 37.935 ;
     RECT  2.16 38.205 162 38.475 ;
     RECT  2.16 38.745 162 39.015 ;
     RECT  2.16 39.285 162 39.555 ;
     RECT  2.16 39.825 162 40.095 ;
     RECT  2.16 40.365 162 40.635 ;
     RECT  2.16 40.905 162 41.04 ;
    LAYER RVTP ;
     RECT  2.16 2.295 162 2.565 ;
     RECT  2.16 2.835 162 3.105 ;
     RECT  2.16 3.375 162 3.645 ;
     RECT  2.16 3.915 162 4.185 ;
     RECT  2.16 4.455 162 4.725 ;
     RECT  2.16 4.995 162 5.265 ;
     RECT  2.16 5.535 162 5.805 ;
     RECT  2.16 6.075 162 6.345 ;
     RECT  2.16 6.615 162 6.885 ;
     RECT  2.16 7.155 162 7.425 ;
     RECT  2.16 7.695 162 7.965 ;
     RECT  2.16 8.235 162 8.505 ;
     RECT  2.16 8.775 162 9.045 ;
     RECT  2.16 9.315 162 9.585 ;
     RECT  2.16 9.855 162 10.125 ;
     RECT  2.16 10.395 162 10.665 ;
     RECT  2.16 10.935 162 11.205 ;
     RECT  2.16 11.475 162 11.745 ;
     RECT  2.16 12.015 162 12.285 ;
     RECT  2.16 12.555 162 12.825 ;
     RECT  2.16 13.095 162 13.365 ;
     RECT  2.16 13.635 162 13.905 ;
     RECT  2.16 14.175 162 14.445 ;
     RECT  2.16 14.715 162 14.985 ;
     RECT  2.16 15.255 162 15.525 ;
     RECT  2.16 15.795 162 16.065 ;
     RECT  2.16 16.335 162 16.605 ;
     RECT  2.16 16.875 162 17.145 ;
     RECT  2.16 17.415 162 17.685 ;
     RECT  2.16 17.955 162 18.225 ;
     RECT  2.16 18.495 162 18.765 ;
     RECT  2.16 19.035 162 19.305 ;
     RECT  2.16 19.575 162 19.845 ;
     RECT  2.16 20.115 162 20.385 ;
     RECT  2.16 20.655 162 20.925 ;
     RECT  2.16 21.195 162 21.465 ;
     RECT  2.16 21.735 162 22.005 ;
     RECT  2.16 22.275 162 22.545 ;
     RECT  2.16 22.815 162 23.085 ;
     RECT  2.16 23.355 162 23.625 ;
     RECT  2.16 23.895 162 24.165 ;
     RECT  2.16 24.435 162 24.705 ;
     RECT  2.16 24.975 162 25.245 ;
     RECT  2.16 25.515 162 25.785 ;
     RECT  2.16 26.055 162 26.325 ;
     RECT  2.16 26.595 162 26.865 ;
     RECT  2.16 27.135 162 27.405 ;
     RECT  2.16 27.675 162 27.945 ;
     RECT  2.16 28.215 162 28.485 ;
     RECT  2.16 28.755 162 29.025 ;
     RECT  2.16 29.295 162 29.565 ;
     RECT  2.16 29.835 162 30.105 ;
     RECT  2.16 30.375 162 30.645 ;
     RECT  2.16 30.915 162 31.185 ;
     RECT  2.16 31.455 162 31.725 ;
     RECT  2.16 31.995 162 32.265 ;
     RECT  2.16 32.535 162 32.805 ;
     RECT  2.16 33.075 162 33.345 ;
     RECT  2.16 33.615 162 33.885 ;
     RECT  2.16 34.155 162 34.425 ;
     RECT  2.16 34.695 162 34.965 ;
     RECT  2.16 35.235 162 35.505 ;
     RECT  2.16 35.775 162 36.045 ;
     RECT  2.16 36.315 162 36.585 ;
     RECT  2.16 36.855 162 37.125 ;
     RECT  2.16 37.395 162 37.665 ;
     RECT  2.16 37.935 162 38.205 ;
     RECT  2.16 38.475 162 38.745 ;
     RECT  2.16 39.015 162 39.285 ;
     RECT  2.16 39.555 162 39.825 ;
     RECT  2.16 40.095 162 40.365 ;
     RECT  2.16 40.635 162 40.905 ;
    LAYER M1 ;
     RECT  2.16 2.151 162 41.049 ;
    LAYER M2 ;
     RECT  0.571 3.582 0.931 3.6 ;
     RECT  0.931 3.582 1.723 3.978 ;
     RECT  0.787 40.536 1.975 40.554 ;
     RECT  1.291 5.742 2.011 5.76 ;
     RECT  1.723 3.582 2.16 4.41 ;
     RECT  2.011 5.742 2.16 5.868 ;
     RECT  1.975 40.536 2.16 41.004 ;
     RECT  2.16 2.151 2.695 41.049 ;
     RECT  2.695 1.728 3.299 41.049 ;
     RECT  4.387 0.036 5.243 0.054 ;
     RECT  5.611 43.146 5.711 43.164 ;
     RECT  3.299 2.151 8.527 41.049 ;
     RECT  8.527 2.106 8.951 41.049 ;
     RECT  10.075 0.036 10.175 0.054 ;
     RECT  8.599 43.146 10.175 43.164 ;
     RECT  11.479 0.036 11.867 0.054 ;
     RECT  12.055 43.146 12.407 43.164 ;
     RECT  8.951 2.151 12.955 41.049 ;
     RECT  12.955 2.151 13.091 41.094 ;
     RECT  13.243 0.036 13.667 0.054 ;
     RECT  14.035 43.146 14.243 43.164 ;
     RECT  15.547 43.146 15.683 43.164 ;
     RECT  16.051 0.036 16.223 0.054 ;
     RECT  17.095 0.036 17.195 0.054 ;
     RECT  13.091 2.151 17.347 41.049 ;
     RECT  17.347 2.151 17.555 41.094 ;
     RECT  17.555 2.151 17.851 41.049 ;
     RECT  17.851 1.728 18.167 41.049 ;
     RECT  19.003 43.146 19.103 43.164 ;
     RECT  22.999 43.146 23.855 43.164 ;
     RECT  24.295 0.036 24.395 0.054 ;
     RECT  24.979 43.146 25.079 43.164 ;
     RECT  18.167 2.151 25.195 41.049 ;
     RECT  25.195 1.728 25.439 41.049 ;
     RECT  25.843 0.036 26.159 0.054 ;
     RECT  29.335 0.036 29.435 0.054 ;
     RECT  30.955 43.146 31.055 43.164 ;
     RECT  34.915 43.146 35.015 43.164 ;
     RECT  34.843 0.036 35.267 0.054 ;
     RECT  37.399 43.146 37.535 43.164 ;
     RECT  37.975 1.152 38.147 1.17 ;
     RECT  38.839 0.036 39.011 0.054 ;
     RECT  39.199 1.152 39.299 1.17 ;
     RECT  39.919 0.036 41.027 0.054 ;
     RECT  41.071 43.146 41.423 43.164 ;
     RECT  43.879 43.146 44.267 43.164 ;
     RECT  46.363 43.146 46.571 43.164 ;
     RECT  47.551 0.036 47.651 0.054 ;
     RECT  47.767 43.146 47.867 43.164 ;
     RECT  48.847 43.146 48.947 43.164 ;
     RECT  48.919 0.036 49.019 0.054 ;
     RECT  50.467 0.036 50.567 0.054 ;
     RECT  52.303 43.146 52.403 43.164 ;
     RECT  25.439 2.151 52.807 41.049 ;
     RECT  52.807 2.151 53.735 41.094 ;
     RECT  54.283 43.146 55.643 43.164 ;
     RECT  56.551 0.036 56.651 0.054 ;
     RECT  53.735 2.151 56.983 41.049 ;
     RECT  56.767 43.146 57.371 43.164 ;
     RECT  56.983 1.728 57.515 41.049 ;
     RECT  60.259 43.146 60.359 43.164 ;
     RECT  60.979 1.152 61.223 1.17 ;
     RECT  63.139 43.146 63.275 43.164 ;
     RECT  63.895 0.036 64.031 0.054 ;
     RECT  64.219 43.146 64.319 43.164 ;
     RECT  57.515 2.151 64.723 41.049 ;
     RECT  64.723 2.151 64.895 41.094 ;
     RECT  67.099 43.146 67.739 43.164 ;
     RECT  68.539 0.036 68.639 0.054 ;
     RECT  69.691 43.146 69.791 43.164 ;
     RECT  64.895 2.151 70.447 41.049 ;
     RECT  70.447 2.106 71.231 41.049 ;
     RECT  71.131 43.146 71.231 43.164 ;
     RECT  72.031 0.036 72.743 0.054 ;
     RECT  72.175 43.146 72.779 43.164 ;
     RECT  71.231 2.151 75.379 41.049 ;
     RECT  75.847 0.036 75.983 0.054 ;
     RECT  75.379 2.106 76.055 41.049 ;
     RECT  76.055 2.151 76.171 41.049 ;
     RECT  76.171 2.151 76.595 41.094 ;
     RECT  76.963 1.152 77.063 1.17 ;
     RECT  77.647 43.146 77.855 43.164 ;
     RECT  76.595 2.151 78.115 41.049 ;
     RECT  78.115 1.53 78.431 41.049 ;
     RECT  78.431 2.151 79.231 41.049 ;
     RECT  79.231 2.106 79.367 41.049 ;
     RECT  79.627 43.146 79.727 43.164 ;
     RECT  78.835 0.036 79.799 0.054 ;
     RECT  79.915 1.152 80.051 1.17 ;
     RECT  79.367 2.151 81.031 41.049 ;
     RECT  80.995 1.152 81.239 1.17 ;
     RECT  81.031 2.106 81.355 41.049 ;
     RECT  81.355 1.728 81.671 41.049 ;
     RECT  82.255 0.036 82.463 0.054 ;
     RECT  81.671 2.151 82.615 41.049 ;
     RECT  82.615 2.151 83.075 41.094 ;
     RECT  83.335 0.036 84.227 0.054 ;
     RECT  83.075 2.151 84.487 41.049 ;
     RECT  84.487 2.106 84.695 41.049 ;
     RECT  85.603 43.146 85.811 43.164 ;
     RECT  87.043 1.152 87.143 1.17 ;
     RECT  87.079 43.146 87.179 43.164 ;
     RECT  88.447 1.152 88.583 1.17 ;
     RECT  88.195 0.036 90.023 0.054 ;
     RECT  91.579 43.146 91.679 43.164 ;
     RECT  91.795 0.036 92.543 0.054 ;
     RECT  92.551 43.146 92.723 43.164 ;
     RECT  84.695 2.151 94.063 41.049 ;
     RECT  94.063 2.106 94.163 41.049 ;
     RECT  93.559 43.146 94.163 43.164 ;
     RECT  94.171 0.036 94.307 0.054 ;
     RECT  94.351 0.576 94.667 0.594 ;
     RECT  95.359 1.152 95.639 1.17 ;
     RECT  95.647 0.036 95.747 0.054 ;
     RECT  95.539 43.146 96.143 43.164 ;
     RECT  96.799 1.152 97.871 1.17 ;
     RECT  97.879 0.036 98.051 0.054 ;
     RECT  97.015 43.146 98.051 43.164 ;
     RECT  98.599 1.152 98.771 1.17 ;
     RECT  99.571 0.036 100.103 0.054 ;
     RECT  101.119 0.036 101.219 0.054 ;
     RECT  101.119 1.152 101.219 1.17 ;
     RECT  103.999 43.146 104.999 43.164 ;
     RECT  105.079 0.036 105.179 0.054 ;
     RECT  106.447 0.036 106.547 0.054 ;
     RECT  106.951 43.146 107.591 43.164 ;
     RECT  94.163 2.151 110.371 41.049 ;
     RECT  110.371 2.151 110.471 41.13 ;
     RECT  110.371 0.036 110.507 0.054 ;
     RECT  113.431 43.146 113.639 43.164 ;
     RECT  114.907 42.228 115.007 42.246 ;
     RECT  115.483 0.036 115.979 0.054 ;
     RECT  115.915 43.146 116.519 43.164 ;
     RECT  117.715 0.036 118.283 0.054 ;
     RECT  120.379 43.146 120.479 43.164 ;
     RECT  120.343 0.036 121.667 0.054 ;
     RECT  122.863 43.146 122.999 43.164 ;
     RECT  122.899 0.036 123.035 0.054 ;
     RECT  123.907 0.036 124.007 0.054 ;
     RECT  123.871 43.146 124.223 43.164 ;
     RECT  125.419 1.152 125.519 1.17 ;
     RECT  110.471 2.151 125.851 41.049 ;
     RECT  125.779 0.036 125.879 0.054 ;
     RECT  125.851 2.151 126.095 41.094 ;
     RECT  126.355 43.146 126.455 43.164 ;
     RECT  126.895 0.036 126.995 0.054 ;
     RECT  127.327 43.146 128.471 43.164 ;
     RECT  128.335 0.036 129.191 0.054 ;
     RECT  130.819 43.146 131.459 43.164 ;
     RECT  131.755 0.036 132.791 0.054 ;
     RECT  126.095 2.151 132.799 41.049 ;
     RECT  132.799 2.151 133.115 41.094 ;
     RECT  134.203 43.146 135.527 43.164 ;
     RECT  136.291 43.146 136.391 43.164 ;
     RECT  136.615 0.036 136.715 0.054 ;
     RECT  137.263 43.146 137.363 43.164 ;
     RECT  137.407 0.108 137.767 0.126 ;
     RECT  137.767 0.036 137.795 0.126 ;
     RECT  137.795 0.036 137.939 0.054 ;
     RECT  139.495 0.036 140.099 0.054 ;
     RECT  133.115 2.151 140.755 41.049 ;
     RECT  140.755 2.151 140.927 41.094 ;
     RECT  141.043 43.146 141.287 43.164 ;
     RECT  141.619 0.036 141.791 0.054 ;
     RECT  142.735 0.036 142.907 0.054 ;
     RECT  143.743 43.146 143.879 43.164 ;
     RECT  144.319 0.036 145.859 0.054 ;
     RECT  145.723 43.146 145.895 43.164 ;
     RECT  147.235 0.036 147.443 0.054 ;
     RECT  146.731 43.146 148.207 43.164 ;
     RECT  148.207 43.074 148.415 43.164 ;
     RECT  148.415 43.146 148.739 43.164 ;
     RECT  148.315 0.036 148.775 0.054 ;
     RECT  150.151 0.036 150.251 0.054 ;
     RECT  149.683 43.146 150.971 43.164 ;
     RECT  151.267 0.036 152.411 0.054 ;
     RECT  152.095 43.146 152.699 43.164 ;
     RECT  140.927 2.151 153.679 41.049 ;
     RECT  153.463 0.036 153.779 0.054 ;
     RECT  153.679 2.151 153.959 41.13 ;
     RECT  155.659 43.146 156.155 43.164 ;
     RECT  156.307 0.036 156.443 0.054 ;
     RECT  157.135 43.146 157.811 43.164 ;
     RECT  157.747 0.036 157.883 0.054 ;
     RECT  158.647 43.146 158.783 43.164 ;
     RECT  159.619 43.146 159.755 43.164 ;
     RECT  159.223 0.036 159.971 0.054 ;
     RECT  153.959 2.151 162 41.049 ;
     RECT  162 3.456 162.311 4.14 ;
     RECT  162.311 3.888 162.455 4.14 ;
     RECT  162 36.828 162.455 36.954 ;
     RECT  162 38.142 162.491 38.16 ;
     RECT  162 40.446 162.635 41.004 ;
     RECT  162 4.932 162.671 5.22 ;
     RECT  162.671 5.202 162.887 5.22 ;
     RECT  162.635 40.986 163.067 41.004 ;
     RECT  162.455 36.936 163.139 36.954 ;
     RECT  162.455 4.122 163.247 4.14 ;
    LAYER M3 ;
     RECT  70.596 0.012 116.226 0.059 ;
     RECT  0.576 0.012 22.734 0.077 ;
     RECT  23.58 0.012 69.75 0.077 ;
     RECT  117.072 0.012 163.242 0.077 ;
     RECT  84.204 0.059 116.226 0.173 ;
     RECT  84.204 0.173 110.394 0.557 ;
     RECT  111.204 0.173 116.226 0.557 ;
     RECT  117.432 0.077 127.278 0.557 ;
     RECT  20.988 0.077 22.734 1.723 ;
     RECT  23.58 0.077 37.026 1.723 ;
     RECT  37.764 0.077 46.854 1.723 ;
     RECT  47.628 0.077 51.21 1.723 ;
     RECT  52.2 0.077 52.65 1.723 ;
     RECT  53.748 0.077 69.75 1.723 ;
     RECT  70.596 0.059 83.358 1.723 ;
     RECT  84.204 0.557 109.062 1.723 ;
     RECT  110.376 0.557 110.394 1.723 ;
     RECT  111.204 0.557 114.786 1.723 ;
     RECT  115.56 0.557 116.226 1.723 ;
     RECT  117.432 0.557 121.806 1.723 ;
     RECT  122.544 0.557 127.278 1.723 ;
     RECT  128.412 0.077 158.166 1.723 ;
     RECT  159.408 0.077 163.242 2.011 ;
     RECT  20.484 1.723 83.358 2.143 ;
     RECT  84.096 1.723 116.478 2.143 ;
     RECT  0.576 0.077 19.566 2.191 ;
     RECT  117.252 1.723 127.278 2.191 ;
     RECT  128.412 1.723 158.202 2.191 ;
     RECT  158.94 2.011 163.242 2.191 ;
     RECT  0.576 2.191 19.746 2.263 ;
     RECT  20.484 2.143 116.478 2.263 ;
     RECT  117.252 2.191 163.242 2.263 ;
     RECT  0.576 2.263 163.242 3.605 ;
     RECT  0.936 3.605 163.242 3.983 ;
     RECT  1.296 3.983 163.242 4.019 ;
     RECT  162.648 4.019 163.242 4.145 ;
     RECT  0.108 3.979 0.126 4.157 ;
     RECT  1.296 4.019 161.874 4.927 ;
     RECT  162.648 4.145 162.882 4.927 ;
     RECT  1.296 4.927 162.882 4.955 ;
     RECT  113.868 4.955 162.882 5.027 ;
     RECT  113.868 5.027 161.802 5.189 ;
     RECT  1.296 4.955 113.094 5.225 ;
     RECT  113.868 5.189 114.138 5.225 ;
     RECT  162.864 5.027 162.882 5.225 ;
     RECT  1.296 5.225 101.862 5.369 ;
     RECT  113.076 5.225 113.094 5.459 ;
     RECT  113.904 5.225 114.138 5.459 ;
     RECT  114.876 5.189 161.802 5.459 ;
     RECT  122.256 5.459 161.802 5.495 ;
     RECT  102.636 5.225 112.122 5.501 ;
     RECT  114.876 5.459 121.497 5.531 ;
     RECT  102.636 5.501 111.762 5.603 ;
     RECT  113.904 5.459 113.922 5.639 ;
     RECT  102.636 5.603 111.654 5.693 ;
     RECT  122.256 5.495 151.83 5.729 ;
     RECT  122.256 5.729 144.486 5.741 ;
     RECT  1.296 5.369 27.126 5.765 ;
     RECT  102.708 5.693 111.654 5.789 ;
     RECT  145.224 5.729 151.83 5.789 ;
     RECT  145.224 5.789 151.398 5.857 ;
     RECT  2.016 5.765 27.126 5.873 ;
     RECT  2.34 5.873 27.126 5.885 ;
     RECT  11.556 5.885 27.126 5.909 ;
     RECT  102.708 5.789 111.186 5.909 ;
     RECT  2.34 5.885 10.602 5.933 ;
     RECT  17.352 5.909 27.126 5.933 ;
     RECT  11.556 5.909 16.578 5.999 ;
     RECT  152.64 5.495 161.802 6.029 ;
     RECT  2.34 5.933 10.35 6.071 ;
     RECT  17.352 5.933 21.186 6.077 ;
     RECT  109.44 5.909 110.754 6.077 ;
     RECT  28.08 5.369 101.862 6.173 ;
     RECT  10.332 6.071 10.35 6.221 ;
     RECT  2.34 6.071 9.594 6.269 ;
     RECT  11.664 5.999 16.506 6.269 ;
     RECT  110.415 6.077 110.754 6.269 ;
     RECT  2.34 6.269 8.514 6.275 ;
     RECT  2.34 6.275 8.442 6.305 ;
     RECT  102.708 5.909 108.486 6.305 ;
     RECT  2.376 6.305 8.442 6.377 ;
     RECT  104.004 6.305 108.486 6.413 ;
     RECT  108.432 6.413 108.45 6.575 ;
     RECT  17.388 6.077 21.186 6.611 ;
     RECT  145.224 5.857 149.418 6.611 ;
     RECT  155.484 6.029 161.802 6.691 ;
     RECT  2.415 6.377 8.442 6.749 ;
     RECT  155.484 6.691 161.874 6.749 ;
     RECT  109.44 6.077 109.53 6.845 ;
     RECT  102.708 6.305 103.086 6.881 ;
     RECT  109.512 6.845 109.53 7.115 ;
     RECT  13.215 6.269 16.506 7.123 ;
     RECT  17.388 6.611 18.897 7.123 ;
     RECT  12.06 6.269 12.078 7.151 ;
     RECT  104.004 6.413 107.442 7.151 ;
     RECT  152.64 6.029 154.746 7.151 ;
     RECT  21.924 5.933 27.126 7.159 ;
     RECT  28.08 6.173 96.57 7.159 ;
     RECT  19.62 6.611 21.186 7.187 ;
     RECT  104.004 7.151 107.334 7.223 ;
     RECT  145.332 6.611 149.418 7.259 ;
     RECT  2.415 6.749 8.262 7.349 ;
     RECT  104.004 7.223 106.794 7.421 ;
     RECT  2.415 7.349 6.318 7.483 ;
     RECT  2.304 7.483 6.318 7.655 ;
     RECT  113.04 7.123 113.058 7.663 ;
     RECT  122.256 5.741 132.354 7.663 ;
     RECT  133.272 5.741 144.486 7.663 ;
     RECT  19.62 7.187 20.106 7.691 ;
     RECT  155.484 6.749 161.838 7.765 ;
     RECT  155.484 7.765 161.874 7.805 ;
     RECT  2.415 7.655 6.318 7.889 ;
     RECT  2.415 7.889 5.274 7.925 ;
     RECT  20.844 7.187 21.186 8.239 ;
     RECT  21.924 7.159 96.57 8.239 ;
     RECT  104.58 7.421 106.794 8.267 ;
     RECT  104.58 8.267 106.182 8.303 ;
     RECT  97.308 6.173 101.862 8.429 ;
     RECT  19.62 7.691 19.782 8.843 ;
     RECT  97.308 8.429 100.134 8.843 ;
     RECT  145.332 7.259 149.238 8.879 ;
     RECT  101.16 8.429 101.862 9.005 ;
     RECT  104.76 8.303 106.182 9.041 ;
     RECT  102.924 6.881 103.086 9.085 ;
     RECT  20.844 8.239 96.57 9.113 ;
     RECT  102.78 9.085 103.086 9.391 ;
     RECT  115.02 5.531 121.497 9.517 ;
     RECT  101.16 9.005 101.826 9.581 ;
     RECT  4.104 7.925 5.274 9.787 ;
     RECT  6.048 7.889 6.318 9.787 ;
     RECT  4.104 9.787 6.318 9.851 ;
     RECT  6.048 9.851 6.318 9.895 ;
     RECT  7.128 7.349 8.262 9.895 ;
     RECT  114.444 9.517 121.497 9.931 ;
     RECT  6.048 9.895 8.262 10.121 ;
     RECT  2.415 7.925 3.258 10.165 ;
     RECT  4.104 9.851 5.274 10.165 ;
     RECT  2.415 10.165 5.274 10.507 ;
     RECT  101.808 9.581 101.826 10.561 ;
     RECT  102.78 9.391 103.194 10.561 ;
     RECT  2.412 10.507 5.274 10.625 ;
     RECT  2.415 10.625 5.274 10.831 ;
     RECT  6.048 10.121 6.318 10.831 ;
     RECT  2.415 10.831 6.318 10.859 ;
     RECT  7.128 10.121 8.262 10.975 ;
     RECT  7.128 10.975 8.442 11.011 ;
     RECT  104.76 9.041 105.75 11.039 ;
     RECT  7.128 11.011 8.946 11.201 ;
     RECT  101.808 10.561 103.194 11.209 ;
     RECT  111.636 9.481 111.654 11.713 ;
     RECT  101.268 11.209 103.194 12.253 ;
     RECT  153.615 7.151 154.746 12.361 ;
     RECT  155.484 7.805 161.838 12.361 ;
     RECT  2.415 10.859 6.174 12.475 ;
     RECT  2.304 12.475 6.174 12.515 ;
     RECT  7.128 11.201 8.262 12.523 ;
     RECT  145.62 8.879 149.238 12.523 ;
     RECT  150.228 5.857 151.398 12.523 ;
     RECT  152.64 7.151 152.658 12.523 ;
     RECT  153.615 12.361 161.838 12.523 ;
     RECT  10.332 12.523 10.35 12.571 ;
     RECT  105.015 11.039 105.75 12.793 ;
     RECT  20.844 9.113 96.498 12.829 ;
     RECT  97.308 8.843 100.026 12.829 ;
     RECT  114.3 9.931 121.497 12.829 ;
     RECT  122.256 7.663 144.486 12.829 ;
     RECT  114.3 12.829 144.486 12.857 ;
     RECT  7.128 12.523 8.37 12.901 ;
     RECT  9.972 12.571 10.35 12.901 ;
     RECT  13.215 7.123 18.897 12.901 ;
     RECT  19.62 8.843 19.674 12.901 ;
     RECT  145.62 12.523 151.398 12.901 ;
     RECT  152.46 12.523 161.838 12.901 ;
     RECT  108.396 8.239 108.414 12.991 ;
     RECT  7.128 12.901 8.514 13.085 ;
     RECT  2.415 12.515 6.174 13.099 ;
     RECT  7.128 13.085 8.262 13.099 ;
     RECT  9.972 12.901 10.566 13.099 ;
     RECT  13.215 12.901 19.674 13.099 ;
     RECT  9.9 13.099 10.566 13.147 ;
     RECT  11.628 13.099 11.646 13.147 ;
     RECT  13.104 13.099 19.674 13.147 ;
     RECT  9.9 13.147 11.646 13.291 ;
     RECT  9.9 13.291 11.934 13.325 ;
     RECT  105.015 12.793 105.894 13.369 ;
     RECT  20.844 12.829 100.026 13.397 ;
     RECT  114.3 12.857 144.27 13.433 ;
     RECT  145.62 12.901 161.838 13.441 ;
     RECT  10.116 13.325 11.934 13.531 ;
     RECT  10.116 13.531 12.078 13.661 ;
     RECT  10.296 13.661 12.078 13.675 ;
     RECT  12.816 13.147 19.674 13.675 ;
     RECT  145.116 13.441 161.838 13.675 ;
     RECT  10.296 13.675 19.674 13.865 ;
     RECT  144.972 13.675 161.838 13.865 ;
     RECT  145.116 13.865 161.838 13.901 ;
     RECT  113.04 7.663 113.562 13.945 ;
     RECT  114.3 13.433 143.982 13.945 ;
     RECT  113.04 13.945 143.982 13.973 ;
     RECT  19.62 13.865 19.674 13.981 ;
     RECT  19.62 13.981 19.782 14.045 ;
     RECT  2.415 13.099 8.262 14.203 ;
     RECT  10.296 13.865 18.897 14.237 ;
     RECT  10.296 14.237 12.078 14.243 ;
     RECT  2.415 14.203 8.406 14.251 ;
     RECT  101.268 12.253 103.338 14.369 ;
     RECT  10.296 14.243 10.422 14.395 ;
     RECT  11.16 14.243 12.078 14.405 ;
     RECT  2.415 14.251 8.694 14.44 ;
     RECT  9.864 14.395 10.422 14.44 ;
     RECT  102.24 14.369 103.338 14.521 ;
     RECT  13.104 14.237 18.897 14.573 ;
     RECT  111.636 11.713 112.266 14.611 ;
     RECT  2.415 14.44 10.422 14.813 ;
     RECT  11.268 14.405 11.286 14.813 ;
     RECT  12.06 14.405 12.078 14.813 ;
     RECT  2.415 14.813 6.678 14.819 ;
     RECT  7.416 14.813 8.802 14.819 ;
     RECT  9.972 14.813 10.422 14.819 ;
     RECT  155.16 13.901 161.838 15.061 ;
     RECT  2.415 14.819 6.354 16.411 ;
     RECT  7.416 14.819 8.262 16.411 ;
     RECT  2.415 16.411 8.262 16.507 ;
     RECT  2.304 16.507 8.262 16.565 ;
     RECT  2.415 16.565 6.354 16.799 ;
     RECT  7.164 16.565 8.262 16.799 ;
     RECT  108.396 12.991 109.134 16.807 ;
     RECT  2.415 16.799 6.174 16.871 ;
     RECT  105.015 13.369 106.362 17.419 ;
     RECT  7.416 16.799 8.262 17.455 ;
     RECT  2.415 16.871 5.886 17.608 ;
     RECT  7.416 17.455 8.658 17.609 ;
     RECT  2.415 17.608 6.246 17.645 ;
     RECT  102.24 14.521 103.842 17.923 ;
     RECT  105.015 17.419 106.902 17.923 ;
     RECT  113.04 13.973 143.097 18.527 ;
     RECT  113.04 18.527 126.897 18.563 ;
     RECT  13.215 14.573 18.897 18.599 ;
     RECT  20.844 13.397 20.862 19.075 ;
     RECT  20.52 19.075 20.862 19.139 ;
     RECT  13.215 18.599 16.794 19.229 ;
     RECT  110.415 6.269 110.697 19.651 ;
     RECT  17.892 18.599 18.897 19.741 ;
     RECT  19.62 14.045 19.674 19.741 ;
     RECT  13.215 19.229 15.678 19.769 ;
     RECT  15.156 19.769 15.678 20.219 ;
     RECT  21.6 13.397 100.026 20.219 ;
     RECT  119.556 18.563 126.897 20.219 ;
     RECT  17.892 19.741 19.674 20.281 ;
     RECT  20.52 19.139 20.538 20.281 ;
     RECT  15.66 20.219 15.678 20.309 ;
     RECT  145.116 13.901 154.422 20.309 ;
     RECT  110.232 19.651 110.697 20.353 ;
     RECT  21.6 20.219 29.697 20.539 ;
     RECT  127.98 18.527 143.097 20.857 ;
     RECT  110.016 20.353 110.697 20.893 ;
     RECT  119.592 20.219 126.897 20.965 ;
     RECT  127.62 20.857 143.097 20.965 ;
     RECT  21.528 20.539 29.697 21.091 ;
     RECT  30.42 20.219 100.026 21.091 ;
     RECT  2.415 17.645 5.418 21.115 ;
     RECT  7.416 17.609 8.262 21.115 ;
     RECT  13.215 19.769 13.95 21.115 ;
     RECT  21.528 21.091 100.026 21.115 ;
     RECT  101.268 14.369 101.286 21.115 ;
     RECT  102.24 17.923 106.902 21.115 ;
     RECT  107.82 16.807 109.134 21.115 ;
     RECT  110.016 20.893 110.79 21.115 ;
     RECT  119.592 20.965 143.097 21.115 ;
     RECT  143.892 13.973 143.982 21.115 ;
     RECT  145.116 20.309 145.134 21.115 ;
     RECT  109.872 21.115 110.79 21.119 ;
     RECT  2.415 21.115 5.562 21.163 ;
     RECT  6.444 21.115 6.462 21.163 ;
     RECT  13.14 21.115 13.95 21.163 ;
     RECT  12.384 21.115 12.402 21.259 ;
     RECT  13.14 21.163 14.346 21.259 ;
     RECT  17.892 20.281 20.538 21.259 ;
     RECT  21.528 21.115 101.286 21.259 ;
     RECT  16.776 19.229 16.794 21.271 ;
     RECT  144.972 21.115 145.134 21.271 ;
     RECT  146.376 20.309 154.422 21.271 ;
     RECT  155.16 15.061 161.874 21.271 ;
     RECT  111.636 14.611 112.302 21.361 ;
     RECT  113.04 18.563 118.782 21.361 ;
     RECT  15.264 21.403 15.282 21.433 ;
     RECT  16.416 21.271 16.794 21.433 ;
     RECT  111.636 21.361 118.782 21.433 ;
     RECT  119.592 21.115 143.982 21.433 ;
     RECT  10.44 21.115 10.458 21.505 ;
     RECT  102.24 21.115 109.134 21.505 ;
     RECT  109.872 21.119 110.697 21.505 ;
     RECT  2.415 21.163 6.462 21.541 ;
     RECT  10.44 21.505 10.566 21.541 ;
     RECT  11.412 21.163 11.43 21.541 ;
     RECT  12.384 21.259 14.346 21.541 ;
     RECT  17.892 21.259 101.286 21.541 ;
     RECT  111.636 21.433 143.982 21.541 ;
     RECT  144.972 21.271 145.35 21.541 ;
     RECT  7.308 21.115 9.054 21.631 ;
     RECT  11.412 21.541 14.346 21.631 ;
     RECT  7.308 21.631 9.162 21.643 ;
     RECT  111.636 21.541 144.126 21.643 ;
     RECT  144.9 21.541 145.35 21.643 ;
     RECT  146.376 21.271 161.874 21.643 ;
     RECT  7.308 21.643 9.234 21.659 ;
     RECT  7.416 21.659 9.234 21.811 ;
     RECT  10.44 21.541 10.674 21.811 ;
     RECT  11.412 21.631 14.454 21.811 ;
     RECT  17.892 21.541 101.43 21.811 ;
     RECT  7.416 21.811 9.306 21.835 ;
     RECT  15.264 21.433 16.794 21.835 ;
     RECT  111.636 21.643 161.874 21.839 ;
     RECT  10.44 21.811 14.454 21.901 ;
     RECT  15.264 21.835 16.938 21.901 ;
     RECT  111.636 21.839 146.646 21.901 ;
     RECT  17.892 21.811 101.502 21.965 ;
     RECT  7.416 21.835 9.378 21.973 ;
     RECT  10.44 21.901 16.938 21.973 ;
     RECT  17.892 21.965 19.17 21.973 ;
     RECT  147.456 21.839 161.874 22.001 ;
     RECT  7.416 21.973 19.17 22.013 ;
     RECT  102.24 21.505 110.697 22.045 ;
     RECT  111.456 21.901 146.646 22.045 ;
     RECT  2.415 21.541 6.57 22.081 ;
     RECT  19.944 21.965 101.502 22.081 ;
     RECT  102.24 22.045 146.646 22.081 ;
     RECT  7.416 22.013 17.082 22.208 ;
     RECT  7.416 22.208 14.706 22.271 ;
     RECT  15.516 22.208 17.082 22.469 ;
     RECT  2.415 22.081 6.642 22.621 ;
     RECT  7.416 22.271 9.018 22.621 ;
     RECT  155.124 22.001 161.874 23.081 ;
     RECT  2.415 22.621 9.018 24.475 ;
     RECT  2.304 24.475 9.018 24.935 ;
     RECT  2.415 24.935 9.018 26.587 ;
     RECT  2.34 26.587 9.018 26.627 ;
     RECT  155.124 23.081 161.802 30.065 ;
     RECT  155.124 30.065 161.694 31.145 ;
     RECT  155.124 31.145 161.442 34.501 ;
     RECT  155.124 34.501 161.622 34.771 ;
     RECT  155.124 34.771 161.766 34.933 ;
     RECT  155.124 34.933 161.802 36.121 ;
     RECT  18 22.013 19.17 36.481 ;
     RECT  19.944 22.081 146.646 36.481 ;
     RECT  15.552 22.469 17.082 36.661 ;
     RECT  18 36.481 146.646 36.661 ;
     RECT  155.124 36.121 161.91 36.823 ;
     RECT  155.124 36.823 162.45 36.931 ;
     RECT  155.124 36.931 163.134 36.959 ;
     RECT  15.552 36.661 146.646 37.165 ;
     RECT  15.516 37.165 146.646 37.201 ;
     RECT  147.456 22.001 154.386 37.201 ;
     RECT  155.124 36.959 162.126 37.201 ;
     RECT  9.756 22.271 14.706 37.471 ;
     RECT  15.516 37.201 162.126 37.471 ;
     RECT  2.415 26.627 9.018 37.561 ;
     RECT  9.756 37.471 162.126 37.561 ;
     RECT  2.415 37.561 162.126 38.137 ;
     RECT  163.116 36.959 163.134 38.137 ;
     RECT  2.415 38.137 163.134 38.209 ;
     RECT  2.34 38.209 163.134 38.507 ;
     RECT  2.415 38.507 163.134 39.631 ;
     RECT  2.376 39.631 163.134 40.171 ;
     RECT  2.304 40.171 163.134 40.829 ;
     RECT  2.304 40.829 3.366 40.865 ;
     RECT  4.104 40.829 163.134 40.865 ;
     RECT  2.304 40.865 3.222 40.981 ;
     RECT  4.608 40.865 163.134 41.021 ;
     RECT  1.98 40.981 3.222 41.165 ;
     RECT  4.608 41.021 11.574 41.213 ;
     RECT  93.924 41.021 147.33 41.645 ;
     RECT  1.98 41.165 2.322 42.173 ;
     RECT  54.612 41.021 93.078 42.173 ;
     RECT  93.924 41.645 134.73 42.173 ;
     RECT  156.06 41.021 163.134 42.173 ;
     RECT  4.608 41.213 8.118 43.141 ;
     RECT  9.072 41.213 11.574 43.141 ;
     RECT  12.384 41.021 23.094 43.141 ;
     RECT  23.832 41.021 43.398 43.141 ;
     RECT  44.244 41.021 53.838 43.141 ;
     RECT  54.612 42.173 54.81 43.141 ;
     RECT  55.62 42.173 93.078 43.141 ;
     RECT  93.924 42.173 123.39 43.141 ;
     RECT  124.2 42.173 134.73 43.141 ;
     RECT  135.504 41.645 147.33 43.141 ;
     RECT  148.176 41.021 155.178 43.141 ;
     RECT  156.132 42.173 163.134 43.141 ;
     RECT  0.792 40.531 0.81 43.181 ;
     RECT  1.98 42.173 1.998 43.181 ;
     RECT  3.204 41.165 3.222 43.181 ;
     RECT  4.608 43.141 163.134 43.181 ;
    LAYER M4 ;
     RECT  0.06 21.504 0.133 21.528 ;
     RECT  0.133 21.504 0.179 21.768 ;
     RECT  1.381 42.144 2.333 42.168 ;
     RECT  0.06 2.4 2.408 5.592 ;
     RECT  0.06 7.488 2.408 7.512 ;
     RECT  0.06 9.504 2.408 9.528 ;
     RECT  0.06 10.512 2.408 10.536 ;
     RECT  0.06 12.48 2.408 12.504 ;
     RECT  0.06 14.496 2.408 14.52 ;
     RECT  0.06 16.512 2.408 16.536 ;
     RECT  0.179 21.744 2.408 21.768 ;
     RECT  0.06 24.48 2.408 24.504 ;
     RECT  2.329 26.592 2.408 26.616 ;
     RECT  0.06 28.992 2.408 29.016 ;
     RECT  2.408 2.148 2.54 41.052 ;
     RECT  2.54 2.148 2.627 41.16 ;
     RECT  2.627 2.148 2.704 40.782 ;
     RECT  2.485 0.096 2.819 0.12 ;
     RECT  2.704 13.68 2.837 14.52 ;
     RECT  2.704 38.448 2.845 39.96 ;
     RECT  2.704 3.408 2.909 5.064 ;
     RECT  2.909 5.04 2.945 5.064 ;
     RECT  2.909 3.408 3.125 3.432 ;
     RECT  2.845 39.936 3.341 39.96 ;
     RECT  2.704 6.192 3.449 6.84 ;
     RECT  2.845 38.448 3.665 38.76 ;
     RECT  2.704 12.576 3.877 12.6 ;
     RECT  2.837 13.68 3.877 14.28 ;
     RECT  3.877 12.576 3.913 14.28 ;
     RECT  3.449 6.48 3.985 6.84 ;
     RECT  2.704 28.992 4.133 29.016 ;
     RECT  3.836 5.376 4.237 5.4 ;
     RECT  3.913 12.576 4.313 14.808 ;
     RECT  2.704 21.648 4.345 21.768 ;
     RECT  3.665 38.448 4.457 38.472 ;
     RECT  4.345 21.12 4.499 21.768 ;
     RECT  4.313 12.576 4.561 12.6 ;
     RECT  4.313 13.632 4.573 14.808 ;
     RECT  4.237 4.56 4.597 5.4 ;
     RECT  3.985 6.48 4.597 6.936 ;
     RECT  4.597 4.56 4.892 6.936 ;
     RECT  4.849 7.968 4.892 7.992 ;
     RECT  4.993 9.696 5.057 9.72 ;
     RECT  5.057 9.696 5.077 10.248 ;
     RECT  5.077 9.792 5.141 10.248 ;
     RECT  4.892 4.56 5.173 7.992 ;
     RECT  5.173 4.512 5.257 7.992 ;
     RECT  4.597 0.528 5.363 0.552 ;
     RECT  5.209 17.088 5.363 17.112 ;
     RECT  4.499 21.168 5.533 21.768 ;
     RECT  4.573 13.68 5.557 14.808 ;
     RECT  4.561 12.528 5.573 12.6 ;
     RECT  5.557 13.68 5.597 15.096 ;
     RECT  5.257 4.56 5.603 7.992 ;
     RECT  5.141 9.792 5.644 9.816 ;
     RECT  4.837 41.568 5.645 41.592 ;
     RECT  5.533 21.12 5.653 21.768 ;
     RECT  5.597 13.056 5.681 15.096 ;
     RECT  5.677 40.992 5.845 41.016 ;
     RECT  5.845 40.368 5.861 41.016 ;
     RECT  5.365 16.56 5.897 16.584 ;
     RECT  2.704 26.592 5.941 26.616 ;
     RECT  5.681 13.104 5.969 15.096 ;
     RECT  5.941 26.208 5.987 26.616 ;
     RECT  2.869 1.728 5.996 1.752 ;
     RECT  5.969 13.104 6.035 14.856 ;
     RECT  4.741 38.64 6.073 38.664 ;
     RECT  5.603 4.56 6.076 7.368 ;
     RECT  5.996 1.728 6.083 2.28 ;
     RECT  6.073 38.208 6.113 38.664 ;
     RECT  5.861 40.368 6.221 40.392 ;
     RECT  6.076 4.56 6.236 6.84 ;
     RECT  6.113 38.208 6.253 38.424 ;
     RECT  5.987 26.208 6.275 26.232 ;
     RECT  6.217 17.616 6.301 17.64 ;
     RECT  6.236 4.512 6.323 6.84 ;
     RECT  6.325 43.056 6.653 43.08 ;
     RECT  6.853 42.144 7.157 42.168 ;
     RECT  6.083 1.728 7.297 1.752 ;
     RECT  6.613 39.888 7.333 39.912 ;
     RECT  6.323 4.656 7.388 6.84 ;
     RECT  7.388 4.656 7.429 7.272 ;
     RECT  6.505 3.408 7.441 3.432 ;
     RECT  7.297 1.632 7.475 1.752 ;
     RECT  6.035 13.104 7.525 14.808 ;
     RECT  7.475 1.728 7.693 1.752 ;
     RECT  7.693 1.728 7.808 2.04 ;
     RECT  7.441 3.312 7.808 3.432 ;
     RECT  7.429 4.512 7.808 7.272 ;
     RECT  5.365 10.992 7.808 11.016 ;
     RECT  7.525 12.528 7.808 14.808 ;
     RECT  5.653 21.12 7.808 22.248 ;
     RECT  5.941 28.512 7.808 28.536 ;
     RECT  6.253 38.112 7.808 38.424 ;
     RECT  7.333 39.888 7.808 40.488 ;
     RECT  7.808 1.728 7.813 41.052 ;
     RECT  7.813 1.728 8.104 41.208 ;
     RECT  8.104 4.512 8.339 6.84 ;
     RECT  8.104 3.408 8.381 3.432 ;
     RECT  8.104 12.528 8.381 14.808 ;
     RECT  8.104 40.464 8.417 41.208 ;
     RECT  8.339 4.512 8.915 6.744 ;
     RECT  8.104 21.12 8.921 22.248 ;
     RECT  8.921 21.12 9.065 21.96 ;
     RECT  8.104 38.16 9.097 38.76 ;
     RECT  8.417 40.464 9.097 41.016 ;
     RECT  9.097 38.16 9.137 41.016 ;
     RECT  8.915 4.512 9.26 6.264 ;
     RECT  9.26 4.272 9.347 6.264 ;
     RECT  8.381 12.576 9.397 14.808 ;
     RECT  9.385 3.408 9.469 3.432 ;
     RECT  9.347 4.512 9.577 6.264 ;
     RECT  9.137 40.992 9.605 41.016 ;
     RECT  9.541 2.88 9.785 2.904 ;
     RECT  9.137 38.16 9.829 39.576 ;
     RECT  9.829 37.584 9.916 39.576 ;
     RECT  9.916 38.16 9.929 39.576 ;
     RECT  9.577 4.512 10.009 6.216 ;
     RECT  9.065 21.648 10.069 21.96 ;
     RECT  9.829 42.144 10.109 42.168 ;
     RECT  9.929 38.4 10.145 39.576 ;
     RECT  10.069 21.168 10.165 21.96 ;
     RECT  8.104 1.728 10.172 1.752 ;
     RECT  9.397 12.528 10.361 14.808 ;
     RECT  10.165 21.12 10.405 21.96 ;
     RECT  10.009 4.656 10.451 6.216 ;
     RECT  10.405 21.12 10.469 22.152 ;
     RECT  10.361 13.056 10.621 14.808 ;
     RECT  10.451 4.656 10.643 5.928 ;
     RECT  10.309 40.464 10.829 40.536 ;
     RECT  10.829 40.512 10.835 40.536 ;
     RECT  10.172 1.728 10.979 2.28 ;
     RECT  10.643 4.656 10.988 5.88 ;
     RECT  10.145 38.4 11.117 39.336 ;
     RECT  10.988 4.512 11.365 5.88 ;
     RECT  10.979 1.728 11.437 1.752 ;
     RECT  11.365 3.936 11.653 5.88 ;
     RECT  11.437 1.68 11.699 1.752 ;
     RECT  11.653 3.936 11.737 6.264 ;
     RECT  11.117 38.4 11.869 38.952 ;
     RECT  10.469 21.168 11.893 22.152 ;
     RECT  11.869 37.488 12.035 38.952 ;
     RECT  11.893 21.12 12.089 22.152 ;
     RECT  11.699 1.728 12.149 1.752 ;
     RECT  10.621 13.104 12.179 14.808 ;
     RECT  12.149 1.728 12.233 2.28 ;
     RECT  11.737 3.936 12.284 6.216 ;
     RECT  12.179 13.104 12.325 14.568 ;
     RECT  12.337 0.528 12.755 0.552 ;
     RECT  12.035 38.16 12.769 38.952 ;
     RECT  12.089 21.12 13.052 22.056 ;
     RECT  12.233 1.728 13.091 1.752 ;
     RECT  12.284 3.84 13.093 6.216 ;
     RECT  12.401 2.832 13.208 2.856 ;
     RECT  13.093 3.84 13.208 6.264 ;
     RECT  12.325 12.528 13.208 14.568 ;
     RECT  13.052 21.12 13.208 22.104 ;
     RECT  12.769 38.16 13.208 39.096 ;
     RECT  11.285 40.992 13.208 41.016 ;
     RECT  13.208 2.016 13.312 41.052 ;
     RECT  13.312 2.016 13.504 41.016 ;
     RECT  13.285 42.144 13.529 42.168 ;
     RECT  13.504 4.224 13.619 5.928 ;
     RECT  13.504 12.528 13.645 14.568 ;
     RECT  13.504 21.12 13.673 22.248 ;
     RECT  13.504 2.016 13.811 2.52 ;
     RECT  13.811 2.016 14.101 2.28 ;
     RECT  13.504 40.752 14.177 41.016 ;
     RECT  13.673 21.168 14.357 22.248 ;
     RECT  13.619 4.224 14.429 4.536 ;
     RECT  13.504 38.4 14.569 39.096 ;
     RECT  13.619 5.568 14.677 5.928 ;
     RECT  14.177 40.752 14.741 40.776 ;
     RECT  14.677 5.568 14.761 6.264 ;
     RECT  14.429 4.512 14.785 4.536 ;
     RECT  14.761 5.568 14.785 5.928 ;
     RECT  14.741 40.56 14.825 40.776 ;
     RECT  14.785 4.512 14.915 5.928 ;
     RECT  14.915 4.512 14.963 5.736 ;
     RECT  13.645 12.528 14.969 14.424 ;
     RECT  14.569 37.872 15.061 39.096 ;
     RECT  15.061 37.488 15.148 39.096 ;
     RECT  14.357 21.408 15.293 22.248 ;
     RECT  15.148 37.872 15.293 39.096 ;
     RECT  15.293 21.648 15.545 22.248 ;
     RECT  14.969 12.576 15.829 14.424 ;
     RECT  14.101 1.728 15.923 2.28 ;
     RECT  14.963 5.184 15.973 5.736 ;
     RECT  15.829 12.576 16.021 14.808 ;
     RECT  15.973 4.512 16.124 5.736 ;
     RECT  16.021 12.528 16.201 14.808 ;
     RECT  16.124 3.936 16.211 5.736 ;
     RECT  15.293 37.872 16.333 38.424 ;
     RECT  16.333 37.008 16.373 38.712 ;
     RECT  16.211 4.512 16.589 5.736 ;
     RECT  16.201 12.528 16.669 14.232 ;
     RECT  16.441 42.816 16.835 42.84 ;
     RECT  15.923 1.728 16.933 1.752 ;
     RECT  16.501 3.168 16.979 3.432 ;
     RECT  16.373 38.016 16.981 38.712 ;
     RECT  16.933 1.728 16.985 1.8 ;
     RECT  16.985 1.776 17.057 1.8 ;
     RECT  16.981 38.016 17.065 39.384 ;
     RECT  16.979 3.168 17.197 3.192 ;
     RECT  15.545 21.648 17.221 22.152 ;
     RECT  17.197 1.824 17.315 3.192 ;
     RECT  16.589 5.088 17.341 5.736 ;
     RECT  17.315 2.832 17.561 3.192 ;
     RECT  16.373 37.008 17.633 37.032 ;
     RECT  17.341 5.088 17.9 6.072 ;
     RECT  16.669 12.528 17.989 14.136 ;
     RECT  17.749 43.056 17.993 43.08 ;
     RECT  17.561 3.168 18.061 3.192 ;
     RECT  17.9 4.848 18.061 6.072 ;
     RECT  17.315 1.824 18.097 1.848 ;
     RECT  15.301 40.992 18.277 41.016 ;
     RECT  18.061 3.168 18.313 6.072 ;
     RECT  17.065 38.016 18.469 38.808 ;
     RECT  18.097 1.728 18.608 1.848 ;
     RECT  18.313 3.168 18.608 6.312 ;
     RECT  17.989 12.528 18.608 14.232 ;
     RECT  17.221 21.12 18.608 22.152 ;
     RECT  18.469 38.016 18.608 39.336 ;
     RECT  18.277 40.56 18.608 41.016 ;
     RECT  18.608 1.728 18.737 41.052 ;
     RECT  18.737 1.728 18.821 41.16 ;
     RECT  18.821 1.728 18.904 41.016 ;
     RECT  18.904 13.056 19.045 14.04 ;
     RECT  18.904 1.728 19.091 3.624 ;
     RECT  18.904 38.16 19.289 41.016 ;
     RECT  18.904 5.088 19.405 6.216 ;
     RECT  19.091 2.256 19.477 3.624 ;
     RECT  19.045 13.68 19.613 14.04 ;
     RECT  18.904 20.544 19.613 21.96 ;
     RECT  19.405 5.136 19.763 6.216 ;
     RECT  19.613 14.016 19.859 14.04 ;
     RECT  19.477 3.408 19.909 3.624 ;
     RECT  19.289 38.16 20.005 40.872 ;
     RECT  20.005 37.584 20.051 40.872 ;
     RECT  19.909 3.408 20.396 4.008 ;
     RECT  19.763 5.136 20.396 6.072 ;
     RECT  19.477 2.256 20.429 2.328 ;
     RECT  20.051 39.504 20.441 40.872 ;
     RECT  20.429 1.728 20.753 2.328 ;
     RECT  20.396 3.408 20.915 6.072 ;
     RECT  20.773 40.944 21.089 40.968 ;
     RECT  20.915 3.408 21.341 6.024 ;
     RECT  19.868 0.048 21.347 0.072 ;
     RECT  20.441 39.504 21.485 39.528 ;
     RECT  20.753 1.728 21.548 2.376 ;
     RECT  21.341 3.408 21.548 3.432 ;
     RECT  19.613 20.544 21.557 21.768 ;
     RECT  21.548 1.728 21.635 3.432 ;
     RECT  21.253 41.568 21.665 41.592 ;
     RECT  21.635 1.728 21.683 2.28 ;
     RECT  21.697 42.768 21.781 42.792 ;
     RECT  21.341 4.56 21.971 6.024 ;
     RECT  21.635 3.408 22.025 3.432 ;
     RECT  20.051 37.584 22.453 38.424 ;
     RECT  22.261 40.416 22.529 40.44 ;
     RECT  22.453 37.584 22.741 38.76 ;
     RECT  22.597 4.416 22.781 4.44 ;
     RECT  23.221 40.992 23.749 41.016 ;
     RECT  22.741 37.44 23.965 38.76 ;
     RECT  21.683 1.728 24.008 1.752 ;
     RECT  23.569 4.128 24.008 4.152 ;
     RECT  21.971 5.472 24.008 6.024 ;
     RECT  21.925 13.344 24.008 13.368 ;
     RECT  21.557 21.12 24.008 21.768 ;
     RECT  23.965 37.44 24.008 39.24 ;
     RECT  23.749 40.704 24.008 41.016 ;
     RECT  24.008 1.728 24.209 41.052 ;
     RECT  24.209 1.728 24.293 41.16 ;
     RECT  24.293 1.728 24.304 41.016 ;
     RECT  24.304 1.728 24.419 4.152 ;
     RECT  24.304 38.16 24.437 39.768 ;
     RECT  24.419 2.832 24.467 4.152 ;
     RECT  24.304 5.136 24.481 6.024 ;
     RECT  24.437 38.16 25.297 38.76 ;
     RECT  24.481 5.184 25.427 6.024 ;
     RECT  25.297 38.112 25.436 38.76 ;
     RECT  24.437 39.744 25.436 39.768 ;
     RECT  24.419 1.728 25.445 1.848 ;
     RECT  25.436 38.112 25.523 39.768 ;
     RECT  24.467 3.744 25.945 4.152 ;
     RECT  25.427 5.184 25.945 5.88 ;
     RECT  25.945 3.744 25.985 5.88 ;
     RECT  24.304 13.344 26.129 13.368 ;
     RECT  25.985 4.128 26.309 5.88 ;
     RECT  26.305 13.632 26.389 13.656 ;
     RECT  25.523 38.112 26.665 38.76 ;
     RECT  26.197 42.144 26.741 42.168 ;
     RECT  26.665 37.584 26.993 38.76 ;
     RECT  26.309 4.656 27.059 5.88 ;
     RECT  25.523 39.744 27.065 39.768 ;
     RECT  24.304 40.992 27.197 41.016 ;
     RECT  27.059 4.656 27.277 5.832 ;
     RECT  26.993 37.584 27.589 38.712 ;
     RECT  27.589 37.008 27.635 38.712 ;
     RECT  27.635 37.008 27.677 37.032 ;
     RECT  27.277 4.56 27.731 5.832 ;
     RECT  27.731 4.56 27.745 5.208 ;
     RECT  27.197 40.944 27.889 41.016 ;
     RECT  27.889 40.8 28.001 41.016 ;
     RECT  25.445 1.728 28.033 1.752 ;
     RECT  28.033 1.728 28.163 2.28 ;
     RECT  27.635 38.112 28.537 38.712 ;
     RECT  28.537 38.112 28.892 39.528 ;
     RECT  28.892 38.016 28.897 39.528 ;
     RECT  27.745 3.984 28.969 5.208 ;
     RECT  28.969 3.984 29.221 5.496 ;
     RECT  28.897 38.016 29.221 40.008 ;
     RECT  28.001 40.992 29.221 41.016 ;
     RECT  28.163 1.728 29.408 1.752 ;
     RECT  29.221 3.984 29.408 6.072 ;
     RECT  24.304 21.12 29.408 21.768 ;
     RECT  29.221 38.016 29.408 41.016 ;
     RECT  29.408 1.728 29.437 41.052 ;
     RECT  29.437 1.728 29.704 41.64 ;
     RECT  29.704 21.12 30.089 21.768 ;
     RECT  29.704 40.992 30.089 41.64 ;
     RECT  30.089 21.216 30.305 21.768 ;
     RECT  29.704 38.16 30.449 38.712 ;
     RECT  29.704 5.472 30.629 6.168 ;
     RECT  30.089 40.992 30.689 41.016 ;
     RECT  30.689 40.464 30.773 41.016 ;
     RECT  29.704 4.416 30.841 4.44 ;
     RECT  30.449 38.16 31.021 38.184 ;
     RECT  31.021 38.016 31.525 38.184 ;
     RECT  31.676 3.36 31.763 3.384 ;
     RECT  30.841 4.416 32.069 4.68 ;
     RECT  30.773 40.992 32.165 41.016 ;
     RECT  29.704 37.008 32.204 37.032 ;
     RECT  31.525 38.016 32.204 38.952 ;
     RECT  32.069 4.464 32.249 4.68 ;
     RECT  32.165 40.992 32.249 41.592 ;
     RECT  32.204 37.008 32.291 38.952 ;
     RECT  32.425 0.096 32.531 0.12 ;
     RECT  32.389 3.456 32.537 3.48 ;
     RECT  32.249 4.56 32.713 4.68 ;
     RECT  32.713 4.56 33.221 5.064 ;
     RECT  32.291 38.016 33.257 38.952 ;
     RECT  33.257 38.544 33.361 38.952 ;
     RECT  29.704 1.728 33.508 1.752 ;
     RECT  32.249 40.992 33.545 41.016 ;
     RECT  32.749 3.36 33.613 3.384 ;
     RECT  33.221 4.56 33.613 4.776 ;
     RECT  33.508 1.728 33.617 1.8 ;
     RECT  33.685 42.144 34.085 42.168 ;
     RECT  32.291 37.008 34.165 37.032 ;
     RECT  34.165 37.008 34.261 37.464 ;
     RECT  33.361 38.544 34.261 39.24 ;
     RECT  33.613 3.36 34.369 4.776 ;
     RECT  33.617 1.728 34.613 1.752 ;
     RECT  34.613 1.728 34.808 1.848 ;
     RECT  34.369 3.36 34.808 5.064 ;
     RECT  30.629 6.144 34.808 6.168 ;
     RECT  30.305 21.264 34.808 21.768 ;
     RECT  34.261 37.008 34.808 39.24 ;
     RECT  34.645 40.56 34.808 40.584 ;
     RECT  34.808 1.728 34.912 41.052 ;
     RECT  34.912 1.728 35.104 41.016 ;
     RECT  35.104 38.16 35.267 41.016 ;
     RECT  35.267 38.4 35.309 41.016 ;
     RECT  35.309 38.4 35.453 38.712 ;
     RECT  35.309 40.08 35.561 40.488 ;
     RECT  35.104 4.128 35.891 6.168 ;
     RECT  35.104 2.832 36.109 2.856 ;
     RECT  35.891 4.128 36.109 5.16 ;
     RECT  35.104 1.728 36.46 1.752 ;
     RECT  35.104 36.912 36.493 37.032 ;
     RECT  35.453 38.544 36.493 38.712 ;
     RECT  36.133 42.144 36.497 42.168 ;
     RECT  35.561 40.368 36.62 40.488 ;
     RECT  36.109 4.128 36.661 4.824 ;
     RECT  36.493 36.912 36.661 38.712 ;
     RECT  36.62 40.272 36.661 40.488 ;
     RECT  36.46 1.728 36.673 1.8 ;
     RECT  36.661 40.272 36.707 41.016 ;
     RECT  36.673 1.728 36.851 2.28 ;
     RECT  36.851 1.728 36.893 1.8 ;
     RECT  36.661 36.912 36.925 39.096 ;
     RECT  36.707 40.992 37.037 41.016 ;
     RECT  36.661 3.408 37.177 4.824 ;
     RECT  37.177 3.408 37.189 5.16 ;
     RECT  37.141 43.056 37.361 43.08 ;
     RECT  36.62 0.048 37.475 0.072 ;
     RECT  37.189 2.832 37.477 5.16 ;
     RECT  35.891 6.144 37.477 6.168 ;
     RECT  37.477 2.832 37.649 6.168 ;
     RECT  37.649 3.408 37.676 6.168 ;
     RECT  37.676 3.408 37.763 6.216 ;
     RECT  36.925 36.912 38.017 39.912 ;
     RECT  38.017 38.208 38.045 39.912 ;
     RECT  38.017 36.912 38.089 37.08 ;
     RECT  36.893 1.728 38.581 1.752 ;
     RECT  38.149 40.992 38.629 41.016 ;
     RECT  38.581 1.728 38.675 1.848 ;
     RECT  38.045 38.208 38.765 39.48 ;
     RECT  38.629 40.464 38.765 41.016 ;
     RECT  38.765 39.072 39.409 39.48 ;
     RECT  38.089 36.912 39.481 37.032 ;
     RECT  37.763 3.408 39.661 6.168 ;
     RECT  39.661 3.12 39.836 6.168 ;
     RECT  39.481 36.912 39.877 37.512 ;
     RECT  39.409 39.072 39.877 39.624 ;
     RECT  38.675 1.728 40.117 1.752 ;
     RECT  39.836 2.736 40.117 6.168 ;
     RECT  38.765 40.992 40.117 41.016 ;
     RECT  40.117 40.992 40.205 41.16 ;
     RECT  40.117 1.728 40.208 6.168 ;
     RECT  35.104 21.744 40.208 21.768 ;
     RECT  39.877 36.912 40.208 39.624 ;
     RECT  40.205 40.992 40.208 41.052 ;
     RECT  40.208 1.728 40.312 41.052 ;
     RECT  40.312 1.728 40.504 41.016 ;
     RECT  40.504 36.912 40.601 39.624 ;
     RECT  40.504 3.36 40.643 6.072 ;
     RECT  40.504 40.992 40.997 41.016 ;
     RECT  40.504 1.728 41.027 2.28 ;
     RECT  40.643 3.408 41.429 6.072 ;
     RECT  40.601 37.008 41.753 39.624 ;
     RECT  41.429 3.408 41.893 6.024 ;
     RECT  41.027 1.728 41.939 1.752 ;
     RECT  41.893 3.36 42.041 6.024 ;
     RECT  41.125 43.056 42.113 43.08 ;
     RECT  41.965 0.096 42.323 0.12 ;
     RECT  41.753 37.008 42.757 38.808 ;
     RECT  42.613 40.848 42.761 40.872 ;
     RECT  42.757 36.912 42.793 38.808 ;
     RECT  42.793 36.912 42.905 38.904 ;
     RECT  42.577 2.256 42.997 2.28 ;
     RECT  42.905 36.912 43.661 38.808 ;
     RECT  43.661 38.688 43.945 38.808 ;
     RECT  43.945 38.688 44.233 38.952 ;
     RECT  42.997 1.728 44.3 2.28 ;
     RECT  42.041 3.6 44.3 6.024 ;
     RECT  44.3 1.728 44.387 6.024 ;
     RECT  44.387 1.728 44.483 2.28 ;
     RECT  44.125 14.016 44.485 14.04 ;
     RECT  44.413 0.096 44.497 0.12 ;
     RECT  44.387 3.408 44.531 6.024 ;
     RECT  44.485 13.68 44.569 14.04 ;
     RECT  44.531 3.408 44.597 5.592 ;
     RECT  43.661 36.912 44.629 37.608 ;
     RECT  44.233 38.688 44.629 39.144 ;
     RECT  44.629 36.912 44.773 39.144 ;
     RECT  40.504 21.744 45.253 21.768 ;
     RECT  45.493 11.52 45.601 11.544 ;
     RECT  44.483 1.728 45.608 2.232 ;
     RECT  44.597 3.456 45.608 5.592 ;
     RECT  45.601 11.424 45.608 11.544 ;
     RECT  44.569 14.016 45.608 14.04 ;
     RECT  45.253 21.12 45.608 21.768 ;
     RECT  45.493 25.104 45.608 25.128 ;
     RECT  44.773 36.912 45.608 40.008 ;
     RECT  43.073 40.992 45.608 41.016 ;
     RECT  45.608 1.728 45.712 41.052 ;
     RECT  45.589 43.056 45.857 43.08 ;
     RECT  45.712 1.728 45.904 41.016 ;
     RECT  45.904 25.392 46.019 25.416 ;
     RECT  45.904 36.912 46.019 39.384 ;
     RECT  45.904 11.52 46.037 12.408 ;
     RECT  45.904 3.552 46.081 5.832 ;
     RECT  46.019 37.152 46.109 39.384 ;
     RECT  46.037 12.384 46.355 12.408 ;
     RECT  45.904 40.464 46.397 41.016 ;
     RECT  46.081 3.792 47.077 5.832 ;
     RECT  45.904 34.128 47.077 34.152 ;
     RECT  45.904 1.728 47.084 1.752 ;
     RECT  47.077 3.408 47.084 5.832 ;
     RECT  45.904 21.504 47.149 21.768 ;
     RECT  46.109 37.152 47.185 38.136 ;
     RECT  46.109 39.264 47.185 39.384 ;
     RECT  47.18 0.048 47.267 0.072 ;
     RECT  47.185 37.152 47.477 39.384 ;
     RECT  47.149 21.504 47.513 22.008 ;
     RECT  46.397 40.992 47.873 41.016 ;
     RECT  48.409 0.096 48.515 0.12 ;
     RECT  48.565 42.144 48.845 42.168 ;
     RECT  47.477 37.152 48.949 38.424 ;
     RECT  48.949 37.152 49.021 38.808 ;
     RECT  49.021 37.152 49.313 39.384 ;
     RECT  48.085 40.464 49.601 40.488 ;
     RECT  45.904 35.712 49.813 35.736 ;
     RECT  49.313 37.152 50.425 38.376 ;
     RECT  49.313 39.36 50.425 39.384 ;
     RECT  50.425 37.152 50.677 39.384 ;
     RECT  50.053 40.56 50.677 40.584 ;
     RECT  49.813 35.28 50.869 35.736 ;
     RECT  47.084 1.728 51.008 5.832 ;
     RECT  47.513 21.744 51.008 22.008 ;
     RECT  47.077 33.552 51.008 34.152 ;
     RECT  50.869 35.28 51.008 36.072 ;
     RECT  50.677 37.152 51.008 40.584 ;
     RECT  49.573 43.056 51.107 43.08 ;
     RECT  51.008 1.728 51.112 41.052 ;
     RECT  51.112 1.728 51.304 41.016 ;
     RECT  51.304 1.728 51.329 5.832 ;
     RECT  51.304 39.504 51.761 41.016 ;
     RECT  51.5 0.048 51.971 0.072 ;
     RECT  51.304 35.712 52.259 38.28 ;
     RECT  52.259 37.056 52.301 38.28 ;
     RECT  52.301 37.152 52.405 38.28 ;
     RECT  52.189 0.096 52.499 0.12 ;
     RECT  52.405 37.152 52.909 38.376 ;
     RECT  51.761 39.504 52.909 39.528 ;
     RECT  51.329 1.728 52.933 2.28 ;
     RECT  51.329 3.408 52.933 5.832 ;
     RECT  51.761 40.992 53.021 41.016 ;
     RECT  52.069 42.144 53.309 42.168 ;
     RECT  52.259 35.712 53.341 36.072 ;
     RECT  53.341 35.472 53.365 36.072 ;
     RECT  52.94 0.048 53.459 0.072 ;
     RECT  53.365 35.472 53.489 36.12 ;
     RECT  53.557 43.056 53.813 43.08 ;
     RECT  53.489 35.712 54.097 36.12 ;
     RECT  52.909 37.152 54.097 39.528 ;
     RECT  54.053 0.528 54.137 0.552 ;
     RECT  54.037 40.992 54.137 41.016 ;
     RECT  54.517 40.848 54.713 40.872 ;
     RECT  54.097 35.712 54.889 39.528 ;
     RECT  52.933 1.728 54.929 5.832 ;
     RECT  54.889 35.712 55.091 40.488 ;
     RECT  54.929 1.728 55.283 2.28 ;
     RECT  55.501 42.144 55.585 42.168 ;
     RECT  55.868 0.048 55.955 0.072 ;
     RECT  56.185 7.68 56.293 7.704 ;
     RECT  55.283 1.728 56.408 1.752 ;
     RECT  54.929 3.312 56.408 5.832 ;
     RECT  56.293 7.68 56.408 7.752 ;
     RECT  51.304 21.744 56.408 22.008 ;
     RECT  51.304 33.552 56.408 34.152 ;
     RECT  55.091 35.712 56.408 39.528 ;
     RECT  56.005 40.992 56.408 41.016 ;
     RECT  56.408 1.728 56.501 41.052 ;
     RECT  56.501 1.728 56.585 41.208 ;
     RECT  56.585 1.728 56.704 40.782 ;
     RECT  56.704 1.728 57.203 5.88 ;
     RECT  57.013 43.056 57.305 43.08 ;
     RECT  56.704 40.464 57.587 40.488 ;
     RECT  57.203 2.736 58.412 5.88 ;
     RECT  58.412 2.736 58.499 6.264 ;
     RECT  57.203 1.728 58.6 1.752 ;
     RECT  58.499 2.736 58.6 5.88 ;
     RECT  56.704 37.152 58.637 39.48 ;
     RECT  57.805 40.944 58.705 40.968 ;
     RECT  58.6 1.728 58.709 5.88 ;
     RECT  58.501 43.056 58.709 43.08 ;
     RECT  58.705 40.56 58.817 40.968 ;
     RECT  59.021 40.992 59.645 41.016 ;
     RECT  58.709 1.728 60.325 1.752 ;
     RECT  58.709 2.736 60.325 5.88 ;
     RECT  60.325 1.728 60.419 5.88 ;
     RECT  60.389 0.576 60.473 0.6 ;
     RECT  59.989 42.144 60.833 42.168 ;
     RECT  58.637 37.392 61.189 39.48 ;
     RECT  60.419 2.736 61.297 5.88 ;
     RECT  58.669 7.056 61.297 7.08 ;
     RECT  61.189 37.392 61.58 39.672 ;
     RECT  61.477 40.992 61.58 41.016 ;
     RECT  60.419 1.728 61.808 1.752 ;
     RECT  61.297 2.736 61.808 7.08 ;
     RECT  56.704 21.744 61.808 22.008 ;
     RECT  56.704 33.552 61.808 34.152 ;
     RECT  56.704 35.712 61.808 36.12 ;
     RECT  61.58 37.392 61.808 41.016 ;
     RECT  61.808 1.728 61.973 41.052 ;
     RECT  61.973 1.728 62.104 41.16 ;
     RECT  62.377 41.616 62.531 41.64 ;
     RECT  62.104 35.712 63.107 39.528 ;
     RECT  63.107 37.392 63.133 39.528 ;
     RECT  62.104 33.552 63.173 34.152 ;
     RECT  62.965 43.056 63.245 43.08 ;
     RECT  63.133 37.392 63.421 40.296 ;
     RECT  63.421 37.392 63.539 40.488 ;
     RECT  63.539 37.392 63.677 40.296 ;
     RECT  63.677 37.392 63.713 39.816 ;
     RECT  63.173 33.552 63.893 33.576 ;
     RECT  63.107 35.712 64.037 36.12 ;
     RECT  62.104 1.728 64.645 1.752 ;
     RECT  62.104 2.736 64.645 7.08 ;
     RECT  63.973 42.144 65.297 42.168 ;
     RECT  63.713 37.392 65.437 39.384 ;
     RECT  64.645 1.728 65.555 7.08 ;
     RECT  66.941 42.144 67.025 42.168 ;
     RECT  65.555 1.728 67.129 1.752 ;
     RECT  67.129 1.104 67.208 1.752 ;
     RECT  65.555 2.736 67.208 7.08 ;
     RECT  62.104 21.744 67.208 22.008 ;
     RECT  64.037 36.048 67.208 36.12 ;
     RECT  65.437 37.392 67.208 39.624 ;
     RECT  65.461 40.992 67.208 41.016 ;
     RECT  67.208 1.104 67.312 41.052 ;
     RECT  67.312 1.104 67.379 40.782 ;
     RECT  67.379 1.728 67.504 40.782 ;
     RECT  67.504 36.048 67.619 40.344 ;
     RECT  67.477 43.056 67.745 43.08 ;
     RECT  67.504 1.728 68.425 1.752 ;
     RECT  68.425 1.152 68.509 1.752 ;
     RECT  67.619 36.048 68.645 39.768 ;
     RECT  68.437 42.144 68.645 42.168 ;
     RECT  69.469 0.528 69.587 0.552 ;
     RECT  68.965 40.992 69.761 41.016 ;
     RECT  68.645 36.048 70.157 39.384 ;
     RECT  70.157 36.096 70.729 39.384 ;
     RECT  70.729 0.096 70.813 0.12 ;
     RECT  70.729 36.096 71.953 39.432 ;
     RECT  71.953 36.096 72.385 39.528 ;
     RECT  70.933 42.144 72.533 42.168 ;
     RECT  68.509 1.728 72.608 1.752 ;
     RECT  67.504 2.736 72.608 7.08 ;
     RECT  67.504 21.744 72.608 22.008 ;
     RECT  72.385 36.096 72.608 39.624 ;
     RECT  71.413 40.992 72.608 41.016 ;
     RECT  72.608 1.728 72.881 41.052 ;
     RECT  72.881 1.728 72.904 41.16 ;
     RECT  72.904 40.992 72.965 41.16 ;
     RECT  72.904 36.096 73.433 39.528 ;
     RECT  73.189 0.528 73.829 0.552 ;
     RECT  73.433 36.096 74.051 36.168 ;
     RECT  74.051 36.096 74.153 36.12 ;
     RECT  73.433 37.392 74.389 39.528 ;
     RECT  72.965 40.992 74.389 41.016 ;
     RECT  72.904 1.728 74.477 7.08 ;
     RECT  74.389 37.392 74.621 41.016 ;
     RECT  74.761 12.864 74.873 12.888 ;
     RECT  74.477 2.256 75.443 7.08 ;
     RECT  74.621 37.392 75.521 39.672 ;
     RECT  75.521 37.392 75.805 39.384 ;
     RECT  75.805 37.008 76.021 39.384 ;
     RECT  76.021 36.864 76.277 39.384 ;
     RECT  75.397 42.144 76.817 42.168 ;
     RECT  76.277 37.008 77.276 39.384 ;
     RECT  74.621 40.992 77.381 41.016 ;
     RECT  77.276 37.008 77.525 39.72 ;
     RECT  77.569 42.192 77.939 42.216 ;
     RECT  75.769 1.728 78.008 1.752 ;
     RECT  75.443 2.736 78.008 7.08 ;
     RECT  72.904 21.744 78.008 22.008 ;
     RECT  77.525 37.008 78.008 39.912 ;
     RECT  77.381 40.944 78.008 41.016 ;
     RECT  78.008 1.728 78.112 41.052 ;
     RECT  78.112 1.728 78.304 40.782 ;
     RECT  78.304 37.104 78.365 40.584 ;
     RECT  78.365 37.2 79.229 40.584 ;
     RECT  79.229 37.2 79.265 39.048 ;
     RECT  79.265 37.296 79.373 39.048 ;
     RECT  79.229 40.56 79.373 40.584 ;
     RECT  79.373 37.296 80.269 38.808 ;
     RECT  80.269 37.008 80.561 38.808 ;
     RECT  78.304 1.728 80.821 1.752 ;
     RECT  78.304 2.736 80.821 7.08 ;
     RECT  79.381 42.144 80.885 42.168 ;
     RECT  80.233 39.888 81.065 39.912 ;
     RECT  80.561 37.008 81.353 38.04 ;
     RECT  80.837 40.992 81.425 41.016 ;
     RECT  81.313 39.36 81.461 39.384 ;
     RECT  81.353 37.584 81.637 38.04 ;
     RECT  81.637 37.584 81.733 38.328 ;
     RECT  78.304 21.744 82.073 22.008 ;
     RECT  81.733 37.584 82.213 38.376 ;
     RECT  82.213 37.584 82.433 39.192 ;
     RECT  82.433 38.304 82.789 39.192 ;
     RECT  81.877 40.464 82.789 40.824 ;
     RECT  82.789 38.304 82.837 40.824 ;
     RECT  80.821 1.728 83.045 7.08 ;
     RECT  82.501 0.096 83.363 0.12 ;
     RECT  82.837 38.304 83.365 41.016 ;
     RECT  83.045 2.016 83.408 7.08 ;
     RECT  82.073 21.984 83.408 22.008 ;
     RECT  83.365 38.304 83.408 41.208 ;
     RECT  83.408 2.016 83.585 41.208 ;
     RECT  83.585 2.016 83.704 41.064 ;
     RECT  83.704 2.016 84.037 7.08 ;
     RECT  83.704 38.16 84.197 38.76 ;
     RECT  83.704 41.04 84.305 41.064 ;
     RECT  84.373 42.144 84.485 42.168 ;
     RECT  84.833 40.848 84.917 40.872 ;
     RECT  83.704 36.432 84.985 36.456 ;
     RECT  84.985 36.432 85.169 36.792 ;
     RECT  85.169 36.624 85.453 36.792 ;
     RECT  84.197 38.16 85.453 38.424 ;
     RECT  85.445 0.576 85.529 0.6 ;
     RECT  84.037 1.728 85.961 7.08 ;
     RECT  85.301 40.992 86.429 41.016 ;
     RECT  85.453 36.624 86.749 38.424 ;
     RECT  85.961 2.832 86.789 7.08 ;
     RECT  86.789 2.832 86.825 6.792 ;
     RECT  86.825 2.832 87.149 6.696 ;
     RECT  86.749 36.624 87.155 38.712 ;
     RECT  87.155 36.624 87.221 36.648 ;
     RECT  87.155 37.968 88.117 38.712 ;
     RECT  86.821 42.144 88.193 42.168 ;
     RECT  88.117 37.968 88.441 39.528 ;
     RECT  88.268 40.992 88.729 41.016 ;
     RECT  85.961 1.728 88.808 1.752 ;
     RECT  87.149 2.832 88.808 6.648 ;
     RECT  83.704 21.984 88.808 22.008 ;
     RECT  88.441 37.92 88.808 39.528 ;
     RECT  88.729 40.992 88.808 41.208 ;
     RECT  88.808 1.728 88.883 41.208 ;
     RECT  88.883 1.728 89.104 41.064 ;
     RECT  89.104 36.336 89.273 39.528 ;
     RECT  89.104 40.992 89.843 41.064 ;
     RECT  89.273 36.336 90.083 36.408 ;
     RECT  89.104 2.88 90.241 6.648 ;
     RECT  89.273 37.44 90.277 39.528 ;
     RECT  90.277 36.528 90.325 39.528 ;
     RECT  90.325 36.528 90.353 40.488 ;
     RECT  89.104 1.728 90.517 1.752 ;
     RECT  90.517 1.728 90.605 1.848 ;
     RECT  90.353 40.464 90.641 40.488 ;
     RECT  90.745 41.568 90.851 41.592 ;
     RECT  90.353 36.528 91.145 39.384 ;
     RECT  90.241 2.88 91.501 6.84 ;
     RECT  91.501 2.88 91.613 6.984 ;
     RECT  91.285 40.704 91.649 40.728 ;
     RECT  91.145 36.768 91.865 39.384 ;
     RECT  91.865 36.768 92.081 39.24 ;
     RECT  90.605 1.728 92.149 1.752 ;
     RECT  91.613 2.88 92.149 6.84 ;
     RECT  91.285 42.144 92.225 42.168 ;
     RECT  92.252 40.848 92.339 40.872 ;
     RECT  92.081 37.296 92.905 39.24 ;
     RECT  92.149 1.728 93.197 6.84 ;
     RECT  93.197 2.784 93.229 6.84 ;
     RECT  92.905 37.296 93.661 39.768 ;
     RECT  93.197 1.728 94.201 1.752 ;
     RECT  93.229 2.784 94.201 6.888 ;
     RECT  94.201 1.728 94.208 6.888 ;
     RECT  89.104 21.984 94.208 22.008 ;
     RECT  93.661 36.816 94.208 39.768 ;
     RECT  92.821 40.944 94.208 41.016 ;
     RECT  94.301 42.144 94.385 42.168 ;
     RECT  94.208 1.728 94.504 41.052 ;
     RECT  94.504 40.992 94.777 41.052 ;
     RECT  94.777 40.992 94.861 41.592 ;
     RECT  94.504 36.816 95.537 38.904 ;
     RECT  94.504 2.88 95.747 6.888 ;
     RECT  94.504 1.728 95.857 1.752 ;
     RECT  95.747 2.88 95.857 6.84 ;
     RECT  95.537 37.056 95.857 38.904 ;
     RECT  94.861 40.992 96.217 41.016 ;
     RECT  95.857 1.728 96.401 6.84 ;
     RECT  96.217 40.464 96.437 41.016 ;
     RECT  95.857 37.056 96.577 39.336 ;
     RECT  96.437 40.464 96.577 40.728 ;
     RECT  96.577 37.056 96.653 40.728 ;
     RECT  96.653 37.296 96.803 40.728 ;
     RECT  96.401 1.728 96.973 1.8 ;
     RECT  96.973 1.152 97.157 1.8 ;
     RECT  96.401 2.88 97.229 6.84 ;
     RECT  97.157 1.152 97.379 1.752 ;
     RECT  97.285 42.144 97.481 42.168 ;
     RECT  97.229 3.168 97.657 6.84 ;
     RECT  96.803 37.296 97.661 39.624 ;
     RECT  96.803 40.704 97.765 40.728 ;
     RECT  97.657 3.168 98.051 6.888 ;
     RECT  97.765 40.704 98.129 40.824 ;
     RECT  97.661 39.6 98.237 39.624 ;
     RECT  97.379 1.728 98.405 1.752 ;
     RECT  98.405 1.728 98.489 1.8 ;
     RECT  97.661 37.296 98.737 38.424 ;
     RECT  98.051 3.168 99.097 6.84 ;
     RECT  98.489 1.728 99.157 1.752 ;
     RECT  99.157 1.2 99.245 1.752 ;
     RECT  99.253 41.568 99.425 41.592 ;
     RECT  99.245 1.728 99.608 1.752 ;
     RECT  99.097 3.168 99.608 7.416 ;
     RECT  94.504 21.984 99.608 22.008 ;
     RECT  98.737 37.296 99.608 38.808 ;
     RECT  98.245 39.84 99.608 40.488 ;
     RECT  99.608 1.728 99.712 41.052 ;
     RECT  99.712 1.728 99.904 41.016 ;
     RECT  99.877 0.096 100.019 0.12 ;
     RECT  99.904 37.344 100.019 38.76 ;
     RECT  98.773 43.056 100.019 43.08 ;
     RECT  99.904 3.168 100.073 7.416 ;
     RECT  99.904 40.032 100.181 41.016 ;
     RECT  100.181 40.416 100.253 41.016 ;
     RECT  99.904 21.12 100.801 22.008 ;
     RECT  100.019 37.392 100.901 38.76 ;
     RECT  100.901 38.736 100.969 38.76 ;
     RECT  100.969 38.736 101.009 39.24 ;
     RECT  101.009 38.976 101.261 39.24 ;
     RECT  100.901 37.392 101.365 37.416 ;
     RECT  101.261 39.216 101.545 39.24 ;
     RECT  99.904 1.728 101.725 1.752 ;
     RECT  101.725 1.728 102.035 1.848 ;
     RECT  101.365 37.296 102.157 37.416 ;
     RECT  102.229 42.144 102.313 42.168 ;
     RECT  102.157 37.296 102.325 38.136 ;
     RECT  101.545 39.216 102.325 39.336 ;
     RECT  100.073 3.168 102.553 6.84 ;
     RECT  102.553 3.12 102.665 6.84 ;
     RECT  102.325 37.296 103.021 39.336 ;
     RECT  100.801 21.984 103.489 22.008 ;
     RECT  100.253 40.992 103.673 41.016 ;
     RECT  102.665 3.168 103.765 6.84 ;
     RECT  103.765 2.832 103.853 6.84 ;
     RECT  103.021 37.296 103.853 39.624 ;
     RECT  103.717 42.144 103.957 42.168 ;
     RECT  103.957 42.144 104.285 42.216 ;
     RECT  104.285 42.192 104.291 42.216 ;
     RECT  102.035 1.728 104.933 1.752 ;
     RECT  103.853 37.296 104.965 37.32 ;
     RECT  103.853 38.784 104.965 39.624 ;
     RECT  103.853 3.168 105.008 6.84 ;
     RECT  103.489 21.12 105.008 22.008 ;
     RECT  104.965 37.296 105.008 39.624 ;
     RECT  104.725 40.992 105.008 41.016 ;
     RECT  105.008 2.148 105.304 41.052 ;
     RECT  105.253 0.096 105.443 0.12 ;
     RECT  105.733 41.616 105.869 41.64 ;
     RECT  105.304 2.148 105.973 6.84 ;
     RECT  105.304 37.296 106.157 39.864 ;
     RECT  105.304 21.12 106.165 22.008 ;
     RECT  105.205 43.056 106.373 43.08 ;
     RECT  105.973 1.728 106.633 6.84 ;
     RECT  106.157 37.296 107.021 39.624 ;
     RECT  106.633 1.728 107.075 1.8 ;
     RECT  106.693 42.144 107.093 42.168 ;
     RECT  107.221 41.616 107.525 41.64 ;
     RECT  106.165 21.984 107.593 22.008 ;
     RECT  107.593 21.12 107.699 22.008 ;
     RECT  106.633 3.168 107.701 6.84 ;
     RECT  107.075 1.728 108.133 1.752 ;
     RECT  107.701 2.832 108.133 6.84 ;
     RECT  107.341 39.744 108.181 39.768 ;
     RECT  107.021 37.296 108.313 38.664 ;
     RECT  108.181 39.744 108.313 39.912 ;
     RECT  108.133 1.728 108.533 6.84 ;
     RECT  107.699 21.648 108.709 22.008 ;
     RECT  108.313 37.296 108.785 39.912 ;
     RECT  108.709 21.12 108.793 22.008 ;
     RECT  108.785 37.296 108.857 39.768 ;
     RECT  108.817 0.096 108.901 0.12 ;
     RECT  107.665 40.992 109.433 41.016 ;
     RECT  108.533 2.112 109.565 6.84 ;
     RECT  109.349 0.528 109.793 0.552 ;
     RECT  108.793 21.984 109.861 22.008 ;
     RECT  109.669 41.568 109.901 41.592 ;
     RECT  109.565 1.728 109.955 6.84 ;
     RECT  108.857 37.296 110.005 38.664 ;
     RECT  108.857 39.744 110.005 39.768 ;
     RECT  110.197 42.144 110.369 42.168 ;
     RECT  109.955 2.148 110.408 6.84 ;
     RECT  109.861 21.12 110.408 22.008 ;
     RECT  110.005 37.296 110.408 39.768 ;
     RECT  110.408 2.148 110.512 41.052 ;
     RECT  110.512 2.148 110.704 41.016 ;
     RECT  110.677 43.056 110.819 43.08 ;
     RECT  110.113 0.048 110.833 0.12 ;
     RECT  110.704 38.736 110.837 41.016 ;
     RECT  110.837 38.736 110.873 39.768 ;
     RECT  110.704 2.148 110.977 6.12 ;
     RECT  110.833 0.048 111.251 0.168 ;
     RECT  110.977 1.728 111.299 6.12 ;
     RECT  110.837 40.944 111.377 41.016 ;
     RECT  111.251 0.144 111.491 0.168 ;
     RECT  110.873 38.736 111.593 39.192 ;
     RECT  111.299 1.728 111.809 2.856 ;
     RECT  110.704 37.296 111.913 37.32 ;
     RECT  111.913 37.296 112.817 38.184 ;
     RECT  111.377 40.992 113.173 41.016 ;
     RECT  113.173 40.464 113.465 41.016 ;
     RECT  111.593 39.168 113.753 39.192 ;
     RECT  112.817 37.296 113.804 37.32 ;
     RECT  113.804 37.008 113.891 37.32 ;
     RECT  111.809 1.728 113.969 1.752 ;
     RECT  111.809 2.832 113.996 2.856 ;
     RECT  111.299 3.84 113.996 6.12 ;
     RECT  113.465 40.464 114.005 40.632 ;
     RECT  113.996 0.048 114.083 0.072 ;
     RECT  113.996 2.832 114.109 6.12 ;
     RECT  114.005 40.608 114.149 40.632 ;
     RECT  110.704 21.984 114.649 22.008 ;
     RECT  114.181 43.056 114.661 43.08 ;
     RECT  114.649 21.12 114.733 22.008 ;
     RECT  114.661 42.144 114.941 43.08 ;
     RECT  114.109 2.256 114.949 6.12 ;
     RECT  113.845 38.64 115.153 38.808 ;
     RECT  115.073 0.528 115.157 0.552 ;
     RECT  114.941 43.056 115.517 43.08 ;
     RECT  113.891 37.296 115.549 37.32 ;
     RECT  115.153 38.64 115.549 39.768 ;
     RECT  114.949 1.728 115.808 6.12 ;
     RECT  114.733 21.984 115.808 22.008 ;
     RECT  115.549 37.296 115.808 39.768 ;
     RECT  115.628 40.992 115.808 41.016 ;
     RECT  115.808 1.728 116.104 41.052 ;
     RECT  116.104 39.552 116.149 41.052 ;
     RECT  116.104 37.296 116.243 38.376 ;
     RECT  116.149 39.552 116.345 41.16 ;
     RECT  116.345 39.552 116.705 41.016 ;
     RECT  116.104 2.832 116.813 5.592 ;
     RECT  117.02 0.048 117.107 0.072 ;
     RECT  116.813 2.88 117.109 5.592 ;
     RECT  116.104 21.12 117.173 22.008 ;
     RECT  116.705 40.224 117.353 41.016 ;
     RECT  116.243 37.296 117.709 38.232 ;
     RECT  117.709 37.296 117.745 38.76 ;
     RECT  117.173 21.12 117.865 21.144 ;
     RECT  116.104 1.728 117.889 1.752 ;
     RECT  117.889 1.104 117.925 1.752 ;
     RECT  117.109 3.408 117.971 5.592 ;
     RECT  117.925 1.104 118.019 2.28 ;
     RECT  118.019 1.728 118.037 2.28 ;
     RECT  117.745 37.296 118.177 39.24 ;
     RECT  118.177 37.296 118.505 39.528 ;
     RECT  117.353 40.848 118.577 41.016 ;
     RECT  117.971 3.744 118.933 5.592 ;
     RECT  118.933 3.36 118.969 5.592 ;
     RECT  119.125 42.144 119.369 42.168 ;
     RECT  118.681 22.176 119.651 22.2 ;
     RECT  119.581 26.208 119.665 26.76 ;
     RECT  118.037 1.728 119.797 1.752 ;
     RECT  118.969 2.832 119.797 5.592 ;
     RECT  119.365 14.016 120.053 14.04 ;
     RECT  118.505 39.456 120.085 39.528 ;
     RECT  118.577 40.992 120.085 41.016 ;
     RECT  119.689 21.696 120.121 21.72 ;
     RECT  120.085 39.456 120.179 41.016 ;
     RECT  119.797 1.728 120.565 5.592 ;
     RECT  118.505 37.296 120.565 38.472 ;
     RECT  120.179 39.456 120.565 39.48 ;
     RECT  120.179 40.56 121.121 41.016 ;
     RECT  121.121 40.56 121.205 41.208 ;
     RECT  120.565 1.728 121.208 5.784 ;
     RECT  120.121 21.12 121.208 21.72 ;
     RECT  119.665 26.736 121.208 26.76 ;
     RECT  120.565 37.296 121.208 39.48 ;
     RECT  121.205 40.56 121.208 41.052 ;
     RECT  121.208 1.728 121.312 41.052 ;
     RECT  121.312 1.728 121.504 40.782 ;
     RECT  121.504 13.68 121.645 13.704 ;
     RECT  121.504 40.56 121.673 40.584 ;
     RECT  121.504 2.832 121.753 5.784 ;
     RECT  121.753 3.408 121.852 5.784 ;
     RECT  121.852 3.456 121.933 5.784 ;
     RECT  121.621 42.144 121.997 42.168 ;
     RECT  121.861 0.528 122.213 0.552 ;
     RECT  122.101 42.192 122.357 42.216 ;
     RECT  121.504 21.648 122.857 21.72 ;
     RECT  122.629 40.992 122.897 41.016 ;
     RECT  121.933 3.84 122.917 5.784 ;
     RECT  121.504 1.728 122.929 1.752 ;
     RECT  122.929 1.728 122.965 2.28 ;
     RECT  122.917 3.408 122.965 5.784 ;
     RECT  122.965 1.728 123.005 5.784 ;
     RECT  123.005 1.728 123.049 2.856 ;
     RECT  122.857 21.12 123.059 21.72 ;
     RECT  123.049 1.728 123.107 2.28 ;
     RECT  123.109 42.144 123.617 42.168 ;
     RECT  123.289 41.04 123.635 41.064 ;
     RECT  123.059 21.12 123.877 21.144 ;
     RECT  121.504 37.584 124.045 39.528 ;
     RECT  123.005 3.84 124.069 5.784 ;
     RECT  123.107 1.728 124.124 1.752 ;
     RECT  124.045 37.584 124.157 40.488 ;
     RECT  124.157 39.504 124.163 40.488 ;
     RECT  124.124 1.728 124.549 2.28 ;
     RECT  124.069 3.312 124.549 5.784 ;
     RECT  124.157 37.584 124.693 38.424 ;
     RECT  124.652 0.048 124.739 0.072 ;
     RECT  124.693 36.96 124.78 38.424 ;
     RECT  124.597 40.992 124.841 41.016 ;
     RECT  124.801 0.096 124.931 0.12 ;
     RECT  124.549 1.728 124.949 5.784 ;
     RECT  124.949 1.728 124.979 2.712 ;
     RECT  124.163 39.504 125.273 39.528 ;
     RECT  124.949 3.984 125.917 5.784 ;
     RECT  125.605 40.8 126.085 40.824 ;
     RECT  124.979 1.728 126.608 2.28 ;
     RECT  125.917 3.648 126.608 5.784 ;
     RECT  124.78 37.344 126.608 38.424 ;
     RECT  126.085 40.464 126.608 40.824 ;
     RECT  126.608 1.728 126.712 41.052 ;
     RECT  126.565 43.056 126.821 43.08 ;
     RECT  126.712 1.728 126.904 41.016 ;
     RECT  126.904 37.344 127.145 39.384 ;
     RECT  127.145 37.488 127.187 39.384 ;
     RECT  126.904 1.728 127.475 5.784 ;
     RECT  127.58 0.048 128.051 0.072 ;
     RECT  127.475 2.304 128.533 5.784 ;
     RECT  126.904 40.992 128.581 41.016 ;
     RECT  128.581 40.992 128.729 41.592 ;
     RECT  128.533 1.728 128.771 5.784 ;
     RECT  128.771 3.408 128.837 5.784 ;
     RECT  128.771 1.728 128.915 2.28 ;
     RECT  127.187 38.16 128.972 39.384 ;
     RECT  128.972 37.584 129.059 39.384 ;
     RECT  128.837 3.648 129.161 5.784 ;
     RECT  128.729 40.992 130.021 41.016 ;
     RECT  129.059 38.112 130.349 39.384 ;
     RECT  130.021 40.704 130.381 41.016 ;
     RECT  130.069 42.144 130.421 42.168 ;
     RECT  130.381 39.84 130.709 41.016 ;
     RECT  130.349 38.112 130.741 38.424 ;
     RECT  129.161 3.936 131.077 5.784 ;
     RECT  131.057 0.096 131.141 0.12 ;
     RECT  128.915 1.728 131.281 1.752 ;
     RECT  131.077 43.056 131.357 43.08 ;
     RECT  130.709 39.84 131.569 39.864 ;
     RECT  131.281 1.728 131.749 2.28 ;
     RECT  131.077 3.696 131.749 5.784 ;
     RECT  131.569 39.6 131.821 39.864 ;
     RECT  130.709 40.992 131.821 41.016 ;
     RECT  130.741 37.632 131.852 38.424 ;
     RECT  131.821 39.6 131.852 41.016 ;
     RECT  131.852 37.632 131.893 41.016 ;
     RECT  131.749 1.728 132.008 5.784 ;
     RECT  131.893 37.632 132.008 41.208 ;
     RECT  132.008 1.728 132.083 41.208 ;
     RECT  132.083 1.728 132.112 41.052 ;
     RECT  131.845 0.144 132.179 0.168 ;
     RECT  132.112 1.728 132.304 41.016 ;
     RECT  132.304 37.632 132.689 39.624 ;
     RECT  132.689 38.16 132.833 39.624 ;
     RECT  132.833 38.208 132.977 39.624 ;
     RECT  132.304 40.944 133.013 41.016 ;
     RECT  133.013 40.944 133.373 40.968 ;
     RECT  132.304 1.728 133.379 2.28 ;
     RECT  132.304 3.408 133.481 5.784 ;
     RECT  132.977 38.208 134.197 39.576 ;
     RECT  134.156 0.048 134.243 0.072 ;
     RECT  134.053 43.056 134.273 43.08 ;
     RECT  133.379 1.728 134.341 1.752 ;
     RECT  134.341 1.728 134.345 1.8 ;
     RECT  134.345 1.776 134.377 1.8 ;
     RECT  134.377 1.776 134.525 2.28 ;
     RECT  134.525 2.256 134.629 2.28 ;
     RECT  133.481 3.408 134.629 5.592 ;
     RECT  134.629 2.256 134.713 5.592 ;
     RECT  134.449 0.096 134.723 0.12 ;
     RECT  134.197 38.208 134.741 39.72 ;
     RECT  134.533 41.616 134.921 41.64 ;
     RECT  134.713 3.408 134.993 5.592 ;
     RECT  134.741 39.696 135.029 39.72 ;
     RECT  134.981 40.992 135.065 41.016 ;
     RECT  134.713 2.256 135.107 2.28 ;
     RECT  134.993 3.408 135.317 5.208 ;
     RECT  135.385 1.152 135.469 1.176 ;
     RECT  134.741 38.208 135.596 38.424 ;
     RECT  135.317 3.408 135.605 3.96 ;
     RECT  135.605 3.936 135.785 3.96 ;
     RECT  135.493 40.896 136.021 40.92 ;
     RECT  136.021 40.8 136.361 40.92 ;
     RECT  136.177 39.744 136.969 39.768 ;
     RECT  135.709 1.728 137.009 1.752 ;
     RECT  137.18 2.016 137.408 2.28 ;
     RECT  135.317 5.184 137.408 5.208 ;
     RECT  135.596 37.488 137.408 38.424 ;
     RECT  136.969 39.6 137.408 39.768 ;
     RECT  136.501 40.992 137.408 41.016 ;
     RECT  137.408 2.016 137.512 41.052 ;
     RECT  137.512 2.016 137.704 40.782 ;
     RECT  137.704 37.008 137.873 40.44 ;
     RECT  137.873 37.008 137.939 39.384 ;
     RECT  137.939 38.736 137.945 39.384 ;
     RECT  137.941 0.576 138.053 0.6 ;
     RECT  137.509 43.056 138.413 43.08 ;
     RECT  137.939 37.008 138.557 37.608 ;
     RECT  137.873 40.416 138.997 40.44 ;
     RECT  138.997 40.416 139.097 40.488 ;
     RECT  137.945 38.736 139.561 38.76 ;
     RECT  139.525 40.56 139.637 40.584 ;
     RECT  139.561 38.736 139.705 38.808 ;
     RECT  137.704 3.984 139.925 4.008 ;
     RECT  137.704 5.184 140.029 5.208 ;
     RECT  138.301 1.728 140.101 1.752 ;
     RECT  139.705 38.736 140.101 39.528 ;
     RECT  140.101 1.728 140.195 2.28 ;
     RECT  140.101 38.016 140.243 39.528 ;
     RECT  140.243 38.016 140.825 38.232 ;
     RECT  140.243 39.312 140.825 39.528 ;
     RECT  140.825 39.504 140.897 39.528 ;
     RECT  140.029 4.56 141.077 5.208 ;
     RECT  140.485 40.992 141.185 41.016 ;
     RECT  141.433 21.12 141.517 21.144 ;
     RECT  140.825 38.112 141.545 38.232 ;
     RECT  141.493 41.616 141.905 41.64 ;
     RECT  141.901 0.096 142.019 0.12 ;
     RECT  141.973 42.144 142.157 42.168 ;
     RECT  141.077 5.04 142.189 5.208 ;
     RECT  140.195 1.728 142.373 1.752 ;
     RECT  141.445 13.824 142.549 13.848 ;
     RECT  142.549 13.632 142.693 13.848 ;
     RECT  142.513 21.648 142.693 21.672 ;
     RECT  141.545 38.112 142.693 38.136 ;
     RECT  142.621 2.016 142.808 2.904 ;
     RECT  142.189 4.512 142.808 5.208 ;
     RECT  142.693 13.632 142.808 14.232 ;
     RECT  142.693 21.648 142.808 21.72 ;
     RECT  138.557 37.008 142.808 37.032 ;
     RECT  142.693 38.112 142.808 38.76 ;
     RECT  142.501 40.992 142.808 41.052 ;
     RECT  142.808 2.016 142.912 41.052 ;
     RECT  142.693 43.056 143.027 43.08 ;
     RECT  142.912 2.016 143.104 41.016 ;
     RECT  143.104 21.12 143.353 21.672 ;
     RECT  143.353 21.12 143.533 21.144 ;
     RECT  143.104 38.16 143.669 39.336 ;
     RECT  143.104 2.832 143.957 2.856 ;
     RECT  143.669 39.312 143.957 39.336 ;
     RECT  143.413 1.728 144.092 1.752 ;
     RECT  143.669 38.16 144.209 38.184 ;
     RECT  143.104 40.992 144.469 41.016 ;
     RECT  144.092 1.728 144.899 2.28 ;
     RECT  144.469 40.704 144.949 41.016 ;
     RECT  144.781 21.648 144.961 21.672 ;
     RECT  143.104 13.008 144.997 14.232 ;
     RECT  143.104 4.512 145.045 5.208 ;
     RECT  144.961 21.12 145.045 21.672 ;
     RECT  144.949 40.704 145.073 41.592 ;
     RECT  144.817 38.064 145.177 38.088 ;
     RECT  145.073 41.568 145.181 41.592 ;
     RECT  143.104 36.912 145.501 36.936 ;
     RECT  145.177 38.016 145.501 38.088 ;
     RECT  145.501 36.912 145.541 38.088 ;
     RECT  145.541 37.008 145.897 38.088 ;
     RECT  144.997 12.48 145.973 14.232 ;
     RECT  145.897 37.008 146.045 38.232 ;
     RECT  145.045 4.512 146.053 5.544 ;
     RECT  144.899 1.728 146.185 1.752 ;
     RECT  146.045 38.208 146.257 38.232 ;
     RECT  146.185 1.728 146.293 2.184 ;
     RECT  146.293 1.728 146.377 2.28 ;
     RECT  146.053 4.128 146.437 5.544 ;
     RECT  145.477 43.056 146.441 43.08 ;
     RECT  146.257 38.208 146.477 38.952 ;
     RECT  145.045 21.648 146.593 21.672 ;
     RECT  146.689 21.12 146.773 21.144 ;
     RECT  146.377 1.728 147.356 2.184 ;
     RECT  146.437 3.696 147.445 5.544 ;
     RECT  145.973 12.48 147.769 13.944 ;
     RECT  147.653 21.168 147.769 21.192 ;
     RECT  147.445 3.312 147.829 5.544 ;
     RECT  146.437 40.992 147.913 41.016 ;
     RECT  147.356 1.728 148.021 2.28 ;
     RECT  147.829 3.312 148.021 5.592 ;
     RECT  146.477 38.208 148.093 38.232 ;
     RECT  148.021 0.096 148.163 0.12 ;
     RECT  148.021 1.728 148.208 5.592 ;
     RECT  147.769 12 148.208 13.944 ;
     RECT  147.769 21.12 148.208 21.192 ;
     RECT  146.045 37.008 148.208 37.032 ;
     RECT  148.093 38.208 148.208 38.712 ;
     RECT  147.913 40.464 148.208 41.016 ;
     RECT  148.208 1.728 148.453 41.052 ;
     RECT  148.453 1.728 148.504 41.16 ;
     RECT  148.504 41.136 148.745 41.16 ;
     RECT  148.504 3.024 148.817 5.592 ;
     RECT  148.504 12.528 148.817 13.848 ;
     RECT  148.504 37.008 148.997 39.624 ;
     RECT  148.817 12.528 149.321 13.656 ;
     RECT  148.997 39.6 149.533 39.624 ;
     RECT  148.817 3.312 149.645 5.592 ;
     RECT  149.645 3.408 149.653 5.592 ;
     RECT  149.461 42.144 149.717 42.168 ;
     RECT  149.653 3.408 149.749 5.736 ;
     RECT  149.749 3.408 149.845 5.784 ;
     RECT  148.504 1.728 149.941 1.752 ;
     RECT  148.997 37.008 150.001 38.184 ;
     RECT  149.533 39.6 150.001 39.72 ;
     RECT  149.321 12.528 150.013 13.608 ;
     RECT  149.941 43.056 150.221 43.08 ;
     RECT  149.941 1.728 150.361 1.8 ;
     RECT  150.013 13.104 150.445 13.608 ;
     RECT  149.845 3.408 150.469 6.024 ;
     RECT  150.001 37.008 150.469 39.72 ;
     RECT  150.445 13.584 150.509 13.608 ;
     RECT  150.469 36.528 150.509 39.72 ;
     RECT  150.509 37.584 150.581 39.72 ;
     RECT  150.581 38.16 150.617 39.72 ;
     RECT  150.361 1.152 150.707 1.8 ;
     RECT  150.421 40.992 150.832 41.016 ;
     RECT  150.469 3.408 150.973 6.12 ;
     RECT  150.832 40.944 150.995 41.016 ;
     RECT  150.707 1.728 150.997 1.8 ;
     RECT  150.973 3.36 150.997 6.12 ;
     RECT  150.997 1.728 151.084 6.12 ;
     RECT  151.084 3.36 151.085 6.12 ;
     RECT  150.617 39.312 151.121 39.72 ;
     RECT  151.084 1.728 151.517 1.752 ;
     RECT  151.121 39.312 151.661 39.336 ;
     RECT  151.085 3.408 151.811 6.12 ;
     RECT  151.811 4.272 151.841 6.12 ;
     RECT  150.617 38.16 152.269 38.184 ;
     RECT  150.995 40.992 152.437 41.016 ;
     RECT  152.101 2.304 152.449 2.328 ;
     RECT  152.449 2.304 152.485 2.856 ;
     RECT  152.269 38.16 152.665 38.76 ;
     RECT  152.449 12.528 152.953 12.552 ;
     RECT  152.953 12.528 152.989 12.6 ;
     RECT  151.841 4.464 153.097 6.12 ;
     RECT  153.097 4.128 153.205 6.12 ;
     RECT  152.437 40.944 153.349 41.016 ;
     RECT  153.349 40.944 153.443 41.64 ;
     RECT  152.485 1.728 153.445 2.856 ;
     RECT  153.205 3.936 153.445 6.12 ;
     RECT  152.989 12.528 153.493 13.128 ;
     RECT  153.445 1.728 153.608 6.12 ;
     RECT  153.493 12.528 153.608 13.656 ;
     RECT  153.485 21.456 153.608 21.48 ;
     RECT  150.509 36.528 153.608 36.552 ;
     RECT  152.665 38.16 153.608 39.576 ;
     RECT  153.443 40.944 153.608 41.052 ;
     RECT  153.608 1.728 153.712 41.052 ;
     RECT  153.712 1.728 153.904 40.782 ;
     RECT  153.904 1.728 153.929 6.12 ;
     RECT  153.925 0.096 154.067 0.12 ;
     RECT  153.925 43.056 154.067 43.08 ;
     RECT  153.904 13.104 154.181 13.656 ;
     RECT  154.181 13.104 154.451 13.128 ;
     RECT  154.285 42.192 154.451 42.216 ;
     RECT  153.904 37.728 154.685 39.864 ;
     RECT  153.929 1.728 154.721 1.752 ;
     RECT  154.685 37.728 154.865 39.48 ;
     RECT  153.929 2.832 154.981 6.12 ;
     RECT  154.865 37.728 155.333 39.432 ;
     RECT  155.333 38.64 155.369 39.432 ;
     RECT  154.885 40.992 155.549 41.016 ;
     RECT  154.933 0.528 155.621 0.552 ;
     RECT  154.981 2.208 155.749 6.12 ;
     RECT  155.749 1.728 155.801 6.12 ;
     RECT  155.801 1.728 156.233 6.024 ;
     RECT  153.904 36.528 156.805 36.552 ;
     RECT  155.725 37.584 156.805 37.608 ;
     RECT  156.733 13.104 156.817 13.128 ;
     RECT  156.421 40.464 156.881 40.488 ;
     RECT  155.893 42.144 157.205 42.168 ;
     RECT  156.233 1.728 157.24 1.752 ;
     RECT  156.233 2.736 157.24 6.024 ;
     RECT  157.24 1.728 157.349 6.024 ;
     RECT  157.349 4.56 157.523 6.024 ;
     RECT  156.805 36.528 157.637 37.608 ;
     RECT  157.381 41.568 157.673 41.592 ;
     RECT  157.637 37.104 157.709 37.608 ;
     RECT  155.369 38.64 158.281 39.336 ;
     RECT  157.909 40.416 158.281 40.44 ;
     RECT  158.245 10.224 158.309 10.248 ;
     RECT  158.281 38.64 158.317 40.44 ;
     RECT  157.349 1.728 158.339 3.432 ;
     RECT  157.523 5.712 158.341 6.024 ;
     RECT  158.317 38.64 158.389 40.488 ;
     RECT  158.339 2.016 158.453 3.432 ;
     RECT  157.523 4.56 158.453 4.68 ;
     RECT  158.341 5.712 158.453 6.264 ;
     RECT  158.453 2.016 158.713 4.68 ;
     RECT  158.453 5.712 158.713 6.312 ;
     RECT  158.713 2.016 158.725 6.312 ;
     RECT  158.725 2.016 158.749 6.36 ;
     RECT  158.389 38.208 158.849 40.488 ;
     RECT  158.245 13.68 158.869 13.704 ;
     RECT  158.492 0.048 158.915 0.072 ;
     RECT  158.749 2.016 159.008 7.128 ;
     RECT  158.309 9.696 159.008 10.248 ;
     RECT  158.389 12.528 159.008 12.552 ;
     RECT  158.869 13.68 159.008 13.8 ;
     RECT  157.633 22.176 159.008 22.2 ;
     RECT  157.709 37.104 159.008 37.128 ;
     RECT  158.849 38.208 159.008 41.016 ;
     RECT  159.008 2.016 159.112 41.052 ;
     RECT  159.112 2.016 159.304 40.782 ;
     RECT  159.304 9.696 159.443 9.72 ;
     RECT  159.397 42.192 159.545 42.216 ;
     RECT  159.304 36.48 159.587 40.104 ;
     RECT  159.493 0.528 159.617 0.552 ;
     RECT  159.304 2.016 159.653 5.448 ;
     RECT  159.587 38.16 159.653 40.104 ;
     RECT  159.653 2.016 159.721 3.96 ;
     RECT  159.721 1.728 159.805 3.96 ;
     RECT  159.304 34.8 160.265 34.824 ;
     RECT  159.304 10.8 160.297 10.824 ;
     RECT  159.653 5.376 160.405 5.448 ;
     RECT  159.304 7.104 160.405 7.464 ;
     RECT  159.304 13.92 160.405 14.28 ;
     RECT  160.297 10.272 160.441 10.824 ;
     RECT  159.653 38.16 160.481 39.528 ;
     RECT  160.405 13.68 160.489 14.28 ;
     RECT  160.441 9.696 160.525 10.824 ;
     RECT  160.357 42.144 160.553 42.168 ;
     RECT  160.525 10.224 160.577 10.824 ;
     RECT  160.489 14.256 160.621 14.28 ;
     RECT  159.587 36.48 160.645 37.128 ;
     RECT  160.645 36.048 160.661 37.128 ;
     RECT  160.481 38.16 160.691 38.76 ;
     RECT  159.805 2.064 160.693 3.96 ;
     RECT  160.405 5.376 160.693 7.464 ;
     RECT  160.577 10.224 160.693 10.872 ;
     RECT  160.693 10.224 160.697 11.064 ;
     RECT  160.661 36.048 160.733 37.08 ;
     RECT  160.693 2.064 160.748 7.464 ;
     RECT  160.697 10.272 160.789 11.064 ;
     RECT  160.748 2.064 160.828 7.896 ;
     RECT  160.828 7.872 160.835 7.896 ;
     RECT  160.733 36.48 160.949 37.08 ;
     RECT  160.873 41.568 160.957 41.736 ;
     RECT  160.828 2.064 161.123 6.792 ;
     RECT  161.089 13.104 161.173 13.128 ;
     RECT  160.613 0.528 161.197 0.552 ;
     RECT  161.123 2.064 161.281 6.744 ;
     RECT  160.621 14.256 161.305 14.856 ;
     RECT  160.789 10.272 161.413 11.448 ;
     RECT  161.305 14.256 161.417 14.904 ;
     RECT  161.413 10.272 161.497 11.976 ;
     RECT  161.281 6.192 161.561 6.744 ;
     RECT  161.305 39.792 161.597 39.816 ;
     RECT  161.281 2.064 161.603 5.16 ;
     RECT  161.603 2.256 161.633 5.16 ;
     RECT  161.497 10.272 161.633 11.448 ;
     RECT  161.417 14.832 161.669 14.904 ;
     RECT  161.633 5.136 161.713 5.16 ;
     RECT  161.669 14.88 161.747 14.904 ;
     RECT  161.633 11.376 161.785 11.448 ;
     RECT  161.633 10.272 161.843 10.296 ;
     RECT  160.691 38.16 161.849 38.568 ;
     RECT  161.561 6.72 161.885 6.744 ;
     RECT  161.633 2.256 161.891 4.008 ;
     RECT  161.804 7.776 161.891 7.8 ;
     RECT  161.785 11.424 161.891 11.448 ;
     RECT  160.957 41.616 161.891 41.736 ;
     RECT  161.891 2.256 161.929 3.432 ;
     RECT  161.849 38.16 161.957 38.184 ;
     RECT  160.949 37.056 162.137 37.08 ;
     RECT  161.929 2.832 162.323 3.432 ;
     RECT  161.891 41.616 162.419 41.64 ;
     RECT  161.197 0.528 162.421 0.6 ;
     RECT  162.323 3.408 162.721 3.432 ;
     RECT  162.457 40.464 162.899 40.488 ;
     RECT  162.421 0.096 163.091 0.6 ;
     RECT  163.033 41.04 163.379 41.064 ;
     RECT  163.091 0.096 163.427 0.12 ;
    LAYER M5 ;
     RECT  0.768 0.016 163.416 0.131 ;
     RECT  71.136 0.131 163.08 0.611 ;
     RECT  0.768 0.131 69.912 1.763 ;
     RECT  71.136 0.611 162.696 1.763 ;
     RECT  16.944 1.763 21.672 1.811 ;
     RECT  33.552 1.763 33.576 1.811 ;
     RECT  36.48 1.763 37.464 1.811 ;
     RECT  50.64 1.763 57.192 1.811 ;
     RECT  58.656 1.763 58.68 1.811 ;
     RECT  64.8 1.763 65.544 1.811 ;
     RECT  80.832 1.763 81.192 1.811 ;
     RECT  97.008 1.763 97.032 1.811 ;
     RECT  98.448 1.763 98.472 1.811 ;
     RECT  105 1.763 107.064 1.811 ;
     RECT  149.952 1.763 149.976 1.811 ;
     RECT  24 1.763 25.224 1.859 ;
     RECT  34.656 1.763 35.112 1.859 ;
     RECT  38.64 1.763 38.664 1.859 ;
     RECT  65.52 1.811 65.544 1.859 ;
     RECT  90.528 1.763 90.552 1.859 ;
     RECT  102 1.763 102.024 1.859 ;
     RECT  7.776 1.763 8.112 2.051 ;
     RECT  6.048 1.763 6.072 2.291 ;
     RECT  9.552 1.763 10.968 2.291 ;
     RECT  13.2 1.763 14.472 2.291 ;
     RECT  15.504 1.763 15.912 2.291 ;
     RECT  17.28 1.811 21.672 2.291 ;
     RECT  28.128 1.763 28.152 2.291 ;
     RECT  42.672 1.763 43.416 2.291 ;
     RECT  74.688 1.763 75.432 2.291 ;
     RECT  105 1.811 106.584 2.291 ;
     RECT  119.808 1.763 121.896 2.291 ;
     RECT  123.072 1.763 123.096 2.291 ;
     RECT  124.176 1.763 128.904 2.291 ;
     RECT  131.424 1.763 132.312 2.291 ;
     RECT  133.344 1.763 135.096 2.291 ;
     RECT  137.232 1.763 137.712 2.291 ;
     RECT  140.16 1.763 140.184 2.291 ;
     RECT  142.704 1.763 143.112 2.291 ;
     RECT  144.144 1.763 144.888 2.291 ;
     RECT  55.248 1.811 57.192 2.339 ;
     RECT  124.56 2.291 128.76 2.387 ;
     RECT  13.2 2.291 13.8 2.531 ;
     RECT  40.128 1.763 41.016 2.725 ;
     RECT  44.448 1.763 45.912 2.725 ;
     RECT  153.216 1.763 156.168 2.725 ;
     RECT  157.296 1.763 162.696 2.725 ;
     RECT  48.816 1.763 49.56 2.773 ;
     RECT  50.64 1.811 54.12 2.773 ;
     RECT  72.6 1.763 73.464 2.773 ;
     RECT  74.688 2.291 74.808 2.773 ;
     RECT  82.512 1.763 83.736 2.773 ;
     RECT  12.192 1.763 12.216 2.821 ;
     RECT  13.2 2.531 13.512 2.821 ;
     RECT  24 1.859 24.408 2.821 ;
     RECT  34.8 1.859 35.112 2.821 ;
     RECT  36.672 1.811 37.464 2.821 ;
     RECT  47.136 1.763 47.784 2.821 ;
     RECT  48.816 2.773 54.12 2.821 ;
     RECT  55.248 2.339 56.856 2.821 ;
     RECT  108.144 1.763 108.216 2.821 ;
     RECT  109.2 1.763 111.624 2.821 ;
     RECT  114.048 1.763 117.96 2.821 ;
     RECT  151.008 1.763 152.136 2.821 ;
     RECT  153.216 2.725 162.696 2.821 ;
     RECT  0.768 1.763 2.808 2.915 ;
     RECT  9.552 2.291 9.576 2.915 ;
     RECT  47.136 2.821 56.856 2.915 ;
     RECT  105 2.291 105.432 2.915 ;
     RECT  107.712 2.821 117.96 2.915 ;
     RECT  151.008 2.821 162.696 2.915 ;
     RECT  82.512 2.773 83.832 2.963 ;
     RECT  87.648 1.763 87.672 2.963 ;
     RECT  92.304 1.763 92.328 2.963 ;
     RECT  160.656 2.915 162.696 2.963 ;
     RECT  72.6 2.773 74.808 3.061 ;
     RECT  7.8 2.051 8.112 3.301 ;
     RECT  72.48 3.061 74.808 3.301 ;
     RECT  124.56 2.387 127.656 3.301 ;
     RECT  118.992 2.821 119.016 3.349 ;
     RECT  16.512 3.157 16.536 3.397 ;
     RECT  17.52 2.291 21.672 3.397 ;
     RECT  47.136 2.915 56.712 3.397 ;
     RECT  67.2 1.763 67.512 3.397 ;
     RECT  118.944 3.349 119.016 3.397 ;
     RECT  120.144 2.291 121.896 3.397 ;
     RECT  122.976 2.821 123 3.397 ;
     RECT  128.736 2.387 128.76 3.397 ;
     RECT  1.104 2.915 2.808 3.443 ;
     RECT  16.512 3.397 21.672 3.443 ;
     RECT  47.088 3.397 56.712 3.443 ;
     RECT  99.6 1.763 100.008 3.443 ;
     RECT  117.936 2.915 117.96 3.443 ;
     RECT  133.344 2.291 134.664 3.443 ;
     RECT  160.704 2.963 162.696 3.443 ;
     RECT  34.8 2.821 37.464 3.491 ;
     RECT  39.888 2.725 41.016 3.491 ;
     RECT  71.088 3.061 71.112 3.491 ;
     RECT  81.168 1.811 81.192 3.491 ;
     RECT  82.608 2.963 83.832 3.491 ;
     RECT  118.944 3.397 121.896 3.491 ;
     RECT  151.008 2.915 159.576 3.491 ;
     RECT  134.208 3.443 134.664 3.539 ;
     RECT  44.352 2.725 45.912 3.541 ;
     RECT  47.088 3.443 51.432 3.587 ;
     RECT  52.416 3.443 56.712 3.587 ;
     RECT  67.2 3.397 67.608 3.587 ;
     RECT  83.232 3.491 83.832 3.587 ;
     RECT  151.008 3.491 159.528 3.587 ;
     RECT  83.232 3.587 83.712 3.635 ;
     RECT  72.48 3.301 75.576 3.637 ;
     RECT  77.232 1.763 78.312 3.637 ;
     RECT  65.232 3.253 65.256 3.685 ;
     RECT  99.6 3.443 99.912 3.685 ;
     RECT  131.808 2.291 132.312 3.685 ;
     RECT  151.008 3.587 159.312 3.685 ;
     RECT  24 2.821 24.456 3.829 ;
     RECT  107.712 2.915 116.76 3.829 ;
     RECT  131.088 3.685 132.312 3.829 ;
     RECT  72.48 3.637 78.312 3.875 ;
     RECT  12.192 2.821 13.512 3.925 ;
     RECT  16.512 3.443 21.624 3.925 ;
     RECT  105 2.915 105.312 3.925 ;
     RECT  64.896 3.685 65.256 3.971 ;
     RECT  44.352 3.541 46.056 3.973 ;
     RECT  47.088 3.587 48.984 3.973 ;
     RECT  1.44 3.443 2.808 4.019 ;
     RECT  124.08 3.301 127.656 4.019 ;
     RECT  160.704 3.443 161.88 4.019 ;
     RECT  150.912 3.685 159.312 4.067 ;
     RECT  70.704 3.781 70.728 4.115 ;
     RECT  37.2 3.491 37.464 4.117 ;
     RECT  146.304 1.763 148.512 4.117 ;
     RECT  39.888 3.491 40.632 4.165 ;
     RECT  88.8 1.763 89.112 4.213 ;
     RECT  9.408 3.397 9.432 4.261 ;
     RECT  146.064 4.117 148.512 4.261 ;
     RECT  149.664 3.925 149.688 4.261 ;
     RECT  106.56 2.291 106.584 4.357 ;
     RECT  107.664 3.829 116.76 4.357 ;
     RECT  106.56 4.357 116.76 4.405 ;
     RECT  98.256 4.069 98.28 4.453 ;
     RECT  4.608 1.763 4.632 4.501 ;
     RECT  7.536 3.301 8.112 4.501 ;
     RECT  9.312 4.261 9.432 4.501 ;
     RECT  11.568 3.925 13.512 4.501 ;
     RECT  16.176 3.925 21.624 4.501 ;
     RECT  99.408 3.685 99.912 4.501 ;
     RECT  67.2 3.587 67.512 4.549 ;
     RECT  98.016 4.453 98.28 4.549 ;
     RECT  99.408 4.501 100.776 4.549 ;
     RECT  16.032 4.501 21.624 4.595 ;
     RECT  53.328 3.587 56.712 4.595 ;
     RECT  65.088 3.971 65.256 4.595 ;
     RECT  72.48 3.875 73.992 4.595 ;
     RECT  106.56 4.405 116.808 4.595 ;
     RECT  125.856 4.019 127.656 4.595 ;
     RECT  134.64 3.539 134.664 4.595 ;
     RECT  86.688 4.117 86.712 4.597 ;
     RECT  95.712 4.405 95.736 4.597 ;
     RECT  96.912 4.501 96.936 4.597 ;
     RECT  122.928 3.397 123 4.597 ;
     RECT  124.08 4.019 124.824 4.597 ;
     RECT  50.016 3.587 51.432 4.643 ;
     RECT  60.384 1.763 60.408 4.643 ;
     RECT  106.56 4.595 114.792 4.643 ;
     RECT  118.944 3.491 121.8 4.643 ;
     RECT  122.928 4.597 124.824 4.643 ;
     RECT  122.928 4.643 124.104 4.645 ;
     RECT  146.064 4.261 149.688 4.645 ;
     RECT  150.912 4.067 154.92 4.645 ;
     RECT  1.44 4.019 2.712 4.691 ;
     RECT  31.728 3.349 31.752 4.691 ;
     RECT  114.048 4.643 114.792 4.739 ;
     RECT  128.736 3.397 128.808 4.739 ;
     RECT  4.608 4.501 5.208 4.837 ;
     RECT  6.288 4.501 6.312 4.837 ;
     RECT  7.44 4.501 9.96 4.837 ;
     RECT  44.064 3.973 48.984 4.837 ;
     RECT  43.296 4.837 48.984 4.931 ;
     RECT  50.832 4.643 51.432 4.931 ;
     RECT  125.856 4.595 127.512 4.931 ;
     RECT  80.688 4.117 80.712 4.933 ;
     RECT  103.776 2.821 103.8 4.933 ;
     RECT  43.296 4.931 47.112 4.979 ;
     RECT  75.552 3.875 78.312 4.979 ;
     RECT  103.536 4.933 103.8 4.981 ;
     RECT  105 3.925 105.48 4.981 ;
     RECT  49.008 4.933 49.032 5.075 ;
     RECT  80.304 4.933 80.712 5.075 ;
     RECT  4.608 4.837 9.96 5.077 ;
     RECT  11.04 4.501 14.952 5.077 ;
     RECT  106.56 4.643 111.768 5.123 ;
     RECT  80.688 5.075 80.712 5.125 ;
     RECT  16.032 4.595 20.904 5.171 ;
     RECT  34.8 3.491 36.072 5.171 ;
     RECT  37.2 4.117 37.512 5.171 ;
     RECT  44.064 4.979 47.112 5.171 ;
     RECT  53.328 4.595 53.448 5.171 ;
     RECT  54.432 4.595 56.712 5.171 ;
     RECT  72.48 4.595 73.464 5.171 ;
     RECT  112.8 4.643 112.824 5.171 ;
     RECT  114.048 4.739 114.696 5.171 ;
     RECT  122.88 4.645 124.104 5.171 ;
     RECT  128.784 4.739 128.808 5.171 ;
     RECT  131.088 3.829 132.744 5.171 ;
     RECT  146.064 4.645 154.92 5.171 ;
     RECT  155.952 4.067 159.312 5.171 ;
     RECT  160.704 4.019 161.688 5.171 ;
     RECT  92.448 4.837 92.472 5.173 ;
     RECT  117.792 4.981 117.816 5.173 ;
     RECT  37.488 5.171 37.512 5.219 ;
     RECT  44.064 5.171 44.52 5.219 ;
     RECT  50.832 4.931 51.312 5.219 ;
     RECT  156.336 5.171 159.312 5.219 ;
     RECT  53.328 5.171 53.4 5.267 ;
     RECT  80.688 5.125 80.952 5.267 ;
     RECT  156.576 5.219 159.312 5.267 ;
     RECT  98.016 4.549 100.776 5.269 ;
     RECT  92.448 5.173 93.048 5.315 ;
     RECT  115.8 4.595 116.808 5.317 ;
     RECT  117.792 5.173 118.344 5.317 ;
     RECT  4.608 5.077 14.952 5.365 ;
     RECT  29.4 1.763 29.712 5.365 ;
     RECT  156.768 5.267 159.312 5.365 ;
     RECT  160.704 5.171 161.256 5.365 ;
     RECT  80.688 5.267 80.712 5.411 ;
     RECT  126.6 4.931 127.512 5.411 ;
     RECT  156.768 5.365 159.432 5.413 ;
     RECT  160.464 5.365 161.256 5.413 ;
     RECT  75.552 4.979 76.152 5.459 ;
     RECT  146.064 5.171 154.44 5.459 ;
     RECT  39.312 4.165 40.632 5.461 ;
     RECT  95.712 4.597 96.936 5.461 ;
     RECT  98.016 5.269 100.92 5.461 ;
     RECT  91.2 5.029 91.224 5.507 ;
     RECT  115.8 5.317 118.344 5.507 ;
     RECT  86.688 4.597 86.904 5.509 ;
     RECT  103.536 4.981 105.48 5.557 ;
     RECT  92.448 5.315 92.952 5.603 ;
     RECT  95.712 5.461 100.92 5.603 ;
     RECT  20.448 5.171 20.904 5.605 ;
     RECT  21.936 5.365 21.96 5.605 ;
     RECT  121.2 4.643 121.8 5.605 ;
     RECT  122.88 5.171 123.864 5.605 ;
     RECT  86.592 5.509 86.904 5.651 ;
     RECT  90.624 5.509 90.648 5.699 ;
     RECT  125.376 5.173 125.4 5.699 ;
     RECT  16.032 5.171 19.368 5.747 ;
     RECT  26.208 4.501 26.232 5.747 ;
     RECT  34.8 5.171 35.88 5.747 ;
     RECT  39.312 5.461 41.304 5.747 ;
     RECT  76.128 5.459 76.152 5.747 ;
     RECT  86.88 5.651 86.904 5.747 ;
     RECT  95.712 5.603 96.36 5.747 ;
     RECT  132 5.171 132.744 5.747 ;
     RECT  146.064 5.459 151.032 5.747 ;
     RECT  156.768 5.413 161.256 5.747 ;
     RECT  120.144 4.643 120.168 5.749 ;
     RECT  121.2 5.605 123.864 5.749 ;
     RECT  54.72 5.171 56.712 5.795 ;
     RECT  107.664 5.123 111.768 5.843 ;
     RECT  27.696 5.797 27.72 5.845 ;
     RECT  92.448 5.603 92.472 5.891 ;
     RECT  107.664 5.843 111.192 5.891 ;
     RECT  156.768 5.747 161.112 5.891 ;
     RECT  37.968 5.605 37.992 5.893 ;
     RECT  107.664 5.891 110.712 5.939 ;
     RECT  17.568 5.747 19.368 5.987 ;
     RECT  85.2 4.837 85.224 5.987 ;
     RECT  24 3.829 24.648 5.989 ;
     RECT  29.232 5.365 29.712 6.083 ;
     RECT  2.4 4.691 2.712 6.181 ;
     RECT  3.888 5.365 14.952 6.181 ;
     RECT  17.952 5.987 19.368 6.181 ;
     RECT  20.448 5.605 21.96 6.181 ;
     RECT  37.968 5.893 38.04 6.181 ;
     RECT  88.8 4.213 89.544 6.229 ;
     RECT  58.464 5.461 58.488 6.275 ;
     RECT  66.24 4.549 67.512 6.323 ;
     RECT  88.8 6.229 89.976 6.371 ;
     RECT  158.352 5.891 161.112 6.709 ;
     RECT  158.352 6.709 161.832 6.803 ;
     RECT  95.712 5.747 95.736 6.899 ;
     RECT  98.016 5.603 100.776 6.899 ;
     RECT  161.808 6.803 161.832 7.765 ;
     RECT  158.352 6.803 160.776 7.861 ;
     RECT  158.352 7.861 160.824 10.213 ;
     RECT  158.256 10.213 160.824 10.789 ;
     RECT  161.808 7.765 161.88 10.789 ;
     RECT  158.256 10.789 161.88 11.459 ;
     RECT  45.6 5.171 46.104 12.373 ;
     RECT  47.088 5.171 47.112 12.373 ;
     RECT  145.056 5.509 145.08 12.469 ;
     RECT  16.032 5.747 16.44 12.563 ;
     RECT  146.064 5.747 150.408 12.563 ;
     RECT  152.496 5.459 154.44 12.563 ;
     RECT  142.8 2.291 143.112 12.997 ;
     RECT  2.4 6.181 14.952 13.045 ;
     RECT  16.416 12.563 16.44 13.045 ;
     RECT  17.952 6.181 21.96 13.045 ;
     RECT  146.064 12.563 149.208 13.139 ;
     RECT  150.384 12.563 150.408 13.139 ;
     RECT  153.024 12.563 154.44 13.139 ;
     RECT  156.768 5.891 156.792 13.139 ;
     RECT  16.416 13.045 21.96 13.379 ;
     RECT  145.008 12.469 145.08 13.381 ;
     RECT  146.064 13.139 148.632 13.381 ;
     RECT  24 5.989 25.416 13.621 ;
     RECT  27.024 5.845 27.72 13.621 ;
     RECT  142.8 12.997 143.496 13.621 ;
     RECT  2.4 13.045 15.096 13.715 ;
     RECT  44.496 5.219 44.52 13.715 ;
     RECT  145.008 13.381 148.632 13.715 ;
     RECT  158.256 11.459 161.736 13.715 ;
     RECT  158.88 13.715 161.736 13.811 ;
     RECT  145.008 13.715 148.512 13.909 ;
     RECT  45.6 12.373 47.112 14.005 ;
     RECT  120.144 5.749 123.864 14.005 ;
     RECT  3.936 13.715 15.096 14.197 ;
     RECT  16.416 13.379 21.864 14.197 ;
     RECT  159 13.811 161.736 14.291 ;
     RECT  160.704 14.291 161.736 14.867 ;
     RECT  161.712 14.867 161.736 14.915 ;
     RECT  3.936 14.197 21.864 21.155 ;
     RECT  45.264 14.005 47.112 21.155 ;
     RECT  98.688 6.899 100.776 21.155 ;
     RECT  103.536 5.557 106.152 21.155 ;
     RECT  107.664 5.939 108.744 21.155 ;
     RECT  109.872 5.939 110.712 21.155 ;
     RECT  114.672 5.171 114.696 21.155 ;
     RECT  115.8 5.507 117.816 21.155 ;
     RECT  119.376 14.005 123.864 21.155 ;
     RECT  141.456 13.813 141.48 21.155 ;
     RECT  142.56 13.621 143.496 21.155 ;
     RECT  144.816 13.909 148.512 21.155 ;
     RECT  3.936 21.155 16.632 21.203 ;
     RECT  17.952 21.155 19.848 21.203 ;
     RECT  24 13.621 27.72 21.203 ;
     RECT  147.696 21.155 148.512 21.203 ;
     RECT  20.88 21.155 21.864 21.205 ;
     RECT  3.936 21.203 4.536 21.251 ;
     RECT  5.616 21.203 16.632 21.251 ;
     RECT  17.952 21.203 19.752 21.251 ;
     RECT  26.352 21.203 27.048 21.251 ;
     RECT  24 21.203 24.648 21.299 ;
     RECT  18.048 21.251 19.752 21.347 ;
     RECT  26.352 21.251 26.376 21.347 ;
     RECT  20.88 21.205 22.824 21.395 ;
     RECT  18.048 21.347 19.368 21.491 ;
     RECT  20.88 21.395 21.864 21.491 ;
     RECT  153.504 13.139 153.912 21.491 ;
     RECT  18.144 21.491 19.368 21.539 ;
     RECT  21.84 21.491 21.864 21.539 ;
     RECT  18.6 21.539 19.368 21.587 ;
     RECT  3.936 21.251 3.96 21.683 ;
     RECT  5.664 21.251 16.632 21.683 ;
     RECT  108.048 21.155 108.648 21.683 ;
     RECT  115.8 21.155 117.048 21.683 ;
     RECT  121.2 21.155 121.944 21.683 ;
     RECT  142.56 21.155 143.304 21.683 ;
     RECT  144.816 21.155 146.568 21.683 ;
     RECT  123.024 21.155 123.048 21.731 ;
     RECT  142.704 21.683 143.112 21.731 ;
     RECT  0.144 21.493 0.168 21.779 ;
     RECT  9.984 21.683 11.88 21.875 ;
     RECT  13.008 21.683 16.632 21.875 ;
     RECT  11.856 21.875 11.88 21.923 ;
     RECT  9.984 21.875 10.44 21.971 ;
     RECT  14.832 21.875 16.632 22.019 ;
     RECT  13.008 21.875 13.656 22.067 ;
     RECT  15.84 22.019 16.632 22.067 ;
     RECT  13.104 22.067 13.656 22.115 ;
     RECT  10.416 21.971 10.44 22.163 ;
     RECT  15.84 22.067 15.864 22.163 ;
     RECT  119.376 21.155 119.4 22.165 ;
     RECT  14.832 22.019 14.856 22.211 ;
     RECT  119.376 22.165 119.64 22.211 ;
     RECT  5.664 21.683 8.712 22.259 ;
     RECT  13.2 22.115 13.608 22.259 ;
     RECT  45.504 21.155 47.112 25.139 ;
     RECT  6.24 22.259 6.264 26.197 ;
     RECT  5.952 26.197 6.264 26.243 ;
     RECT  119.616 22.211 119.64 26.243 ;
     RECT  121.2 21.683 121.512 26.725 ;
     RECT  5.952 26.243 5.976 28.547 ;
     RECT  45.6 25.139 47.112 33.587 ;
     RECT  50.88 5.219 51.312 36.083 ;
     RECT  53.376 5.267 53.4 36.131 ;
     RECT  88.8 6.371 89.112 36.325 ;
     RECT  55.392 5.795 56.712 36.373 ;
     RECT  153.6 21.491 153.912 36.517 ;
     RECT  51 36.083 51.312 36.613 ;
     RECT  72.6 5.171 72.912 36.901 ;
     RECT  74.016 36.133 74.04 36.901 ;
     RECT  37.728 6.181 38.04 36.949 ;
     RECT  39.552 5.747 41.304 36.949 ;
     RECT  29.4 6.083 29.712 36.997 ;
     RECT  61.8 1.763 62.112 36.997 ;
     RECT  137.4 2.291 137.712 36.997 ;
     RECT  159 14.291 159.312 36.997 ;
     RECT  37.728 36.949 41.304 37.045 ;
     RECT  42.336 5.653 42.36 37.045 ;
     RECT  51 36.613 52.248 37.091 ;
     RECT  37.728 37.045 42.36 37.187 ;
     RECT  37.728 37.187 41.688 37.235 ;
     RECT  69.936 36.757 69.96 37.285 ;
     RECT  115.8 21.683 116.112 37.285 ;
     RECT  34.8 5.747 35.112 37.429 ;
     RECT  37.728 37.235 40.512 37.475 ;
     RECT  54.48 36.373 56.712 37.475 ;
     RECT  126.6 5.411 126.912 37.477 ;
     RECT  37.728 37.475 38.712 37.573 ;
     RECT  67.2 6.323 67.512 37.573 ;
     RECT  157.008 36.901 157.032 37.573 ;
     RECT  40.032 37.475 40.512 37.619 ;
     RECT  124.704 36.949 124.728 37.621 ;
     RECT  124.272 37.621 124.728 37.763 ;
     RECT  69.936 37.285 70.344 37.765 ;
     RECT  98.688 21.155 100.104 37.765 ;
     RECT  159 36.997 159.576 37.859 ;
     RECT  67.2 37.573 68.088 37.861 ;
     RECT  69.936 37.765 70.488 37.861 ;
     RECT  72.6 36.901 74.04 37.861 ;
     RECT  40.08 37.619 40.512 38.003 ;
     RECT  29.4 36.997 30.216 38.005 ;
     RECT  32.256 37.429 32.28 38.051 ;
     RECT  110.4 21.155 110.712 38.101 ;
     RECT  41.664 37.235 41.688 38.147 ;
     RECT  54.48 37.475 54.744 38.147 ;
     RECT  71.856 37.861 74.04 38.147 ;
     RECT  7.8 22.259 8.112 38.149 ;
     RECT  34.176 37.429 35.112 38.149 ;
     RECT  61.8 36.997 63.096 38.149 ;
     RECT  121.104 26.725 121.512 38.149 ;
     RECT  148.2 21.203 148.512 38.149 ;
     RECT  61.8 38.149 63.816 38.195 ;
     RECT  27.6 36.997 27.624 38.197 ;
     RECT  51 37.091 51.312 38.197 ;
     RECT  9.84 37.573 9.864 38.243 ;
     RECT  36.864 37.573 38.712 38.243 ;
     RECT  135.648 37.477 135.672 38.243 ;
     RECT  71.856 38.147 72.912 38.387 ;
     RECT  81.744 37.573 81.768 38.387 ;
     RECT  87.12 37.573 87.144 38.387 ;
     RECT  115.8 37.285 116.232 38.387 ;
     RECT  137.4 36.997 137.928 38.387 ;
     RECT  153.6 36.517 154.872 38.387 ;
     RECT  15.072 37.477 15.096 38.435 ;
     RECT  28.944 38.005 30.216 38.435 ;
     RECT  92.304 37.381 92.328 38.435 ;
     RECT  122.976 37.573 123 38.435 ;
     RECT  2.4 13.715 2.712 38.437 ;
     RECT  88.8 36.325 90.072 38.533 ;
     RECT  54.48 38.147 54.6 38.579 ;
     RECT  67.2 37.861 70.488 38.579 ;
     RECT  95.712 37.045 95.736 38.629 ;
     RECT  60.432 37.525 60.456 38.675 ;
     RECT  95.52 38.629 95.736 38.675 ;
     RECT  106.848 38.005 106.872 38.675 ;
     RECT  113.856 36.997 113.88 38.675 ;
     RECT  126.6 37.477 127.176 38.675 ;
     RECT  129.024 37.573 129.048 38.675 ;
     RECT  61.8 38.195 62.112 38.677 ;
     RECT  83.4 3.635 83.712 38.677 ;
     RECT  27.6 38.197 27.72 38.723 ;
     RECT  28.944 38.435 29.712 38.723 ;
     RECT  36.864 38.243 37.752 38.723 ;
     RECT  50.88 38.197 51.312 38.725 ;
     RECT  142.8 21.731 143.112 38.725 ;
     RECT  159 37.859 159.312 38.725 ;
     RECT  54.576 38.579 54.6 38.771 ;
     RECT  68.976 38.579 70.488 38.771 ;
     RECT  74.016 38.147 74.04 38.771 ;
     RECT  153.6 38.387 154.248 38.771 ;
     RECT  160.656 36.037 160.68 38.771 ;
     RECT  142.704 38.725 143.112 38.773 ;
     RECT  48.96 38.149 48.984 38.819 ;
     RECT  88.176 38.533 90.072 38.819 ;
     RECT  156.144 37.573 157.032 38.819 ;
     RECT  132 5.747 132.312 38.821 ;
     RECT  95.52 38.675 95.544 38.915 ;
     RECT  12 37.477 12.024 38.963 ;
     RECT  20.016 37.573 20.04 38.963 ;
     RECT  63.792 38.195 63.816 38.963 ;
     RECT  110.016 38.101 110.712 38.963 ;
     RECT  131.904 38.821 132.312 39.011 ;
     RECT  142.704 38.773 143.592 39.011 ;
     RECT  44.352 38.677 44.376 39.155 ;
     RECT  61.536 38.677 62.112 39.157 ;
     RECT  65.52 38.581 65.544 39.203 ;
     RECT  83.28 38.677 83.712 39.203 ;
     RECT  158.592 38.725 159.312 39.205 ;
     RECT  18.6 21.587 18.912 39.301 ;
     RECT  140.208 38.005 140.232 39.301 ;
     RECT  102.336 38.773 102.36 39.347 ;
     RECT  156.144 38.819 156.168 39.347 ;
     RECT  77.28 4.979 78.312 39.349 ;
     RECT  137.4 38.387 137.712 39.349 ;
     RECT  16.992 38.677 17.016 39.395 ;
     RECT  37.728 38.723 37.752 39.395 ;
     RECT  45.6 33.587 46.344 39.395 ;
     RECT  77.28 39.349 78.408 39.395 ;
     RECT  34.176 38.149 35.256 39.491 ;
     RECT  120.576 38.149 121.512 39.491 ;
     RECT  55.92 37.475 56.712 39.539 ;
     RECT  88.176 38.819 89.112 39.539 ;
     RECT  140.016 39.301 140.232 39.539 ;
     RECT  45.6 39.395 45.912 39.589 ;
     RECT  150.816 39.301 150.84 39.635 ;
     RECT  77.328 39.395 78.408 39.731 ;
     RECT  153.6 38.771 153.912 39.733 ;
     RECT  25.488 38.101 25.512 39.779 ;
     RECT  29.4 38.723 29.712 39.829 ;
     RECT  98.688 37.765 100.776 39.829 ;
     RECT  36.672 39.061 36.696 39.877 ;
     RECT  77.568 39.731 78.408 39.923 ;
     RECT  2.4 38.437 2.808 39.971 ;
     RECT  22.752 37.429 22.776 40.405 ;
     RECT  137.4 39.349 137.832 40.405 ;
     RECT  158.592 39.205 159.912 40.405 ;
     RECT  7.8 38.149 8.376 40.453 ;
     RECT  34.176 39.491 35.112 40.453 ;
     RECT  45.12 39.589 45.912 40.453 ;
     RECT  50.688 38.725 51.312 40.453 ;
     RECT  56.4 39.539 56.712 40.453 ;
     RECT  125.088 38.101 125.112 40.453 ;
     RECT  126.6 38.675 126.912 40.453 ;
     RECT  132 39.011 132.312 40.453 ;
     RECT  137.4 40.405 138.552 40.453 ;
     RECT  148.2 38.149 148.968 40.453 ;
     RECT  98.256 39.829 100.776 40.499 ;
     RECT  10.32 40.453 10.344 40.501 ;
     RECT  18.48 39.301 18.912 40.549 ;
     RECT  49.104 40.453 49.128 40.549 ;
     RECT  50.688 40.453 51.576 40.549 ;
     RECT  78 39.923 78.408 40.549 ;
     RECT  137.4 40.453 139.032 40.549 ;
     RECT  140.016 39.539 140.04 40.549 ;
     RECT  24 21.299 24.312 40.693 ;
     RECT  13.2 22.259 13.512 40.741 ;
     RECT  14.784 40.549 14.808 40.741 ;
     RECT  81.888 40.453 81.912 40.789 ;
     RECT  98.256 40.499 98.28 40.789 ;
     RECT  124.128 40.453 125.112 40.789 ;
     RECT  126.096 40.453 126.912 40.789 ;
     RECT  18.288 40.549 18.912 40.837 ;
     RECT  20.256 40.453 20.28 40.837 ;
     RECT  42.144 38.149 42.168 40.837 ;
     RECT  55.056 40.453 55.08 40.837 ;
     RECT  136.032 40.789 136.056 40.885 ;
     RECT  18.288 40.837 20.28 40.933 ;
     RECT  27.696 38.723 27.72 40.933 ;
     RECT  29.28 39.829 29.712 40.933 ;
     RECT  56.4 40.453 57.576 40.933 ;
     RECT  78 40.549 78.936 40.933 ;
     RECT  94.2 1.763 94.512 40.933 ;
     RECT  96.768 40.453 96.792 40.933 ;
     RECT  110.4 38.963 110.712 40.933 ;
     RECT  131.904 40.453 132.312 40.933 ;
     RECT  133.536 39.541 133.56 40.933 ;
     RECT  7.344 40.453 8.856 40.981 ;
     RECT  10.32 40.501 10.824 40.981 ;
     RECT  13.2 40.741 14.808 40.981 ;
     RECT  22.272 40.405 22.776 40.981 ;
     RECT  23.76 40.693 24.312 40.981 ;
     RECT  27.216 40.933 27.72 40.981 ;
     RECT  29.232 40.933 29.712 40.981 ;
     RECT  30.72 40.453 30.744 40.981 ;
     RECT  36.672 39.877 37.656 40.981 ;
     RECT  38.64 40.453 38.664 40.981 ;
     RECT  40.2 38.003 40.512 40.981 ;
     RECT  42.144 40.837 42.648 40.981 ;
     RECT  45.12 40.453 46.104 40.981 ;
     RECT  48.096 40.453 48.12 40.981 ;
     RECT  54.528 40.837 55.08 40.981 ;
     RECT  56.4 40.933 58.056 40.981 ;
     RECT  67.2 38.579 67.992 40.981 ;
     RECT  69.936 38.771 70.488 40.981 ;
     RECT  72.6 38.387 72.912 40.981 ;
     RECT  74.4 40.453 74.424 40.981 ;
     RECT  77.424 40.933 78.936 40.981 ;
     RECT  81.888 40.789 82.392 40.981 ;
     RECT  83.4 39.203 83.712 40.981 ;
     RECT  84.864 40.837 84.888 40.981 ;
     RECT  88.8 39.539 89.112 40.981 ;
     RECT  92.304 40.837 92.328 40.981 ;
     RECT  93.312 40.933 94.512 40.981 ;
     RECT  96.288 40.933 96.792 40.981 ;
     RECT  99.6 40.499 100.776 40.981 ;
     RECT  105 21.155 105.312 40.981 ;
     RECT  108.192 39.877 108.216 40.981 ;
     RECT  110.4 40.933 111.24 40.981 ;
     RECT  113.184 40.453 113.688 40.981 ;
     RECT  115.8 38.387 116.112 40.981 ;
     RECT  118.128 40.837 118.152 40.981 ;
     RECT  120.144 40.357 120.168 40.981 ;
     RECT  121.2 39.491 121.512 40.981 ;
     RECT  124.128 40.789 126.912 40.981 ;
     RECT  131.904 40.933 133.56 40.981 ;
     RECT  135.552 40.885 136.056 40.981 ;
     RECT  137.4 40.549 140.04 40.981 ;
     RECT  142.704 39.011 143.112 40.981 ;
     RECT  144.48 40.693 144.504 40.981 ;
     RECT  147.984 40.453 148.968 40.981 ;
     RECT  150.96 40.933 150.984 40.981 ;
     RECT  152.448 40.933 152.472 40.981 ;
     RECT  153.6 39.733 154.056 40.981 ;
     RECT  80.88 40.981 83.712 41.029 ;
     RECT  88.32 40.981 89.352 41.029 ;
     RECT  90.336 40.453 90.36 41.029 ;
     RECT  122.64 40.981 122.664 41.029 ;
     RECT  124.128 40.981 128.088 41.029 ;
     RECT  162.864 40.453 162.888 41.029 ;
     RECT  2.4 39.971 2.712 41.049 ;
     RECT  54.048 40.981 58.056 41.049 ;
     RECT  115.68 40.981 121.512 41.049 ;
     RECT  2.4 41.049 2.616 41.063 ;
     RECT  10.32 40.981 16.296 41.063 ;
     RECT  65.472 40.981 67.992 41.063 ;
     RECT  72.6 40.981 74.952 41.063 ;
     RECT  92.304 40.981 96.792 41.063 ;
     RECT  104.736 40.981 105.312 41.063 ;
     RECT  110.4 40.981 113.688 41.063 ;
     RECT  115.68 41.049 121.32 41.063 ;
     RECT  122.64 41.029 128.088 41.063 ;
     RECT  157.92 40.405 159.912 41.063 ;
     RECT  5.856 40.357 5.88 41.557 ;
     RECT  18.288 40.933 20.808 41.557 ;
     RECT  26.736 40.981 31.704 41.557 ;
     RECT  32.688 40.981 33.192 41.557 ;
     RECT  88.32 41.029 90.36 41.557 ;
     RECT  99.6 40.981 101.784 41.557 ;
     RECT  107.712 40.981 109.224 41.557 ;
     RECT  127.104 41.063 128.088 41.557 ;
     RECT  129.072 40.981 130.584 41.557 ;
     RECT  142.512 40.981 144.504 41.557 ;
     RECT  156.432 40.453 156.456 41.557 ;
     RECT  157.92 41.063 158.904 41.557 ;
     RECT  61.008 39.157 62.112 41.605 ;
     RECT  107.712 41.557 109.704 41.605 ;
     RECT  135.024 40.981 141.048 41.605 ;
     RECT  160.896 41.557 160.92 41.605 ;
     RECT  162.864 41.029 163.368 41.605 ;
     RECT  160.896 41.605 161.4 41.701 ;
     RECT  162.384 41.605 163.368 41.701 ;
     RECT  7.344 40.981 9.336 42.133 ;
     RECT  10.32 41.063 12.84 42.133 ;
     RECT  13.824 41.063 16.296 42.133 ;
     RECT  22.272 40.981 25.752 42.133 ;
     RECT  26.736 41.557 33.192 42.133 ;
     RECT  34.176 40.453 35.688 42.133 ;
     RECT  36.672 40.981 40.68 42.133 ;
     RECT  42.144 40.981 48.12 42.133 ;
     RECT  49.104 40.549 51.576 42.133 ;
     RECT  52.56 40.981 52.584 42.133 ;
     RECT  59.04 40.981 59.544 42.133 ;
     RECT  61.008 41.605 62.52 42.133 ;
     RECT  63.504 40.453 63.528 42.133 ;
     RECT  65.472 41.063 66.504 42.133 ;
     RECT  67.968 41.063 67.992 42.133 ;
     RECT  68.976 40.981 71.448 42.133 ;
     RECT  72.912 41.063 74.952 42.133 ;
     RECT  75.936 40.981 78.936 42.133 ;
     RECT  80.88 41.029 83.88 42.133 ;
     RECT  84.864 40.981 86.376 42.133 ;
     RECT  88.32 41.557 90.84 42.133 ;
     RECT  92.304 41.063 93.816 42.133 ;
     RECT  94.8 41.063 96.792 42.133 ;
     RECT  97.776 40.789 98.28 42.133 ;
     RECT  99.264 41.557 101.784 42.133 ;
     RECT  102.768 40.981 103.272 42.133 ;
     RECT  105.744 41.605 105.768 42.133 ;
     RECT  107.232 41.605 109.704 42.133 ;
     RECT  110.784 41.063 113.688 42.133 ;
     RECT  115.68 41.063 121.176 42.133 ;
     RECT  134.544 41.605 141.528 42.133 ;
     RECT  142.512 41.557 144.984 42.133 ;
     RECT  146.448 40.981 148.968 42.133 ;
     RECT  150.432 40.981 155.448 42.133 ;
     RECT  156.432 41.557 158.904 42.133 ;
     RECT  159.888 41.063 159.912 42.133 ;
     RECT  160.896 41.701 163.368 42.133 ;
     RECT  99.264 42.133 103.752 42.181 ;
     RECT  104.736 41.063 104.76 42.181 ;
     RECT  115.68 42.133 121.656 42.181 ;
     RECT  122.64 41.063 126.12 42.181 ;
     RECT  146.448 42.133 158.904 42.181 ;
     RECT  159.888 42.133 163.368 42.181 ;
     RECT  18.288 41.557 21.288 42.757 ;
     RECT  22.272 42.133 40.68 42.757 ;
     RECT  6.864 42.133 16.296 42.805 ;
     RECT  17.28 40.981 17.304 42.805 ;
     RECT  4.848 41.557 5.88 43.045 ;
     RECT  6.864 42.805 17.304 43.045 ;
     RECT  18.288 42.757 40.68 43.045 ;
     RECT  42.144 42.133 53.064 43.045 ;
     RECT  54.048 41.049 56.568 43.045 ;
     RECT  57.552 41.049 58.056 43.045 ;
     RECT  59.04 42.133 62.52 43.045 ;
     RECT  63.504 42.133 66.984 43.045 ;
     RECT  67.968 42.133 98.28 43.045 ;
     RECT  99.264 42.181 104.76 43.045 ;
     RECT  105.744 42.133 113.688 43.045 ;
     RECT  114.672 42.133 114.696 43.045 ;
     RECT  115.68 42.181 126.12 43.045 ;
     RECT  127.104 41.557 130.584 43.045 ;
     RECT  131.568 40.981 133.56 43.045 ;
     RECT  134.544 42.133 144.984 43.045 ;
     RECT  146.448 42.181 163.368 43.045 ;
     RECT  1.392 42.133 1.416 43.152 ;
     RECT  2.592 41.063 2.616 43.152 ;
     RECT  4.848 43.045 163.368 43.152 ;
  END
END ot_s81_mx4_mcol
END LIBRARY
